VERSION 5.8 ;
BUSBITCHARS "[]" ;
DIVIDERCHAR "/" ;
UNITS
    DATABASE MICRONS 1000 ;
END UNITS

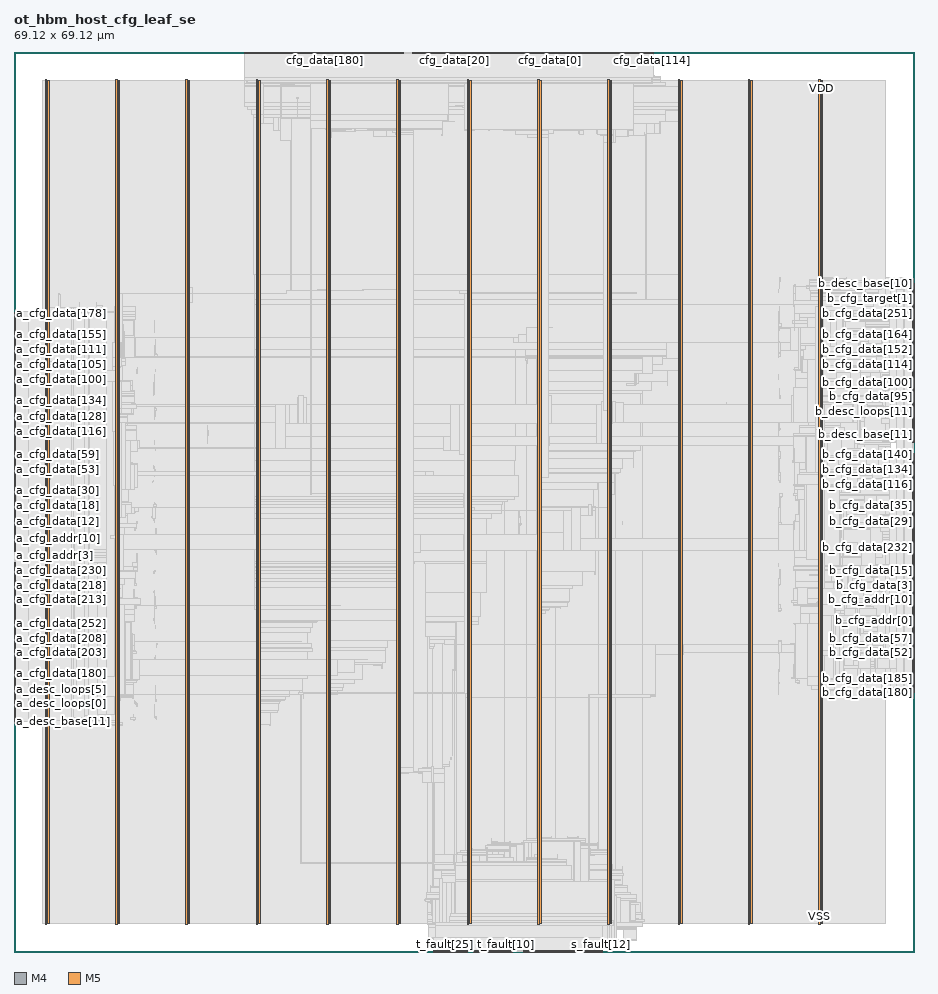
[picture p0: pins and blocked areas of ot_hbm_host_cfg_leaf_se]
MACRO ot_hbm_host_cfg_leaf_se
  FOREIGN ot_hbm_host_cfg_leaf_se 0 0 ;
  CLASS BLOCK ;
  SIZE 69.12 BY 69.12 ;
  PIN a_cfg_addr[0]
    DIRECTION OUTPUT ;
    USE SIGNAL ;
    PORT
      LAYER M4 ;
        RECT  0 30.768 0.084 30.792 ;
    END
  END a_cfg_addr[0]
  PIN a_cfg_addr[10]
    DIRECTION OUTPUT ;
    USE SIGNAL ;
    PORT
      LAYER M4 ;
        RECT  0 31.728 0.084 31.752 ;
    END
  END a_cfg_addr[10]
  PIN a_cfg_addr[11]
    DIRECTION OUTPUT ;
    USE SIGNAL ;
    PORT
      LAYER M4 ;
        RECT  0 31.824 0.084 31.848 ;
    END
  END a_cfg_addr[11]
  PIN a_cfg_addr[1]
    DIRECTION OUTPUT ;
    USE SIGNAL ;
    PORT
      LAYER M4 ;
        RECT  0 30.864 0.084 30.888 ;
    END
  END a_cfg_addr[1]
  PIN a_cfg_addr[2]
    DIRECTION OUTPUT ;
    USE SIGNAL ;
    PORT
      LAYER M4 ;
        RECT  0 30.96 0.084 30.984 ;
    END
  END a_cfg_addr[2]
  PIN a_cfg_addr[3]
    DIRECTION OUTPUT ;
    USE SIGNAL ;
    PORT
      LAYER M4 ;
        RECT  0 31.056 0.084 31.08 ;
    END
  END a_cfg_addr[3]
  PIN a_cfg_addr[4]
    DIRECTION OUTPUT ;
    USE SIGNAL ;
    PORT
      LAYER M4 ;
        RECT  0 31.152 0.084 31.176 ;
    END
  END a_cfg_addr[4]
  PIN a_cfg_addr[5]
    DIRECTION OUTPUT ;
    USE SIGNAL ;
    PORT
      LAYER M4 ;
        RECT  0 31.248 0.084 31.272 ;
    END
  END a_cfg_addr[5]
  PIN a_cfg_addr[6]
    DIRECTION OUTPUT ;
    USE SIGNAL ;
    PORT
      LAYER M4 ;
        RECT  0 31.344 0.084 31.368 ;
    END
  END a_cfg_addr[6]
  PIN a_cfg_addr[7]
    DIRECTION OUTPUT ;
    USE SIGNAL ;
    PORT
      LAYER M4 ;
        RECT  0 31.44 0.084 31.464 ;
    END
  END a_cfg_addr[7]
  PIN a_cfg_addr[8]
    DIRECTION OUTPUT ;
    USE SIGNAL ;
    PORT
      LAYER M4 ;
        RECT  0 31.536 0.084 31.56 ;
    END
  END a_cfg_addr[8]
  PIN a_cfg_addr[9]
    DIRECTION OUTPUT ;
    USE SIGNAL ;
    PORT
      LAYER M4 ;
        RECT  0 31.632 0.084 31.656 ;
    END
  END a_cfg_addr[9]
  PIN a_cfg_data[0]
    DIRECTION OUTPUT ;
    USE SIGNAL ;
    PORT
      LAYER M4 ;
        RECT  0 31.92 0.084 31.944 ;
    END
  END a_cfg_data[0]
  PIN a_cfg_data[100]
    DIRECTION OUTPUT ;
    USE SIGNAL ;
    PORT
      LAYER M4 ;
        RECT  0 44.592 0.084 44.616 ;
    END
  END a_cfg_data[100]
  PIN a_cfg_data[101]
    DIRECTION OUTPUT ;
    USE SIGNAL ;
    PORT
      LAYER M4 ;
        RECT  0 44.688 0.084 44.712 ;
    END
  END a_cfg_data[101]
  PIN a_cfg_data[102]
    DIRECTION OUTPUT ;
    USE SIGNAL ;
    PORT
      LAYER M4 ;
        RECT  0 44.784 0.084 44.808 ;
    END
  END a_cfg_data[102]
  PIN a_cfg_data[103]
    DIRECTION OUTPUT ;
    USE SIGNAL ;
    PORT
      LAYER M4 ;
        RECT  0 44.88 0.084 44.904 ;
    END
  END a_cfg_data[103]
  PIN a_cfg_data[104]
    DIRECTION OUTPUT ;
    USE SIGNAL ;
    PORT
      LAYER M4 ;
        RECT  0 44.976 0.084 45 ;
    END
  END a_cfg_data[104]
  PIN a_cfg_data[105]
    DIRECTION OUTPUT ;
    USE SIGNAL ;
    PORT
      LAYER M4 ;
        RECT  0 45.072 0.084 45.096 ;
    END
  END a_cfg_data[105]
  PIN a_cfg_data[106]
    DIRECTION OUTPUT ;
    USE SIGNAL ;
    PORT
      LAYER M4 ;
        RECT  0 45.168 0.084 45.192 ;
    END
  END a_cfg_data[106]
  PIN a_cfg_data[107]
    DIRECTION OUTPUT ;
    USE SIGNAL ;
    PORT
      LAYER M4 ;
        RECT  0 45.264 0.084 45.288 ;
    END
  END a_cfg_data[107]
  PIN a_cfg_data[108]
    DIRECTION OUTPUT ;
    USE SIGNAL ;
    PORT
      LAYER M4 ;
        RECT  0 45.36 0.084 45.384 ;
    END
  END a_cfg_data[108]
  PIN a_cfg_data[109]
    DIRECTION OUTPUT ;
    USE SIGNAL ;
    PORT
      LAYER M4 ;
        RECT  0 45.456 0.084 45.48 ;
    END
  END a_cfg_data[109]
  PIN a_cfg_data[10]
    DIRECTION OUTPUT ;
    USE SIGNAL ;
    PORT
      LAYER M4 ;
        RECT  0 32.88 0.084 32.904 ;
    END
  END a_cfg_data[10]
  PIN a_cfg_data[110]
    DIRECTION OUTPUT ;
    USE SIGNAL ;
    PORT
      LAYER M4 ;
        RECT  0 45.552 0.084 45.576 ;
    END
  END a_cfg_data[110]
  PIN a_cfg_data[111]
    DIRECTION OUTPUT ;
    USE SIGNAL ;
    PORT
      LAYER M4 ;
        RECT  0 45.648 0.084 45.672 ;
    END
  END a_cfg_data[111]
  PIN a_cfg_data[112]
    DIRECTION OUTPUT ;
    USE SIGNAL ;
    PORT
      LAYER M4 ;
        RECT  0 45.744 0.084 45.768 ;
    END
  END a_cfg_data[112]
  PIN a_cfg_data[113]
    DIRECTION OUTPUT ;
    USE SIGNAL ;
    PORT
      LAYER M4 ;
        RECT  0 45.84 0.084 45.864 ;
    END
  END a_cfg_data[113]
  PIN a_cfg_data[114]
    DIRECTION OUTPUT ;
    USE SIGNAL ;
    PORT
      LAYER M4 ;
        RECT  0 45.936 0.084 45.96 ;
    END
  END a_cfg_data[114]
  PIN a_cfg_data[115]
    DIRECTION OUTPUT ;
    USE SIGNAL ;
    PORT
      LAYER M4 ;
        RECT  0 46.032 0.084 46.056 ;
    END
  END a_cfg_data[115]
  PIN a_cfg_data[116]
    DIRECTION OUTPUT ;
    USE SIGNAL ;
    PORT
      LAYER M4 ;
        RECT  0 39.984 0.084 40.008 ;
    END
  END a_cfg_data[116]
  PIN a_cfg_data[117]
    DIRECTION OUTPUT ;
    USE SIGNAL ;
    PORT
      LAYER M4 ;
        RECT  0 40.08 0.084 40.104 ;
    END
  END a_cfg_data[117]
  PIN a_cfg_data[118]
    DIRECTION OUTPUT ;
    USE SIGNAL ;
    PORT
      LAYER M4 ;
        RECT  0 40.176 0.084 40.2 ;
    END
  END a_cfg_data[118]
  PIN a_cfg_data[119]
    DIRECTION OUTPUT ;
    USE SIGNAL ;
    PORT
      LAYER M4 ;
        RECT  0 40.272 0.084 40.296 ;
    END
  END a_cfg_data[119]
  PIN a_cfg_data[11]
    DIRECTION OUTPUT ;
    USE SIGNAL ;
    PORT
      LAYER M4 ;
        RECT  0 32.976 0.084 33 ;
    END
  END a_cfg_data[11]
  PIN a_cfg_data[120]
    DIRECTION OUTPUT ;
    USE SIGNAL ;
    PORT
      LAYER M4 ;
        RECT  0 40.368 0.084 40.392 ;
    END
  END a_cfg_data[120]
  PIN a_cfg_data[121]
    DIRECTION OUTPUT ;
    USE SIGNAL ;
    PORT
      LAYER M4 ;
        RECT  0 40.464 0.084 40.488 ;
    END
  END a_cfg_data[121]
  PIN a_cfg_data[122]
    DIRECTION OUTPUT ;
    USE SIGNAL ;
    PORT
      LAYER M4 ;
        RECT  0 40.56 0.084 40.584 ;
    END
  END a_cfg_data[122]
  PIN a_cfg_data[123]
    DIRECTION OUTPUT ;
    USE SIGNAL ;
    PORT
      LAYER M4 ;
        RECT  0 40.656 0.084 40.68 ;
    END
  END a_cfg_data[123]
  PIN a_cfg_data[124]
    DIRECTION OUTPUT ;
    USE SIGNAL ;
    PORT
      LAYER M4 ;
        RECT  0 40.752 0.084 40.776 ;
    END
  END a_cfg_data[124]
  PIN a_cfg_data[125]
    DIRECTION OUTPUT ;
    USE SIGNAL ;
    PORT
      LAYER M4 ;
        RECT  0 40.848 0.084 40.872 ;
    END
  END a_cfg_data[125]
  PIN a_cfg_data[126]
    DIRECTION OUTPUT ;
    USE SIGNAL ;
    PORT
      LAYER M4 ;
        RECT  0 40.944 0.084 40.968 ;
    END
  END a_cfg_data[126]
  PIN a_cfg_data[127]
    DIRECTION OUTPUT ;
    USE SIGNAL ;
    PORT
      LAYER M4 ;
        RECT  0 41.04 0.084 41.064 ;
    END
  END a_cfg_data[127]
  PIN a_cfg_data[128]
    DIRECTION OUTPUT ;
    USE SIGNAL ;
    PORT
      LAYER M4 ;
        RECT  0 41.136 0.084 41.16 ;
    END
  END a_cfg_data[128]
  PIN a_cfg_data[129]
    DIRECTION OUTPUT ;
    USE SIGNAL ;
    PORT
      LAYER M4 ;
        RECT  0 41.232 0.084 41.256 ;
    END
  END a_cfg_data[129]
  PIN a_cfg_data[12]
    DIRECTION OUTPUT ;
    USE SIGNAL ;
    PORT
      LAYER M4 ;
        RECT  0 33.072 0.084 33.096 ;
    END
  END a_cfg_data[12]
  PIN a_cfg_data[130]
    DIRECTION OUTPUT ;
    USE SIGNAL ;
    PORT
      LAYER M4 ;
        RECT  0 41.328 0.084 41.352 ;
    END
  END a_cfg_data[130]
  PIN a_cfg_data[131]
    DIRECTION OUTPUT ;
    USE SIGNAL ;
    PORT
      LAYER M4 ;
        RECT  0 41.424 0.084 41.448 ;
    END
  END a_cfg_data[131]
  PIN a_cfg_data[132]
    DIRECTION OUTPUT ;
    USE SIGNAL ;
    PORT
      LAYER M4 ;
        RECT  0 41.52 0.084 41.544 ;
    END
  END a_cfg_data[132]
  PIN a_cfg_data[133]
    DIRECTION OUTPUT ;
    USE SIGNAL ;
    PORT
      LAYER M4 ;
        RECT  0 41.616 0.084 41.64 ;
    END
  END a_cfg_data[133]
  PIN a_cfg_data[134]
    DIRECTION OUTPUT ;
    USE SIGNAL ;
    PORT
      LAYER M4 ;
        RECT  0 41.712 0.084 41.736 ;
    END
  END a_cfg_data[134]
  PIN a_cfg_data[135]
    DIRECTION OUTPUT ;
    USE SIGNAL ;
    PORT
      LAYER M4 ;
        RECT  0 41.808 0.084 41.832 ;
    END
  END a_cfg_data[135]
  PIN a_cfg_data[136]
    DIRECTION OUTPUT ;
    USE SIGNAL ;
    PORT
      LAYER M4 ;
        RECT  0 41.904 0.084 41.928 ;
    END
  END a_cfg_data[136]
  PIN a_cfg_data[137]
    DIRECTION OUTPUT ;
    USE SIGNAL ;
    PORT
      LAYER M4 ;
        RECT  0 42 0.084 42.024 ;
    END
  END a_cfg_data[137]
  PIN a_cfg_data[138]
    DIRECTION OUTPUT ;
    USE SIGNAL ;
    PORT
      LAYER M4 ;
        RECT  0 42.096 0.084 42.12 ;
    END
  END a_cfg_data[138]
  PIN a_cfg_data[139]
    DIRECTION OUTPUT ;
    USE SIGNAL ;
    PORT
      LAYER M4 ;
        RECT  0 42.192 0.084 42.216 ;
    END
  END a_cfg_data[139]
  PIN a_cfg_data[13]
    DIRECTION OUTPUT ;
    USE SIGNAL ;
    PORT
      LAYER M4 ;
        RECT  0 33.168 0.084 33.192 ;
    END
  END a_cfg_data[13]
  PIN a_cfg_data[140]
    DIRECTION OUTPUT ;
    USE SIGNAL ;
    PORT
      LAYER M4 ;
        RECT  0 42.288 0.084 42.312 ;
    END
  END a_cfg_data[140]
  PIN a_cfg_data[141]
    DIRECTION OUTPUT ;
    USE SIGNAL ;
    PORT
      LAYER M4 ;
        RECT  0 42.384 0.084 42.408 ;
    END
  END a_cfg_data[141]
  PIN a_cfg_data[142]
    DIRECTION OUTPUT ;
    USE SIGNAL ;
    PORT
      LAYER M4 ;
        RECT  0 42.48 0.084 42.504 ;
    END
  END a_cfg_data[142]
  PIN a_cfg_data[143]
    DIRECTION OUTPUT ;
    USE SIGNAL ;
    PORT
      LAYER M4 ;
        RECT  0 42.576 0.084 42.6 ;
    END
  END a_cfg_data[143]
  PIN a_cfg_data[144]
    DIRECTION OUTPUT ;
    USE SIGNAL ;
    PORT
      LAYER M4 ;
        RECT  0 42.672 0.084 42.696 ;
    END
  END a_cfg_data[144]
  PIN a_cfg_data[145]
    DIRECTION OUTPUT ;
    USE SIGNAL ;
    PORT
      LAYER M4 ;
        RECT  0 42.768 0.084 42.792 ;
    END
  END a_cfg_data[145]
  PIN a_cfg_data[146]
    DIRECTION OUTPUT ;
    USE SIGNAL ;
    PORT
      LAYER M4 ;
        RECT  0 42.864 0.084 42.888 ;
    END
  END a_cfg_data[146]
  PIN a_cfg_data[147]
    DIRECTION OUTPUT ;
    USE SIGNAL ;
    PORT
      LAYER M4 ;
        RECT  0 42.96 0.084 42.984 ;
    END
  END a_cfg_data[147]
  PIN a_cfg_data[148]
    DIRECTION OUTPUT ;
    USE SIGNAL ;
    PORT
      LAYER M4 ;
        RECT  0 46.128 0.084 46.152 ;
    END
  END a_cfg_data[148]
  PIN a_cfg_data[149]
    DIRECTION OUTPUT ;
    USE SIGNAL ;
    PORT
      LAYER M4 ;
        RECT  0 46.224 0.084 46.248 ;
    END
  END a_cfg_data[149]
  PIN a_cfg_data[14]
    DIRECTION OUTPUT ;
    USE SIGNAL ;
    PORT
      LAYER M4 ;
        RECT  0 33.264 0.084 33.288 ;
    END
  END a_cfg_data[14]
  PIN a_cfg_data[150]
    DIRECTION OUTPUT ;
    USE SIGNAL ;
    PORT
      LAYER M4 ;
        RECT  0 46.32 0.084 46.344 ;
    END
  END a_cfg_data[150]
  PIN a_cfg_data[151]
    DIRECTION OUTPUT ;
    USE SIGNAL ;
    PORT
      LAYER M4 ;
        RECT  0 46.416 0.084 46.44 ;
    END
  END a_cfg_data[151]
  PIN a_cfg_data[152]
    DIRECTION OUTPUT ;
    USE SIGNAL ;
    PORT
      LAYER M4 ;
        RECT  0 46.512 0.084 46.536 ;
    END
  END a_cfg_data[152]
  PIN a_cfg_data[153]
    DIRECTION OUTPUT ;
    USE SIGNAL ;
    PORT
      LAYER M4 ;
        RECT  0 46.608 0.084 46.632 ;
    END
  END a_cfg_data[153]
  PIN a_cfg_data[154]
    DIRECTION OUTPUT ;
    USE SIGNAL ;
    PORT
      LAYER M4 ;
        RECT  0 46.704 0.084 46.728 ;
    END
  END a_cfg_data[154]
  PIN a_cfg_data[155]
    DIRECTION OUTPUT ;
    USE SIGNAL ;
    PORT
      LAYER M4 ;
        RECT  0 46.8 0.084 46.824 ;
    END
  END a_cfg_data[155]
  PIN a_cfg_data[156]
    DIRECTION OUTPUT ;
    USE SIGNAL ;
    PORT
      LAYER M4 ;
        RECT  0 46.896 0.084 46.92 ;
    END
  END a_cfg_data[156]
  PIN a_cfg_data[157]
    DIRECTION OUTPUT ;
    USE SIGNAL ;
    PORT
      LAYER M4 ;
        RECT  0 46.992 0.084 47.016 ;
    END
  END a_cfg_data[157]
  PIN a_cfg_data[158]
    DIRECTION OUTPUT ;
    USE SIGNAL ;
    PORT
      LAYER M4 ;
        RECT  0 47.088 0.084 47.112 ;
    END
  END a_cfg_data[158]
  PIN a_cfg_data[159]
    DIRECTION OUTPUT ;
    USE SIGNAL ;
    PORT
      LAYER M4 ;
        RECT  0 47.184 0.084 47.208 ;
    END
  END a_cfg_data[159]
  PIN a_cfg_data[15]
    DIRECTION OUTPUT ;
    USE SIGNAL ;
    PORT
      LAYER M4 ;
        RECT  0 33.36 0.084 33.384 ;
    END
  END a_cfg_data[15]
  PIN a_cfg_data[160]
    DIRECTION OUTPUT ;
    USE SIGNAL ;
    PORT
      LAYER M4 ;
        RECT  0 47.28 0.084 47.304 ;
    END
  END a_cfg_data[160]
  PIN a_cfg_data[161]
    DIRECTION OUTPUT ;
    USE SIGNAL ;
    PORT
      LAYER M4 ;
        RECT  0 47.376 0.084 47.4 ;
    END
  END a_cfg_data[161]
  PIN a_cfg_data[162]
    DIRECTION OUTPUT ;
    USE SIGNAL ;
    PORT
      LAYER M4 ;
        RECT  0 47.472 0.084 47.496 ;
    END
  END a_cfg_data[162]
  PIN a_cfg_data[163]
    DIRECTION OUTPUT ;
    USE SIGNAL ;
    PORT
      LAYER M4 ;
        RECT  0 47.568 0.084 47.592 ;
    END
  END a_cfg_data[163]
  PIN a_cfg_data[164]
    DIRECTION OUTPUT ;
    USE SIGNAL ;
    PORT
      LAYER M4 ;
        RECT  0 47.664 0.084 47.688 ;
    END
  END a_cfg_data[164]
  PIN a_cfg_data[165]
    DIRECTION OUTPUT ;
    USE SIGNAL ;
    PORT
      LAYER M4 ;
        RECT  0 47.76 0.084 47.784 ;
    END
  END a_cfg_data[165]
  PIN a_cfg_data[166]
    DIRECTION OUTPUT ;
    USE SIGNAL ;
    PORT
      LAYER M4 ;
        RECT  0 47.856 0.084 47.88 ;
    END
  END a_cfg_data[166]
  PIN a_cfg_data[167]
    DIRECTION OUTPUT ;
    USE SIGNAL ;
    PORT
      LAYER M4 ;
        RECT  0 47.952 0.084 47.976 ;
    END
  END a_cfg_data[167]
  PIN a_cfg_data[168]
    DIRECTION OUTPUT ;
    USE SIGNAL ;
    PORT
      LAYER M4 ;
        RECT  0 48.048 0.084 48.072 ;
    END
  END a_cfg_data[168]
  PIN a_cfg_data[169]
    DIRECTION OUTPUT ;
    USE SIGNAL ;
    PORT
      LAYER M4 ;
        RECT  0 48.144 0.084 48.168 ;
    END
  END a_cfg_data[169]
  PIN a_cfg_data[16]
    DIRECTION OUTPUT ;
    USE SIGNAL ;
    PORT
      LAYER M4 ;
        RECT  0 33.456 0.084 33.48 ;
    END
  END a_cfg_data[16]
  PIN a_cfg_data[170]
    DIRECTION OUTPUT ;
    USE SIGNAL ;
    PORT
      LAYER M4 ;
        RECT  0 48.24 0.084 48.264 ;
    END
  END a_cfg_data[170]
  PIN a_cfg_data[171]
    DIRECTION OUTPUT ;
    USE SIGNAL ;
    PORT
      LAYER M4 ;
        RECT  0 48.336 0.084 48.36 ;
    END
  END a_cfg_data[171]
  PIN a_cfg_data[172]
    DIRECTION OUTPUT ;
    USE SIGNAL ;
    PORT
      LAYER M4 ;
        RECT  0 48.432 0.084 48.456 ;
    END
  END a_cfg_data[172]
  PIN a_cfg_data[173]
    DIRECTION OUTPUT ;
    USE SIGNAL ;
    PORT
      LAYER M4 ;
        RECT  0 48.528 0.084 48.552 ;
    END
  END a_cfg_data[173]
  PIN a_cfg_data[174]
    DIRECTION OUTPUT ;
    USE SIGNAL ;
    PORT
      LAYER M4 ;
        RECT  0 48.624 0.084 48.648 ;
    END
  END a_cfg_data[174]
  PIN a_cfg_data[175]
    DIRECTION OUTPUT ;
    USE SIGNAL ;
    PORT
      LAYER M4 ;
        RECT  0 48.72 0.084 48.744 ;
    END
  END a_cfg_data[175]
  PIN a_cfg_data[176]
    DIRECTION OUTPUT ;
    USE SIGNAL ;
    PORT
      LAYER M4 ;
        RECT  0 48.816 0.084 48.84 ;
    END
  END a_cfg_data[176]
  PIN a_cfg_data[177]
    DIRECTION OUTPUT ;
    USE SIGNAL ;
    PORT
      LAYER M4 ;
        RECT  0 48.912 0.084 48.936 ;
    END
  END a_cfg_data[177]
  PIN a_cfg_data[178]
    DIRECTION OUTPUT ;
    USE SIGNAL ;
    PORT
      LAYER M4 ;
        RECT  0 49.008 0.084 49.032 ;
    END
  END a_cfg_data[178]
  PIN a_cfg_data[179]
    DIRECTION OUTPUT ;
    USE SIGNAL ;
    PORT
      LAYER M4 ;
        RECT  0 49.104 0.084 49.128 ;
    END
  END a_cfg_data[179]
  PIN a_cfg_data[17]
    DIRECTION OUTPUT ;
    USE SIGNAL ;
    PORT
      LAYER M4 ;
        RECT  0 33.552 0.084 33.576 ;
    END
  END a_cfg_data[17]
  PIN a_cfg_data[180]
    DIRECTION OUTPUT ;
    USE SIGNAL ;
    PORT
      LAYER M4 ;
        RECT  0 20.784 0.084 20.808 ;
    END
  END a_cfg_data[180]
  PIN a_cfg_data[181]
    DIRECTION OUTPUT ;
    USE SIGNAL ;
    PORT
      LAYER M4 ;
        RECT  0 20.88 0.084 20.904 ;
    END
  END a_cfg_data[181]
  PIN a_cfg_data[182]
    DIRECTION OUTPUT ;
    USE SIGNAL ;
    PORT
      LAYER M4 ;
        RECT  0 20.976 0.084 21 ;
    END
  END a_cfg_data[182]
  PIN a_cfg_data[183]
    DIRECTION OUTPUT ;
    USE SIGNAL ;
    PORT
      LAYER M4 ;
        RECT  0 21.072 0.084 21.096 ;
    END
  END a_cfg_data[183]
  PIN a_cfg_data[184]
    DIRECTION OUTPUT ;
    USE SIGNAL ;
    PORT
      LAYER M4 ;
        RECT  0 21.168 0.084 21.192 ;
    END
  END a_cfg_data[184]
  PIN a_cfg_data[185]
    DIRECTION OUTPUT ;
    USE SIGNAL ;
    PORT
      LAYER M4 ;
        RECT  0 21.264 0.084 21.288 ;
    END
  END a_cfg_data[185]
  PIN a_cfg_data[186]
    DIRECTION OUTPUT ;
    USE SIGNAL ;
    PORT
      LAYER M4 ;
        RECT  0 21.36 0.084 21.384 ;
    END
  END a_cfg_data[186]
  PIN a_cfg_data[187]
    DIRECTION OUTPUT ;
    USE SIGNAL ;
    PORT
      LAYER M4 ;
        RECT  0 21.456 0.084 21.48 ;
    END
  END a_cfg_data[187]
  PIN a_cfg_data[188]
    DIRECTION OUTPUT ;
    USE SIGNAL ;
    PORT
      LAYER M4 ;
        RECT  0 21.552 0.084 21.576 ;
    END
  END a_cfg_data[188]
  PIN a_cfg_data[189]
    DIRECTION OUTPUT ;
    USE SIGNAL ;
    PORT
      LAYER M4 ;
        RECT  0 21.648 0.084 21.672 ;
    END
  END a_cfg_data[189]
  PIN a_cfg_data[18]
    DIRECTION OUTPUT ;
    USE SIGNAL ;
    PORT
      LAYER M4 ;
        RECT  0 33.648 0.084 33.672 ;
    END
  END a_cfg_data[18]
  PIN a_cfg_data[190]
    DIRECTION OUTPUT ;
    USE SIGNAL ;
    PORT
      LAYER M4 ;
        RECT  0 21.744 0.084 21.768 ;
    END
  END a_cfg_data[190]
  PIN a_cfg_data[191]
    DIRECTION OUTPUT ;
    USE SIGNAL ;
    PORT
      LAYER M4 ;
        RECT  0 21.84 0.084 21.864 ;
    END
  END a_cfg_data[191]
  PIN a_cfg_data[192]
    DIRECTION OUTPUT ;
    USE SIGNAL ;
    PORT
      LAYER M4 ;
        RECT  0 21.936 0.084 21.96 ;
    END
  END a_cfg_data[192]
  PIN a_cfg_data[193]
    DIRECTION OUTPUT ;
    USE SIGNAL ;
    PORT
      LAYER M4 ;
        RECT  0 22.032 0.084 22.056 ;
    END
  END a_cfg_data[193]
  PIN a_cfg_data[194]
    DIRECTION OUTPUT ;
    USE SIGNAL ;
    PORT
      LAYER M4 ;
        RECT  0 22.128 0.084 22.152 ;
    END
  END a_cfg_data[194]
  PIN a_cfg_data[195]
    DIRECTION OUTPUT ;
    USE SIGNAL ;
    PORT
      LAYER M4 ;
        RECT  0 22.224 0.084 22.248 ;
    END
  END a_cfg_data[195]
  PIN a_cfg_data[196]
    DIRECTION OUTPUT ;
    USE SIGNAL ;
    PORT
      LAYER M4 ;
        RECT  0 22.32 0.084 22.344 ;
    END
  END a_cfg_data[196]
  PIN a_cfg_data[197]
    DIRECTION OUTPUT ;
    USE SIGNAL ;
    PORT
      LAYER M4 ;
        RECT  0 22.416 0.084 22.44 ;
    END
  END a_cfg_data[197]
  PIN a_cfg_data[198]
    DIRECTION OUTPUT ;
    USE SIGNAL ;
    PORT
      LAYER M4 ;
        RECT  0 22.512 0.084 22.536 ;
    END
  END a_cfg_data[198]
  PIN a_cfg_data[199]
    DIRECTION OUTPUT ;
    USE SIGNAL ;
    PORT
      LAYER M4 ;
        RECT  0 22.608 0.084 22.632 ;
    END
  END a_cfg_data[199]
  PIN a_cfg_data[19]
    DIRECTION OUTPUT ;
    USE SIGNAL ;
    PORT
      LAYER M4 ;
        RECT  0 33.744 0.084 33.768 ;
    END
  END a_cfg_data[19]
  PIN a_cfg_data[1]
    DIRECTION OUTPUT ;
    USE SIGNAL ;
    PORT
      LAYER M4 ;
        RECT  0 32.016 0.084 32.04 ;
    END
  END a_cfg_data[1]
  PIN a_cfg_data[200]
    DIRECTION OUTPUT ;
    USE SIGNAL ;
    PORT
      LAYER M4 ;
        RECT  0 22.704 0.084 22.728 ;
    END
  END a_cfg_data[200]
  PIN a_cfg_data[201]
    DIRECTION OUTPUT ;
    USE SIGNAL ;
    PORT
      LAYER M4 ;
        RECT  0 22.8 0.084 22.824 ;
    END
  END a_cfg_data[201]
  PIN a_cfg_data[202]
    DIRECTION OUTPUT ;
    USE SIGNAL ;
    PORT
      LAYER M4 ;
        RECT  0 22.896 0.084 22.92 ;
    END
  END a_cfg_data[202]
  PIN a_cfg_data[203]
    DIRECTION OUTPUT ;
    USE SIGNAL ;
    PORT
      LAYER M4 ;
        RECT  0 22.992 0.084 23.016 ;
    END
  END a_cfg_data[203]
  PIN a_cfg_data[204]
    DIRECTION OUTPUT ;
    USE SIGNAL ;
    PORT
      LAYER M4 ;
        RECT  0 23.088 0.084 23.112 ;
    END
  END a_cfg_data[204]
  PIN a_cfg_data[205]
    DIRECTION OUTPUT ;
    USE SIGNAL ;
    PORT
      LAYER M4 ;
        RECT  0 23.184 0.084 23.208 ;
    END
  END a_cfg_data[205]
  PIN a_cfg_data[206]
    DIRECTION OUTPUT ;
    USE SIGNAL ;
    PORT
      LAYER M4 ;
        RECT  0 23.28 0.084 23.304 ;
    END
  END a_cfg_data[206]
  PIN a_cfg_data[207]
    DIRECTION OUTPUT ;
    USE SIGNAL ;
    PORT
      LAYER M4 ;
        RECT  0 23.376 0.084 23.4 ;
    END
  END a_cfg_data[207]
  PIN a_cfg_data[208]
    DIRECTION OUTPUT ;
    USE SIGNAL ;
    PORT
      LAYER M4 ;
        RECT  0 23.472 0.084 23.496 ;
    END
  END a_cfg_data[208]
  PIN a_cfg_data[209]
    DIRECTION OUTPUT ;
    USE SIGNAL ;
    PORT
      LAYER M4 ;
        RECT  0 23.568 0.084 23.592 ;
    END
  END a_cfg_data[209]
  PIN a_cfg_data[20]
    DIRECTION OUTPUT ;
    USE SIGNAL ;
    PORT
      LAYER M4 ;
        RECT  0 33.84 0.084 33.864 ;
    END
  END a_cfg_data[20]
  PIN a_cfg_data[210]
    DIRECTION OUTPUT ;
    USE SIGNAL ;
    PORT
      LAYER M4 ;
        RECT  0 23.664 0.084 23.688 ;
    END
  END a_cfg_data[210]
  PIN a_cfg_data[211]
    DIRECTION OUTPUT ;
    USE SIGNAL ;
    PORT
      LAYER M4 ;
        RECT  0 23.76 0.084 23.784 ;
    END
  END a_cfg_data[211]
  PIN a_cfg_data[212]
    DIRECTION OUTPUT ;
    USE SIGNAL ;
    PORT
      LAYER M4 ;
        RECT  0 26.928 0.084 26.952 ;
    END
  END a_cfg_data[212]
  PIN a_cfg_data[213]
    DIRECTION OUTPUT ;
    USE SIGNAL ;
    PORT
      LAYER M4 ;
        RECT  0 27.024 0.084 27.048 ;
    END
  END a_cfg_data[213]
  PIN a_cfg_data[214]
    DIRECTION OUTPUT ;
    USE SIGNAL ;
    PORT
      LAYER M4 ;
        RECT  0 27.12 0.084 27.144 ;
    END
  END a_cfg_data[214]
  PIN a_cfg_data[215]
    DIRECTION OUTPUT ;
    USE SIGNAL ;
    PORT
      LAYER M4 ;
        RECT  0 27.216 0.084 27.24 ;
    END
  END a_cfg_data[215]
  PIN a_cfg_data[216]
    DIRECTION OUTPUT ;
    USE SIGNAL ;
    PORT
      LAYER M4 ;
        RECT  0 27.312 0.084 27.336 ;
    END
  END a_cfg_data[216]
  PIN a_cfg_data[217]
    DIRECTION OUTPUT ;
    USE SIGNAL ;
    PORT
      LAYER M4 ;
        RECT  0 27.408 0.084 27.432 ;
    END
  END a_cfg_data[217]
  PIN a_cfg_data[218]
    DIRECTION OUTPUT ;
    USE SIGNAL ;
    PORT
      LAYER M4 ;
        RECT  0 27.504 0.084 27.528 ;
    END
  END a_cfg_data[218]
  PIN a_cfg_data[219]
    DIRECTION OUTPUT ;
    USE SIGNAL ;
    PORT
      LAYER M4 ;
        RECT  0 27.6 0.084 27.624 ;
    END
  END a_cfg_data[219]
  PIN a_cfg_data[21]
    DIRECTION OUTPUT ;
    USE SIGNAL ;
    PORT
      LAYER M4 ;
        RECT  0 33.936 0.084 33.96 ;
    END
  END a_cfg_data[21]
  PIN a_cfg_data[220]
    DIRECTION OUTPUT ;
    USE SIGNAL ;
    PORT
      LAYER M4 ;
        RECT  0 27.696 0.084 27.72 ;
    END
  END a_cfg_data[220]
  PIN a_cfg_data[221]
    DIRECTION OUTPUT ;
    USE SIGNAL ;
    PORT
      LAYER M4 ;
        RECT  0 27.792 0.084 27.816 ;
    END
  END a_cfg_data[221]
  PIN a_cfg_data[222]
    DIRECTION OUTPUT ;
    USE SIGNAL ;
    PORT
      LAYER M4 ;
        RECT  0 27.888 0.084 27.912 ;
    END
  END a_cfg_data[222]
  PIN a_cfg_data[223]
    DIRECTION OUTPUT ;
    USE SIGNAL ;
    PORT
      LAYER M4 ;
        RECT  0 27.984 0.084 28.008 ;
    END
  END a_cfg_data[223]
  PIN a_cfg_data[224]
    DIRECTION OUTPUT ;
    USE SIGNAL ;
    PORT
      LAYER M4 ;
        RECT  0 28.08 0.084 28.104 ;
    END
  END a_cfg_data[224]
  PIN a_cfg_data[225]
    DIRECTION OUTPUT ;
    USE SIGNAL ;
    PORT
      LAYER M4 ;
        RECT  0 28.176 0.084 28.2 ;
    END
  END a_cfg_data[225]
  PIN a_cfg_data[226]
    DIRECTION OUTPUT ;
    USE SIGNAL ;
    PORT
      LAYER M4 ;
        RECT  0 28.272 0.084 28.296 ;
    END
  END a_cfg_data[226]
  PIN a_cfg_data[227]
    DIRECTION OUTPUT ;
    USE SIGNAL ;
    PORT
      LAYER M4 ;
        RECT  0 28.368 0.084 28.392 ;
    END
  END a_cfg_data[227]
  PIN a_cfg_data[228]
    DIRECTION OUTPUT ;
    USE SIGNAL ;
    PORT
      LAYER M4 ;
        RECT  0 28.464 0.084 28.488 ;
    END
  END a_cfg_data[228]
  PIN a_cfg_data[229]
    DIRECTION OUTPUT ;
    USE SIGNAL ;
    PORT
      LAYER M4 ;
        RECT  0 28.56 0.084 28.584 ;
    END
  END a_cfg_data[229]
  PIN a_cfg_data[22]
    DIRECTION OUTPUT ;
    USE SIGNAL ;
    PORT
      LAYER M4 ;
        RECT  0 34.032 0.084 34.056 ;
    END
  END a_cfg_data[22]
  PIN a_cfg_data[230]
    DIRECTION OUTPUT ;
    USE SIGNAL ;
    PORT
      LAYER M4 ;
        RECT  0 28.656 0.084 28.68 ;
    END
  END a_cfg_data[230]
  PIN a_cfg_data[231]
    DIRECTION OUTPUT ;
    USE SIGNAL ;
    PORT
      LAYER M4 ;
        RECT  0 28.752 0.084 28.776 ;
    END
  END a_cfg_data[231]
  PIN a_cfg_data[232]
    DIRECTION OUTPUT ;
    USE SIGNAL ;
    PORT
      LAYER M4 ;
        RECT  0 28.848 0.084 28.872 ;
    END
  END a_cfg_data[232]
  PIN a_cfg_data[233]
    DIRECTION OUTPUT ;
    USE SIGNAL ;
    PORT
      LAYER M4 ;
        RECT  0 28.944 0.084 28.968 ;
    END
  END a_cfg_data[233]
  PIN a_cfg_data[234]
    DIRECTION OUTPUT ;
    USE SIGNAL ;
    PORT
      LAYER M4 ;
        RECT  0 29.04 0.084 29.064 ;
    END
  END a_cfg_data[234]
  PIN a_cfg_data[235]
    DIRECTION OUTPUT ;
    USE SIGNAL ;
    PORT
      LAYER M4 ;
        RECT  0 29.136 0.084 29.16 ;
    END
  END a_cfg_data[235]
  PIN a_cfg_data[236]
    DIRECTION OUTPUT ;
    USE SIGNAL ;
    PORT
      LAYER M4 ;
        RECT  0 29.232 0.084 29.256 ;
    END
  END a_cfg_data[236]
  PIN a_cfg_data[237]
    DIRECTION OUTPUT ;
    USE SIGNAL ;
    PORT
      LAYER M4 ;
        RECT  0 29.328 0.084 29.352 ;
    END
  END a_cfg_data[237]
  PIN a_cfg_data[238]
    DIRECTION OUTPUT ;
    USE SIGNAL ;
    PORT
      LAYER M4 ;
        RECT  0 29.424 0.084 29.448 ;
    END
  END a_cfg_data[238]
  PIN a_cfg_data[239]
    DIRECTION OUTPUT ;
    USE SIGNAL ;
    PORT
      LAYER M4 ;
        RECT  0 29.52 0.084 29.544 ;
    END
  END a_cfg_data[239]
  PIN a_cfg_data[23]
    DIRECTION OUTPUT ;
    USE SIGNAL ;
    PORT
      LAYER M4 ;
        RECT  0 34.128 0.084 34.152 ;
    END
  END a_cfg_data[23]
  PIN a_cfg_data[240]
    DIRECTION OUTPUT ;
    USE SIGNAL ;
    PORT
      LAYER M4 ;
        RECT  0 29.616 0.084 29.64 ;
    END
  END a_cfg_data[240]
  PIN a_cfg_data[241]
    DIRECTION OUTPUT ;
    USE SIGNAL ;
    PORT
      LAYER M4 ;
        RECT  0 29.712 0.084 29.736 ;
    END
  END a_cfg_data[241]
  PIN a_cfg_data[242]
    DIRECTION OUTPUT ;
    USE SIGNAL ;
    PORT
      LAYER M4 ;
        RECT  0 29.808 0.084 29.832 ;
    END
  END a_cfg_data[242]
  PIN a_cfg_data[243]
    DIRECTION OUTPUT ;
    USE SIGNAL ;
    PORT
      LAYER M4 ;
        RECT  0 29.904 0.084 29.928 ;
    END
  END a_cfg_data[243]
  PIN a_cfg_data[244]
    DIRECTION OUTPUT ;
    USE SIGNAL ;
    PORT
      LAYER M4 ;
        RECT  0 23.856 0.084 23.88 ;
    END
  END a_cfg_data[244]
  PIN a_cfg_data[245]
    DIRECTION OUTPUT ;
    USE SIGNAL ;
    PORT
      LAYER M4 ;
        RECT  0 23.952 0.084 23.976 ;
    END
  END a_cfg_data[245]
  PIN a_cfg_data[246]
    DIRECTION OUTPUT ;
    USE SIGNAL ;
    PORT
      LAYER M4 ;
        RECT  0 24.048 0.084 24.072 ;
    END
  END a_cfg_data[246]
  PIN a_cfg_data[247]
    DIRECTION OUTPUT ;
    USE SIGNAL ;
    PORT
      LAYER M4 ;
        RECT  0 24.144 0.084 24.168 ;
    END
  END a_cfg_data[247]
  PIN a_cfg_data[248]
    DIRECTION OUTPUT ;
    USE SIGNAL ;
    PORT
      LAYER M4 ;
        RECT  0 24.24 0.084 24.264 ;
    END
  END a_cfg_data[248]
  PIN a_cfg_data[249]
    DIRECTION OUTPUT ;
    USE SIGNAL ;
    PORT
      LAYER M4 ;
        RECT  0 24.336 0.084 24.36 ;
    END
  END a_cfg_data[249]
  PIN a_cfg_data[24]
    DIRECTION OUTPUT ;
    USE SIGNAL ;
    PORT
      LAYER M4 ;
        RECT  0 34.224 0.084 34.248 ;
    END
  END a_cfg_data[24]
  PIN a_cfg_data[250]
    DIRECTION OUTPUT ;
    USE SIGNAL ;
    PORT
      LAYER M4 ;
        RECT  0 24.432 0.084 24.456 ;
    END
  END a_cfg_data[250]
  PIN a_cfg_data[251]
    DIRECTION OUTPUT ;
    USE SIGNAL ;
    PORT
      LAYER M4 ;
        RECT  0 24.528 0.084 24.552 ;
    END
  END a_cfg_data[251]
  PIN a_cfg_data[252]
    DIRECTION OUTPUT ;
    USE SIGNAL ;
    PORT
      LAYER M4 ;
        RECT  0 24.624 0.084 24.648 ;
    END
  END a_cfg_data[252]
  PIN a_cfg_data[253]
    DIRECTION OUTPUT ;
    USE SIGNAL ;
    PORT
      LAYER M4 ;
        RECT  0 24.72 0.084 24.744 ;
    END
  END a_cfg_data[253]
  PIN a_cfg_data[254]
    DIRECTION OUTPUT ;
    USE SIGNAL ;
    PORT
      LAYER M4 ;
        RECT  0 24.816 0.084 24.84 ;
    END
  END a_cfg_data[254]
  PIN a_cfg_data[255]
    DIRECTION OUTPUT ;
    USE SIGNAL ;
    PORT
      LAYER M4 ;
        RECT  0 24.912 0.084 24.936 ;
    END
  END a_cfg_data[255]
  PIN a_cfg_data[25]
    DIRECTION OUTPUT ;
    USE SIGNAL ;
    PORT
      LAYER M4 ;
        RECT  0 34.32 0.084 34.344 ;
    END
  END a_cfg_data[25]
  PIN a_cfg_data[26]
    DIRECTION OUTPUT ;
    USE SIGNAL ;
    PORT
      LAYER M4 ;
        RECT  0 34.416 0.084 34.44 ;
    END
  END a_cfg_data[26]
  PIN a_cfg_data[27]
    DIRECTION OUTPUT ;
    USE SIGNAL ;
    PORT
      LAYER M4 ;
        RECT  0 34.512 0.084 34.536 ;
    END
  END a_cfg_data[27]
  PIN a_cfg_data[28]
    DIRECTION OUTPUT ;
    USE SIGNAL ;
    PORT
      LAYER M4 ;
        RECT  0 34.608 0.084 34.632 ;
    END
  END a_cfg_data[28]
  PIN a_cfg_data[29]
    DIRECTION OUTPUT ;
    USE SIGNAL ;
    PORT
      LAYER M4 ;
        RECT  0 34.704 0.084 34.728 ;
    END
  END a_cfg_data[29]
  PIN a_cfg_data[2]
    DIRECTION OUTPUT ;
    USE SIGNAL ;
    PORT
      LAYER M4 ;
        RECT  0 32.112 0.084 32.136 ;
    END
  END a_cfg_data[2]
  PIN a_cfg_data[30]
    DIRECTION OUTPUT ;
    USE SIGNAL ;
    PORT
      LAYER M4 ;
        RECT  0 34.8 0.084 34.824 ;
    END
  END a_cfg_data[30]
  PIN a_cfg_data[31]
    DIRECTION OUTPUT ;
    USE SIGNAL ;
    PORT
      LAYER M4 ;
        RECT  0 34.896 0.084 34.92 ;
    END
  END a_cfg_data[31]
  PIN a_cfg_data[32]
    DIRECTION OUTPUT ;
    USE SIGNAL ;
    PORT
      LAYER M4 ;
        RECT  0 34.992 0.084 35.016 ;
    END
  END a_cfg_data[32]
  PIN a_cfg_data[33]
    DIRECTION OUTPUT ;
    USE SIGNAL ;
    PORT
      LAYER M4 ;
        RECT  0 35.088 0.084 35.112 ;
    END
  END a_cfg_data[33]
  PIN a_cfg_data[34]
    DIRECTION OUTPUT ;
    USE SIGNAL ;
    PORT
      LAYER M4 ;
        RECT  0 35.184 0.084 35.208 ;
    END
  END a_cfg_data[34]
  PIN a_cfg_data[35]
    DIRECTION OUTPUT ;
    USE SIGNAL ;
    PORT
      LAYER M4 ;
        RECT  0 35.28 0.084 35.304 ;
    END
  END a_cfg_data[35]
  PIN a_cfg_data[36]
    DIRECTION OUTPUT ;
    USE SIGNAL ;
    PORT
      LAYER M4 ;
        RECT  0 35.376 0.084 35.4 ;
    END
  END a_cfg_data[36]
  PIN a_cfg_data[37]
    DIRECTION OUTPUT ;
    USE SIGNAL ;
    PORT
      LAYER M4 ;
        RECT  0 35.472 0.084 35.496 ;
    END
  END a_cfg_data[37]
  PIN a_cfg_data[38]
    DIRECTION OUTPUT ;
    USE SIGNAL ;
    PORT
      LAYER M4 ;
        RECT  0 35.568 0.084 35.592 ;
    END
  END a_cfg_data[38]
  PIN a_cfg_data[39]
    DIRECTION OUTPUT ;
    USE SIGNAL ;
    PORT
      LAYER M4 ;
        RECT  0 35.664 0.084 35.688 ;
    END
  END a_cfg_data[39]
  PIN a_cfg_data[3]
    DIRECTION OUTPUT ;
    USE SIGNAL ;
    PORT
      LAYER M4 ;
        RECT  0 32.208 0.084 32.232 ;
    END
  END a_cfg_data[3]
  PIN a_cfg_data[40]
    DIRECTION OUTPUT ;
    USE SIGNAL ;
    PORT
      LAYER M4 ;
        RECT  0 35.76 0.084 35.784 ;
    END
  END a_cfg_data[40]
  PIN a_cfg_data[41]
    DIRECTION OUTPUT ;
    USE SIGNAL ;
    PORT
      LAYER M4 ;
        RECT  0 35.856 0.084 35.88 ;
    END
  END a_cfg_data[41]
  PIN a_cfg_data[42]
    DIRECTION OUTPUT ;
    USE SIGNAL ;
    PORT
      LAYER M4 ;
        RECT  0 35.952 0.084 35.976 ;
    END
  END a_cfg_data[42]
  PIN a_cfg_data[43]
    DIRECTION OUTPUT ;
    USE SIGNAL ;
    PORT
      LAYER M4 ;
        RECT  0 36.048 0.084 36.072 ;
    END
  END a_cfg_data[43]
  PIN a_cfg_data[44]
    DIRECTION OUTPUT ;
    USE SIGNAL ;
    PORT
      LAYER M4 ;
        RECT  0 36.144 0.084 36.168 ;
    END
  END a_cfg_data[44]
  PIN a_cfg_data[45]
    DIRECTION OUTPUT ;
    USE SIGNAL ;
    PORT
      LAYER M4 ;
        RECT  0 36.24 0.084 36.264 ;
    END
  END a_cfg_data[45]
  PIN a_cfg_data[46]
    DIRECTION OUTPUT ;
    USE SIGNAL ;
    PORT
      LAYER M4 ;
        RECT  0 36.336 0.084 36.36 ;
    END
  END a_cfg_data[46]
  PIN a_cfg_data[47]
    DIRECTION OUTPUT ;
    USE SIGNAL ;
    PORT
      LAYER M4 ;
        RECT  0 36.432 0.084 36.456 ;
    END
  END a_cfg_data[47]
  PIN a_cfg_data[48]
    DIRECTION OUTPUT ;
    USE SIGNAL ;
    PORT
      LAYER M4 ;
        RECT  0 36.528 0.084 36.552 ;
    END
  END a_cfg_data[48]
  PIN a_cfg_data[49]
    DIRECTION OUTPUT ;
    USE SIGNAL ;
    PORT
      LAYER M4 ;
        RECT  0 36.624 0.084 36.648 ;
    END
  END a_cfg_data[49]
  PIN a_cfg_data[4]
    DIRECTION OUTPUT ;
    USE SIGNAL ;
    PORT
      LAYER M4 ;
        RECT  0 32.304 0.084 32.328 ;
    END
  END a_cfg_data[4]
  PIN a_cfg_data[50]
    DIRECTION OUTPUT ;
    USE SIGNAL ;
    PORT
      LAYER M4 ;
        RECT  0 36.72 0.084 36.744 ;
    END
  END a_cfg_data[50]
  PIN a_cfg_data[51]
    DIRECTION OUTPUT ;
    USE SIGNAL ;
    PORT
      LAYER M4 ;
        RECT  0 36.816 0.084 36.84 ;
    END
  END a_cfg_data[51]
  PIN a_cfg_data[52]
    DIRECTION OUTPUT ;
    USE SIGNAL ;
    PORT
      LAYER M4 ;
        RECT  0 36.912 0.084 36.936 ;
    END
  END a_cfg_data[52]
  PIN a_cfg_data[53]
    DIRECTION OUTPUT ;
    USE SIGNAL ;
    PORT
      LAYER M4 ;
        RECT  0 37.008 0.084 37.032 ;
    END
  END a_cfg_data[53]
  PIN a_cfg_data[54]
    DIRECTION OUTPUT ;
    USE SIGNAL ;
    PORT
      LAYER M4 ;
        RECT  0 37.104 0.084 37.128 ;
    END
  END a_cfg_data[54]
  PIN a_cfg_data[55]
    DIRECTION OUTPUT ;
    USE SIGNAL ;
    PORT
      LAYER M4 ;
        RECT  0 37.2 0.084 37.224 ;
    END
  END a_cfg_data[55]
  PIN a_cfg_data[56]
    DIRECTION OUTPUT ;
    USE SIGNAL ;
    PORT
      LAYER M4 ;
        RECT  0 37.296 0.084 37.32 ;
    END
  END a_cfg_data[56]
  PIN a_cfg_data[57]
    DIRECTION OUTPUT ;
    USE SIGNAL ;
    PORT
      LAYER M4 ;
        RECT  0 37.392 0.084 37.416 ;
    END
  END a_cfg_data[57]
  PIN a_cfg_data[58]
    DIRECTION OUTPUT ;
    USE SIGNAL ;
    PORT
      LAYER M4 ;
        RECT  0 37.488 0.084 37.512 ;
    END
  END a_cfg_data[58]
  PIN a_cfg_data[59]
    DIRECTION OUTPUT ;
    USE SIGNAL ;
    PORT
      LAYER M4 ;
        RECT  0 37.584 0.084 37.608 ;
    END
  END a_cfg_data[59]
  PIN a_cfg_data[5]
    DIRECTION OUTPUT ;
    USE SIGNAL ;
    PORT
      LAYER M4 ;
        RECT  0 32.4 0.084 32.424 ;
    END
  END a_cfg_data[5]
  PIN a_cfg_data[60]
    DIRECTION OUTPUT ;
    USE SIGNAL ;
    PORT
      LAYER M4 ;
        RECT  0 37.68 0.084 37.704 ;
    END
  END a_cfg_data[60]
  PIN a_cfg_data[61]
    DIRECTION OUTPUT ;
    USE SIGNAL ;
    PORT
      LAYER M4 ;
        RECT  0 37.776 0.084 37.8 ;
    END
  END a_cfg_data[61]
  PIN a_cfg_data[62]
    DIRECTION OUTPUT ;
    USE SIGNAL ;
    PORT
      LAYER M4 ;
        RECT  0 37.872 0.084 37.896 ;
    END
  END a_cfg_data[62]
  PIN a_cfg_data[63]
    DIRECTION OUTPUT ;
    USE SIGNAL ;
    PORT
      LAYER M4 ;
        RECT  0 37.968 0.084 37.992 ;
    END
  END a_cfg_data[63]
  PIN a_cfg_data[64]
    DIRECTION OUTPUT ;
    USE SIGNAL ;
    PORT
      LAYER M4 ;
        RECT  0 38.064 0.084 38.088 ;
    END
  END a_cfg_data[64]
  PIN a_cfg_data[65]
    DIRECTION OUTPUT ;
    USE SIGNAL ;
    PORT
      LAYER M4 ;
        RECT  0 38.16 0.084 38.184 ;
    END
  END a_cfg_data[65]
  PIN a_cfg_data[66]
    DIRECTION OUTPUT ;
    USE SIGNAL ;
    PORT
      LAYER M4 ;
        RECT  0 38.256 0.084 38.28 ;
    END
  END a_cfg_data[66]
  PIN a_cfg_data[67]
    DIRECTION OUTPUT ;
    USE SIGNAL ;
    PORT
      LAYER M4 ;
        RECT  0 38.352 0.084 38.376 ;
    END
  END a_cfg_data[67]
  PIN a_cfg_data[68]
    DIRECTION OUTPUT ;
    USE SIGNAL ;
    PORT
      LAYER M4 ;
        RECT  0 38.448 0.084 38.472 ;
    END
  END a_cfg_data[68]
  PIN a_cfg_data[69]
    DIRECTION OUTPUT ;
    USE SIGNAL ;
    PORT
      LAYER M4 ;
        RECT  0 38.544 0.084 38.568 ;
    END
  END a_cfg_data[69]
  PIN a_cfg_data[6]
    DIRECTION OUTPUT ;
    USE SIGNAL ;
    PORT
      LAYER M4 ;
        RECT  0 32.496 0.084 32.52 ;
    END
  END a_cfg_data[6]
  PIN a_cfg_data[70]
    DIRECTION OUTPUT ;
    USE SIGNAL ;
    PORT
      LAYER M4 ;
        RECT  0 38.64 0.084 38.664 ;
    END
  END a_cfg_data[70]
  PIN a_cfg_data[71]
    DIRECTION OUTPUT ;
    USE SIGNAL ;
    PORT
      LAYER M4 ;
        RECT  0 38.736 0.084 38.76 ;
    END
  END a_cfg_data[71]
  PIN a_cfg_data[72]
    DIRECTION OUTPUT ;
    USE SIGNAL ;
    PORT
      LAYER M4 ;
        RECT  0 38.832 0.084 38.856 ;
    END
  END a_cfg_data[72]
  PIN a_cfg_data[73]
    DIRECTION OUTPUT ;
    USE SIGNAL ;
    PORT
      LAYER M4 ;
        RECT  0 38.928 0.084 38.952 ;
    END
  END a_cfg_data[73]
  PIN a_cfg_data[74]
    DIRECTION OUTPUT ;
    USE SIGNAL ;
    PORT
      LAYER M4 ;
        RECT  0 39.024 0.084 39.048 ;
    END
  END a_cfg_data[74]
  PIN a_cfg_data[75]
    DIRECTION OUTPUT ;
    USE SIGNAL ;
    PORT
      LAYER M4 ;
        RECT  0 39.12 0.084 39.144 ;
    END
  END a_cfg_data[75]
  PIN a_cfg_data[76]
    DIRECTION OUTPUT ;
    USE SIGNAL ;
    PORT
      LAYER M4 ;
        RECT  0 39.216 0.084 39.24 ;
    END
  END a_cfg_data[76]
  PIN a_cfg_data[77]
    DIRECTION OUTPUT ;
    USE SIGNAL ;
    PORT
      LAYER M4 ;
        RECT  0 39.312 0.084 39.336 ;
    END
  END a_cfg_data[77]
  PIN a_cfg_data[78]
    DIRECTION OUTPUT ;
    USE SIGNAL ;
    PORT
      LAYER M4 ;
        RECT  0 39.408 0.084 39.432 ;
    END
  END a_cfg_data[78]
  PIN a_cfg_data[79]
    DIRECTION OUTPUT ;
    USE SIGNAL ;
    PORT
      LAYER M4 ;
        RECT  0 39.504 0.084 39.528 ;
    END
  END a_cfg_data[79]
  PIN a_cfg_data[7]
    DIRECTION OUTPUT ;
    USE SIGNAL ;
    PORT
      LAYER M4 ;
        RECT  0 32.592 0.084 32.616 ;
    END
  END a_cfg_data[7]
  PIN a_cfg_data[80]
    DIRECTION OUTPUT ;
    USE SIGNAL ;
    PORT
      LAYER M4 ;
        RECT  0 39.6 0.084 39.624 ;
    END
  END a_cfg_data[80]
  PIN a_cfg_data[81]
    DIRECTION OUTPUT ;
    USE SIGNAL ;
    PORT
      LAYER M4 ;
        RECT  0 39.696 0.084 39.72 ;
    END
  END a_cfg_data[81]
  PIN a_cfg_data[82]
    DIRECTION OUTPUT ;
    USE SIGNAL ;
    PORT
      LAYER M4 ;
        RECT  0 39.792 0.084 39.816 ;
    END
  END a_cfg_data[82]
  PIN a_cfg_data[83]
    DIRECTION OUTPUT ;
    USE SIGNAL ;
    PORT
      LAYER M4 ;
        RECT  0 39.888 0.084 39.912 ;
    END
  END a_cfg_data[83]
  PIN a_cfg_data[84]
    DIRECTION OUTPUT ;
    USE SIGNAL ;
    PORT
      LAYER M4 ;
        RECT  0 43.056 0.084 43.08 ;
    END
  END a_cfg_data[84]
  PIN a_cfg_data[85]
    DIRECTION OUTPUT ;
    USE SIGNAL ;
    PORT
      LAYER M4 ;
        RECT  0 43.152 0.084 43.176 ;
    END
  END a_cfg_data[85]
  PIN a_cfg_data[86]
    DIRECTION OUTPUT ;
    USE SIGNAL ;
    PORT
      LAYER M4 ;
        RECT  0 43.248 0.084 43.272 ;
    END
  END a_cfg_data[86]
  PIN a_cfg_data[87]
    DIRECTION OUTPUT ;
    USE SIGNAL ;
    PORT
      LAYER M4 ;
        RECT  0 43.344 0.084 43.368 ;
    END
  END a_cfg_data[87]
  PIN a_cfg_data[88]
    DIRECTION OUTPUT ;
    USE SIGNAL ;
    PORT
      LAYER M4 ;
        RECT  0 43.44 0.084 43.464 ;
    END
  END a_cfg_data[88]
  PIN a_cfg_data[89]
    DIRECTION OUTPUT ;
    USE SIGNAL ;
    PORT
      LAYER M4 ;
        RECT  0 43.536 0.084 43.56 ;
    END
  END a_cfg_data[89]
  PIN a_cfg_data[8]
    DIRECTION OUTPUT ;
    USE SIGNAL ;
    PORT
      LAYER M4 ;
        RECT  0 32.688 0.084 32.712 ;
    END
  END a_cfg_data[8]
  PIN a_cfg_data[90]
    DIRECTION OUTPUT ;
    USE SIGNAL ;
    PORT
      LAYER M4 ;
        RECT  0 43.632 0.084 43.656 ;
    END
  END a_cfg_data[90]
  PIN a_cfg_data[91]
    DIRECTION OUTPUT ;
    USE SIGNAL ;
    PORT
      LAYER M4 ;
        RECT  0 43.728 0.084 43.752 ;
    END
  END a_cfg_data[91]
  PIN a_cfg_data[92]
    DIRECTION OUTPUT ;
    USE SIGNAL ;
    PORT
      LAYER M4 ;
        RECT  0 43.824 0.084 43.848 ;
    END
  END a_cfg_data[92]
  PIN a_cfg_data[93]
    DIRECTION OUTPUT ;
    USE SIGNAL ;
    PORT
      LAYER M4 ;
        RECT  0 43.92 0.084 43.944 ;
    END
  END a_cfg_data[93]
  PIN a_cfg_data[94]
    DIRECTION OUTPUT ;
    USE SIGNAL ;
    PORT
      LAYER M4 ;
        RECT  0 44.016 0.084 44.04 ;
    END
  END a_cfg_data[94]
  PIN a_cfg_data[95]
    DIRECTION OUTPUT ;
    USE SIGNAL ;
    PORT
      LAYER M4 ;
        RECT  0 44.112 0.084 44.136 ;
    END
  END a_cfg_data[95]
  PIN a_cfg_data[96]
    DIRECTION OUTPUT ;
    USE SIGNAL ;
    PORT
      LAYER M4 ;
        RECT  0 44.208 0.084 44.232 ;
    END
  END a_cfg_data[96]
  PIN a_cfg_data[97]
    DIRECTION OUTPUT ;
    USE SIGNAL ;
    PORT
      LAYER M4 ;
        RECT  0 44.304 0.084 44.328 ;
    END
  END a_cfg_data[97]
  PIN a_cfg_data[98]
    DIRECTION OUTPUT ;
    USE SIGNAL ;
    PORT
      LAYER M4 ;
        RECT  0 44.4 0.084 44.424 ;
    END
  END a_cfg_data[98]
  PIN a_cfg_data[99]
    DIRECTION OUTPUT ;
    USE SIGNAL ;
    PORT
      LAYER M4 ;
        RECT  0 44.496 0.084 44.52 ;
    END
  END a_cfg_data[99]
  PIN a_cfg_data[9]
    DIRECTION OUTPUT ;
    USE SIGNAL ;
    PORT
      LAYER M4 ;
        RECT  0 32.784 0.084 32.808 ;
    END
  END a_cfg_data[9]
  PIN a_cfg_target[0]
    DIRECTION OUTPUT ;
    USE SIGNAL ;
    PORT
      LAYER M4 ;
        RECT  0 25.008 0.084 25.032 ;
    END
  END a_cfg_target[0]
  PIN a_cfg_target[1]
    DIRECTION OUTPUT ;
    USE SIGNAL ;
    PORT
      LAYER M4 ;
        RECT  0 25.104 0.084 25.128 ;
    END
  END a_cfg_target[1]
  PIN a_cfg_target[2]
    DIRECTION OUTPUT ;
    USE SIGNAL ;
    PORT
      LAYER M4 ;
        RECT  0 25.2 0.084 25.224 ;
    END
  END a_cfg_target[2]
  PIN a_cfg_target[3]
    DIRECTION OUTPUT ;
    USE SIGNAL ;
    PORT
      LAYER M4 ;
        RECT  0 25.296 0.084 25.32 ;
    END
  END a_cfg_target[3]
  PIN a_cfg_target[4]
    DIRECTION OUTPUT ;
    USE SIGNAL ;
    PORT
      LAYER M4 ;
        RECT  0 25.392 0.084 25.416 ;
    END
  END a_cfg_target[4]
  PIN a_cfg_target[5]
    DIRECTION OUTPUT ;
    USE SIGNAL ;
    PORT
      LAYER M4 ;
        RECT  0 25.488 0.084 25.512 ;
    END
  END a_cfg_target[5]
  PIN a_cfg_target[6]
    DIRECTION OUTPUT ;
    USE SIGNAL ;
    PORT
      LAYER M4 ;
        RECT  0 25.584 0.084 25.608 ;
    END
  END a_cfg_target[6]
  PIN a_cfg_target[7]
    DIRECTION OUTPUT ;
    USE SIGNAL ;
    PORT
      LAYER M4 ;
        RECT  0 25.68 0.084 25.704 ;
    END
  END a_cfg_target[7]
  PIN a_cfg_v
    DIRECTION OUTPUT ;
    USE SIGNAL ;
    PORT
      LAYER M4 ;
        RECT  0 25.776 0.084 25.8 ;
    END
  END a_cfg_v
  PIN a_desc_base[0]
    DIRECTION OUTPUT ;
    USE SIGNAL ;
    PORT
      LAYER M4 ;
        RECT  0 25.872 0.084 25.896 ;
    END
  END a_desc_base[0]
  PIN a_desc_base[10]
    DIRECTION OUTPUT ;
    USE SIGNAL ;
    PORT
      LAYER M4 ;
        RECT  0 26.832 0.084 26.856 ;
    END
  END a_desc_base[10]
  PIN a_desc_base[11]
    DIRECTION OUTPUT ;
    USE SIGNAL ;
    PORT
      LAYER M4 ;
        RECT  0 17.712 0.084 17.736 ;
    END
  END a_desc_base[11]
  PIN a_desc_base[1]
    DIRECTION OUTPUT ;
    USE SIGNAL ;
    PORT
      LAYER M4 ;
        RECT  0 25.968 0.084 25.992 ;
    END
  END a_desc_base[1]
  PIN a_desc_base[2]
    DIRECTION OUTPUT ;
    USE SIGNAL ;
    PORT
      LAYER M4 ;
        RECT  0 26.064 0.084 26.088 ;
    END
  END a_desc_base[2]
  PIN a_desc_base[3]
    DIRECTION OUTPUT ;
    USE SIGNAL ;
    PORT
      LAYER M4 ;
        RECT  0 26.16 0.084 26.184 ;
    END
  END a_desc_base[3]
  PIN a_desc_base[4]
    DIRECTION OUTPUT ;
    USE SIGNAL ;
    PORT
      LAYER M4 ;
        RECT  0 26.256 0.084 26.28 ;
    END
  END a_desc_base[4]
  PIN a_desc_base[5]
    DIRECTION OUTPUT ;
    USE SIGNAL ;
    PORT
      LAYER M4 ;
        RECT  0 26.352 0.084 26.376 ;
    END
  END a_desc_base[5]
  PIN a_desc_base[6]
    DIRECTION OUTPUT ;
    USE SIGNAL ;
    PORT
      LAYER M4 ;
        RECT  0 26.448 0.084 26.472 ;
    END
  END a_desc_base[6]
  PIN a_desc_base[7]
    DIRECTION OUTPUT ;
    USE SIGNAL ;
    PORT
      LAYER M4 ;
        RECT  0 26.544 0.084 26.568 ;
    END
  END a_desc_base[7]
  PIN a_desc_base[8]
    DIRECTION OUTPUT ;
    USE SIGNAL ;
    PORT
      LAYER M4 ;
        RECT  0 26.64 0.084 26.664 ;
    END
  END a_desc_base[8]
  PIN a_desc_base[9]
    DIRECTION OUTPUT ;
    USE SIGNAL ;
    PORT
      LAYER M4 ;
        RECT  0 26.736 0.084 26.76 ;
    END
  END a_desc_base[9]
  PIN a_desc_limit[0]
    DIRECTION OUTPUT ;
    USE SIGNAL ;
    PORT
      LAYER M4 ;
        RECT  0 17.808 0.084 17.832 ;
    END
  END a_desc_limit[0]
  PIN a_desc_limit[10]
    DIRECTION OUTPUT ;
    USE SIGNAL ;
    PORT
      LAYER M4 ;
        RECT  0 18.768 0.084 18.792 ;
    END
  END a_desc_limit[10]
  PIN a_desc_limit[11]
    DIRECTION OUTPUT ;
    USE SIGNAL ;
    PORT
      LAYER M4 ;
        RECT  0 18.864 0.084 18.888 ;
    END
  END a_desc_limit[11]
  PIN a_desc_limit[12]
    DIRECTION OUTPUT ;
    USE SIGNAL ;
    PORT
      LAYER M4 ;
        RECT  0 18.96 0.084 18.984 ;
    END
  END a_desc_limit[12]
  PIN a_desc_limit[1]
    DIRECTION OUTPUT ;
    USE SIGNAL ;
    PORT
      LAYER M4 ;
        RECT  0 17.904 0.084 17.928 ;
    END
  END a_desc_limit[1]
  PIN a_desc_limit[2]
    DIRECTION OUTPUT ;
    USE SIGNAL ;
    PORT
      LAYER M4 ;
        RECT  0 18 0.084 18.024 ;
    END
  END a_desc_limit[2]
  PIN a_desc_limit[3]
    DIRECTION OUTPUT ;
    USE SIGNAL ;
    PORT
      LAYER M4 ;
        RECT  0 18.096 0.084 18.12 ;
    END
  END a_desc_limit[3]
  PIN a_desc_limit[4]
    DIRECTION OUTPUT ;
    USE SIGNAL ;
    PORT
      LAYER M4 ;
        RECT  0 18.192 0.084 18.216 ;
    END
  END a_desc_limit[4]
  PIN a_desc_limit[5]
    DIRECTION OUTPUT ;
    USE SIGNAL ;
    PORT
      LAYER M4 ;
        RECT  0 18.288 0.084 18.312 ;
    END
  END a_desc_limit[5]
  PIN a_desc_limit[6]
    DIRECTION OUTPUT ;
    USE SIGNAL ;
    PORT
      LAYER M4 ;
        RECT  0 18.384 0.084 18.408 ;
    END
  END a_desc_limit[6]
  PIN a_desc_limit[7]
    DIRECTION OUTPUT ;
    USE SIGNAL ;
    PORT
      LAYER M4 ;
        RECT  0 18.48 0.084 18.504 ;
    END
  END a_desc_limit[7]
  PIN a_desc_limit[8]
    DIRECTION OUTPUT ;
    USE SIGNAL ;
    PORT
      LAYER M4 ;
        RECT  0 18.576 0.084 18.6 ;
    END
  END a_desc_limit[8]
  PIN a_desc_limit[9]
    DIRECTION OUTPUT ;
    USE SIGNAL ;
    PORT
      LAYER M4 ;
        RECT  0 18.672 0.084 18.696 ;
    END
  END a_desc_limit[9]
  PIN a_desc_loops[0]
    DIRECTION OUTPUT ;
    USE SIGNAL ;
    PORT
      LAYER M4 ;
        RECT  0 19.056 0.084 19.08 ;
    END
  END a_desc_loops[0]
  PIN a_desc_loops[10]
    DIRECTION OUTPUT ;
    USE SIGNAL ;
    PORT
      LAYER M4 ;
        RECT  0 20.016 0.084 20.04 ;
    END
  END a_desc_loops[10]
  PIN a_desc_loops[11]
    DIRECTION OUTPUT ;
    USE SIGNAL ;
    PORT
      LAYER M4 ;
        RECT  0 20.112 0.084 20.136 ;
    END
  END a_desc_loops[11]
  PIN a_desc_loops[12]
    DIRECTION OUTPUT ;
    USE SIGNAL ;
    PORT
      LAYER M4 ;
        RECT  0 20.208 0.084 20.232 ;
    END
  END a_desc_loops[12]
  PIN a_desc_loops[13]
    DIRECTION OUTPUT ;
    USE SIGNAL ;
    PORT
      LAYER M4 ;
        RECT  0 20.304 0.084 20.328 ;
    END
  END a_desc_loops[13]
  PIN a_desc_loops[14]
    DIRECTION OUTPUT ;
    USE SIGNAL ;
    PORT
      LAYER M4 ;
        RECT  0 20.4 0.084 20.424 ;
    END
  END a_desc_loops[14]
  PIN a_desc_loops[15]
    DIRECTION OUTPUT ;
    USE SIGNAL ;
    PORT
      LAYER M4 ;
        RECT  0 20.496 0.084 20.52 ;
    END
  END a_desc_loops[15]
  PIN a_desc_loops[1]
    DIRECTION OUTPUT ;
    USE SIGNAL ;
    PORT
      LAYER M4 ;
        RECT  0 19.152 0.084 19.176 ;
    END
  END a_desc_loops[1]
  PIN a_desc_loops[2]
    DIRECTION OUTPUT ;
    USE SIGNAL ;
    PORT
      LAYER M4 ;
        RECT  0 19.248 0.084 19.272 ;
    END
  END a_desc_loops[2]
  PIN a_desc_loops[3]
    DIRECTION OUTPUT ;
    USE SIGNAL ;
    PORT
      LAYER M4 ;
        RECT  0 19.344 0.084 19.368 ;
    END
  END a_desc_loops[3]
  PIN a_desc_loops[4]
    DIRECTION OUTPUT ;
    USE SIGNAL ;
    PORT
      LAYER M4 ;
        RECT  0 19.44 0.084 19.464 ;
    END
  END a_desc_loops[4]
  PIN a_desc_loops[5]
    DIRECTION OUTPUT ;
    USE SIGNAL ;
    PORT
      LAYER M4 ;
        RECT  0 19.536 0.084 19.56 ;
    END
  END a_desc_loops[5]
  PIN a_desc_loops[6]
    DIRECTION OUTPUT ;
    USE SIGNAL ;
    PORT
      LAYER M4 ;
        RECT  0 19.632 0.084 19.656 ;
    END
  END a_desc_loops[6]
  PIN a_desc_loops[7]
    DIRECTION OUTPUT ;
    USE SIGNAL ;
    PORT
      LAYER M4 ;
        RECT  0 19.728 0.084 19.752 ;
    END
  END a_desc_loops[7]
  PIN a_desc_loops[8]
    DIRECTION OUTPUT ;
    USE SIGNAL ;
    PORT
      LAYER M4 ;
        RECT  0 19.824 0.084 19.848 ;
    END
  END a_desc_loops[8]
  PIN a_desc_loops[9]
    DIRECTION OUTPUT ;
    USE SIGNAL ;
    PORT
      LAYER M4 ;
        RECT  0 19.92 0.084 19.944 ;
    END
  END a_desc_loops[9]
  PIN a_desc_v
    DIRECTION OUTPUT ;
    USE SIGNAL ;
    PORT
      LAYER M4 ;
        RECT  0 20.592 0.084 20.616 ;
    END
  END a_desc_v
  PIN a_launch_v
    DIRECTION OUTPUT ;
    USE SIGNAL ;
    PORT
      LAYER M4 ;
        RECT  0 20.688 0.084 20.712 ;
    END
  END a_launch_v
  PIN b_cfg_addr[0]
    DIRECTION OUTPUT ;
    USE SIGNAL ;
    PORT
      LAYER M4 ;
        RECT  69.036 26.064 69.12 26.088 ;
    END
  END b_cfg_addr[0]
  PIN b_cfg_addr[10]
    DIRECTION OUTPUT ;
    USE SIGNAL ;
    PORT
      LAYER M4 ;
        RECT  69.036 27.024 69.12 27.048 ;
    END
  END b_cfg_addr[10]
  PIN b_cfg_addr[11]
    DIRECTION OUTPUT ;
    USE SIGNAL ;
    PORT
      LAYER M4 ;
        RECT  69.036 27.12 69.12 27.144 ;
    END
  END b_cfg_addr[11]
  PIN b_cfg_addr[1]
    DIRECTION OUTPUT ;
    USE SIGNAL ;
    PORT
      LAYER M4 ;
        RECT  69.036 26.16 69.12 26.184 ;
    END
  END b_cfg_addr[1]
  PIN b_cfg_addr[2]
    DIRECTION OUTPUT ;
    USE SIGNAL ;
    PORT
      LAYER M4 ;
        RECT  69.036 26.256 69.12 26.28 ;
    END
  END b_cfg_addr[2]
  PIN b_cfg_addr[3]
    DIRECTION OUTPUT ;
    USE SIGNAL ;
    PORT
      LAYER M4 ;
        RECT  69.036 26.352 69.12 26.376 ;
    END
  END b_cfg_addr[3]
  PIN b_cfg_addr[4]
    DIRECTION OUTPUT ;
    USE SIGNAL ;
    PORT
      LAYER M4 ;
        RECT  69.036 26.448 69.12 26.472 ;
    END
  END b_cfg_addr[4]
  PIN b_cfg_addr[5]
    DIRECTION OUTPUT ;
    USE SIGNAL ;
    PORT
      LAYER M4 ;
        RECT  69.036 26.544 69.12 26.568 ;
    END
  END b_cfg_addr[5]
  PIN b_cfg_addr[6]
    DIRECTION OUTPUT ;
    USE SIGNAL ;
    PORT
      LAYER M4 ;
        RECT  69.036 26.64 69.12 26.664 ;
    END
  END b_cfg_addr[6]
  PIN b_cfg_addr[7]
    DIRECTION OUTPUT ;
    USE SIGNAL ;
    PORT
      LAYER M4 ;
        RECT  69.036 26.736 69.12 26.76 ;
    END
  END b_cfg_addr[7]
  PIN b_cfg_addr[8]
    DIRECTION OUTPUT ;
    USE SIGNAL ;
    PORT
      LAYER M4 ;
        RECT  69.036 26.832 69.12 26.856 ;
    END
  END b_cfg_addr[8]
  PIN b_cfg_addr[9]
    DIRECTION OUTPUT ;
    USE SIGNAL ;
    PORT
      LAYER M4 ;
        RECT  69.036 26.928 69.12 26.952 ;
    END
  END b_cfg_addr[9]
  PIN b_cfg_data[0]
    DIRECTION OUTPUT ;
    USE SIGNAL ;
    PORT
      LAYER M4 ;
        RECT  69.036 27.216 69.12 27.24 ;
    END
  END b_cfg_data[0]
  PIN b_cfg_data[100]
    DIRECTION OUTPUT ;
    USE SIGNAL ;
    PORT
      LAYER M4 ;
        RECT  69.036 43.728 69.12 43.752 ;
    END
  END b_cfg_data[100]
  PIN b_cfg_data[101]
    DIRECTION OUTPUT ;
    USE SIGNAL ;
    PORT
      LAYER M4 ;
        RECT  69.036 43.824 69.12 43.848 ;
    END
  END b_cfg_data[101]
  PIN b_cfg_data[102]
    DIRECTION OUTPUT ;
    USE SIGNAL ;
    PORT
      LAYER M4 ;
        RECT  69.036 43.92 69.12 43.944 ;
    END
  END b_cfg_data[102]
  PIN b_cfg_data[103]
    DIRECTION OUTPUT ;
    USE SIGNAL ;
    PORT
      LAYER M4 ;
        RECT  69.036 44.016 69.12 44.04 ;
    END
  END b_cfg_data[103]
  PIN b_cfg_data[104]
    DIRECTION OUTPUT ;
    USE SIGNAL ;
    PORT
      LAYER M4 ;
        RECT  69.036 44.112 69.12 44.136 ;
    END
  END b_cfg_data[104]
  PIN b_cfg_data[105]
    DIRECTION OUTPUT ;
    USE SIGNAL ;
    PORT
      LAYER M4 ;
        RECT  69.036 44.208 69.12 44.232 ;
    END
  END b_cfg_data[105]
  PIN b_cfg_data[106]
    DIRECTION OUTPUT ;
    USE SIGNAL ;
    PORT
      LAYER M4 ;
        RECT  69.036 44.304 69.12 44.328 ;
    END
  END b_cfg_data[106]
  PIN b_cfg_data[107]
    DIRECTION OUTPUT ;
    USE SIGNAL ;
    PORT
      LAYER M4 ;
        RECT  69.036 44.4 69.12 44.424 ;
    END
  END b_cfg_data[107]
  PIN b_cfg_data[108]
    DIRECTION OUTPUT ;
    USE SIGNAL ;
    PORT
      LAYER M4 ;
        RECT  69.036 44.496 69.12 44.52 ;
    END
  END b_cfg_data[108]
  PIN b_cfg_data[109]
    DIRECTION OUTPUT ;
    USE SIGNAL ;
    PORT
      LAYER M4 ;
        RECT  69.036 44.592 69.12 44.616 ;
    END
  END b_cfg_data[109]
  PIN b_cfg_data[10]
    DIRECTION OUTPUT ;
    USE SIGNAL ;
    PORT
      LAYER M4 ;
        RECT  69.036 28.176 69.12 28.2 ;
    END
  END b_cfg_data[10]
  PIN b_cfg_data[110]
    DIRECTION OUTPUT ;
    USE SIGNAL ;
    PORT
      LAYER M4 ;
        RECT  69.036 44.688 69.12 44.712 ;
    END
  END b_cfg_data[110]
  PIN b_cfg_data[111]
    DIRECTION OUTPUT ;
    USE SIGNAL ;
    PORT
      LAYER M4 ;
        RECT  69.036 44.784 69.12 44.808 ;
    END
  END b_cfg_data[111]
  PIN b_cfg_data[112]
    DIRECTION OUTPUT ;
    USE SIGNAL ;
    PORT
      LAYER M4 ;
        RECT  69.036 44.88 69.12 44.904 ;
    END
  END b_cfg_data[112]
  PIN b_cfg_data[113]
    DIRECTION OUTPUT ;
    USE SIGNAL ;
    PORT
      LAYER M4 ;
        RECT  69.036 44.976 69.12 45 ;
    END
  END b_cfg_data[113]
  PIN b_cfg_data[114]
    DIRECTION OUTPUT ;
    USE SIGNAL ;
    PORT
      LAYER M4 ;
        RECT  69.036 45.072 69.12 45.096 ;
    END
  END b_cfg_data[114]
  PIN b_cfg_data[115]
    DIRECTION OUTPUT ;
    USE SIGNAL ;
    PORT
      LAYER M4 ;
        RECT  69.036 45.168 69.12 45.192 ;
    END
  END b_cfg_data[115]
  PIN b_cfg_data[116]
    DIRECTION OUTPUT ;
    USE SIGNAL ;
    PORT
      LAYER M4 ;
        RECT  69.036 35.28 69.12 35.304 ;
    END
  END b_cfg_data[116]
  PIN b_cfg_data[117]
    DIRECTION OUTPUT ;
    USE SIGNAL ;
    PORT
      LAYER M4 ;
        RECT  69.036 35.376 69.12 35.4 ;
    END
  END b_cfg_data[117]
  PIN b_cfg_data[118]
    DIRECTION OUTPUT ;
    USE SIGNAL ;
    PORT
      LAYER M4 ;
        RECT  69.036 35.472 69.12 35.496 ;
    END
  END b_cfg_data[118]
  PIN b_cfg_data[119]
    DIRECTION OUTPUT ;
    USE SIGNAL ;
    PORT
      LAYER M4 ;
        RECT  69.036 35.568 69.12 35.592 ;
    END
  END b_cfg_data[119]
  PIN b_cfg_data[11]
    DIRECTION OUTPUT ;
    USE SIGNAL ;
    PORT
      LAYER M4 ;
        RECT  69.036 28.272 69.12 28.296 ;
    END
  END b_cfg_data[11]
  PIN b_cfg_data[120]
    DIRECTION OUTPUT ;
    USE SIGNAL ;
    PORT
      LAYER M4 ;
        RECT  69.036 35.664 69.12 35.688 ;
    END
  END b_cfg_data[120]
  PIN b_cfg_data[121]
    DIRECTION OUTPUT ;
    USE SIGNAL ;
    PORT
      LAYER M4 ;
        RECT  69.036 35.76 69.12 35.784 ;
    END
  END b_cfg_data[121]
  PIN b_cfg_data[122]
    DIRECTION OUTPUT ;
    USE SIGNAL ;
    PORT
      LAYER M4 ;
        RECT  69.036 35.856 69.12 35.88 ;
    END
  END b_cfg_data[122]
  PIN b_cfg_data[123]
    DIRECTION OUTPUT ;
    USE SIGNAL ;
    PORT
      LAYER M4 ;
        RECT  69.036 35.952 69.12 35.976 ;
    END
  END b_cfg_data[123]
  PIN b_cfg_data[124]
    DIRECTION OUTPUT ;
    USE SIGNAL ;
    PORT
      LAYER M4 ;
        RECT  69.036 36.048 69.12 36.072 ;
    END
  END b_cfg_data[124]
  PIN b_cfg_data[125]
    DIRECTION OUTPUT ;
    USE SIGNAL ;
    PORT
      LAYER M4 ;
        RECT  69.036 36.144 69.12 36.168 ;
    END
  END b_cfg_data[125]
  PIN b_cfg_data[126]
    DIRECTION OUTPUT ;
    USE SIGNAL ;
    PORT
      LAYER M4 ;
        RECT  69.036 36.24 69.12 36.264 ;
    END
  END b_cfg_data[126]
  PIN b_cfg_data[127]
    DIRECTION OUTPUT ;
    USE SIGNAL ;
    PORT
      LAYER M4 ;
        RECT  69.036 36.336 69.12 36.36 ;
    END
  END b_cfg_data[127]
  PIN b_cfg_data[128]
    DIRECTION OUTPUT ;
    USE SIGNAL ;
    PORT
      LAYER M4 ;
        RECT  69.036 36.432 69.12 36.456 ;
    END
  END b_cfg_data[128]
  PIN b_cfg_data[129]
    DIRECTION OUTPUT ;
    USE SIGNAL ;
    PORT
      LAYER M4 ;
        RECT  69.036 36.528 69.12 36.552 ;
    END
  END b_cfg_data[129]
  PIN b_cfg_data[12]
    DIRECTION OUTPUT ;
    USE SIGNAL ;
    PORT
      LAYER M4 ;
        RECT  69.036 28.368 69.12 28.392 ;
    END
  END b_cfg_data[12]
  PIN b_cfg_data[130]
    DIRECTION OUTPUT ;
    USE SIGNAL ;
    PORT
      LAYER M4 ;
        RECT  69.036 36.624 69.12 36.648 ;
    END
  END b_cfg_data[130]
  PIN b_cfg_data[131]
    DIRECTION OUTPUT ;
    USE SIGNAL ;
    PORT
      LAYER M4 ;
        RECT  69.036 36.72 69.12 36.744 ;
    END
  END b_cfg_data[131]
  PIN b_cfg_data[132]
    DIRECTION OUTPUT ;
    USE SIGNAL ;
    PORT
      LAYER M4 ;
        RECT  69.036 36.816 69.12 36.84 ;
    END
  END b_cfg_data[132]
  PIN b_cfg_data[133]
    DIRECTION OUTPUT ;
    USE SIGNAL ;
    PORT
      LAYER M4 ;
        RECT  69.036 36.912 69.12 36.936 ;
    END
  END b_cfg_data[133]
  PIN b_cfg_data[134]
    DIRECTION OUTPUT ;
    USE SIGNAL ;
    PORT
      LAYER M4 ;
        RECT  69.036 37.008 69.12 37.032 ;
    END
  END b_cfg_data[134]
  PIN b_cfg_data[135]
    DIRECTION OUTPUT ;
    USE SIGNAL ;
    PORT
      LAYER M4 ;
        RECT  69.036 37.104 69.12 37.128 ;
    END
  END b_cfg_data[135]
  PIN b_cfg_data[136]
    DIRECTION OUTPUT ;
    USE SIGNAL ;
    PORT
      LAYER M4 ;
        RECT  69.036 37.2 69.12 37.224 ;
    END
  END b_cfg_data[136]
  PIN b_cfg_data[137]
    DIRECTION OUTPUT ;
    USE SIGNAL ;
    PORT
      LAYER M4 ;
        RECT  69.036 37.296 69.12 37.32 ;
    END
  END b_cfg_data[137]
  PIN b_cfg_data[138]
    DIRECTION OUTPUT ;
    USE SIGNAL ;
    PORT
      LAYER M4 ;
        RECT  69.036 37.392 69.12 37.416 ;
    END
  END b_cfg_data[138]
  PIN b_cfg_data[139]
    DIRECTION OUTPUT ;
    USE SIGNAL ;
    PORT
      LAYER M4 ;
        RECT  69.036 37.488 69.12 37.512 ;
    END
  END b_cfg_data[139]
  PIN b_cfg_data[13]
    DIRECTION OUTPUT ;
    USE SIGNAL ;
    PORT
      LAYER M4 ;
        RECT  69.036 28.464 69.12 28.488 ;
    END
  END b_cfg_data[13]
  PIN b_cfg_data[140]
    DIRECTION OUTPUT ;
    USE SIGNAL ;
    PORT
      LAYER M4 ;
        RECT  69.036 37.584 69.12 37.608 ;
    END
  END b_cfg_data[140]
  PIN b_cfg_data[141]
    DIRECTION OUTPUT ;
    USE SIGNAL ;
    PORT
      LAYER M4 ;
        RECT  69.036 37.68 69.12 37.704 ;
    END
  END b_cfg_data[141]
  PIN b_cfg_data[142]
    DIRECTION OUTPUT ;
    USE SIGNAL ;
    PORT
      LAYER M4 ;
        RECT  69.036 37.776 69.12 37.8 ;
    END
  END b_cfg_data[142]
  PIN b_cfg_data[143]
    DIRECTION OUTPUT ;
    USE SIGNAL ;
    PORT
      LAYER M4 ;
        RECT  69.036 37.872 69.12 37.896 ;
    END
  END b_cfg_data[143]
  PIN b_cfg_data[144]
    DIRECTION OUTPUT ;
    USE SIGNAL ;
    PORT
      LAYER M4 ;
        RECT  69.036 37.968 69.12 37.992 ;
    END
  END b_cfg_data[144]
  PIN b_cfg_data[145]
    DIRECTION OUTPUT ;
    USE SIGNAL ;
    PORT
      LAYER M4 ;
        RECT  69.036 38.064 69.12 38.088 ;
    END
  END b_cfg_data[145]
  PIN b_cfg_data[146]
    DIRECTION OUTPUT ;
    USE SIGNAL ;
    PORT
      LAYER M4 ;
        RECT  69.036 38.16 69.12 38.184 ;
    END
  END b_cfg_data[146]
  PIN b_cfg_data[147]
    DIRECTION OUTPUT ;
    USE SIGNAL ;
    PORT
      LAYER M4 ;
        RECT  69.036 38.256 69.12 38.28 ;
    END
  END b_cfg_data[147]
  PIN b_cfg_data[148]
    DIRECTION OUTPUT ;
    USE SIGNAL ;
    PORT
      LAYER M4 ;
        RECT  69.036 45.264 69.12 45.288 ;
    END
  END b_cfg_data[148]
  PIN b_cfg_data[149]
    DIRECTION OUTPUT ;
    USE SIGNAL ;
    PORT
      LAYER M4 ;
        RECT  69.036 45.36 69.12 45.384 ;
    END
  END b_cfg_data[149]
  PIN b_cfg_data[14]
    DIRECTION OUTPUT ;
    USE SIGNAL ;
    PORT
      LAYER M4 ;
        RECT  69.036 28.56 69.12 28.584 ;
    END
  END b_cfg_data[14]
  PIN b_cfg_data[150]
    DIRECTION OUTPUT ;
    USE SIGNAL ;
    PORT
      LAYER M4 ;
        RECT  69.036 45.456 69.12 45.48 ;
    END
  END b_cfg_data[150]
  PIN b_cfg_data[151]
    DIRECTION OUTPUT ;
    USE SIGNAL ;
    PORT
      LAYER M4 ;
        RECT  69.036 45.552 69.12 45.576 ;
    END
  END b_cfg_data[151]
  PIN b_cfg_data[152]
    DIRECTION OUTPUT ;
    USE SIGNAL ;
    PORT
      LAYER M4 ;
        RECT  69.036 45.648 69.12 45.672 ;
    END
  END b_cfg_data[152]
  PIN b_cfg_data[153]
    DIRECTION OUTPUT ;
    USE SIGNAL ;
    PORT
      LAYER M4 ;
        RECT  69.036 45.744 69.12 45.768 ;
    END
  END b_cfg_data[153]
  PIN b_cfg_data[154]
    DIRECTION OUTPUT ;
    USE SIGNAL ;
    PORT
      LAYER M4 ;
        RECT  69.036 45.84 69.12 45.864 ;
    END
  END b_cfg_data[154]
  PIN b_cfg_data[155]
    DIRECTION OUTPUT ;
    USE SIGNAL ;
    PORT
      LAYER M4 ;
        RECT  69.036 45.936 69.12 45.96 ;
    END
  END b_cfg_data[155]
  PIN b_cfg_data[156]
    DIRECTION OUTPUT ;
    USE SIGNAL ;
    PORT
      LAYER M4 ;
        RECT  69.036 46.032 69.12 46.056 ;
    END
  END b_cfg_data[156]
  PIN b_cfg_data[157]
    DIRECTION OUTPUT ;
    USE SIGNAL ;
    PORT
      LAYER M4 ;
        RECT  69.036 46.128 69.12 46.152 ;
    END
  END b_cfg_data[157]
  PIN b_cfg_data[158]
    DIRECTION OUTPUT ;
    USE SIGNAL ;
    PORT
      LAYER M4 ;
        RECT  69.036 46.224 69.12 46.248 ;
    END
  END b_cfg_data[158]
  PIN b_cfg_data[159]
    DIRECTION OUTPUT ;
    USE SIGNAL ;
    PORT
      LAYER M4 ;
        RECT  69.036 46.32 69.12 46.344 ;
    END
  END b_cfg_data[159]
  PIN b_cfg_data[15]
    DIRECTION OUTPUT ;
    USE SIGNAL ;
    PORT
      LAYER M4 ;
        RECT  69.036 28.656 69.12 28.68 ;
    END
  END b_cfg_data[15]
  PIN b_cfg_data[160]
    DIRECTION OUTPUT ;
    USE SIGNAL ;
    PORT
      LAYER M4 ;
        RECT  69.036 46.416 69.12 46.44 ;
    END
  END b_cfg_data[160]
  PIN b_cfg_data[161]
    DIRECTION OUTPUT ;
    USE SIGNAL ;
    PORT
      LAYER M4 ;
        RECT  69.036 46.512 69.12 46.536 ;
    END
  END b_cfg_data[161]
  PIN b_cfg_data[162]
    DIRECTION OUTPUT ;
    USE SIGNAL ;
    PORT
      LAYER M4 ;
        RECT  69.036 46.608 69.12 46.632 ;
    END
  END b_cfg_data[162]
  PIN b_cfg_data[163]
    DIRECTION OUTPUT ;
    USE SIGNAL ;
    PORT
      LAYER M4 ;
        RECT  69.036 46.704 69.12 46.728 ;
    END
  END b_cfg_data[163]
  PIN b_cfg_data[164]
    DIRECTION OUTPUT ;
    USE SIGNAL ;
    PORT
      LAYER M4 ;
        RECT  69.036 46.8 69.12 46.824 ;
    END
  END b_cfg_data[164]
  PIN b_cfg_data[165]
    DIRECTION OUTPUT ;
    USE SIGNAL ;
    PORT
      LAYER M4 ;
        RECT  69.036 46.896 69.12 46.92 ;
    END
  END b_cfg_data[165]
  PIN b_cfg_data[166]
    DIRECTION OUTPUT ;
    USE SIGNAL ;
    PORT
      LAYER M4 ;
        RECT  69.036 46.992 69.12 47.016 ;
    END
  END b_cfg_data[166]
  PIN b_cfg_data[167]
    DIRECTION OUTPUT ;
    USE SIGNAL ;
    PORT
      LAYER M4 ;
        RECT  69.036 47.088 69.12 47.112 ;
    END
  END b_cfg_data[167]
  PIN b_cfg_data[168]
    DIRECTION OUTPUT ;
    USE SIGNAL ;
    PORT
      LAYER M4 ;
        RECT  69.036 47.184 69.12 47.208 ;
    END
  END b_cfg_data[168]
  PIN b_cfg_data[169]
    DIRECTION OUTPUT ;
    USE SIGNAL ;
    PORT
      LAYER M4 ;
        RECT  69.036 47.28 69.12 47.304 ;
    END
  END b_cfg_data[169]
  PIN b_cfg_data[16]
    DIRECTION OUTPUT ;
    USE SIGNAL ;
    PORT
      LAYER M4 ;
        RECT  69.036 28.752 69.12 28.776 ;
    END
  END b_cfg_data[16]
  PIN b_cfg_data[170]
    DIRECTION OUTPUT ;
    USE SIGNAL ;
    PORT
      LAYER M4 ;
        RECT  69.036 47.376 69.12 47.4 ;
    END
  END b_cfg_data[170]
  PIN b_cfg_data[171]
    DIRECTION OUTPUT ;
    USE SIGNAL ;
    PORT
      LAYER M4 ;
        RECT  69.036 47.472 69.12 47.496 ;
    END
  END b_cfg_data[171]
  PIN b_cfg_data[172]
    DIRECTION OUTPUT ;
    USE SIGNAL ;
    PORT
      LAYER M4 ;
        RECT  69.036 47.568 69.12 47.592 ;
    END
  END b_cfg_data[172]
  PIN b_cfg_data[173]
    DIRECTION OUTPUT ;
    USE SIGNAL ;
    PORT
      LAYER M4 ;
        RECT  69.036 47.664 69.12 47.688 ;
    END
  END b_cfg_data[173]
  PIN b_cfg_data[174]
    DIRECTION OUTPUT ;
    USE SIGNAL ;
    PORT
      LAYER M4 ;
        RECT  69.036 47.76 69.12 47.784 ;
    END
  END b_cfg_data[174]
  PIN b_cfg_data[175]
    DIRECTION OUTPUT ;
    USE SIGNAL ;
    PORT
      LAYER M4 ;
        RECT  69.036 47.856 69.12 47.88 ;
    END
  END b_cfg_data[175]
  PIN b_cfg_data[176]
    DIRECTION OUTPUT ;
    USE SIGNAL ;
    PORT
      LAYER M4 ;
        RECT  69.036 47.952 69.12 47.976 ;
    END
  END b_cfg_data[176]
  PIN b_cfg_data[177]
    DIRECTION OUTPUT ;
    USE SIGNAL ;
    PORT
      LAYER M4 ;
        RECT  69.036 48.048 69.12 48.072 ;
    END
  END b_cfg_data[177]
  PIN b_cfg_data[178]
    DIRECTION OUTPUT ;
    USE SIGNAL ;
    PORT
      LAYER M4 ;
        RECT  69.036 48.144 69.12 48.168 ;
    END
  END b_cfg_data[178]
  PIN b_cfg_data[179]
    DIRECTION OUTPUT ;
    USE SIGNAL ;
    PORT
      LAYER M4 ;
        RECT  69.036 48.24 69.12 48.264 ;
    END
  END b_cfg_data[179]
  PIN b_cfg_data[17]
    DIRECTION OUTPUT ;
    USE SIGNAL ;
    PORT
      LAYER M4 ;
        RECT  69.036 28.848 69.12 28.872 ;
    END
  END b_cfg_data[17]
  PIN b_cfg_data[180]
    DIRECTION OUTPUT ;
    USE SIGNAL ;
    PORT
      LAYER M4 ;
        RECT  69.036 19.92 69.12 19.944 ;
    END
  END b_cfg_data[180]
  PIN b_cfg_data[181]
    DIRECTION OUTPUT ;
    USE SIGNAL ;
    PORT
      LAYER M4 ;
        RECT  69.036 20.016 69.12 20.04 ;
    END
  END b_cfg_data[181]
  PIN b_cfg_data[182]
    DIRECTION OUTPUT ;
    USE SIGNAL ;
    PORT
      LAYER M4 ;
        RECT  69.036 20.112 69.12 20.136 ;
    END
  END b_cfg_data[182]
  PIN b_cfg_data[183]
    DIRECTION OUTPUT ;
    USE SIGNAL ;
    PORT
      LAYER M4 ;
        RECT  69.036 20.208 69.12 20.232 ;
    END
  END b_cfg_data[183]
  PIN b_cfg_data[184]
    DIRECTION OUTPUT ;
    USE SIGNAL ;
    PORT
      LAYER M4 ;
        RECT  69.036 20.304 69.12 20.328 ;
    END
  END b_cfg_data[184]
  PIN b_cfg_data[185]
    DIRECTION OUTPUT ;
    USE SIGNAL ;
    PORT
      LAYER M4 ;
        RECT  69.036 20.4 69.12 20.424 ;
    END
  END b_cfg_data[185]
  PIN b_cfg_data[186]
    DIRECTION OUTPUT ;
    USE SIGNAL ;
    PORT
      LAYER M4 ;
        RECT  69.036 20.496 69.12 20.52 ;
    END
  END b_cfg_data[186]
  PIN b_cfg_data[187]
    DIRECTION OUTPUT ;
    USE SIGNAL ;
    PORT
      LAYER M4 ;
        RECT  69.036 20.592 69.12 20.616 ;
    END
  END b_cfg_data[187]
  PIN b_cfg_data[188]
    DIRECTION OUTPUT ;
    USE SIGNAL ;
    PORT
      LAYER M4 ;
        RECT  69.036 20.688 69.12 20.712 ;
    END
  END b_cfg_data[188]
  PIN b_cfg_data[189]
    DIRECTION OUTPUT ;
    USE SIGNAL ;
    PORT
      LAYER M4 ;
        RECT  69.036 20.784 69.12 20.808 ;
    END
  END b_cfg_data[189]
  PIN b_cfg_data[18]
    DIRECTION OUTPUT ;
    USE SIGNAL ;
    PORT
      LAYER M4 ;
        RECT  69.036 28.944 69.12 28.968 ;
    END
  END b_cfg_data[18]
  PIN b_cfg_data[190]
    DIRECTION OUTPUT ;
    USE SIGNAL ;
    PORT
      LAYER M4 ;
        RECT  69.036 20.88 69.12 20.904 ;
    END
  END b_cfg_data[190]
  PIN b_cfg_data[191]
    DIRECTION OUTPUT ;
    USE SIGNAL ;
    PORT
      LAYER M4 ;
        RECT  69.036 20.976 69.12 21 ;
    END
  END b_cfg_data[191]
  PIN b_cfg_data[192]
    DIRECTION OUTPUT ;
    USE SIGNAL ;
    PORT
      LAYER M4 ;
        RECT  69.036 21.072 69.12 21.096 ;
    END
  END b_cfg_data[192]
  PIN b_cfg_data[193]
    DIRECTION OUTPUT ;
    USE SIGNAL ;
    PORT
      LAYER M4 ;
        RECT  69.036 21.168 69.12 21.192 ;
    END
  END b_cfg_data[193]
  PIN b_cfg_data[194]
    DIRECTION OUTPUT ;
    USE SIGNAL ;
    PORT
      LAYER M4 ;
        RECT  69.036 21.264 69.12 21.288 ;
    END
  END b_cfg_data[194]
  PIN b_cfg_data[195]
    DIRECTION OUTPUT ;
    USE SIGNAL ;
    PORT
      LAYER M4 ;
        RECT  69.036 21.36 69.12 21.384 ;
    END
  END b_cfg_data[195]
  PIN b_cfg_data[196]
    DIRECTION OUTPUT ;
    USE SIGNAL ;
    PORT
      LAYER M4 ;
        RECT  69.036 21.456 69.12 21.48 ;
    END
  END b_cfg_data[196]
  PIN b_cfg_data[197]
    DIRECTION OUTPUT ;
    USE SIGNAL ;
    PORT
      LAYER M4 ;
        RECT  69.036 21.552 69.12 21.576 ;
    END
  END b_cfg_data[197]
  PIN b_cfg_data[198]
    DIRECTION OUTPUT ;
    USE SIGNAL ;
    PORT
      LAYER M4 ;
        RECT  69.036 21.648 69.12 21.672 ;
    END
  END b_cfg_data[198]
  PIN b_cfg_data[199]
    DIRECTION OUTPUT ;
    USE SIGNAL ;
    PORT
      LAYER M4 ;
        RECT  69.036 21.744 69.12 21.768 ;
    END
  END b_cfg_data[199]
  PIN b_cfg_data[19]
    DIRECTION OUTPUT ;
    USE SIGNAL ;
    PORT
      LAYER M4 ;
        RECT  69.036 29.04 69.12 29.064 ;
    END
  END b_cfg_data[19]
  PIN b_cfg_data[1]
    DIRECTION OUTPUT ;
    USE SIGNAL ;
    PORT
      LAYER M4 ;
        RECT  69.036 27.312 69.12 27.336 ;
    END
  END b_cfg_data[1]
  PIN b_cfg_data[200]
    DIRECTION OUTPUT ;
    USE SIGNAL ;
    PORT
      LAYER M4 ;
        RECT  69.036 21.84 69.12 21.864 ;
    END
  END b_cfg_data[200]
  PIN b_cfg_data[201]
    DIRECTION OUTPUT ;
    USE SIGNAL ;
    PORT
      LAYER M4 ;
        RECT  69.036 21.936 69.12 21.96 ;
    END
  END b_cfg_data[201]
  PIN b_cfg_data[202]
    DIRECTION OUTPUT ;
    USE SIGNAL ;
    PORT
      LAYER M4 ;
        RECT  69.036 22.032 69.12 22.056 ;
    END
  END b_cfg_data[202]
  PIN b_cfg_data[203]
    DIRECTION OUTPUT ;
    USE SIGNAL ;
    PORT
      LAYER M4 ;
        RECT  69.036 22.128 69.12 22.152 ;
    END
  END b_cfg_data[203]
  PIN b_cfg_data[204]
    DIRECTION OUTPUT ;
    USE SIGNAL ;
    PORT
      LAYER M4 ;
        RECT  69.036 22.224 69.12 22.248 ;
    END
  END b_cfg_data[204]
  PIN b_cfg_data[205]
    DIRECTION OUTPUT ;
    USE SIGNAL ;
    PORT
      LAYER M4 ;
        RECT  69.036 22.32 69.12 22.344 ;
    END
  END b_cfg_data[205]
  PIN b_cfg_data[206]
    DIRECTION OUTPUT ;
    USE SIGNAL ;
    PORT
      LAYER M4 ;
        RECT  69.036 22.416 69.12 22.44 ;
    END
  END b_cfg_data[206]
  PIN b_cfg_data[207]
    DIRECTION OUTPUT ;
    USE SIGNAL ;
    PORT
      LAYER M4 ;
        RECT  69.036 22.512 69.12 22.536 ;
    END
  END b_cfg_data[207]
  PIN b_cfg_data[208]
    DIRECTION OUTPUT ;
    USE SIGNAL ;
    PORT
      LAYER M4 ;
        RECT  69.036 22.608 69.12 22.632 ;
    END
  END b_cfg_data[208]
  PIN b_cfg_data[209]
    DIRECTION OUTPUT ;
    USE SIGNAL ;
    PORT
      LAYER M4 ;
        RECT  69.036 22.704 69.12 22.728 ;
    END
  END b_cfg_data[209]
  PIN b_cfg_data[20]
    DIRECTION OUTPUT ;
    USE SIGNAL ;
    PORT
      LAYER M4 ;
        RECT  69.036 32.208 69.12 32.232 ;
    END
  END b_cfg_data[20]
  PIN b_cfg_data[210]
    DIRECTION OUTPUT ;
    USE SIGNAL ;
    PORT
      LAYER M4 ;
        RECT  69.036 22.8 69.12 22.824 ;
    END
  END b_cfg_data[210]
  PIN b_cfg_data[211]
    DIRECTION OUTPUT ;
    USE SIGNAL ;
    PORT
      LAYER M4 ;
        RECT  69.036 22.896 69.12 22.92 ;
    END
  END b_cfg_data[211]
  PIN b_cfg_data[212]
    DIRECTION OUTPUT ;
    USE SIGNAL ;
    PORT
      LAYER M4 ;
        RECT  69.036 29.136 69.12 29.16 ;
    END
  END b_cfg_data[212]
  PIN b_cfg_data[213]
    DIRECTION OUTPUT ;
    USE SIGNAL ;
    PORT
      LAYER M4 ;
        RECT  69.036 29.232 69.12 29.256 ;
    END
  END b_cfg_data[213]
  PIN b_cfg_data[214]
    DIRECTION OUTPUT ;
    USE SIGNAL ;
    PORT
      LAYER M4 ;
        RECT  69.036 29.328 69.12 29.352 ;
    END
  END b_cfg_data[214]
  PIN b_cfg_data[215]
    DIRECTION OUTPUT ;
    USE SIGNAL ;
    PORT
      LAYER M4 ;
        RECT  69.036 29.424 69.12 29.448 ;
    END
  END b_cfg_data[215]
  PIN b_cfg_data[216]
    DIRECTION OUTPUT ;
    USE SIGNAL ;
    PORT
      LAYER M4 ;
        RECT  69.036 29.52 69.12 29.544 ;
    END
  END b_cfg_data[216]
  PIN b_cfg_data[217]
    DIRECTION OUTPUT ;
    USE SIGNAL ;
    PORT
      LAYER M4 ;
        RECT  69.036 29.616 69.12 29.64 ;
    END
  END b_cfg_data[217]
  PIN b_cfg_data[218]
    DIRECTION OUTPUT ;
    USE SIGNAL ;
    PORT
      LAYER M4 ;
        RECT  69.036 29.712 69.12 29.736 ;
    END
  END b_cfg_data[218]
  PIN b_cfg_data[219]
    DIRECTION OUTPUT ;
    USE SIGNAL ;
    PORT
      LAYER M4 ;
        RECT  69.036 29.808 69.12 29.832 ;
    END
  END b_cfg_data[219]
  PIN b_cfg_data[21]
    DIRECTION OUTPUT ;
    USE SIGNAL ;
    PORT
      LAYER M4 ;
        RECT  69.036 32.304 69.12 32.328 ;
    END
  END b_cfg_data[21]
  PIN b_cfg_data[220]
    DIRECTION OUTPUT ;
    USE SIGNAL ;
    PORT
      LAYER M4 ;
        RECT  69.036 29.904 69.12 29.928 ;
    END
  END b_cfg_data[220]
  PIN b_cfg_data[221]
    DIRECTION OUTPUT ;
    USE SIGNAL ;
    PORT
      LAYER M4 ;
        RECT  69.036 30 69.12 30.024 ;
    END
  END b_cfg_data[221]
  PIN b_cfg_data[222]
    DIRECTION OUTPUT ;
    USE SIGNAL ;
    PORT
      LAYER M4 ;
        RECT  69.036 30.096 69.12 30.12 ;
    END
  END b_cfg_data[222]
  PIN b_cfg_data[223]
    DIRECTION OUTPUT ;
    USE SIGNAL ;
    PORT
      LAYER M4 ;
        RECT  69.036 30.192 69.12 30.216 ;
    END
  END b_cfg_data[223]
  PIN b_cfg_data[224]
    DIRECTION OUTPUT ;
    USE SIGNAL ;
    PORT
      LAYER M4 ;
        RECT  69.036 30.288 69.12 30.312 ;
    END
  END b_cfg_data[224]
  PIN b_cfg_data[225]
    DIRECTION OUTPUT ;
    USE SIGNAL ;
    PORT
      LAYER M4 ;
        RECT  69.036 30.384 69.12 30.408 ;
    END
  END b_cfg_data[225]
  PIN b_cfg_data[226]
    DIRECTION OUTPUT ;
    USE SIGNAL ;
    PORT
      LAYER M4 ;
        RECT  69.036 30.48 69.12 30.504 ;
    END
  END b_cfg_data[226]
  PIN b_cfg_data[227]
    DIRECTION OUTPUT ;
    USE SIGNAL ;
    PORT
      LAYER M4 ;
        RECT  69.036 30.576 69.12 30.6 ;
    END
  END b_cfg_data[227]
  PIN b_cfg_data[228]
    DIRECTION OUTPUT ;
    USE SIGNAL ;
    PORT
      LAYER M4 ;
        RECT  69.036 30.672 69.12 30.696 ;
    END
  END b_cfg_data[228]
  PIN b_cfg_data[229]
    DIRECTION OUTPUT ;
    USE SIGNAL ;
    PORT
      LAYER M4 ;
        RECT  69.036 30.768 69.12 30.792 ;
    END
  END b_cfg_data[229]
  PIN b_cfg_data[22]
    DIRECTION OUTPUT ;
    USE SIGNAL ;
    PORT
      LAYER M4 ;
        RECT  69.036 32.4 69.12 32.424 ;
    END
  END b_cfg_data[22]
  PIN b_cfg_data[230]
    DIRECTION OUTPUT ;
    USE SIGNAL ;
    PORT
      LAYER M4 ;
        RECT  69.036 30.864 69.12 30.888 ;
    END
  END b_cfg_data[230]
  PIN b_cfg_data[231]
    DIRECTION OUTPUT ;
    USE SIGNAL ;
    PORT
      LAYER M4 ;
        RECT  69.036 30.96 69.12 30.984 ;
    END
  END b_cfg_data[231]
  PIN b_cfg_data[232]
    DIRECTION OUTPUT ;
    USE SIGNAL ;
    PORT
      LAYER M4 ;
        RECT  69.036 31.056 69.12 31.08 ;
    END
  END b_cfg_data[232]
  PIN b_cfg_data[233]
    DIRECTION OUTPUT ;
    USE SIGNAL ;
    PORT
      LAYER M4 ;
        RECT  69.036 31.152 69.12 31.176 ;
    END
  END b_cfg_data[233]
  PIN b_cfg_data[234]
    DIRECTION OUTPUT ;
    USE SIGNAL ;
    PORT
      LAYER M4 ;
        RECT  69.036 31.248 69.12 31.272 ;
    END
  END b_cfg_data[234]
  PIN b_cfg_data[235]
    DIRECTION OUTPUT ;
    USE SIGNAL ;
    PORT
      LAYER M4 ;
        RECT  69.036 31.344 69.12 31.368 ;
    END
  END b_cfg_data[235]
  PIN b_cfg_data[236]
    DIRECTION OUTPUT ;
    USE SIGNAL ;
    PORT
      LAYER M4 ;
        RECT  69.036 31.44 69.12 31.464 ;
    END
  END b_cfg_data[236]
  PIN b_cfg_data[237]
    DIRECTION OUTPUT ;
    USE SIGNAL ;
    PORT
      LAYER M4 ;
        RECT  69.036 31.536 69.12 31.56 ;
    END
  END b_cfg_data[237]
  PIN b_cfg_data[238]
    DIRECTION OUTPUT ;
    USE SIGNAL ;
    PORT
      LAYER M4 ;
        RECT  69.036 31.632 69.12 31.656 ;
    END
  END b_cfg_data[238]
  PIN b_cfg_data[239]
    DIRECTION OUTPUT ;
    USE SIGNAL ;
    PORT
      LAYER M4 ;
        RECT  69.036 31.728 69.12 31.752 ;
    END
  END b_cfg_data[239]
  PIN b_cfg_data[23]
    DIRECTION OUTPUT ;
    USE SIGNAL ;
    PORT
      LAYER M4 ;
        RECT  69.036 32.496 69.12 32.52 ;
    END
  END b_cfg_data[23]
  PIN b_cfg_data[240]
    DIRECTION OUTPUT ;
    USE SIGNAL ;
    PORT
      LAYER M4 ;
        RECT  69.036 31.824 69.12 31.848 ;
    END
  END b_cfg_data[240]
  PIN b_cfg_data[241]
    DIRECTION OUTPUT ;
    USE SIGNAL ;
    PORT
      LAYER M4 ;
        RECT  69.036 31.92 69.12 31.944 ;
    END
  END b_cfg_data[241]
  PIN b_cfg_data[242]
    DIRECTION OUTPUT ;
    USE SIGNAL ;
    PORT
      LAYER M4 ;
        RECT  69.036 32.016 69.12 32.04 ;
    END
  END b_cfg_data[242]
  PIN b_cfg_data[243]
    DIRECTION OUTPUT ;
    USE SIGNAL ;
    PORT
      LAYER M4 ;
        RECT  69.036 32.112 69.12 32.136 ;
    END
  END b_cfg_data[243]
  PIN b_cfg_data[244]
    DIRECTION OUTPUT ;
    USE SIGNAL ;
    PORT
      LAYER M4 ;
        RECT  69.036 48.336 69.12 48.36 ;
    END
  END b_cfg_data[244]
  PIN b_cfg_data[245]
    DIRECTION OUTPUT ;
    USE SIGNAL ;
    PORT
      LAYER M4 ;
        RECT  69.036 48.432 69.12 48.456 ;
    END
  END b_cfg_data[245]
  PIN b_cfg_data[246]
    DIRECTION OUTPUT ;
    USE SIGNAL ;
    PORT
      LAYER M4 ;
        RECT  69.036 48.528 69.12 48.552 ;
    END
  END b_cfg_data[246]
  PIN b_cfg_data[247]
    DIRECTION OUTPUT ;
    USE SIGNAL ;
    PORT
      LAYER M4 ;
        RECT  69.036 48.624 69.12 48.648 ;
    END
  END b_cfg_data[247]
  PIN b_cfg_data[248]
    DIRECTION OUTPUT ;
    USE SIGNAL ;
    PORT
      LAYER M4 ;
        RECT  69.036 48.72 69.12 48.744 ;
    END
  END b_cfg_data[248]
  PIN b_cfg_data[249]
    DIRECTION OUTPUT ;
    USE SIGNAL ;
    PORT
      LAYER M4 ;
        RECT  69.036 48.816 69.12 48.84 ;
    END
  END b_cfg_data[249]
  PIN b_cfg_data[24]
    DIRECTION OUTPUT ;
    USE SIGNAL ;
    PORT
      LAYER M4 ;
        RECT  69.036 32.592 69.12 32.616 ;
    END
  END b_cfg_data[24]
  PIN b_cfg_data[250]
    DIRECTION OUTPUT ;
    USE SIGNAL ;
    PORT
      LAYER M4 ;
        RECT  69.036 48.912 69.12 48.936 ;
    END
  END b_cfg_data[250]
  PIN b_cfg_data[251]
    DIRECTION OUTPUT ;
    USE SIGNAL ;
    PORT
      LAYER M4 ;
        RECT  69.036 49.008 69.12 49.032 ;
    END
  END b_cfg_data[251]
  PIN b_cfg_data[252]
    DIRECTION OUTPUT ;
    USE SIGNAL ;
    PORT
      LAYER M4 ;
        RECT  69.036 49.104 69.12 49.128 ;
    END
  END b_cfg_data[252]
  PIN b_cfg_data[253]
    DIRECTION OUTPUT ;
    USE SIGNAL ;
    PORT
      LAYER M4 ;
        RECT  69.036 49.2 69.12 49.224 ;
    END
  END b_cfg_data[253]
  PIN b_cfg_data[254]
    DIRECTION OUTPUT ;
    USE SIGNAL ;
    PORT
      LAYER M4 ;
        RECT  69.036 49.296 69.12 49.32 ;
    END
  END b_cfg_data[254]
  PIN b_cfg_data[255]
    DIRECTION OUTPUT ;
    USE SIGNAL ;
    PORT
      LAYER M4 ;
        RECT  69.036 49.392 69.12 49.416 ;
    END
  END b_cfg_data[255]
  PIN b_cfg_data[25]
    DIRECTION OUTPUT ;
    USE SIGNAL ;
    PORT
      LAYER M4 ;
        RECT  69.036 32.688 69.12 32.712 ;
    END
  END b_cfg_data[25]
  PIN b_cfg_data[26]
    DIRECTION OUTPUT ;
    USE SIGNAL ;
    PORT
      LAYER M4 ;
        RECT  69.036 32.784 69.12 32.808 ;
    END
  END b_cfg_data[26]
  PIN b_cfg_data[27]
    DIRECTION OUTPUT ;
    USE SIGNAL ;
    PORT
      LAYER M4 ;
        RECT  69.036 32.88 69.12 32.904 ;
    END
  END b_cfg_data[27]
  PIN b_cfg_data[28]
    DIRECTION OUTPUT ;
    USE SIGNAL ;
    PORT
      LAYER M4 ;
        RECT  69.036 32.976 69.12 33 ;
    END
  END b_cfg_data[28]
  PIN b_cfg_data[29]
    DIRECTION OUTPUT ;
    USE SIGNAL ;
    PORT
      LAYER M4 ;
        RECT  69.036 33.072 69.12 33.096 ;
    END
  END b_cfg_data[29]
  PIN b_cfg_data[2]
    DIRECTION OUTPUT ;
    USE SIGNAL ;
    PORT
      LAYER M4 ;
        RECT  69.036 27.408 69.12 27.432 ;
    END
  END b_cfg_data[2]
  PIN b_cfg_data[30]
    DIRECTION OUTPUT ;
    USE SIGNAL ;
    PORT
      LAYER M4 ;
        RECT  69.036 33.168 69.12 33.192 ;
    END
  END b_cfg_data[30]
  PIN b_cfg_data[31]
    DIRECTION OUTPUT ;
    USE SIGNAL ;
    PORT
      LAYER M4 ;
        RECT  69.036 33.264 69.12 33.288 ;
    END
  END b_cfg_data[31]
  PIN b_cfg_data[32]
    DIRECTION OUTPUT ;
    USE SIGNAL ;
    PORT
      LAYER M4 ;
        RECT  69.036 33.36 69.12 33.384 ;
    END
  END b_cfg_data[32]
  PIN b_cfg_data[33]
    DIRECTION OUTPUT ;
    USE SIGNAL ;
    PORT
      LAYER M4 ;
        RECT  69.036 33.456 69.12 33.48 ;
    END
  END b_cfg_data[33]
  PIN b_cfg_data[34]
    DIRECTION OUTPUT ;
    USE SIGNAL ;
    PORT
      LAYER M4 ;
        RECT  69.036 33.552 69.12 33.576 ;
    END
  END b_cfg_data[34]
  PIN b_cfg_data[35]
    DIRECTION OUTPUT ;
    USE SIGNAL ;
    PORT
      LAYER M4 ;
        RECT  69.036 33.648 69.12 33.672 ;
    END
  END b_cfg_data[35]
  PIN b_cfg_data[36]
    DIRECTION OUTPUT ;
    USE SIGNAL ;
    PORT
      LAYER M4 ;
        RECT  69.036 33.744 69.12 33.768 ;
    END
  END b_cfg_data[36]
  PIN b_cfg_data[37]
    DIRECTION OUTPUT ;
    USE SIGNAL ;
    PORT
      LAYER M4 ;
        RECT  69.036 33.84 69.12 33.864 ;
    END
  END b_cfg_data[37]
  PIN b_cfg_data[38]
    DIRECTION OUTPUT ;
    USE SIGNAL ;
    PORT
      LAYER M4 ;
        RECT  69.036 33.936 69.12 33.96 ;
    END
  END b_cfg_data[38]
  PIN b_cfg_data[39]
    DIRECTION OUTPUT ;
    USE SIGNAL ;
    PORT
      LAYER M4 ;
        RECT  69.036 34.032 69.12 34.056 ;
    END
  END b_cfg_data[39]
  PIN b_cfg_data[3]
    DIRECTION OUTPUT ;
    USE SIGNAL ;
    PORT
      LAYER M4 ;
        RECT  69.036 27.504 69.12 27.528 ;
    END
  END b_cfg_data[3]
  PIN b_cfg_data[40]
    DIRECTION OUTPUT ;
    USE SIGNAL ;
    PORT
      LAYER M4 ;
        RECT  69.036 34.128 69.12 34.152 ;
    END
  END b_cfg_data[40]
  PIN b_cfg_data[41]
    DIRECTION OUTPUT ;
    USE SIGNAL ;
    PORT
      LAYER M4 ;
        RECT  69.036 34.224 69.12 34.248 ;
    END
  END b_cfg_data[41]
  PIN b_cfg_data[42]
    DIRECTION OUTPUT ;
    USE SIGNAL ;
    PORT
      LAYER M4 ;
        RECT  69.036 34.32 69.12 34.344 ;
    END
  END b_cfg_data[42]
  PIN b_cfg_data[43]
    DIRECTION OUTPUT ;
    USE SIGNAL ;
    PORT
      LAYER M4 ;
        RECT  69.036 34.416 69.12 34.44 ;
    END
  END b_cfg_data[43]
  PIN b_cfg_data[44]
    DIRECTION OUTPUT ;
    USE SIGNAL ;
    PORT
      LAYER M4 ;
        RECT  69.036 34.512 69.12 34.536 ;
    END
  END b_cfg_data[44]
  PIN b_cfg_data[45]
    DIRECTION OUTPUT ;
    USE SIGNAL ;
    PORT
      LAYER M4 ;
        RECT  69.036 34.608 69.12 34.632 ;
    END
  END b_cfg_data[45]
  PIN b_cfg_data[46]
    DIRECTION OUTPUT ;
    USE SIGNAL ;
    PORT
      LAYER M4 ;
        RECT  69.036 34.704 69.12 34.728 ;
    END
  END b_cfg_data[46]
  PIN b_cfg_data[47]
    DIRECTION OUTPUT ;
    USE SIGNAL ;
    PORT
      LAYER M4 ;
        RECT  69.036 34.8 69.12 34.824 ;
    END
  END b_cfg_data[47]
  PIN b_cfg_data[48]
    DIRECTION OUTPUT ;
    USE SIGNAL ;
    PORT
      LAYER M4 ;
        RECT  69.036 34.896 69.12 34.92 ;
    END
  END b_cfg_data[48]
  PIN b_cfg_data[49]
    DIRECTION OUTPUT ;
    USE SIGNAL ;
    PORT
      LAYER M4 ;
        RECT  69.036 34.992 69.12 35.016 ;
    END
  END b_cfg_data[49]
  PIN b_cfg_data[4]
    DIRECTION OUTPUT ;
    USE SIGNAL ;
    PORT
      LAYER M4 ;
        RECT  69.036 27.6 69.12 27.624 ;
    END
  END b_cfg_data[4]
  PIN b_cfg_data[50]
    DIRECTION OUTPUT ;
    USE SIGNAL ;
    PORT
      LAYER M4 ;
        RECT  69.036 35.088 69.12 35.112 ;
    END
  END b_cfg_data[50]
  PIN b_cfg_data[51]
    DIRECTION OUTPUT ;
    USE SIGNAL ;
    PORT
      LAYER M4 ;
        RECT  69.036 35.184 69.12 35.208 ;
    END
  END b_cfg_data[51]
  PIN b_cfg_data[52]
    DIRECTION OUTPUT ;
    USE SIGNAL ;
    PORT
      LAYER M4 ;
        RECT  69.036 22.992 69.12 23.016 ;
    END
  END b_cfg_data[52]
  PIN b_cfg_data[53]
    DIRECTION OUTPUT ;
    USE SIGNAL ;
    PORT
      LAYER M4 ;
        RECT  69.036 23.088 69.12 23.112 ;
    END
  END b_cfg_data[53]
  PIN b_cfg_data[54]
    DIRECTION OUTPUT ;
    USE SIGNAL ;
    PORT
      LAYER M4 ;
        RECT  69.036 23.184 69.12 23.208 ;
    END
  END b_cfg_data[54]
  PIN b_cfg_data[55]
    DIRECTION OUTPUT ;
    USE SIGNAL ;
    PORT
      LAYER M4 ;
        RECT  69.036 23.28 69.12 23.304 ;
    END
  END b_cfg_data[55]
  PIN b_cfg_data[56]
    DIRECTION OUTPUT ;
    USE SIGNAL ;
    PORT
      LAYER M4 ;
        RECT  69.036 23.376 69.12 23.4 ;
    END
  END b_cfg_data[56]
  PIN b_cfg_data[57]
    DIRECTION OUTPUT ;
    USE SIGNAL ;
    PORT
      LAYER M4 ;
        RECT  69.036 23.472 69.12 23.496 ;
    END
  END b_cfg_data[57]
  PIN b_cfg_data[58]
    DIRECTION OUTPUT ;
    USE SIGNAL ;
    PORT
      LAYER M4 ;
        RECT  69.036 23.568 69.12 23.592 ;
    END
  END b_cfg_data[58]
  PIN b_cfg_data[59]
    DIRECTION OUTPUT ;
    USE SIGNAL ;
    PORT
      LAYER M4 ;
        RECT  69.036 23.664 69.12 23.688 ;
    END
  END b_cfg_data[59]
  PIN b_cfg_data[5]
    DIRECTION OUTPUT ;
    USE SIGNAL ;
    PORT
      LAYER M4 ;
        RECT  69.036 27.696 69.12 27.72 ;
    END
  END b_cfg_data[5]
  PIN b_cfg_data[60]
    DIRECTION OUTPUT ;
    USE SIGNAL ;
    PORT
      LAYER M4 ;
        RECT  69.036 23.76 69.12 23.784 ;
    END
  END b_cfg_data[60]
  PIN b_cfg_data[61]
    DIRECTION OUTPUT ;
    USE SIGNAL ;
    PORT
      LAYER M4 ;
        RECT  69.036 23.856 69.12 23.88 ;
    END
  END b_cfg_data[61]
  PIN b_cfg_data[62]
    DIRECTION OUTPUT ;
    USE SIGNAL ;
    PORT
      LAYER M4 ;
        RECT  69.036 23.952 69.12 23.976 ;
    END
  END b_cfg_data[62]
  PIN b_cfg_data[63]
    DIRECTION OUTPUT ;
    USE SIGNAL ;
    PORT
      LAYER M4 ;
        RECT  69.036 24.048 69.12 24.072 ;
    END
  END b_cfg_data[63]
  PIN b_cfg_data[64]
    DIRECTION OUTPUT ;
    USE SIGNAL ;
    PORT
      LAYER M4 ;
        RECT  69.036 24.144 69.12 24.168 ;
    END
  END b_cfg_data[64]
  PIN b_cfg_data[65]
    DIRECTION OUTPUT ;
    USE SIGNAL ;
    PORT
      LAYER M4 ;
        RECT  69.036 24.24 69.12 24.264 ;
    END
  END b_cfg_data[65]
  PIN b_cfg_data[66]
    DIRECTION OUTPUT ;
    USE SIGNAL ;
    PORT
      LAYER M4 ;
        RECT  69.036 24.336 69.12 24.36 ;
    END
  END b_cfg_data[66]
  PIN b_cfg_data[67]
    DIRECTION OUTPUT ;
    USE SIGNAL ;
    PORT
      LAYER M4 ;
        RECT  69.036 24.432 69.12 24.456 ;
    END
  END b_cfg_data[67]
  PIN b_cfg_data[68]
    DIRECTION OUTPUT ;
    USE SIGNAL ;
    PORT
      LAYER M4 ;
        RECT  69.036 24.528 69.12 24.552 ;
    END
  END b_cfg_data[68]
  PIN b_cfg_data[69]
    DIRECTION OUTPUT ;
    USE SIGNAL ;
    PORT
      LAYER M4 ;
        RECT  69.036 24.624 69.12 24.648 ;
    END
  END b_cfg_data[69]
  PIN b_cfg_data[6]
    DIRECTION OUTPUT ;
    USE SIGNAL ;
    PORT
      LAYER M4 ;
        RECT  69.036 27.792 69.12 27.816 ;
    END
  END b_cfg_data[6]
  PIN b_cfg_data[70]
    DIRECTION OUTPUT ;
    USE SIGNAL ;
    PORT
      LAYER M4 ;
        RECT  69.036 24.72 69.12 24.744 ;
    END
  END b_cfg_data[70]
  PIN b_cfg_data[71]
    DIRECTION OUTPUT ;
    USE SIGNAL ;
    PORT
      LAYER M4 ;
        RECT  69.036 24.816 69.12 24.84 ;
    END
  END b_cfg_data[71]
  PIN b_cfg_data[72]
    DIRECTION OUTPUT ;
    USE SIGNAL ;
    PORT
      LAYER M4 ;
        RECT  69.036 24.912 69.12 24.936 ;
    END
  END b_cfg_data[72]
  PIN b_cfg_data[73]
    DIRECTION OUTPUT ;
    USE SIGNAL ;
    PORT
      LAYER M4 ;
        RECT  69.036 25.008 69.12 25.032 ;
    END
  END b_cfg_data[73]
  PIN b_cfg_data[74]
    DIRECTION OUTPUT ;
    USE SIGNAL ;
    PORT
      LAYER M4 ;
        RECT  69.036 25.104 69.12 25.128 ;
    END
  END b_cfg_data[74]
  PIN b_cfg_data[75]
    DIRECTION OUTPUT ;
    USE SIGNAL ;
    PORT
      LAYER M4 ;
        RECT  69.036 25.2 69.12 25.224 ;
    END
  END b_cfg_data[75]
  PIN b_cfg_data[76]
    DIRECTION OUTPUT ;
    USE SIGNAL ;
    PORT
      LAYER M4 ;
        RECT  69.036 25.296 69.12 25.32 ;
    END
  END b_cfg_data[76]
  PIN b_cfg_data[77]
    DIRECTION OUTPUT ;
    USE SIGNAL ;
    PORT
      LAYER M4 ;
        RECT  69.036 25.392 69.12 25.416 ;
    END
  END b_cfg_data[77]
  PIN b_cfg_data[78]
    DIRECTION OUTPUT ;
    USE SIGNAL ;
    PORT
      LAYER M4 ;
        RECT  69.036 25.488 69.12 25.512 ;
    END
  END b_cfg_data[78]
  PIN b_cfg_data[79]
    DIRECTION OUTPUT ;
    USE SIGNAL ;
    PORT
      LAYER M4 ;
        RECT  69.036 25.584 69.12 25.608 ;
    END
  END b_cfg_data[79]
  PIN b_cfg_data[7]
    DIRECTION OUTPUT ;
    USE SIGNAL ;
    PORT
      LAYER M4 ;
        RECT  69.036 27.888 69.12 27.912 ;
    END
  END b_cfg_data[7]
  PIN b_cfg_data[80]
    DIRECTION OUTPUT ;
    USE SIGNAL ;
    PORT
      LAYER M4 ;
        RECT  69.036 25.68 69.12 25.704 ;
    END
  END b_cfg_data[80]
  PIN b_cfg_data[81]
    DIRECTION OUTPUT ;
    USE SIGNAL ;
    PORT
      LAYER M4 ;
        RECT  69.036 25.776 69.12 25.8 ;
    END
  END b_cfg_data[81]
  PIN b_cfg_data[82]
    DIRECTION OUTPUT ;
    USE SIGNAL ;
    PORT
      LAYER M4 ;
        RECT  69.036 25.872 69.12 25.896 ;
    END
  END b_cfg_data[82]
  PIN b_cfg_data[83]
    DIRECTION OUTPUT ;
    USE SIGNAL ;
    PORT
      LAYER M4 ;
        RECT  69.036 25.968 69.12 25.992 ;
    END
  END b_cfg_data[83]
  PIN b_cfg_data[84]
    DIRECTION OUTPUT ;
    USE SIGNAL ;
    PORT
      LAYER M4 ;
        RECT  69.036 42.192 69.12 42.216 ;
    END
  END b_cfg_data[84]
  PIN b_cfg_data[85]
    DIRECTION OUTPUT ;
    USE SIGNAL ;
    PORT
      LAYER M4 ;
        RECT  69.036 42.288 69.12 42.312 ;
    END
  END b_cfg_data[85]
  PIN b_cfg_data[86]
    DIRECTION OUTPUT ;
    USE SIGNAL ;
    PORT
      LAYER M4 ;
        RECT  69.036 42.384 69.12 42.408 ;
    END
  END b_cfg_data[86]
  PIN b_cfg_data[87]
    DIRECTION OUTPUT ;
    USE SIGNAL ;
    PORT
      LAYER M4 ;
        RECT  69.036 42.48 69.12 42.504 ;
    END
  END b_cfg_data[87]
  PIN b_cfg_data[88]
    DIRECTION OUTPUT ;
    USE SIGNAL ;
    PORT
      LAYER M4 ;
        RECT  69.036 42.576 69.12 42.6 ;
    END
  END b_cfg_data[88]
  PIN b_cfg_data[89]
    DIRECTION OUTPUT ;
    USE SIGNAL ;
    PORT
      LAYER M4 ;
        RECT  69.036 42.672 69.12 42.696 ;
    END
  END b_cfg_data[89]
  PIN b_cfg_data[8]
    DIRECTION OUTPUT ;
    USE SIGNAL ;
    PORT
      LAYER M4 ;
        RECT  69.036 27.984 69.12 28.008 ;
    END
  END b_cfg_data[8]
  PIN b_cfg_data[90]
    DIRECTION OUTPUT ;
    USE SIGNAL ;
    PORT
      LAYER M4 ;
        RECT  69.036 42.768 69.12 42.792 ;
    END
  END b_cfg_data[90]
  PIN b_cfg_data[91]
    DIRECTION OUTPUT ;
    USE SIGNAL ;
    PORT
      LAYER M4 ;
        RECT  69.036 42.864 69.12 42.888 ;
    END
  END b_cfg_data[91]
  PIN b_cfg_data[92]
    DIRECTION OUTPUT ;
    USE SIGNAL ;
    PORT
      LAYER M4 ;
        RECT  69.036 42.96 69.12 42.984 ;
    END
  END b_cfg_data[92]
  PIN b_cfg_data[93]
    DIRECTION OUTPUT ;
    USE SIGNAL ;
    PORT
      LAYER M4 ;
        RECT  69.036 43.056 69.12 43.08 ;
    END
  END b_cfg_data[93]
  PIN b_cfg_data[94]
    DIRECTION OUTPUT ;
    USE SIGNAL ;
    PORT
      LAYER M4 ;
        RECT  69.036 43.152 69.12 43.176 ;
    END
  END b_cfg_data[94]
  PIN b_cfg_data[95]
    DIRECTION OUTPUT ;
    USE SIGNAL ;
    PORT
      LAYER M4 ;
        RECT  69.036 43.248 69.12 43.272 ;
    END
  END b_cfg_data[95]
  PIN b_cfg_data[96]
    DIRECTION OUTPUT ;
    USE SIGNAL ;
    PORT
      LAYER M4 ;
        RECT  69.036 43.344 69.12 43.368 ;
    END
  END b_cfg_data[96]
  PIN b_cfg_data[97]
    DIRECTION OUTPUT ;
    USE SIGNAL ;
    PORT
      LAYER M4 ;
        RECT  69.036 43.44 69.12 43.464 ;
    END
  END b_cfg_data[97]
  PIN b_cfg_data[98]
    DIRECTION OUTPUT ;
    USE SIGNAL ;
    PORT
      LAYER M4 ;
        RECT  69.036 43.536 69.12 43.56 ;
    END
  END b_cfg_data[98]
  PIN b_cfg_data[99]
    DIRECTION OUTPUT ;
    USE SIGNAL ;
    PORT
      LAYER M4 ;
        RECT  69.036 43.632 69.12 43.656 ;
    END
  END b_cfg_data[99]
  PIN b_cfg_data[9]
    DIRECTION OUTPUT ;
    USE SIGNAL ;
    PORT
      LAYER M4 ;
        RECT  69.036 28.08 69.12 28.104 ;
    END
  END b_cfg_data[9]
  PIN b_cfg_target[0]
    DIRECTION OUTPUT ;
    USE SIGNAL ;
    PORT
      LAYER M4 ;
        RECT  69.036 49.488 69.12 49.512 ;
    END
  END b_cfg_target[0]
  PIN b_cfg_target[1]
    DIRECTION OUTPUT ;
    USE SIGNAL ;
    PORT
      LAYER M4 ;
        RECT  69.036 49.584 69.12 49.608 ;
    END
  END b_cfg_target[1]
  PIN b_cfg_target[2]
    DIRECTION OUTPUT ;
    USE SIGNAL ;
    PORT
      LAYER M4 ;
        RECT  69.036 49.68 69.12 49.704 ;
    END
  END b_cfg_target[2]
  PIN b_cfg_target[3]
    DIRECTION OUTPUT ;
    USE SIGNAL ;
    PORT
      LAYER M4 ;
        RECT  69.036 49.776 69.12 49.8 ;
    END
  END b_cfg_target[3]
  PIN b_cfg_target[4]
    DIRECTION OUTPUT ;
    USE SIGNAL ;
    PORT
      LAYER M4 ;
        RECT  69.036 49.872 69.12 49.896 ;
    END
  END b_cfg_target[4]
  PIN b_cfg_target[5]
    DIRECTION OUTPUT ;
    USE SIGNAL ;
    PORT
      LAYER M4 ;
        RECT  69.036 49.968 69.12 49.992 ;
    END
  END b_cfg_target[5]
  PIN b_cfg_target[6]
    DIRECTION OUTPUT ;
    USE SIGNAL ;
    PORT
      LAYER M4 ;
        RECT  69.036 50.064 69.12 50.088 ;
    END
  END b_cfg_target[6]
  PIN b_cfg_target[7]
    DIRECTION OUTPUT ;
    USE SIGNAL ;
    PORT
      LAYER M4 ;
        RECT  69.036 50.16 69.12 50.184 ;
    END
  END b_cfg_target[7]
  PIN b_cfg_v
    DIRECTION OUTPUT ;
    USE SIGNAL ;
    PORT
      LAYER M4 ;
        RECT  69.036 50.256 69.12 50.28 ;
    END
  END b_cfg_v
  PIN b_desc_base[0]
    DIRECTION OUTPUT ;
    USE SIGNAL ;
    PORT
      LAYER M4 ;
        RECT  69.036 50.352 69.12 50.376 ;
    END
  END b_desc_base[0]
  PIN b_desc_base[10]
    DIRECTION OUTPUT ;
    USE SIGNAL ;
    PORT
      LAYER M4 ;
        RECT  69.036 51.312 69.12 51.336 ;
    END
  END b_desc_base[10]
  PIN b_desc_base[11]
    DIRECTION OUTPUT ;
    USE SIGNAL ;
    PORT
      LAYER M4 ;
        RECT  69.036 39.12 69.12 39.144 ;
    END
  END b_desc_base[11]
  PIN b_desc_base[1]
    DIRECTION OUTPUT ;
    USE SIGNAL ;
    PORT
      LAYER M4 ;
        RECT  69.036 50.448 69.12 50.472 ;
    END
  END b_desc_base[1]
  PIN b_desc_base[2]
    DIRECTION OUTPUT ;
    USE SIGNAL ;
    PORT
      LAYER M4 ;
        RECT  69.036 50.544 69.12 50.568 ;
    END
  END b_desc_base[2]
  PIN b_desc_base[3]
    DIRECTION OUTPUT ;
    USE SIGNAL ;
    PORT
      LAYER M4 ;
        RECT  69.036 50.64 69.12 50.664 ;
    END
  END b_desc_base[3]
  PIN b_desc_base[4]
    DIRECTION OUTPUT ;
    USE SIGNAL ;
    PORT
      LAYER M4 ;
        RECT  69.036 50.736 69.12 50.76 ;
    END
  END b_desc_base[4]
  PIN b_desc_base[5]
    DIRECTION OUTPUT ;
    USE SIGNAL ;
    PORT
      LAYER M4 ;
        RECT  69.036 50.832 69.12 50.856 ;
    END
  END b_desc_base[5]
  PIN b_desc_base[6]
    DIRECTION OUTPUT ;
    USE SIGNAL ;
    PORT
      LAYER M4 ;
        RECT  69.036 50.928 69.12 50.952 ;
    END
  END b_desc_base[6]
  PIN b_desc_base[7]
    DIRECTION OUTPUT ;
    USE SIGNAL ;
    PORT
      LAYER M4 ;
        RECT  69.036 51.024 69.12 51.048 ;
    END
  END b_desc_base[7]
  PIN b_desc_base[8]
    DIRECTION OUTPUT ;
    USE SIGNAL ;
    PORT
      LAYER M4 ;
        RECT  69.036 51.12 69.12 51.144 ;
    END
  END b_desc_base[8]
  PIN b_desc_base[9]
    DIRECTION OUTPUT ;
    USE SIGNAL ;
    PORT
      LAYER M4 ;
        RECT  69.036 51.216 69.12 51.24 ;
    END
  END b_desc_base[9]
  PIN b_desc_limit[0]
    DIRECTION OUTPUT ;
    USE SIGNAL ;
    PORT
      LAYER M4 ;
        RECT  69.036 39.216 69.12 39.24 ;
    END
  END b_desc_limit[0]
  PIN b_desc_limit[10]
    DIRECTION OUTPUT ;
    USE SIGNAL ;
    PORT
      LAYER M4 ;
        RECT  69.036 40.176 69.12 40.2 ;
    END
  END b_desc_limit[10]
  PIN b_desc_limit[11]
    DIRECTION OUTPUT ;
    USE SIGNAL ;
    PORT
      LAYER M4 ;
        RECT  69.036 40.272 69.12 40.296 ;
    END
  END b_desc_limit[11]
  PIN b_desc_limit[12]
    DIRECTION OUTPUT ;
    USE SIGNAL ;
    PORT
      LAYER M4 ;
        RECT  69.036 40.368 69.12 40.392 ;
    END
  END b_desc_limit[12]
  PIN b_desc_limit[1]
    DIRECTION OUTPUT ;
    USE SIGNAL ;
    PORT
      LAYER M4 ;
        RECT  69.036 39.312 69.12 39.336 ;
    END
  END b_desc_limit[1]
  PIN b_desc_limit[2]
    DIRECTION OUTPUT ;
    USE SIGNAL ;
    PORT
      LAYER M4 ;
        RECT  69.036 39.408 69.12 39.432 ;
    END
  END b_desc_limit[2]
  PIN b_desc_limit[3]
    DIRECTION OUTPUT ;
    USE SIGNAL ;
    PORT
      LAYER M4 ;
        RECT  69.036 39.504 69.12 39.528 ;
    END
  END b_desc_limit[3]
  PIN b_desc_limit[4]
    DIRECTION OUTPUT ;
    USE SIGNAL ;
    PORT
      LAYER M4 ;
        RECT  69.036 39.6 69.12 39.624 ;
    END
  END b_desc_limit[4]
  PIN b_desc_limit[5]
    DIRECTION OUTPUT ;
    USE SIGNAL ;
    PORT
      LAYER M4 ;
        RECT  69.036 39.696 69.12 39.72 ;
    END
  END b_desc_limit[5]
  PIN b_desc_limit[6]
    DIRECTION OUTPUT ;
    USE SIGNAL ;
    PORT
      LAYER M4 ;
        RECT  69.036 39.792 69.12 39.816 ;
    END
  END b_desc_limit[6]
  PIN b_desc_limit[7]
    DIRECTION OUTPUT ;
    USE SIGNAL ;
    PORT
      LAYER M4 ;
        RECT  69.036 39.888 69.12 39.912 ;
    END
  END b_desc_limit[7]
  PIN b_desc_limit[8]
    DIRECTION OUTPUT ;
    USE SIGNAL ;
    PORT
      LAYER M4 ;
        RECT  69.036 39.984 69.12 40.008 ;
    END
  END b_desc_limit[8]
  PIN b_desc_limit[9]
    DIRECTION OUTPUT ;
    USE SIGNAL ;
    PORT
      LAYER M4 ;
        RECT  69.036 40.08 69.12 40.104 ;
    END
  END b_desc_limit[9]
  PIN b_desc_loops[0]
    DIRECTION OUTPUT ;
    USE SIGNAL ;
    PORT
      LAYER M4 ;
        RECT  69.036 40.464 69.12 40.488 ;
    END
  END b_desc_loops[0]
  PIN b_desc_loops[10]
    DIRECTION OUTPUT ;
    USE SIGNAL ;
    PORT
      LAYER M4 ;
        RECT  69.036 41.424 69.12 41.448 ;
    END
  END b_desc_loops[10]
  PIN b_desc_loops[11]
    DIRECTION OUTPUT ;
    USE SIGNAL ;
    PORT
      LAYER M4 ;
        RECT  69.036 41.52 69.12 41.544 ;
    END
  END b_desc_loops[11]
  PIN b_desc_loops[12]
    DIRECTION OUTPUT ;
    USE SIGNAL ;
    PORT
      LAYER M4 ;
        RECT  69.036 41.616 69.12 41.64 ;
    END
  END b_desc_loops[12]
  PIN b_desc_loops[13]
    DIRECTION OUTPUT ;
    USE SIGNAL ;
    PORT
      LAYER M4 ;
        RECT  69.036 41.712 69.12 41.736 ;
    END
  END b_desc_loops[13]
  PIN b_desc_loops[14]
    DIRECTION OUTPUT ;
    USE SIGNAL ;
    PORT
      LAYER M4 ;
        RECT  69.036 41.808 69.12 41.832 ;
    END
  END b_desc_loops[14]
  PIN b_desc_loops[15]
    DIRECTION OUTPUT ;
    USE SIGNAL ;
    PORT
      LAYER M4 ;
        RECT  69.036 41.904 69.12 41.928 ;
    END
  END b_desc_loops[15]
  PIN b_desc_loops[1]
    DIRECTION OUTPUT ;
    USE SIGNAL ;
    PORT
      LAYER M4 ;
        RECT  69.036 40.56 69.12 40.584 ;
    END
  END b_desc_loops[1]
  PIN b_desc_loops[2]
    DIRECTION OUTPUT ;
    USE SIGNAL ;
    PORT
      LAYER M4 ;
        RECT  69.036 40.656 69.12 40.68 ;
    END
  END b_desc_loops[2]
  PIN b_desc_loops[3]
    DIRECTION OUTPUT ;
    USE SIGNAL ;
    PORT
      LAYER M4 ;
        RECT  69.036 40.752 69.12 40.776 ;
    END
  END b_desc_loops[3]
  PIN b_desc_loops[4]
    DIRECTION OUTPUT ;
    USE SIGNAL ;
    PORT
      LAYER M4 ;
        RECT  69.036 40.848 69.12 40.872 ;
    END
  END b_desc_loops[4]
  PIN b_desc_loops[5]
    DIRECTION OUTPUT ;
    USE SIGNAL ;
    PORT
      LAYER M4 ;
        RECT  69.036 40.944 69.12 40.968 ;
    END
  END b_desc_loops[5]
  PIN b_desc_loops[6]
    DIRECTION OUTPUT ;
    USE SIGNAL ;
    PORT
      LAYER M4 ;
        RECT  69.036 41.04 69.12 41.064 ;
    END
  END b_desc_loops[6]
  PIN b_desc_loops[7]
    DIRECTION OUTPUT ;
    USE SIGNAL ;
    PORT
      LAYER M4 ;
        RECT  69.036 41.136 69.12 41.16 ;
    END
  END b_desc_loops[7]
  PIN b_desc_loops[8]
    DIRECTION OUTPUT ;
    USE SIGNAL ;
    PORT
      LAYER M4 ;
        RECT  69.036 41.232 69.12 41.256 ;
    END
  END b_desc_loops[8]
  PIN b_desc_loops[9]
    DIRECTION OUTPUT ;
    USE SIGNAL ;
    PORT
      LAYER M4 ;
        RECT  69.036 41.328 69.12 41.352 ;
    END
  END b_desc_loops[9]
  PIN b_desc_v
    DIRECTION OUTPUT ;
    USE SIGNAL ;
    PORT
      LAYER M4 ;
        RECT  69.036 42 69.12 42.024 ;
    END
  END b_desc_v
  PIN b_launch_v
    DIRECTION OUTPUT ;
    USE SIGNAL ;
    PORT
      LAYER M4 ;
        RECT  69.036 42.096 69.12 42.12 ;
    END
  END b_launch_v
  PIN cfg_addr[0]
    DIRECTION INPUT ;
    USE SIGNAL ;
    PORT
      LAYER M5 ;
        RECT  39.984 69.036 40.008 69.12 ;
    END
  END cfg_addr[0]
  PIN cfg_addr[10]
    DIRECTION INPUT ;
    USE SIGNAL ;
    PORT
      LAYER M5 ;
        RECT  40.944 69.036 40.968 69.12 ;
    END
  END cfg_addr[10]
  PIN cfg_addr[11]
    DIRECTION INPUT ;
    USE SIGNAL ;
    PORT
      LAYER M5 ;
        RECT  41.04 69.036 41.064 69.12 ;
    END
  END cfg_addr[11]
  PIN cfg_addr[1]
    DIRECTION INPUT ;
    USE SIGNAL ;
    PORT
      LAYER M5 ;
        RECT  40.08 69.036 40.104 69.12 ;
    END
  END cfg_addr[1]
  PIN cfg_addr[2]
    DIRECTION INPUT ;
    USE SIGNAL ;
    PORT
      LAYER M5 ;
        RECT  40.176 69.036 40.2 69.12 ;
    END
  END cfg_addr[2]
  PIN cfg_addr[3]
    DIRECTION INPUT ;
    USE SIGNAL ;
    PORT
      LAYER M5 ;
        RECT  40.272 69.036 40.296 69.12 ;
    END
  END cfg_addr[3]
  PIN cfg_addr[4]
    DIRECTION INPUT ;
    USE SIGNAL ;
    PORT
      LAYER M5 ;
        RECT  40.368 69.036 40.392 69.12 ;
    END
  END cfg_addr[4]
  PIN cfg_addr[5]
    DIRECTION INPUT ;
    USE SIGNAL ;
    PORT
      LAYER M5 ;
        RECT  40.464 69.036 40.488 69.12 ;
    END
  END cfg_addr[5]
  PIN cfg_addr[6]
    DIRECTION INPUT ;
    USE SIGNAL ;
    PORT
      LAYER M5 ;
        RECT  40.56 69.036 40.584 69.12 ;
    END
  END cfg_addr[6]
  PIN cfg_addr[7]
    DIRECTION INPUT ;
    USE SIGNAL ;
    PORT
      LAYER M5 ;
        RECT  40.656 69.036 40.68 69.12 ;
    END
  END cfg_addr[7]
  PIN cfg_addr[8]
    DIRECTION INPUT ;
    USE SIGNAL ;
    PORT
      LAYER M5 ;
        RECT  40.752 69.036 40.776 69.12 ;
    END
  END cfg_addr[8]
  PIN cfg_addr[9]
    DIRECTION INPUT ;
    USE SIGNAL ;
    PORT
      LAYER M5 ;
        RECT  40.848 69.036 40.872 69.12 ;
    END
  END cfg_addr[9]
  PIN cfg_data[0]
    DIRECTION INPUT ;
    USE SIGNAL ;
    PORT
      LAYER M5 ;
        RECT  41.136 69.036 41.16 69.12 ;
    END
  END cfg_data[0]
  PIN cfg_data[100]
    DIRECTION INPUT ;
    USE SIGNAL ;
    PORT
      LAYER M5 ;
        RECT  47.664 69.036 47.688 69.12 ;
    END
  END cfg_data[100]
  PIN cfg_data[101]
    DIRECTION INPUT ;
    USE SIGNAL ;
    PORT
      LAYER M5 ;
        RECT  47.76 69.036 47.784 69.12 ;
    END
  END cfg_data[101]
  PIN cfg_data[102]
    DIRECTION INPUT ;
    USE SIGNAL ;
    PORT
      LAYER M5 ;
        RECT  47.856 69.036 47.88 69.12 ;
    END
  END cfg_data[102]
  PIN cfg_data[103]
    DIRECTION INPUT ;
    USE SIGNAL ;
    PORT
      LAYER M5 ;
        RECT  47.952 69.036 47.976 69.12 ;
    END
  END cfg_data[103]
  PIN cfg_data[104]
    DIRECTION INPUT ;
    USE SIGNAL ;
    PORT
      LAYER M5 ;
        RECT  48.048 69.036 48.072 69.12 ;
    END
  END cfg_data[104]
  PIN cfg_data[105]
    DIRECTION INPUT ;
    USE SIGNAL ;
    PORT
      LAYER M5 ;
        RECT  48.144 69.036 48.168 69.12 ;
    END
  END cfg_data[105]
  PIN cfg_data[106]
    DIRECTION INPUT ;
    USE SIGNAL ;
    PORT
      LAYER M5 ;
        RECT  48.24 69.036 48.264 69.12 ;
    END
  END cfg_data[106]
  PIN cfg_data[107]
    DIRECTION INPUT ;
    USE SIGNAL ;
    PORT
      LAYER M5 ;
        RECT  48.336 69.036 48.36 69.12 ;
    END
  END cfg_data[107]
  PIN cfg_data[108]
    DIRECTION INPUT ;
    USE SIGNAL ;
    PORT
      LAYER M5 ;
        RECT  48.432 69.036 48.456 69.12 ;
    END
  END cfg_data[108]
  PIN cfg_data[109]
    DIRECTION INPUT ;
    USE SIGNAL ;
    PORT
      LAYER M5 ;
        RECT  48.528 69.036 48.552 69.12 ;
    END
  END cfg_data[109]
  PIN cfg_data[10]
    DIRECTION INPUT ;
    USE SIGNAL ;
    PORT
      LAYER M5 ;
        RECT  42.096 69.036 42.12 69.12 ;
    END
  END cfg_data[10]
  PIN cfg_data[110]
    DIRECTION INPUT ;
    USE SIGNAL ;
    PORT
      LAYER M5 ;
        RECT  48.624 69.036 48.648 69.12 ;
    END
  END cfg_data[110]
  PIN cfg_data[111]
    DIRECTION INPUT ;
    USE SIGNAL ;
    PORT
      LAYER M5 ;
        RECT  48.72 69.036 48.744 69.12 ;
    END
  END cfg_data[111]
  PIN cfg_data[112]
    DIRECTION INPUT ;
    USE SIGNAL ;
    PORT
      LAYER M5 ;
        RECT  48.816 69.036 48.84 69.12 ;
    END
  END cfg_data[112]
  PIN cfg_data[113]
    DIRECTION INPUT ;
    USE SIGNAL ;
    PORT
      LAYER M5 ;
        RECT  48.912 69.036 48.936 69.12 ;
    END
  END cfg_data[113]
  PIN cfg_data[114]
    DIRECTION INPUT ;
    USE SIGNAL ;
    PORT
      LAYER M5 ;
        RECT  49.008 69.036 49.032 69.12 ;
    END
  END cfg_data[114]
  PIN cfg_data[115]
    DIRECTION INPUT ;
    USE SIGNAL ;
    PORT
      LAYER M5 ;
        RECT  49.104 69.036 49.128 69.12 ;
    END
  END cfg_data[115]
  PIN cfg_data[116]
    DIRECTION INPUT ;
    USE SIGNAL ;
    PORT
      LAYER M5 ;
        RECT  43.056 69.036 43.08 69.12 ;
    END
  END cfg_data[116]
  PIN cfg_data[117]
    DIRECTION INPUT ;
    USE SIGNAL ;
    PORT
      LAYER M5 ;
        RECT  43.152 69.036 43.176 69.12 ;
    END
  END cfg_data[117]
  PIN cfg_data[118]
    DIRECTION INPUT ;
    USE SIGNAL ;
    PORT
      LAYER M5 ;
        RECT  43.248 69.036 43.272 69.12 ;
    END
  END cfg_data[118]
  PIN cfg_data[119]
    DIRECTION INPUT ;
    USE SIGNAL ;
    PORT
      LAYER M5 ;
        RECT  43.344 69.036 43.368 69.12 ;
    END
  END cfg_data[119]
  PIN cfg_data[11]
    DIRECTION INPUT ;
    USE SIGNAL ;
    PORT
      LAYER M5 ;
        RECT  42.192 69.036 42.216 69.12 ;
    END
  END cfg_data[11]
  PIN cfg_data[120]
    DIRECTION INPUT ;
    USE SIGNAL ;
    PORT
      LAYER M5 ;
        RECT  43.44 69.036 43.464 69.12 ;
    END
  END cfg_data[120]
  PIN cfg_data[121]
    DIRECTION INPUT ;
    USE SIGNAL ;
    PORT
      LAYER M5 ;
        RECT  43.536 69.036 43.56 69.12 ;
    END
  END cfg_data[121]
  PIN cfg_data[122]
    DIRECTION INPUT ;
    USE SIGNAL ;
    PORT
      LAYER M5 ;
        RECT  43.632 69.036 43.656 69.12 ;
    END
  END cfg_data[122]
  PIN cfg_data[123]
    DIRECTION INPUT ;
    USE SIGNAL ;
    PORT
      LAYER M5 ;
        RECT  43.728 69.036 43.752 69.12 ;
    END
  END cfg_data[123]
  PIN cfg_data[124]
    DIRECTION INPUT ;
    USE SIGNAL ;
    PORT
      LAYER M5 ;
        RECT  43.824 69.036 43.848 69.12 ;
    END
  END cfg_data[124]
  PIN cfg_data[125]
    DIRECTION INPUT ;
    USE SIGNAL ;
    PORT
      LAYER M5 ;
        RECT  43.92 69.036 43.944 69.12 ;
    END
  END cfg_data[125]
  PIN cfg_data[126]
    DIRECTION INPUT ;
    USE SIGNAL ;
    PORT
      LAYER M5 ;
        RECT  44.016 69.036 44.04 69.12 ;
    END
  END cfg_data[126]
  PIN cfg_data[127]
    DIRECTION INPUT ;
    USE SIGNAL ;
    PORT
      LAYER M5 ;
        RECT  44.112 69.036 44.136 69.12 ;
    END
  END cfg_data[127]
  PIN cfg_data[128]
    DIRECTION INPUT ;
    USE SIGNAL ;
    PORT
      LAYER M5 ;
        RECT  44.208 69.036 44.232 69.12 ;
    END
  END cfg_data[128]
  PIN cfg_data[129]
    DIRECTION INPUT ;
    USE SIGNAL ;
    PORT
      LAYER M5 ;
        RECT  44.304 69.036 44.328 69.12 ;
    END
  END cfg_data[129]
  PIN cfg_data[12]
    DIRECTION INPUT ;
    USE SIGNAL ;
    PORT
      LAYER M5 ;
        RECT  42.288 69.036 42.312 69.12 ;
    END
  END cfg_data[12]
  PIN cfg_data[130]
    DIRECTION INPUT ;
    USE SIGNAL ;
    PORT
      LAYER M5 ;
        RECT  44.4 69.036 44.424 69.12 ;
    END
  END cfg_data[130]
  PIN cfg_data[131]
    DIRECTION INPUT ;
    USE SIGNAL ;
    PORT
      LAYER M5 ;
        RECT  44.496 69.036 44.52 69.12 ;
    END
  END cfg_data[131]
  PIN cfg_data[132]
    DIRECTION INPUT ;
    USE SIGNAL ;
    PORT
      LAYER M5 ;
        RECT  44.592 69.036 44.616 69.12 ;
    END
  END cfg_data[132]
  PIN cfg_data[133]
    DIRECTION INPUT ;
    USE SIGNAL ;
    PORT
      LAYER M5 ;
        RECT  44.688 69.036 44.712 69.12 ;
    END
  END cfg_data[133]
  PIN cfg_data[134]
    DIRECTION INPUT ;
    USE SIGNAL ;
    PORT
      LAYER M5 ;
        RECT  44.784 69.036 44.808 69.12 ;
    END
  END cfg_data[134]
  PIN cfg_data[135]
    DIRECTION INPUT ;
    USE SIGNAL ;
    PORT
      LAYER M5 ;
        RECT  44.88 69.036 44.904 69.12 ;
    END
  END cfg_data[135]
  PIN cfg_data[136]
    DIRECTION INPUT ;
    USE SIGNAL ;
    PORT
      LAYER M5 ;
        RECT  44.976 69.036 45 69.12 ;
    END
  END cfg_data[136]
  PIN cfg_data[137]
    DIRECTION INPUT ;
    USE SIGNAL ;
    PORT
      LAYER M5 ;
        RECT  45.072 69.036 45.096 69.12 ;
    END
  END cfg_data[137]
  PIN cfg_data[138]
    DIRECTION INPUT ;
    USE SIGNAL ;
    PORT
      LAYER M5 ;
        RECT  45.168 69.036 45.192 69.12 ;
    END
  END cfg_data[138]
  PIN cfg_data[139]
    DIRECTION INPUT ;
    USE SIGNAL ;
    PORT
      LAYER M5 ;
        RECT  45.264 69.036 45.288 69.12 ;
    END
  END cfg_data[139]
  PIN cfg_data[13]
    DIRECTION INPUT ;
    USE SIGNAL ;
    PORT
      LAYER M5 ;
        RECT  42.384 69.036 42.408 69.12 ;
    END
  END cfg_data[13]
  PIN cfg_data[140]
    DIRECTION INPUT ;
    USE SIGNAL ;
    PORT
      LAYER M5 ;
        RECT  45.36 69.036 45.384 69.12 ;
    END
  END cfg_data[140]
  PIN cfg_data[141]
    DIRECTION INPUT ;
    USE SIGNAL ;
    PORT
      LAYER M5 ;
        RECT  45.456 69.036 45.48 69.12 ;
    END
  END cfg_data[141]
  PIN cfg_data[142]
    DIRECTION INPUT ;
    USE SIGNAL ;
    PORT
      LAYER M5 ;
        RECT  45.552 69.036 45.576 69.12 ;
    END
  END cfg_data[142]
  PIN cfg_data[143]
    DIRECTION INPUT ;
    USE SIGNAL ;
    PORT
      LAYER M5 ;
        RECT  45.648 69.036 45.672 69.12 ;
    END
  END cfg_data[143]
  PIN cfg_data[144]
    DIRECTION INPUT ;
    USE SIGNAL ;
    PORT
      LAYER M5 ;
        RECT  45.744 69.036 45.768 69.12 ;
    END
  END cfg_data[144]
  PIN cfg_data[145]
    DIRECTION INPUT ;
    USE SIGNAL ;
    PORT
      LAYER M5 ;
        RECT  45.84 69.036 45.864 69.12 ;
    END
  END cfg_data[145]
  PIN cfg_data[146]
    DIRECTION INPUT ;
    USE SIGNAL ;
    PORT
      LAYER M5 ;
        RECT  45.936 69.036 45.96 69.12 ;
    END
  END cfg_data[146]
  PIN cfg_data[147]
    DIRECTION INPUT ;
    USE SIGNAL ;
    PORT
      LAYER M5 ;
        RECT  46.032 69.036 46.056 69.12 ;
    END
  END cfg_data[147]
  PIN cfg_data[148]
    DIRECTION INPUT ;
    USE SIGNAL ;
    PORT
      LAYER M5 ;
        RECT  36.912 69.036 36.936 69.12 ;
    END
  END cfg_data[148]
  PIN cfg_data[149]
    DIRECTION INPUT ;
    USE SIGNAL ;
    PORT
      LAYER M5 ;
        RECT  37.008 69.036 37.032 69.12 ;
    END
  END cfg_data[149]
  PIN cfg_data[14]
    DIRECTION INPUT ;
    USE SIGNAL ;
    PORT
      LAYER M5 ;
        RECT  42.48 69.036 42.504 69.12 ;
    END
  END cfg_data[14]
  PIN cfg_data[150]
    DIRECTION INPUT ;
    USE SIGNAL ;
    PORT
      LAYER M5 ;
        RECT  37.104 69.036 37.128 69.12 ;
    END
  END cfg_data[150]
  PIN cfg_data[151]
    DIRECTION INPUT ;
    USE SIGNAL ;
    PORT
      LAYER M5 ;
        RECT  37.2 69.036 37.224 69.12 ;
    END
  END cfg_data[151]
  PIN cfg_data[152]
    DIRECTION INPUT ;
    USE SIGNAL ;
    PORT
      LAYER M5 ;
        RECT  37.296 69.036 37.32 69.12 ;
    END
  END cfg_data[152]
  PIN cfg_data[153]
    DIRECTION INPUT ;
    USE SIGNAL ;
    PORT
      LAYER M5 ;
        RECT  37.392 69.036 37.416 69.12 ;
    END
  END cfg_data[153]
  PIN cfg_data[154]
    DIRECTION INPUT ;
    USE SIGNAL ;
    PORT
      LAYER M5 ;
        RECT  37.488 69.036 37.512 69.12 ;
    END
  END cfg_data[154]
  PIN cfg_data[155]
    DIRECTION INPUT ;
    USE SIGNAL ;
    PORT
      LAYER M5 ;
        RECT  37.584 69.036 37.608 69.12 ;
    END
  END cfg_data[155]
  PIN cfg_data[156]
    DIRECTION INPUT ;
    USE SIGNAL ;
    PORT
      LAYER M5 ;
        RECT  37.68 69.036 37.704 69.12 ;
    END
  END cfg_data[156]
  PIN cfg_data[157]
    DIRECTION INPUT ;
    USE SIGNAL ;
    PORT
      LAYER M5 ;
        RECT  37.776 69.036 37.8 69.12 ;
    END
  END cfg_data[157]
  PIN cfg_data[158]
    DIRECTION INPUT ;
    USE SIGNAL ;
    PORT
      LAYER M5 ;
        RECT  37.872 69.036 37.896 69.12 ;
    END
  END cfg_data[158]
  PIN cfg_data[159]
    DIRECTION INPUT ;
    USE SIGNAL ;
    PORT
      LAYER M5 ;
        RECT  37.968 69.036 37.992 69.12 ;
    END
  END cfg_data[159]
  PIN cfg_data[15]
    DIRECTION INPUT ;
    USE SIGNAL ;
    PORT
      LAYER M5 ;
        RECT  42.576 69.036 42.6 69.12 ;
    END
  END cfg_data[15]
  PIN cfg_data[160]
    DIRECTION INPUT ;
    USE SIGNAL ;
    PORT
      LAYER M5 ;
        RECT  38.064 69.036 38.088 69.12 ;
    END
  END cfg_data[160]
  PIN cfg_data[161]
    DIRECTION INPUT ;
    USE SIGNAL ;
    PORT
      LAYER M5 ;
        RECT  38.16 69.036 38.184 69.12 ;
    END
  END cfg_data[161]
  PIN cfg_data[162]
    DIRECTION INPUT ;
    USE SIGNAL ;
    PORT
      LAYER M5 ;
        RECT  38.256 69.036 38.28 69.12 ;
    END
  END cfg_data[162]
  PIN cfg_data[163]
    DIRECTION INPUT ;
    USE SIGNAL ;
    PORT
      LAYER M5 ;
        RECT  38.352 69.036 38.376 69.12 ;
    END
  END cfg_data[163]
  PIN cfg_data[164]
    DIRECTION INPUT ;
    USE SIGNAL ;
    PORT
      LAYER M5 ;
        RECT  38.448 69.036 38.472 69.12 ;
    END
  END cfg_data[164]
  PIN cfg_data[165]
    DIRECTION INPUT ;
    USE SIGNAL ;
    PORT
      LAYER M5 ;
        RECT  38.544 69.036 38.568 69.12 ;
    END
  END cfg_data[165]
  PIN cfg_data[166]
    DIRECTION INPUT ;
    USE SIGNAL ;
    PORT
      LAYER M5 ;
        RECT  38.64 69.036 38.664 69.12 ;
    END
  END cfg_data[166]
  PIN cfg_data[167]
    DIRECTION INPUT ;
    USE SIGNAL ;
    PORT
      LAYER M5 ;
        RECT  38.736 69.036 38.76 69.12 ;
    END
  END cfg_data[167]
  PIN cfg_data[168]
    DIRECTION INPUT ;
    USE SIGNAL ;
    PORT
      LAYER M5 ;
        RECT  38.832 69.036 38.856 69.12 ;
    END
  END cfg_data[168]
  PIN cfg_data[169]
    DIRECTION INPUT ;
    USE SIGNAL ;
    PORT
      LAYER M5 ;
        RECT  38.928 69.036 38.952 69.12 ;
    END
  END cfg_data[169]
  PIN cfg_data[16]
    DIRECTION INPUT ;
    USE SIGNAL ;
    PORT
      LAYER M5 ;
        RECT  42.672 69.036 42.696 69.12 ;
    END
  END cfg_data[16]
  PIN cfg_data[170]
    DIRECTION INPUT ;
    USE SIGNAL ;
    PORT
      LAYER M5 ;
        RECT  39.024 69.036 39.048 69.12 ;
    END
  END cfg_data[170]
  PIN cfg_data[171]
    DIRECTION INPUT ;
    USE SIGNAL ;
    PORT
      LAYER M5 ;
        RECT  39.12 69.036 39.144 69.12 ;
    END
  END cfg_data[171]
  PIN cfg_data[172]
    DIRECTION INPUT ;
    USE SIGNAL ;
    PORT
      LAYER M5 ;
        RECT  39.216 69.036 39.24 69.12 ;
    END
  END cfg_data[172]
  PIN cfg_data[173]
    DIRECTION INPUT ;
    USE SIGNAL ;
    PORT
      LAYER M5 ;
        RECT  39.312 69.036 39.336 69.12 ;
    END
  END cfg_data[173]
  PIN cfg_data[174]
    DIRECTION INPUT ;
    USE SIGNAL ;
    PORT
      LAYER M5 ;
        RECT  39.408 69.036 39.432 69.12 ;
    END
  END cfg_data[174]
  PIN cfg_data[175]
    DIRECTION INPUT ;
    USE SIGNAL ;
    PORT
      LAYER M5 ;
        RECT  39.504 69.036 39.528 69.12 ;
    END
  END cfg_data[175]
  PIN cfg_data[176]
    DIRECTION INPUT ;
    USE SIGNAL ;
    PORT
      LAYER M5 ;
        RECT  39.6 69.036 39.624 69.12 ;
    END
  END cfg_data[176]
  PIN cfg_data[177]
    DIRECTION INPUT ;
    USE SIGNAL ;
    PORT
      LAYER M5 ;
        RECT  39.696 69.036 39.72 69.12 ;
    END
  END cfg_data[177]
  PIN cfg_data[178]
    DIRECTION INPUT ;
    USE SIGNAL ;
    PORT
      LAYER M5 ;
        RECT  39.792 69.036 39.816 69.12 ;
    END
  END cfg_data[178]
  PIN cfg_data[179]
    DIRECTION INPUT ;
    USE SIGNAL ;
    PORT
      LAYER M5 ;
        RECT  39.888 69.036 39.912 69.12 ;
    END
  END cfg_data[179]
  PIN cfg_data[17]
    DIRECTION INPUT ;
    USE SIGNAL ;
    PORT
      LAYER M5 ;
        RECT  42.768 69.036 42.792 69.12 ;
    END
  END cfg_data[17]
  PIN cfg_data[180]
    DIRECTION INPUT ;
    USE SIGNAL ;
    PORT
      LAYER M5 ;
        RECT  23.856 69.036 23.88 69.12 ;
    END
  END cfg_data[180]
  PIN cfg_data[181]
    DIRECTION INPUT ;
    USE SIGNAL ;
    PORT
      LAYER M5 ;
        RECT  23.952 69.036 23.976 69.12 ;
    END
  END cfg_data[181]
  PIN cfg_data[182]
    DIRECTION INPUT ;
    USE SIGNAL ;
    PORT
      LAYER M5 ;
        RECT  24.048 69.036 24.072 69.12 ;
    END
  END cfg_data[182]
  PIN cfg_data[183]
    DIRECTION INPUT ;
    USE SIGNAL ;
    PORT
      LAYER M5 ;
        RECT  24.144 69.036 24.168 69.12 ;
    END
  END cfg_data[183]
  PIN cfg_data[184]
    DIRECTION INPUT ;
    USE SIGNAL ;
    PORT
      LAYER M5 ;
        RECT  24.24 69.036 24.264 69.12 ;
    END
  END cfg_data[184]
  PIN cfg_data[185]
    DIRECTION INPUT ;
    USE SIGNAL ;
    PORT
      LAYER M5 ;
        RECT  24.336 69.036 24.36 69.12 ;
    END
  END cfg_data[185]
  PIN cfg_data[186]
    DIRECTION INPUT ;
    USE SIGNAL ;
    PORT
      LAYER M5 ;
        RECT  24.432 69.036 24.456 69.12 ;
    END
  END cfg_data[186]
  PIN cfg_data[187]
    DIRECTION INPUT ;
    USE SIGNAL ;
    PORT
      LAYER M5 ;
        RECT  24.528 69.036 24.552 69.12 ;
    END
  END cfg_data[187]
  PIN cfg_data[188]
    DIRECTION INPUT ;
    USE SIGNAL ;
    PORT
      LAYER M5 ;
        RECT  24.624 69.036 24.648 69.12 ;
    END
  END cfg_data[188]
  PIN cfg_data[189]
    DIRECTION INPUT ;
    USE SIGNAL ;
    PORT
      LAYER M5 ;
        RECT  24.72 69.036 24.744 69.12 ;
    END
  END cfg_data[189]
  PIN cfg_data[18]
    DIRECTION INPUT ;
    USE SIGNAL ;
    PORT
      LAYER M5 ;
        RECT  42.864 69.036 42.888 69.12 ;
    END
  END cfg_data[18]
  PIN cfg_data[190]
    DIRECTION INPUT ;
    USE SIGNAL ;
    PORT
      LAYER M5 ;
        RECT  24.816 69.036 24.84 69.12 ;
    END
  END cfg_data[190]
  PIN cfg_data[191]
    DIRECTION INPUT ;
    USE SIGNAL ;
    PORT
      LAYER M5 ;
        RECT  24.912 69.036 24.936 69.12 ;
    END
  END cfg_data[191]
  PIN cfg_data[192]
    DIRECTION INPUT ;
    USE SIGNAL ;
    PORT
      LAYER M5 ;
        RECT  25.008 69.036 25.032 69.12 ;
    END
  END cfg_data[192]
  PIN cfg_data[193]
    DIRECTION INPUT ;
    USE SIGNAL ;
    PORT
      LAYER M5 ;
        RECT  25.104 69.036 25.128 69.12 ;
    END
  END cfg_data[193]
  PIN cfg_data[194]
    DIRECTION INPUT ;
    USE SIGNAL ;
    PORT
      LAYER M5 ;
        RECT  25.2 69.036 25.224 69.12 ;
    END
  END cfg_data[194]
  PIN cfg_data[195]
    DIRECTION INPUT ;
    USE SIGNAL ;
    PORT
      LAYER M5 ;
        RECT  25.296 69.036 25.32 69.12 ;
    END
  END cfg_data[195]
  PIN cfg_data[196]
    DIRECTION INPUT ;
    USE SIGNAL ;
    PORT
      LAYER M5 ;
        RECT  25.392 69.036 25.416 69.12 ;
    END
  END cfg_data[196]
  PIN cfg_data[197]
    DIRECTION INPUT ;
    USE SIGNAL ;
    PORT
      LAYER M5 ;
        RECT  25.488 69.036 25.512 69.12 ;
    END
  END cfg_data[197]
  PIN cfg_data[198]
    DIRECTION INPUT ;
    USE SIGNAL ;
    PORT
      LAYER M5 ;
        RECT  25.584 69.036 25.608 69.12 ;
    END
  END cfg_data[198]
  PIN cfg_data[199]
    DIRECTION INPUT ;
    USE SIGNAL ;
    PORT
      LAYER M5 ;
        RECT  25.68 69.036 25.704 69.12 ;
    END
  END cfg_data[199]
  PIN cfg_data[19]
    DIRECTION INPUT ;
    USE SIGNAL ;
    PORT
      LAYER M5 ;
        RECT  42.96 69.036 42.984 69.12 ;
    END
  END cfg_data[19]
  PIN cfg_data[1]
    DIRECTION INPUT ;
    USE SIGNAL ;
    PORT
      LAYER M5 ;
        RECT  41.232 69.036 41.256 69.12 ;
    END
  END cfg_data[1]
  PIN cfg_data[200]
    DIRECTION INPUT ;
    USE SIGNAL ;
    PORT
      LAYER M5 ;
        RECT  25.776 69.036 25.8 69.12 ;
    END
  END cfg_data[200]
  PIN cfg_data[201]
    DIRECTION INPUT ;
    USE SIGNAL ;
    PORT
      LAYER M5 ;
        RECT  25.872 69.036 25.896 69.12 ;
    END
  END cfg_data[201]
  PIN cfg_data[202]
    DIRECTION INPUT ;
    USE SIGNAL ;
    PORT
      LAYER M5 ;
        RECT  25.968 69.036 25.992 69.12 ;
    END
  END cfg_data[202]
  PIN cfg_data[203]
    DIRECTION INPUT ;
    USE SIGNAL ;
    PORT
      LAYER M5 ;
        RECT  26.064 69.036 26.088 69.12 ;
    END
  END cfg_data[203]
  PIN cfg_data[204]
    DIRECTION INPUT ;
    USE SIGNAL ;
    PORT
      LAYER M5 ;
        RECT  26.16 69.036 26.184 69.12 ;
    END
  END cfg_data[204]
  PIN cfg_data[205]
    DIRECTION INPUT ;
    USE SIGNAL ;
    PORT
      LAYER M5 ;
        RECT  26.256 69.036 26.28 69.12 ;
    END
  END cfg_data[205]
  PIN cfg_data[206]
    DIRECTION INPUT ;
    USE SIGNAL ;
    PORT
      LAYER M5 ;
        RECT  26.352 69.036 26.376 69.12 ;
    END
  END cfg_data[206]
  PIN cfg_data[207]
    DIRECTION INPUT ;
    USE SIGNAL ;
    PORT
      LAYER M5 ;
        RECT  26.448 69.036 26.472 69.12 ;
    END
  END cfg_data[207]
  PIN cfg_data[208]
    DIRECTION INPUT ;
    USE SIGNAL ;
    PORT
      LAYER M5 ;
        RECT  26.544 69.036 26.568 69.12 ;
    END
  END cfg_data[208]
  PIN cfg_data[209]
    DIRECTION INPUT ;
    USE SIGNAL ;
    PORT
      LAYER M5 ;
        RECT  26.64 69.036 26.664 69.12 ;
    END
  END cfg_data[209]
  PIN cfg_data[20]
    DIRECTION INPUT ;
    USE SIGNAL ;
    PORT
      LAYER M5 ;
        RECT  33.84 69.036 33.864 69.12 ;
    END
  END cfg_data[20]
  PIN cfg_data[210]
    DIRECTION INPUT ;
    USE SIGNAL ;
    PORT
      LAYER M5 ;
        RECT  26.736 69.036 26.76 69.12 ;
    END
  END cfg_data[210]
  PIN cfg_data[211]
    DIRECTION INPUT ;
    USE SIGNAL ;
    PORT
      LAYER M5 ;
        RECT  26.832 69.036 26.856 69.12 ;
    END
  END cfg_data[211]
  PIN cfg_data[212]
    DIRECTION INPUT ;
    USE SIGNAL ;
    PORT
      LAYER M5 ;
        RECT  26.928 69.036 26.952 69.12 ;
    END
  END cfg_data[212]
  PIN cfg_data[213]
    DIRECTION INPUT ;
    USE SIGNAL ;
    PORT
      LAYER M5 ;
        RECT  27.024 69.036 27.048 69.12 ;
    END
  END cfg_data[213]
  PIN cfg_data[214]
    DIRECTION INPUT ;
    USE SIGNAL ;
    PORT
      LAYER M5 ;
        RECT  27.12 69.036 27.144 69.12 ;
    END
  END cfg_data[214]
  PIN cfg_data[215]
    DIRECTION INPUT ;
    USE SIGNAL ;
    PORT
      LAYER M5 ;
        RECT  27.216 69.036 27.24 69.12 ;
    END
  END cfg_data[215]
  PIN cfg_data[216]
    DIRECTION INPUT ;
    USE SIGNAL ;
    PORT
      LAYER M5 ;
        RECT  27.312 69.036 27.336 69.12 ;
    END
  END cfg_data[216]
  PIN cfg_data[217]
    DIRECTION INPUT ;
    USE SIGNAL ;
    PORT
      LAYER M5 ;
        RECT  27.408 69.036 27.432 69.12 ;
    END
  END cfg_data[217]
  PIN cfg_data[218]
    DIRECTION INPUT ;
    USE SIGNAL ;
    PORT
      LAYER M5 ;
        RECT  27.504 69.036 27.528 69.12 ;
    END
  END cfg_data[218]
  PIN cfg_data[219]
    DIRECTION INPUT ;
    USE SIGNAL ;
    PORT
      LAYER M5 ;
        RECT  27.6 69.036 27.624 69.12 ;
    END
  END cfg_data[219]
  PIN cfg_data[21]
    DIRECTION INPUT ;
    USE SIGNAL ;
    PORT
      LAYER M5 ;
        RECT  33.936 69.036 33.96 69.12 ;
    END
  END cfg_data[21]
  PIN cfg_data[220]
    DIRECTION INPUT ;
    USE SIGNAL ;
    PORT
      LAYER M5 ;
        RECT  27.696 69.036 27.72 69.12 ;
    END
  END cfg_data[220]
  PIN cfg_data[221]
    DIRECTION INPUT ;
    USE SIGNAL ;
    PORT
      LAYER M5 ;
        RECT  27.792 69.036 27.816 69.12 ;
    END
  END cfg_data[221]
  PIN cfg_data[222]
    DIRECTION INPUT ;
    USE SIGNAL ;
    PORT
      LAYER M5 ;
        RECT  27.888 69.036 27.912 69.12 ;
    END
  END cfg_data[222]
  PIN cfg_data[223]
    DIRECTION INPUT ;
    USE SIGNAL ;
    PORT
      LAYER M5 ;
        RECT  27.984 69.036 28.008 69.12 ;
    END
  END cfg_data[223]
  PIN cfg_data[224]
    DIRECTION INPUT ;
    USE SIGNAL ;
    PORT
      LAYER M5 ;
        RECT  28.08 69.036 28.104 69.12 ;
    END
  END cfg_data[224]
  PIN cfg_data[225]
    DIRECTION INPUT ;
    USE SIGNAL ;
    PORT
      LAYER M5 ;
        RECT  28.176 69.036 28.2 69.12 ;
    END
  END cfg_data[225]
  PIN cfg_data[226]
    DIRECTION INPUT ;
    USE SIGNAL ;
    PORT
      LAYER M5 ;
        RECT  28.272 69.036 28.296 69.12 ;
    END
  END cfg_data[226]
  PIN cfg_data[227]
    DIRECTION INPUT ;
    USE SIGNAL ;
    PORT
      LAYER M5 ;
        RECT  28.368 69.036 28.392 69.12 ;
    END
  END cfg_data[227]
  PIN cfg_data[228]
    DIRECTION INPUT ;
    USE SIGNAL ;
    PORT
      LAYER M5 ;
        RECT  28.464 69.036 28.488 69.12 ;
    END
  END cfg_data[228]
  PIN cfg_data[229]
    DIRECTION INPUT ;
    USE SIGNAL ;
    PORT
      LAYER M5 ;
        RECT  28.56 69.036 28.584 69.12 ;
    END
  END cfg_data[229]
  PIN cfg_data[22]
    DIRECTION INPUT ;
    USE SIGNAL ;
    PORT
      LAYER M5 ;
        RECT  34.032 69.036 34.056 69.12 ;
    END
  END cfg_data[22]
  PIN cfg_data[230]
    DIRECTION INPUT ;
    USE SIGNAL ;
    PORT
      LAYER M5 ;
        RECT  28.656 69.036 28.68 69.12 ;
    END
  END cfg_data[230]
  PIN cfg_data[231]
    DIRECTION INPUT ;
    USE SIGNAL ;
    PORT
      LAYER M5 ;
        RECT  28.752 69.036 28.776 69.12 ;
    END
  END cfg_data[231]
  PIN cfg_data[232]
    DIRECTION INPUT ;
    USE SIGNAL ;
    PORT
      LAYER M5 ;
        RECT  28.848 69.036 28.872 69.12 ;
    END
  END cfg_data[232]
  PIN cfg_data[233]
    DIRECTION INPUT ;
    USE SIGNAL ;
    PORT
      LAYER M5 ;
        RECT  28.944 69.036 28.968 69.12 ;
    END
  END cfg_data[233]
  PIN cfg_data[234]
    DIRECTION INPUT ;
    USE SIGNAL ;
    PORT
      LAYER M5 ;
        RECT  29.04 69.036 29.064 69.12 ;
    END
  END cfg_data[234]
  PIN cfg_data[235]
    DIRECTION INPUT ;
    USE SIGNAL ;
    PORT
      LAYER M5 ;
        RECT  29.136 69.036 29.16 69.12 ;
    END
  END cfg_data[235]
  PIN cfg_data[236]
    DIRECTION INPUT ;
    USE SIGNAL ;
    PORT
      LAYER M5 ;
        RECT  29.232 69.036 29.256 69.12 ;
    END
  END cfg_data[236]
  PIN cfg_data[237]
    DIRECTION INPUT ;
    USE SIGNAL ;
    PORT
      LAYER M5 ;
        RECT  29.328 69.036 29.352 69.12 ;
    END
  END cfg_data[237]
  PIN cfg_data[238]
    DIRECTION INPUT ;
    USE SIGNAL ;
    PORT
      LAYER M5 ;
        RECT  29.424 69.036 29.448 69.12 ;
    END
  END cfg_data[238]
  PIN cfg_data[239]
    DIRECTION INPUT ;
    USE SIGNAL ;
    PORT
      LAYER M5 ;
        RECT  29.52 69.036 29.544 69.12 ;
    END
  END cfg_data[239]
  PIN cfg_data[23]
    DIRECTION INPUT ;
    USE SIGNAL ;
    PORT
      LAYER M5 ;
        RECT  34.128 69.036 34.152 69.12 ;
    END
  END cfg_data[23]
  PIN cfg_data[240]
    DIRECTION INPUT ;
    USE SIGNAL ;
    PORT
      LAYER M5 ;
        RECT  29.616 69.036 29.64 69.12 ;
    END
  END cfg_data[240]
  PIN cfg_data[241]
    DIRECTION INPUT ;
    USE SIGNAL ;
    PORT
      LAYER M5 ;
        RECT  29.712 69.036 29.736 69.12 ;
    END
  END cfg_data[241]
  PIN cfg_data[242]
    DIRECTION INPUT ;
    USE SIGNAL ;
    PORT
      LAYER M5 ;
        RECT  29.808 69.036 29.832 69.12 ;
    END
  END cfg_data[242]
  PIN cfg_data[243]
    DIRECTION INPUT ;
    USE SIGNAL ;
    PORT
      LAYER M5 ;
        RECT  29.904 69.036 29.928 69.12 ;
    END
  END cfg_data[243]
  PIN cfg_data[244]
    DIRECTION INPUT ;
    USE SIGNAL ;
    PORT
      LAYER M5 ;
        RECT  20.784 69.036 20.808 69.12 ;
    END
  END cfg_data[244]
  PIN cfg_data[245]
    DIRECTION INPUT ;
    USE SIGNAL ;
    PORT
      LAYER M5 ;
        RECT  20.88 69.036 20.904 69.12 ;
    END
  END cfg_data[245]
  PIN cfg_data[246]
    DIRECTION INPUT ;
    USE SIGNAL ;
    PORT
      LAYER M5 ;
        RECT  20.976 69.036 21 69.12 ;
    END
  END cfg_data[246]
  PIN cfg_data[247]
    DIRECTION INPUT ;
    USE SIGNAL ;
    PORT
      LAYER M5 ;
        RECT  21.072 69.036 21.096 69.12 ;
    END
  END cfg_data[247]
  PIN cfg_data[248]
    DIRECTION INPUT ;
    USE SIGNAL ;
    PORT
      LAYER M5 ;
        RECT  21.168 69.036 21.192 69.12 ;
    END
  END cfg_data[248]
  PIN cfg_data[249]
    DIRECTION INPUT ;
    USE SIGNAL ;
    PORT
      LAYER M5 ;
        RECT  21.264 69.036 21.288 69.12 ;
    END
  END cfg_data[249]
  PIN cfg_data[24]
    DIRECTION INPUT ;
    USE SIGNAL ;
    PORT
      LAYER M5 ;
        RECT  34.224 69.036 34.248 69.12 ;
    END
  END cfg_data[24]
  PIN cfg_data[250]
    DIRECTION INPUT ;
    USE SIGNAL ;
    PORT
      LAYER M5 ;
        RECT  21.36 69.036 21.384 69.12 ;
    END
  END cfg_data[250]
  PIN cfg_data[251]
    DIRECTION INPUT ;
    USE SIGNAL ;
    PORT
      LAYER M5 ;
        RECT  21.456 69.036 21.48 69.12 ;
    END
  END cfg_data[251]
  PIN cfg_data[252]
    DIRECTION INPUT ;
    USE SIGNAL ;
    PORT
      LAYER M5 ;
        RECT  21.552 69.036 21.576 69.12 ;
    END
  END cfg_data[252]
  PIN cfg_data[253]
    DIRECTION INPUT ;
    USE SIGNAL ;
    PORT
      LAYER M5 ;
        RECT  21.648 69.036 21.672 69.12 ;
    END
  END cfg_data[253]
  PIN cfg_data[254]
    DIRECTION INPUT ;
    USE SIGNAL ;
    PORT
      LAYER M5 ;
        RECT  21.744 69.036 21.768 69.12 ;
    END
  END cfg_data[254]
  PIN cfg_data[255]
    DIRECTION INPUT ;
    USE SIGNAL ;
    PORT
      LAYER M5 ;
        RECT  21.84 69.036 21.864 69.12 ;
    END
  END cfg_data[255]
  PIN cfg_data[25]
    DIRECTION INPUT ;
    USE SIGNAL ;
    PORT
      LAYER M5 ;
        RECT  34.32 69.036 34.344 69.12 ;
    END
  END cfg_data[25]
  PIN cfg_data[26]
    DIRECTION INPUT ;
    USE SIGNAL ;
    PORT
      LAYER M5 ;
        RECT  34.416 69.036 34.44 69.12 ;
    END
  END cfg_data[26]
  PIN cfg_data[27]
    DIRECTION INPUT ;
    USE SIGNAL ;
    PORT
      LAYER M5 ;
        RECT  34.512 69.036 34.536 69.12 ;
    END
  END cfg_data[27]
  PIN cfg_data[28]
    DIRECTION INPUT ;
    USE SIGNAL ;
    PORT
      LAYER M5 ;
        RECT  34.608 69.036 34.632 69.12 ;
    END
  END cfg_data[28]
  PIN cfg_data[29]
    DIRECTION INPUT ;
    USE SIGNAL ;
    PORT
      LAYER M5 ;
        RECT  34.704 69.036 34.728 69.12 ;
    END
  END cfg_data[29]
  PIN cfg_data[2]
    DIRECTION INPUT ;
    USE SIGNAL ;
    PORT
      LAYER M5 ;
        RECT  41.328 69.036 41.352 69.12 ;
    END
  END cfg_data[2]
  PIN cfg_data[30]
    DIRECTION INPUT ;
    USE SIGNAL ;
    PORT
      LAYER M5 ;
        RECT  34.8 69.036 34.824 69.12 ;
    END
  END cfg_data[30]
  PIN cfg_data[31]
    DIRECTION INPUT ;
    USE SIGNAL ;
    PORT
      LAYER M5 ;
        RECT  34.896 69.036 34.92 69.12 ;
    END
  END cfg_data[31]
  PIN cfg_data[32]
    DIRECTION INPUT ;
    USE SIGNAL ;
    PORT
      LAYER M5 ;
        RECT  34.992 69.036 35.016 69.12 ;
    END
  END cfg_data[32]
  PIN cfg_data[33]
    DIRECTION INPUT ;
    USE SIGNAL ;
    PORT
      LAYER M5 ;
        RECT  35.088 69.036 35.112 69.12 ;
    END
  END cfg_data[33]
  PIN cfg_data[34]
    DIRECTION INPUT ;
    USE SIGNAL ;
    PORT
      LAYER M5 ;
        RECT  35.184 69.036 35.208 69.12 ;
    END
  END cfg_data[34]
  PIN cfg_data[35]
    DIRECTION INPUT ;
    USE SIGNAL ;
    PORT
      LAYER M5 ;
        RECT  35.28 69.036 35.304 69.12 ;
    END
  END cfg_data[35]
  PIN cfg_data[36]
    DIRECTION INPUT ;
    USE SIGNAL ;
    PORT
      LAYER M5 ;
        RECT  35.376 69.036 35.4 69.12 ;
    END
  END cfg_data[36]
  PIN cfg_data[37]
    DIRECTION INPUT ;
    USE SIGNAL ;
    PORT
      LAYER M5 ;
        RECT  35.472 69.036 35.496 69.12 ;
    END
  END cfg_data[37]
  PIN cfg_data[38]
    DIRECTION INPUT ;
    USE SIGNAL ;
    PORT
      LAYER M5 ;
        RECT  35.568 69.036 35.592 69.12 ;
    END
  END cfg_data[38]
  PIN cfg_data[39]
    DIRECTION INPUT ;
    USE SIGNAL ;
    PORT
      LAYER M5 ;
        RECT  35.664 69.036 35.688 69.12 ;
    END
  END cfg_data[39]
  PIN cfg_data[3]
    DIRECTION INPUT ;
    USE SIGNAL ;
    PORT
      LAYER M5 ;
        RECT  41.424 69.036 41.448 69.12 ;
    END
  END cfg_data[3]
  PIN cfg_data[40]
    DIRECTION INPUT ;
    USE SIGNAL ;
    PORT
      LAYER M5 ;
        RECT  35.76 69.036 35.784 69.12 ;
    END
  END cfg_data[40]
  PIN cfg_data[41]
    DIRECTION INPUT ;
    USE SIGNAL ;
    PORT
      LAYER M5 ;
        RECT  35.856 69.036 35.88 69.12 ;
    END
  END cfg_data[41]
  PIN cfg_data[42]
    DIRECTION INPUT ;
    USE SIGNAL ;
    PORT
      LAYER M5 ;
        RECT  35.952 69.036 35.976 69.12 ;
    END
  END cfg_data[42]
  PIN cfg_data[43]
    DIRECTION INPUT ;
    USE SIGNAL ;
    PORT
      LAYER M5 ;
        RECT  36.048 69.036 36.072 69.12 ;
    END
  END cfg_data[43]
  PIN cfg_data[44]
    DIRECTION INPUT ;
    USE SIGNAL ;
    PORT
      LAYER M5 ;
        RECT  36.144 69.036 36.168 69.12 ;
    END
  END cfg_data[44]
  PIN cfg_data[45]
    DIRECTION INPUT ;
    USE SIGNAL ;
    PORT
      LAYER M5 ;
        RECT  36.24 69.036 36.264 69.12 ;
    END
  END cfg_data[45]
  PIN cfg_data[46]
    DIRECTION INPUT ;
    USE SIGNAL ;
    PORT
      LAYER M5 ;
        RECT  36.336 69.036 36.36 69.12 ;
    END
  END cfg_data[46]
  PIN cfg_data[47]
    DIRECTION INPUT ;
    USE SIGNAL ;
    PORT
      LAYER M5 ;
        RECT  36.432 69.036 36.456 69.12 ;
    END
  END cfg_data[47]
  PIN cfg_data[48]
    DIRECTION INPUT ;
    USE SIGNAL ;
    PORT
      LAYER M5 ;
        RECT  36.528 69.036 36.552 69.12 ;
    END
  END cfg_data[48]
  PIN cfg_data[49]
    DIRECTION INPUT ;
    USE SIGNAL ;
    PORT
      LAYER M5 ;
        RECT  36.624 69.036 36.648 69.12 ;
    END
  END cfg_data[49]
  PIN cfg_data[4]
    DIRECTION INPUT ;
    USE SIGNAL ;
    PORT
      LAYER M5 ;
        RECT  41.52 69.036 41.544 69.12 ;
    END
  END cfg_data[4]
  PIN cfg_data[50]
    DIRECTION INPUT ;
    USE SIGNAL ;
    PORT
      LAYER M5 ;
        RECT  36.72 69.036 36.744 69.12 ;
    END
  END cfg_data[50]
  PIN cfg_data[51]
    DIRECTION INPUT ;
    USE SIGNAL ;
    PORT
      LAYER M5 ;
        RECT  36.816 69.036 36.84 69.12 ;
    END
  END cfg_data[51]
  PIN cfg_data[52]
    DIRECTION INPUT ;
    USE SIGNAL ;
    PORT
      LAYER M5 ;
        RECT  30.768 69.036 30.792 69.12 ;
    END
  END cfg_data[52]
  PIN cfg_data[53]
    DIRECTION INPUT ;
    USE SIGNAL ;
    PORT
      LAYER M5 ;
        RECT  30.864 69.036 30.888 69.12 ;
    END
  END cfg_data[53]
  PIN cfg_data[54]
    DIRECTION INPUT ;
    USE SIGNAL ;
    PORT
      LAYER M5 ;
        RECT  30.96 69.036 30.984 69.12 ;
    END
  END cfg_data[54]
  PIN cfg_data[55]
    DIRECTION INPUT ;
    USE SIGNAL ;
    PORT
      LAYER M5 ;
        RECT  31.056 69.036 31.08 69.12 ;
    END
  END cfg_data[55]
  PIN cfg_data[56]
    DIRECTION INPUT ;
    USE SIGNAL ;
    PORT
      LAYER M5 ;
        RECT  31.152 69.036 31.176 69.12 ;
    END
  END cfg_data[56]
  PIN cfg_data[57]
    DIRECTION INPUT ;
    USE SIGNAL ;
    PORT
      LAYER M5 ;
        RECT  31.248 69.036 31.272 69.12 ;
    END
  END cfg_data[57]
  PIN cfg_data[58]
    DIRECTION INPUT ;
    USE SIGNAL ;
    PORT
      LAYER M5 ;
        RECT  31.344 69.036 31.368 69.12 ;
    END
  END cfg_data[58]
  PIN cfg_data[59]
    DIRECTION INPUT ;
    USE SIGNAL ;
    PORT
      LAYER M5 ;
        RECT  31.44 69.036 31.464 69.12 ;
    END
  END cfg_data[59]
  PIN cfg_data[5]
    DIRECTION INPUT ;
    USE SIGNAL ;
    PORT
      LAYER M5 ;
        RECT  41.616 69.036 41.64 69.12 ;
    END
  END cfg_data[5]
  PIN cfg_data[60]
    DIRECTION INPUT ;
    USE SIGNAL ;
    PORT
      LAYER M5 ;
        RECT  31.536 69.036 31.56 69.12 ;
    END
  END cfg_data[60]
  PIN cfg_data[61]
    DIRECTION INPUT ;
    USE SIGNAL ;
    PORT
      LAYER M5 ;
        RECT  31.632 69.036 31.656 69.12 ;
    END
  END cfg_data[61]
  PIN cfg_data[62]
    DIRECTION INPUT ;
    USE SIGNAL ;
    PORT
      LAYER M5 ;
        RECT  31.728 69.036 31.752 69.12 ;
    END
  END cfg_data[62]
  PIN cfg_data[63]
    DIRECTION INPUT ;
    USE SIGNAL ;
    PORT
      LAYER M5 ;
        RECT  31.824 69.036 31.848 69.12 ;
    END
  END cfg_data[63]
  PIN cfg_data[64]
    DIRECTION INPUT ;
    USE SIGNAL ;
    PORT
      LAYER M5 ;
        RECT  31.92 69.036 31.944 69.12 ;
    END
  END cfg_data[64]
  PIN cfg_data[65]
    DIRECTION INPUT ;
    USE SIGNAL ;
    PORT
      LAYER M5 ;
        RECT  32.016 69.036 32.04 69.12 ;
    END
  END cfg_data[65]
  PIN cfg_data[66]
    DIRECTION INPUT ;
    USE SIGNAL ;
    PORT
      LAYER M5 ;
        RECT  32.112 69.036 32.136 69.12 ;
    END
  END cfg_data[66]
  PIN cfg_data[67]
    DIRECTION INPUT ;
    USE SIGNAL ;
    PORT
      LAYER M5 ;
        RECT  32.208 69.036 32.232 69.12 ;
    END
  END cfg_data[67]
  PIN cfg_data[68]
    DIRECTION INPUT ;
    USE SIGNAL ;
    PORT
      LAYER M5 ;
        RECT  32.304 69.036 32.328 69.12 ;
    END
  END cfg_data[68]
  PIN cfg_data[69]
    DIRECTION INPUT ;
    USE SIGNAL ;
    PORT
      LAYER M5 ;
        RECT  32.4 69.036 32.424 69.12 ;
    END
  END cfg_data[69]
  PIN cfg_data[6]
    DIRECTION INPUT ;
    USE SIGNAL ;
    PORT
      LAYER M5 ;
        RECT  41.712 69.036 41.736 69.12 ;
    END
  END cfg_data[6]
  PIN cfg_data[70]
    DIRECTION INPUT ;
    USE SIGNAL ;
    PORT
      LAYER M5 ;
        RECT  32.496 69.036 32.52 69.12 ;
    END
  END cfg_data[70]
  PIN cfg_data[71]
    DIRECTION INPUT ;
    USE SIGNAL ;
    PORT
      LAYER M5 ;
        RECT  32.592 69.036 32.616 69.12 ;
    END
  END cfg_data[71]
  PIN cfg_data[72]
    DIRECTION INPUT ;
    USE SIGNAL ;
    PORT
      LAYER M5 ;
        RECT  32.688 69.036 32.712 69.12 ;
    END
  END cfg_data[72]
  PIN cfg_data[73]
    DIRECTION INPUT ;
    USE SIGNAL ;
    PORT
      LAYER M5 ;
        RECT  32.784 69.036 32.808 69.12 ;
    END
  END cfg_data[73]
  PIN cfg_data[74]
    DIRECTION INPUT ;
    USE SIGNAL ;
    PORT
      LAYER M5 ;
        RECT  32.88 69.036 32.904 69.12 ;
    END
  END cfg_data[74]
  PIN cfg_data[75]
    DIRECTION INPUT ;
    USE SIGNAL ;
    PORT
      LAYER M5 ;
        RECT  32.976 69.036 33 69.12 ;
    END
  END cfg_data[75]
  PIN cfg_data[76]
    DIRECTION INPUT ;
    USE SIGNAL ;
    PORT
      LAYER M5 ;
        RECT  33.072 69.036 33.096 69.12 ;
    END
  END cfg_data[76]
  PIN cfg_data[77]
    DIRECTION INPUT ;
    USE SIGNAL ;
    PORT
      LAYER M5 ;
        RECT  33.168 69.036 33.192 69.12 ;
    END
  END cfg_data[77]
  PIN cfg_data[78]
    DIRECTION INPUT ;
    USE SIGNAL ;
    PORT
      LAYER M5 ;
        RECT  33.264 69.036 33.288 69.12 ;
    END
  END cfg_data[78]
  PIN cfg_data[79]
    DIRECTION INPUT ;
    USE SIGNAL ;
    PORT
      LAYER M5 ;
        RECT  33.36 69.036 33.384 69.12 ;
    END
  END cfg_data[79]
  PIN cfg_data[7]
    DIRECTION INPUT ;
    USE SIGNAL ;
    PORT
      LAYER M5 ;
        RECT  41.808 69.036 41.832 69.12 ;
    END
  END cfg_data[7]
  PIN cfg_data[80]
    DIRECTION INPUT ;
    USE SIGNAL ;
    PORT
      LAYER M5 ;
        RECT  33.456 69.036 33.48 69.12 ;
    END
  END cfg_data[80]
  PIN cfg_data[81]
    DIRECTION INPUT ;
    USE SIGNAL ;
    PORT
      LAYER M5 ;
        RECT  33.552 69.036 33.576 69.12 ;
    END
  END cfg_data[81]
  PIN cfg_data[82]
    DIRECTION INPUT ;
    USE SIGNAL ;
    PORT
      LAYER M5 ;
        RECT  33.648 69.036 33.672 69.12 ;
    END
  END cfg_data[82]
  PIN cfg_data[83]
    DIRECTION INPUT ;
    USE SIGNAL ;
    PORT
      LAYER M5 ;
        RECT  33.744 69.036 33.768 69.12 ;
    END
  END cfg_data[83]
  PIN cfg_data[84]
    DIRECTION INPUT ;
    USE SIGNAL ;
    PORT
      LAYER M5 ;
        RECT  46.128 69.036 46.152 69.12 ;
    END
  END cfg_data[84]
  PIN cfg_data[85]
    DIRECTION INPUT ;
    USE SIGNAL ;
    PORT
      LAYER M5 ;
        RECT  46.224 69.036 46.248 69.12 ;
    END
  END cfg_data[85]
  PIN cfg_data[86]
    DIRECTION INPUT ;
    USE SIGNAL ;
    PORT
      LAYER M5 ;
        RECT  46.32 69.036 46.344 69.12 ;
    END
  END cfg_data[86]
  PIN cfg_data[87]
    DIRECTION INPUT ;
    USE SIGNAL ;
    PORT
      LAYER M5 ;
        RECT  46.416 69.036 46.44 69.12 ;
    END
  END cfg_data[87]
  PIN cfg_data[88]
    DIRECTION INPUT ;
    USE SIGNAL ;
    PORT
      LAYER M5 ;
        RECT  46.512 69.036 46.536 69.12 ;
    END
  END cfg_data[88]
  PIN cfg_data[89]
    DIRECTION INPUT ;
    USE SIGNAL ;
    PORT
      LAYER M5 ;
        RECT  46.608 69.036 46.632 69.12 ;
    END
  END cfg_data[89]
  PIN cfg_data[8]
    DIRECTION INPUT ;
    USE SIGNAL ;
    PORT
      LAYER M5 ;
        RECT  41.904 69.036 41.928 69.12 ;
    END
  END cfg_data[8]
  PIN cfg_data[90]
    DIRECTION INPUT ;
    USE SIGNAL ;
    PORT
      LAYER M5 ;
        RECT  46.704 69.036 46.728 69.12 ;
    END
  END cfg_data[90]
  PIN cfg_data[91]
    DIRECTION INPUT ;
    USE SIGNAL ;
    PORT
      LAYER M5 ;
        RECT  46.8 69.036 46.824 69.12 ;
    END
  END cfg_data[91]
  PIN cfg_data[92]
    DIRECTION INPUT ;
    USE SIGNAL ;
    PORT
      LAYER M5 ;
        RECT  46.896 69.036 46.92 69.12 ;
    END
  END cfg_data[92]
  PIN cfg_data[93]
    DIRECTION INPUT ;
    USE SIGNAL ;
    PORT
      LAYER M5 ;
        RECT  46.992 69.036 47.016 69.12 ;
    END
  END cfg_data[93]
  PIN cfg_data[94]
    DIRECTION INPUT ;
    USE SIGNAL ;
    PORT
      LAYER M5 ;
        RECT  47.088 69.036 47.112 69.12 ;
    END
  END cfg_data[94]
  PIN cfg_data[95]
    DIRECTION INPUT ;
    USE SIGNAL ;
    PORT
      LAYER M5 ;
        RECT  47.184 69.036 47.208 69.12 ;
    END
  END cfg_data[95]
  PIN cfg_data[96]
    DIRECTION INPUT ;
    USE SIGNAL ;
    PORT
      LAYER M5 ;
        RECT  47.28 69.036 47.304 69.12 ;
    END
  END cfg_data[96]
  PIN cfg_data[97]
    DIRECTION INPUT ;
    USE SIGNAL ;
    PORT
      LAYER M5 ;
        RECT  47.376 69.036 47.4 69.12 ;
    END
  END cfg_data[97]
  PIN cfg_data[98]
    DIRECTION INPUT ;
    USE SIGNAL ;
    PORT
      LAYER M5 ;
        RECT  47.472 69.036 47.496 69.12 ;
    END
  END cfg_data[98]
  PIN cfg_data[99]
    DIRECTION INPUT ;
    USE SIGNAL ;
    PORT
      LAYER M5 ;
        RECT  47.568 69.036 47.592 69.12 ;
    END
  END cfg_data[99]
  PIN cfg_data[9]
    DIRECTION INPUT ;
    USE SIGNAL ;
    PORT
      LAYER M5 ;
        RECT  42 69.036 42.024 69.12 ;
    END
  END cfg_data[9]
  PIN cfg_target[0]
    DIRECTION INPUT ;
    USE SIGNAL ;
    PORT
      LAYER M5 ;
        RECT  21.936 69.036 21.96 69.12 ;
    END
  END cfg_target[0]
  PIN cfg_target[1]
    DIRECTION INPUT ;
    USE SIGNAL ;
    PORT
      LAYER M5 ;
        RECT  22.032 69.036 22.056 69.12 ;
    END
  END cfg_target[1]
  PIN cfg_target[2]
    DIRECTION INPUT ;
    USE SIGNAL ;
    PORT
      LAYER M5 ;
        RECT  22.128 69.036 22.152 69.12 ;
    END
  END cfg_target[2]
  PIN cfg_target[3]
    DIRECTION INPUT ;
    USE SIGNAL ;
    PORT
      LAYER M5 ;
        RECT  22.224 69.036 22.248 69.12 ;
    END
  END cfg_target[3]
  PIN cfg_target[4]
    DIRECTION INPUT ;
    USE SIGNAL ;
    PORT
      LAYER M5 ;
        RECT  22.32 69.036 22.344 69.12 ;
    END
  END cfg_target[4]
  PIN cfg_target[5]
    DIRECTION INPUT ;
    USE SIGNAL ;
    PORT
      LAYER M5 ;
        RECT  22.416 69.036 22.44 69.12 ;
    END
  END cfg_target[5]
  PIN cfg_target[6]
    DIRECTION INPUT ;
    USE SIGNAL ;
    PORT
      LAYER M5 ;
        RECT  22.512 69.036 22.536 69.12 ;
    END
  END cfg_target[6]
  PIN cfg_target[7]
    DIRECTION INPUT ;
    USE SIGNAL ;
    PORT
      LAYER M5 ;
        RECT  22.608 69.036 22.632 69.12 ;
    END
  END cfg_target[7]
  PIN cfg_v
    DIRECTION INPUT ;
    USE SIGNAL ;
    PORT
      LAYER M5 ;
        RECT  22.704 69.036 22.728 69.12 ;
    END
  END cfg_v
  PIN clk
    DIRECTION INPUT ;
    USE SIGNAL ;
    PORT
      LAYER M5 ;
        RECT  22.8 69.036 22.824 69.12 ;
    END
  END clk
  PIN desc_base[0]
    DIRECTION INPUT ;
    USE SIGNAL ;
    PORT
      LAYER M5 ;
        RECT  22.896 69.036 22.92 69.12 ;
    END
  END desc_base[0]
  PIN desc_base[10]
    DIRECTION INPUT ;
    USE SIGNAL ;
    PORT
      LAYER M5 ;
        RECT  17.712 69.036 17.736 69.12 ;
    END
  END desc_base[10]
  PIN desc_base[11]
    DIRECTION INPUT ;
    USE SIGNAL ;
    PORT
      LAYER M5 ;
        RECT  17.808 69.036 17.832 69.12 ;
    END
  END desc_base[11]
  PIN desc_base[1]
    DIRECTION INPUT ;
    USE SIGNAL ;
    PORT
      LAYER M5 ;
        RECT  22.992 69.036 23.016 69.12 ;
    END
  END desc_base[1]
  PIN desc_base[2]
    DIRECTION INPUT ;
    USE SIGNAL ;
    PORT
      LAYER M5 ;
        RECT  23.088 69.036 23.112 69.12 ;
    END
  END desc_base[2]
  PIN desc_base[3]
    DIRECTION INPUT ;
    USE SIGNAL ;
    PORT
      LAYER M5 ;
        RECT  23.184 69.036 23.208 69.12 ;
    END
  END desc_base[3]
  PIN desc_base[4]
    DIRECTION INPUT ;
    USE SIGNAL ;
    PORT
      LAYER M5 ;
        RECT  23.28 69.036 23.304 69.12 ;
    END
  END desc_base[4]
  PIN desc_base[5]
    DIRECTION INPUT ;
    USE SIGNAL ;
    PORT
      LAYER M5 ;
        RECT  23.376 69.036 23.4 69.12 ;
    END
  END desc_base[5]
  PIN desc_base[6]
    DIRECTION INPUT ;
    USE SIGNAL ;
    PORT
      LAYER M5 ;
        RECT  23.472 69.036 23.496 69.12 ;
    END
  END desc_base[6]
  PIN desc_base[7]
    DIRECTION INPUT ;
    USE SIGNAL ;
    PORT
      LAYER M5 ;
        RECT  23.568 69.036 23.592 69.12 ;
    END
  END desc_base[7]
  PIN desc_base[8]
    DIRECTION INPUT ;
    USE SIGNAL ;
    PORT
      LAYER M5 ;
        RECT  23.664 69.036 23.688 69.12 ;
    END
  END desc_base[8]
  PIN desc_base[9]
    DIRECTION INPUT ;
    USE SIGNAL ;
    PORT
      LAYER M5 ;
        RECT  23.76 69.036 23.784 69.12 ;
    END
  END desc_base[9]
  PIN desc_limit[0]
    DIRECTION INPUT ;
    USE SIGNAL ;
    PORT
      LAYER M5 ;
        RECT  17.904 69.036 17.928 69.12 ;
    END
  END desc_limit[0]
  PIN desc_limit[10]
    DIRECTION INPUT ;
    USE SIGNAL ;
    PORT
      LAYER M5 ;
        RECT  18.864 69.036 18.888 69.12 ;
    END
  END desc_limit[10]
  PIN desc_limit[11]
    DIRECTION INPUT ;
    USE SIGNAL ;
    PORT
      LAYER M5 ;
        RECT  18.96 69.036 18.984 69.12 ;
    END
  END desc_limit[11]
  PIN desc_limit[12]
    DIRECTION INPUT ;
    USE SIGNAL ;
    PORT
      LAYER M5 ;
        RECT  19.056 69.036 19.08 69.12 ;
    END
  END desc_limit[12]
  PIN desc_limit[1]
    DIRECTION INPUT ;
    USE SIGNAL ;
    PORT
      LAYER M5 ;
        RECT  18 69.036 18.024 69.12 ;
    END
  END desc_limit[1]
  PIN desc_limit[2]
    DIRECTION INPUT ;
    USE SIGNAL ;
    PORT
      LAYER M5 ;
        RECT  18.096 69.036 18.12 69.12 ;
    END
  END desc_limit[2]
  PIN desc_limit[3]
    DIRECTION INPUT ;
    USE SIGNAL ;
    PORT
      LAYER M5 ;
        RECT  18.192 69.036 18.216 69.12 ;
    END
  END desc_limit[3]
  PIN desc_limit[4]
    DIRECTION INPUT ;
    USE SIGNAL ;
    PORT
      LAYER M5 ;
        RECT  18.288 69.036 18.312 69.12 ;
    END
  END desc_limit[4]
  PIN desc_limit[5]
    DIRECTION INPUT ;
    USE SIGNAL ;
    PORT
      LAYER M5 ;
        RECT  18.384 69.036 18.408 69.12 ;
    END
  END desc_limit[5]
  PIN desc_limit[6]
    DIRECTION INPUT ;
    USE SIGNAL ;
    PORT
      LAYER M5 ;
        RECT  18.48 69.036 18.504 69.12 ;
    END
  END desc_limit[6]
  PIN desc_limit[7]
    DIRECTION INPUT ;
    USE SIGNAL ;
    PORT
      LAYER M5 ;
        RECT  18.576 69.036 18.6 69.12 ;
    END
  END desc_limit[7]
  PIN desc_limit[8]
    DIRECTION INPUT ;
    USE SIGNAL ;
    PORT
      LAYER M5 ;
        RECT  18.672 69.036 18.696 69.12 ;
    END
  END desc_limit[8]
  PIN desc_limit[9]
    DIRECTION INPUT ;
    USE SIGNAL ;
    PORT
      LAYER M5 ;
        RECT  18.768 69.036 18.792 69.12 ;
    END
  END desc_limit[9]
  PIN desc_loops[0]
    DIRECTION INPUT ;
    USE SIGNAL ;
    PORT
      LAYER M5 ;
        RECT  19.152 69.036 19.176 69.12 ;
    END
  END desc_loops[0]
  PIN desc_loops[10]
    DIRECTION INPUT ;
    USE SIGNAL ;
    PORT
      LAYER M5 ;
        RECT  20.112 69.036 20.136 69.12 ;
    END
  END desc_loops[10]
  PIN desc_loops[11]
    DIRECTION INPUT ;
    USE SIGNAL ;
    PORT
      LAYER M5 ;
        RECT  20.208 69.036 20.232 69.12 ;
    END
  END desc_loops[11]
  PIN desc_loops[12]
    DIRECTION INPUT ;
    USE SIGNAL ;
    PORT
      LAYER M5 ;
        RECT  20.304 69.036 20.328 69.12 ;
    END
  END desc_loops[12]
  PIN desc_loops[13]
    DIRECTION INPUT ;
    USE SIGNAL ;
    PORT
      LAYER M5 ;
        RECT  20.4 69.036 20.424 69.12 ;
    END
  END desc_loops[13]
  PIN desc_loops[14]
    DIRECTION INPUT ;
    USE SIGNAL ;
    PORT
      LAYER M5 ;
        RECT  20.496 69.036 20.52 69.12 ;
    END
  END desc_loops[14]
  PIN desc_loops[15]
    DIRECTION INPUT ;
    USE SIGNAL ;
    PORT
      LAYER M5 ;
        RECT  20.592 69.036 20.616 69.12 ;
    END
  END desc_loops[15]
  PIN desc_loops[1]
    DIRECTION INPUT ;
    USE SIGNAL ;
    PORT
      LAYER M5 ;
        RECT  19.248 69.036 19.272 69.12 ;
    END
  END desc_loops[1]
  PIN desc_loops[2]
    DIRECTION INPUT ;
    USE SIGNAL ;
    PORT
      LAYER M5 ;
        RECT  19.344 69.036 19.368 69.12 ;
    END
  END desc_loops[2]
  PIN desc_loops[3]
    DIRECTION INPUT ;
    USE SIGNAL ;
    PORT
      LAYER M5 ;
        RECT  19.44 69.036 19.464 69.12 ;
    END
  END desc_loops[3]
  PIN desc_loops[4]
    DIRECTION INPUT ;
    USE SIGNAL ;
    PORT
      LAYER M5 ;
        RECT  19.536 69.036 19.56 69.12 ;
    END
  END desc_loops[4]
  PIN desc_loops[5]
    DIRECTION INPUT ;
    USE SIGNAL ;
    PORT
      LAYER M5 ;
        RECT  19.632 69.036 19.656 69.12 ;
    END
  END desc_loops[5]
  PIN desc_loops[6]
    DIRECTION INPUT ;
    USE SIGNAL ;
    PORT
      LAYER M5 ;
        RECT  19.728 69.036 19.752 69.12 ;
    END
  END desc_loops[6]
  PIN desc_loops[7]
    DIRECTION INPUT ;
    USE SIGNAL ;
    PORT
      LAYER M5 ;
        RECT  19.824 69.036 19.848 69.12 ;
    END
  END desc_loops[7]
  PIN desc_loops[8]
    DIRECTION INPUT ;
    USE SIGNAL ;
    PORT
      LAYER M5 ;
        RECT  19.92 69.036 19.944 69.12 ;
    END
  END desc_loops[8]
  PIN desc_loops[9]
    DIRECTION INPUT ;
    USE SIGNAL ;
    PORT
      LAYER M5 ;
        RECT  20.016 69.036 20.04 69.12 ;
    END
  END desc_loops[9]
  PIN desc_v
    DIRECTION INPUT ;
    USE SIGNAL ;
    PORT
      LAYER M5 ;
        RECT  20.688 69.036 20.712 69.12 ;
    END
  END desc_v
  PIN launch_v
    DIRECTION INPUT ;
    USE SIGNAL ;
    PORT
      LAYER M5 ;
        RECT  30.576 69.036 30.6 69.12 ;
    END
  END launch_v
  PIN rst_n
    DIRECTION INPUT ;
    USE SIGNAL ;
    PORT
      LAYER M5 ;
        RECT  30.672 69.036 30.696 69.12 ;
    END
  END rst_n
  PIN s_active[0]
    DIRECTION OUTPUT ;
    USE SIGNAL ;
    PORT
      LAYER M5 ;
        RECT  42.192 0 42.216 0.084 ;
    END
  END s_active[0]
  PIN s_active[10]
    DIRECTION OUTPUT ;
    USE SIGNAL ;
    PORT
      LAYER M5 ;
        RECT  43.152 0 43.176 0.084 ;
    END
  END s_active[10]
  PIN s_active[11]
    DIRECTION OUTPUT ;
    USE SIGNAL ;
    PORT
      LAYER M5 ;
        RECT  43.248 0 43.272 0.084 ;
    END
  END s_active[11]
  PIN s_active[12]
    DIRECTION OUTPUT ;
    USE SIGNAL ;
    PORT
      LAYER M5 ;
        RECT  43.344 0 43.368 0.084 ;
    END
  END s_active[12]
  PIN s_active[13]
    DIRECTION OUTPUT ;
    USE SIGNAL ;
    PORT
      LAYER M5 ;
        RECT  43.44 0 43.464 0.084 ;
    END
  END s_active[13]
  PIN s_active[14]
    DIRECTION OUTPUT ;
    USE SIGNAL ;
    PORT
      LAYER M5 ;
        RECT  43.536 0 43.56 0.084 ;
    END
  END s_active[14]
  PIN s_active[15]
    DIRECTION OUTPUT ;
    USE SIGNAL ;
    PORT
      LAYER M5 ;
        RECT  43.632 0 43.656 0.084 ;
    END
  END s_active[15]
  PIN s_active[16]
    DIRECTION OUTPUT ;
    USE SIGNAL ;
    PORT
      LAYER M5 ;
        RECT  43.728 0 43.752 0.084 ;
    END
  END s_active[16]
  PIN s_active[17]
    DIRECTION OUTPUT ;
    USE SIGNAL ;
    PORT
      LAYER M5 ;
        RECT  43.824 0 43.848 0.084 ;
    END
  END s_active[17]
  PIN s_active[1]
    DIRECTION OUTPUT ;
    USE SIGNAL ;
    PORT
      LAYER M5 ;
        RECT  42.288 0 42.312 0.084 ;
    END
  END s_active[1]
  PIN s_active[2]
    DIRECTION OUTPUT ;
    USE SIGNAL ;
    PORT
      LAYER M5 ;
        RECT  42.384 0 42.408 0.084 ;
    END
  END s_active[2]
  PIN s_active[3]
    DIRECTION OUTPUT ;
    USE SIGNAL ;
    PORT
      LAYER M5 ;
        RECT  42.48 0 42.504 0.084 ;
    END
  END s_active[3]
  PIN s_active[4]
    DIRECTION OUTPUT ;
    USE SIGNAL ;
    PORT
      LAYER M5 ;
        RECT  42.576 0 42.6 0.084 ;
    END
  END s_active[4]
  PIN s_active[5]
    DIRECTION OUTPUT ;
    USE SIGNAL ;
    PORT
      LAYER M5 ;
        RECT  42.672 0 42.696 0.084 ;
    END
  END s_active[5]
  PIN s_active[6]
    DIRECTION OUTPUT ;
    USE SIGNAL ;
    PORT
      LAYER M5 ;
        RECT  42.768 0 42.792 0.084 ;
    END
  END s_active[6]
  PIN s_active[7]
    DIRECTION OUTPUT ;
    USE SIGNAL ;
    PORT
      LAYER M5 ;
        RECT  42.864 0 42.888 0.084 ;
    END
  END s_active[7]
  PIN s_active[8]
    DIRECTION OUTPUT ;
    USE SIGNAL ;
    PORT
      LAYER M5 ;
        RECT  42.96 0 42.984 0.084 ;
    END
  END s_active[8]
  PIN s_active[9]
    DIRECTION OUTPUT ;
    USE SIGNAL ;
    PORT
      LAYER M5 ;
        RECT  43.056 0 43.08 0.084 ;
    END
  END s_active[9]
  PIN s_fault[0]
    DIRECTION OUTPUT ;
    USE SIGNAL ;
    PORT
      LAYER M5 ;
        RECT  43.92 0 43.944 0.084 ;
    END
  END s_fault[0]
  PIN s_fault[10]
    DIRECTION OUTPUT ;
    USE SIGNAL ;
    PORT
      LAYER M5 ;
        RECT  44.88 0 44.904 0.084 ;
    END
  END s_fault[10]
  PIN s_fault[11]
    DIRECTION OUTPUT ;
    USE SIGNAL ;
    PORT
      LAYER M5 ;
        RECT  44.976 0 45 0.084 ;
    END
  END s_fault[11]
  PIN s_fault[12]
    DIRECTION OUTPUT ;
    USE SIGNAL ;
    PORT
      LAYER M5 ;
        RECT  45.072 0 45.096 0.084 ;
    END
  END s_fault[12]
  PIN s_fault[13]
    DIRECTION OUTPUT ;
    USE SIGNAL ;
    PORT
      LAYER M5 ;
        RECT  45.168 0 45.192 0.084 ;
    END
  END s_fault[13]
  PIN s_fault[14]
    DIRECTION OUTPUT ;
    USE SIGNAL ;
    PORT
      LAYER M5 ;
        RECT  39.12 0 39.144 0.084 ;
    END
  END s_fault[14]
  PIN s_fault[15]
    DIRECTION OUTPUT ;
    USE SIGNAL ;
    PORT
      LAYER M5 ;
        RECT  39.216 0 39.24 0.084 ;
    END
  END s_fault[15]
  PIN s_fault[16]
    DIRECTION OUTPUT ;
    USE SIGNAL ;
    PORT
      LAYER M5 ;
        RECT  39.312 0 39.336 0.084 ;
    END
  END s_fault[16]
  PIN s_fault[17]
    DIRECTION OUTPUT ;
    USE SIGNAL ;
    PORT
      LAYER M5 ;
        RECT  39.408 0 39.432 0.084 ;
    END
  END s_fault[17]
  PIN s_fault[18]
    DIRECTION OUTPUT ;
    USE SIGNAL ;
    PORT
      LAYER M5 ;
        RECT  39.504 0 39.528 0.084 ;
    END
  END s_fault[18]
  PIN s_fault[19]
    DIRECTION OUTPUT ;
    USE SIGNAL ;
    PORT
      LAYER M5 ;
        RECT  39.6 0 39.624 0.084 ;
    END
  END s_fault[19]
  PIN s_fault[1]
    DIRECTION OUTPUT ;
    USE SIGNAL ;
    PORT
      LAYER M5 ;
        RECT  44.016 0 44.04 0.084 ;
    END
  END s_fault[1]
  PIN s_fault[20]
    DIRECTION OUTPUT ;
    USE SIGNAL ;
    PORT
      LAYER M5 ;
        RECT  39.696 0 39.72 0.084 ;
    END
  END s_fault[20]
  PIN s_fault[21]
    DIRECTION OUTPUT ;
    USE SIGNAL ;
    PORT
      LAYER M5 ;
        RECT  39.792 0 39.816 0.084 ;
    END
  END s_fault[21]
  PIN s_fault[22]
    DIRECTION OUTPUT ;
    USE SIGNAL ;
    PORT
      LAYER M5 ;
        RECT  39.888 0 39.912 0.084 ;
    END
  END s_fault[22]
  PIN s_fault[23]
    DIRECTION OUTPUT ;
    USE SIGNAL ;
    PORT
      LAYER M5 ;
        RECT  39.984 0 40.008 0.084 ;
    END
  END s_fault[23]
  PIN s_fault[24]
    DIRECTION OUTPUT ;
    USE SIGNAL ;
    PORT
      LAYER M5 ;
        RECT  40.08 0 40.104 0.084 ;
    END
  END s_fault[24]
  PIN s_fault[25]
    DIRECTION OUTPUT ;
    USE SIGNAL ;
    PORT
      LAYER M5 ;
        RECT  40.176 0 40.2 0.084 ;
    END
  END s_fault[25]
  PIN s_fault[2]
    DIRECTION OUTPUT ;
    USE SIGNAL ;
    PORT
      LAYER M5 ;
        RECT  44.112 0 44.136 0.084 ;
    END
  END s_fault[2]
  PIN s_fault[3]
    DIRECTION OUTPUT ;
    USE SIGNAL ;
    PORT
      LAYER M5 ;
        RECT  44.208 0 44.232 0.084 ;
    END
  END s_fault[3]
  PIN s_fault[4]
    DIRECTION OUTPUT ;
    USE SIGNAL ;
    PORT
      LAYER M5 ;
        RECT  44.304 0 44.328 0.084 ;
    END
  END s_fault[4]
  PIN s_fault[5]
    DIRECTION OUTPUT ;
    USE SIGNAL ;
    PORT
      LAYER M5 ;
        RECT  44.4 0 44.424 0.084 ;
    END
  END s_fault[5]
  PIN s_fault[6]
    DIRECTION OUTPUT ;
    USE SIGNAL ;
    PORT
      LAYER M5 ;
        RECT  44.496 0 44.52 0.084 ;
    END
  END s_fault[6]
  PIN s_fault[7]
    DIRECTION OUTPUT ;
    USE SIGNAL ;
    PORT
      LAYER M5 ;
        RECT  44.592 0 44.616 0.084 ;
    END
  END s_fault[7]
  PIN s_fault[8]
    DIRECTION OUTPUT ;
    USE SIGNAL ;
    PORT
      LAYER M5 ;
        RECT  44.688 0 44.712 0.084 ;
    END
  END s_fault[8]
  PIN s_fault[9]
    DIRECTION OUTPUT ;
    USE SIGNAL ;
    PORT
      LAYER M5 ;
        RECT  44.784 0 44.808 0.084 ;
    END
  END s_fault[9]
  PIN s_ready[0]
    DIRECTION OUTPUT ;
    USE SIGNAL ;
    PORT
      LAYER M5 ;
        RECT  40.272 0 40.296 0.084 ;
    END
  END s_ready[0]
  PIN s_ready[10]
    DIRECTION OUTPUT ;
    USE SIGNAL ;
    PORT
      LAYER M5 ;
        RECT  41.232 0 41.256 0.084 ;
    END
  END s_ready[10]
  PIN s_ready[11]
    DIRECTION OUTPUT ;
    USE SIGNAL ;
    PORT
      LAYER M5 ;
        RECT  41.328 0 41.352 0.084 ;
    END
  END s_ready[11]
  PIN s_ready[12]
    DIRECTION OUTPUT ;
    USE SIGNAL ;
    PORT
      LAYER M5 ;
        RECT  41.424 0 41.448 0.084 ;
    END
  END s_ready[12]
  PIN s_ready[13]
    DIRECTION OUTPUT ;
    USE SIGNAL ;
    PORT
      LAYER M5 ;
        RECT  41.52 0 41.544 0.084 ;
    END
  END s_ready[13]
  PIN s_ready[14]
    DIRECTION OUTPUT ;
    USE SIGNAL ;
    PORT
      LAYER M5 ;
        RECT  41.616 0 41.64 0.084 ;
    END
  END s_ready[14]
  PIN s_ready[15]
    DIRECTION OUTPUT ;
    USE SIGNAL ;
    PORT
      LAYER M5 ;
        RECT  41.712 0 41.736 0.084 ;
    END
  END s_ready[15]
  PIN s_ready[16]
    DIRECTION OUTPUT ;
    USE SIGNAL ;
    PORT
      LAYER M5 ;
        RECT  41.808 0 41.832 0.084 ;
    END
  END s_ready[16]
  PIN s_ready[17]
    DIRECTION OUTPUT ;
    USE SIGNAL ;
    PORT
      LAYER M5 ;
        RECT  41.904 0 41.928 0.084 ;
    END
  END s_ready[17]
  PIN s_ready[1]
    DIRECTION OUTPUT ;
    USE SIGNAL ;
    PORT
      LAYER M5 ;
        RECT  40.368 0 40.392 0.084 ;
    END
  END s_ready[1]
  PIN s_ready[2]
    DIRECTION OUTPUT ;
    USE SIGNAL ;
    PORT
      LAYER M5 ;
        RECT  40.464 0 40.488 0.084 ;
    END
  END s_ready[2]
  PIN s_ready[3]
    DIRECTION OUTPUT ;
    USE SIGNAL ;
    PORT
      LAYER M5 ;
        RECT  40.56 0 40.584 0.084 ;
    END
  END s_ready[3]
  PIN s_ready[4]
    DIRECTION OUTPUT ;
    USE SIGNAL ;
    PORT
      LAYER M5 ;
        RECT  40.656 0 40.68 0.084 ;
    END
  END s_ready[4]
  PIN s_ready[5]
    DIRECTION OUTPUT ;
    USE SIGNAL ;
    PORT
      LAYER M5 ;
        RECT  40.752 0 40.776 0.084 ;
    END
  END s_ready[5]
  PIN s_ready[6]
    DIRECTION OUTPUT ;
    USE SIGNAL ;
    PORT
      LAYER M5 ;
        RECT  40.848 0 40.872 0.084 ;
    END
  END s_ready[6]
  PIN s_ready[7]
    DIRECTION OUTPUT ;
    USE SIGNAL ;
    PORT
      LAYER M5 ;
        RECT  40.944 0 40.968 0.084 ;
    END
  END s_ready[7]
  PIN s_ready[8]
    DIRECTION OUTPUT ;
    USE SIGNAL ;
    PORT
      LAYER M5 ;
        RECT  41.04 0 41.064 0.084 ;
    END
  END s_ready[8]
  PIN s_ready[9]
    DIRECTION OUTPUT ;
    USE SIGNAL ;
    PORT
      LAYER M5 ;
        RECT  41.136 0 41.16 0.084 ;
    END
  END s_ready[9]
  PIN t_active[0]
    DIRECTION INPUT ;
    USE SIGNAL ;
    PORT
      LAYER M5 ;
        RECT  42 0 42.024 0.084 ;
    END
  END t_active[0]
  PIN t_active[10]
    DIRECTION INPUT ;
    USE SIGNAL ;
    PORT
      LAYER M5 ;
        RECT  36.048 0 36.072 0.084 ;
    END
  END t_active[10]
  PIN t_active[11]
    DIRECTION INPUT ;
    USE SIGNAL ;
    PORT
      LAYER M5 ;
        RECT  36.144 0 36.168 0.084 ;
    END
  END t_active[11]
  PIN t_active[12]
    DIRECTION INPUT ;
    USE SIGNAL ;
    PORT
      LAYER M5 ;
        RECT  36.24 0 36.264 0.084 ;
    END
  END t_active[12]
  PIN t_active[13]
    DIRECTION INPUT ;
    USE SIGNAL ;
    PORT
      LAYER M5 ;
        RECT  36.336 0 36.36 0.084 ;
    END
  END t_active[13]
  PIN t_active[14]
    DIRECTION INPUT ;
    USE SIGNAL ;
    PORT
      LAYER M5 ;
        RECT  36.432 0 36.456 0.084 ;
    END
  END t_active[14]
  PIN t_active[15]
    DIRECTION INPUT ;
    USE SIGNAL ;
    PORT
      LAYER M5 ;
        RECT  36.528 0 36.552 0.084 ;
    END
  END t_active[15]
  PIN t_active[16]
    DIRECTION INPUT ;
    USE SIGNAL ;
    PORT
      LAYER M5 ;
        RECT  36.624 0 36.648 0.084 ;
    END
  END t_active[16]
  PIN t_active[17]
    DIRECTION INPUT ;
    USE SIGNAL ;
    PORT
      LAYER M5 ;
        RECT  36.72 0 36.744 0.084 ;
    END
  END t_active[17]
  PIN t_active[1]
    DIRECTION INPUT ;
    USE SIGNAL ;
    PORT
      LAYER M5 ;
        RECT  42.096 0 42.12 0.084 ;
    END
  END t_active[1]
  PIN t_active[2]
    DIRECTION INPUT ;
    USE SIGNAL ;
    PORT
      LAYER M5 ;
        RECT  35.28 0 35.304 0.084 ;
    END
  END t_active[2]
  PIN t_active[3]
    DIRECTION INPUT ;
    USE SIGNAL ;
    PORT
      LAYER M5 ;
        RECT  35.376 0 35.4 0.084 ;
    END
  END t_active[3]
  PIN t_active[4]
    DIRECTION INPUT ;
    USE SIGNAL ;
    PORT
      LAYER M5 ;
        RECT  35.472 0 35.496 0.084 ;
    END
  END t_active[4]
  PIN t_active[5]
    DIRECTION INPUT ;
    USE SIGNAL ;
    PORT
      LAYER M5 ;
        RECT  35.568 0 35.592 0.084 ;
    END
  END t_active[5]
  PIN t_active[6]
    DIRECTION INPUT ;
    USE SIGNAL ;
    PORT
      LAYER M5 ;
        RECT  35.664 0 35.688 0.084 ;
    END
  END t_active[6]
  PIN t_active[7]
    DIRECTION INPUT ;
    USE SIGNAL ;
    PORT
      LAYER M5 ;
        RECT  35.76 0 35.784 0.084 ;
    END
  END t_active[7]
  PIN t_active[8]
    DIRECTION INPUT ;
    USE SIGNAL ;
    PORT
      LAYER M5 ;
        RECT  35.856 0 35.88 0.084 ;
    END
  END t_active[8]
  PIN t_active[9]
    DIRECTION INPUT ;
    USE SIGNAL ;
    PORT
      LAYER M5 ;
        RECT  35.952 0 35.976 0.084 ;
    END
  END t_active[9]
  PIN t_fault[0]
    DIRECTION INPUT ;
    USE SIGNAL ;
    PORT
      LAYER M5 ;
        RECT  36.816 0 36.84 0.084 ;
    END
  END t_fault[0]
  PIN t_fault[10]
    DIRECTION INPUT ;
    USE SIGNAL ;
    PORT
      LAYER M5 ;
        RECT  37.776 0 37.8 0.084 ;
    END
  END t_fault[10]
  PIN t_fault[11]
    DIRECTION INPUT ;
    USE SIGNAL ;
    PORT
      LAYER M5 ;
        RECT  37.872 0 37.896 0.084 ;
    END
  END t_fault[11]
  PIN t_fault[12]
    DIRECTION INPUT ;
    USE SIGNAL ;
    PORT
      LAYER M5 ;
        RECT  37.968 0 37.992 0.084 ;
    END
  END t_fault[12]
  PIN t_fault[13]
    DIRECTION INPUT ;
    USE SIGNAL ;
    PORT
      LAYER M5 ;
        RECT  38.064 0 38.088 0.084 ;
    END
  END t_fault[13]
  PIN t_fault[14]
    DIRECTION INPUT ;
    USE SIGNAL ;
    PORT
      LAYER M5 ;
        RECT  38.16 0 38.184 0.084 ;
    END
  END t_fault[14]
  PIN t_fault[15]
    DIRECTION INPUT ;
    USE SIGNAL ;
    PORT
      LAYER M5 ;
        RECT  38.256 0 38.28 0.084 ;
    END
  END t_fault[15]
  PIN t_fault[16]
    DIRECTION INPUT ;
    USE SIGNAL ;
    PORT
      LAYER M5 ;
        RECT  32.208 0 32.232 0.084 ;
    END
  END t_fault[16]
  PIN t_fault[17]
    DIRECTION INPUT ;
    USE SIGNAL ;
    PORT
      LAYER M5 ;
        RECT  32.304 0 32.328 0.084 ;
    END
  END t_fault[17]
  PIN t_fault[18]
    DIRECTION INPUT ;
    USE SIGNAL ;
    PORT
      LAYER M5 ;
        RECT  32.4 0 32.424 0.084 ;
    END
  END t_fault[18]
  PIN t_fault[19]
    DIRECTION INPUT ;
    USE SIGNAL ;
    PORT
      LAYER M5 ;
        RECT  32.496 0 32.52 0.084 ;
    END
  END t_fault[19]
  PIN t_fault[1]
    DIRECTION INPUT ;
    USE SIGNAL ;
    PORT
      LAYER M5 ;
        RECT  36.912 0 36.936 0.084 ;
    END
  END t_fault[1]
  PIN t_fault[20]
    DIRECTION INPUT ;
    USE SIGNAL ;
    PORT
      LAYER M5 ;
        RECT  32.592 0 32.616 0.084 ;
    END
  END t_fault[20]
  PIN t_fault[21]
    DIRECTION INPUT ;
    USE SIGNAL ;
    PORT
      LAYER M5 ;
        RECT  32.688 0 32.712 0.084 ;
    END
  END t_fault[21]
  PIN t_fault[22]
    DIRECTION INPUT ;
    USE SIGNAL ;
    PORT
      LAYER M5 ;
        RECT  32.784 0 32.808 0.084 ;
    END
  END t_fault[22]
  PIN t_fault[23]
    DIRECTION INPUT ;
    USE SIGNAL ;
    PORT
      LAYER M5 ;
        RECT  32.88 0 32.904 0.084 ;
    END
  END t_fault[23]
  PIN t_fault[24]
    DIRECTION INPUT ;
    USE SIGNAL ;
    PORT
      LAYER M5 ;
        RECT  32.976 0 33 0.084 ;
    END
  END t_fault[24]
  PIN t_fault[25]
    DIRECTION INPUT ;
    USE SIGNAL ;
    PORT
      LAYER M5 ;
        RECT  33.072 0 33.096 0.084 ;
    END
  END t_fault[25]
  PIN t_fault[2]
    DIRECTION INPUT ;
    USE SIGNAL ;
    PORT
      LAYER M5 ;
        RECT  37.008 0 37.032 0.084 ;
    END
  END t_fault[2]
  PIN t_fault[3]
    DIRECTION INPUT ;
    USE SIGNAL ;
    PORT
      LAYER M5 ;
        RECT  37.104 0 37.128 0.084 ;
    END
  END t_fault[3]
  PIN t_fault[4]
    DIRECTION INPUT ;
    USE SIGNAL ;
    PORT
      LAYER M5 ;
        RECT  37.2 0 37.224 0.084 ;
    END
  END t_fault[4]
  PIN t_fault[5]
    DIRECTION INPUT ;
    USE SIGNAL ;
    PORT
      LAYER M5 ;
        RECT  37.296 0 37.32 0.084 ;
    END
  END t_fault[5]
  PIN t_fault[6]
    DIRECTION INPUT ;
    USE SIGNAL ;
    PORT
      LAYER M5 ;
        RECT  37.392 0 37.416 0.084 ;
    END
  END t_fault[6]
  PIN t_fault[7]
    DIRECTION INPUT ;
    USE SIGNAL ;
    PORT
      LAYER M5 ;
        RECT  37.488 0 37.512 0.084 ;
    END
  END t_fault[7]
  PIN t_fault[8]
    DIRECTION INPUT ;
    USE SIGNAL ;
    PORT
      LAYER M5 ;
        RECT  37.584 0 37.608 0.084 ;
    END
  END t_fault[8]
  PIN t_fault[9]
    DIRECTION INPUT ;
    USE SIGNAL ;
    PORT
      LAYER M5 ;
        RECT  37.68 0 37.704 0.084 ;
    END
  END t_fault[9]
  PIN t_ready[0]
    DIRECTION INPUT ;
    USE SIGNAL ;
    PORT
      LAYER M5 ;
        RECT  33.168 0 33.192 0.084 ;
    END
  END t_ready[0]
  PIN t_ready[10]
    DIRECTION INPUT ;
    USE SIGNAL ;
    PORT
      LAYER M5 ;
        RECT  34.128 0 34.152 0.084 ;
    END
  END t_ready[10]
  PIN t_ready[11]
    DIRECTION INPUT ;
    USE SIGNAL ;
    PORT
      LAYER M5 ;
        RECT  34.224 0 34.248 0.084 ;
    END
  END t_ready[11]
  PIN t_ready[12]
    DIRECTION INPUT ;
    USE SIGNAL ;
    PORT
      LAYER M5 ;
        RECT  34.32 0 34.344 0.084 ;
    END
  END t_ready[12]
  PIN t_ready[13]
    DIRECTION INPUT ;
    USE SIGNAL ;
    PORT
      LAYER M5 ;
        RECT  34.416 0 34.44 0.084 ;
    END
  END t_ready[13]
  PIN t_ready[14]
    DIRECTION INPUT ;
    USE SIGNAL ;
    PORT
      LAYER M5 ;
        RECT  34.512 0 34.536 0.084 ;
    END
  END t_ready[14]
  PIN t_ready[15]
    DIRECTION INPUT ;
    USE SIGNAL ;
    PORT
      LAYER M5 ;
        RECT  34.608 0 34.632 0.084 ;
    END
  END t_ready[15]
  PIN t_ready[16]
    DIRECTION INPUT ;
    USE SIGNAL ;
    PORT
      LAYER M5 ;
        RECT  34.704 0 34.728 0.084 ;
    END
  END t_ready[16]
  PIN t_ready[17]
    DIRECTION INPUT ;
    USE SIGNAL ;
    PORT
      LAYER M5 ;
        RECT  34.8 0 34.824 0.084 ;
    END
  END t_ready[17]
  PIN t_ready[1]
    DIRECTION INPUT ;
    USE SIGNAL ;
    PORT
      LAYER M5 ;
        RECT  33.264 0 33.288 0.084 ;
    END
  END t_ready[1]
  PIN t_ready[2]
    DIRECTION INPUT ;
    USE SIGNAL ;
    PORT
      LAYER M5 ;
        RECT  33.36 0 33.384 0.084 ;
    END
  END t_ready[2]
  PIN t_ready[3]
    DIRECTION INPUT ;
    USE SIGNAL ;
    PORT
      LAYER M5 ;
        RECT  33.456 0 33.48 0.084 ;
    END
  END t_ready[3]
  PIN t_ready[4]
    DIRECTION INPUT ;
    USE SIGNAL ;
    PORT
      LAYER M5 ;
        RECT  33.552 0 33.576 0.084 ;
    END
  END t_ready[4]
  PIN t_ready[5]
    DIRECTION INPUT ;
    USE SIGNAL ;
    PORT
      LAYER M5 ;
        RECT  33.648 0 33.672 0.084 ;
    END
  END t_ready[5]
  PIN t_ready[6]
    DIRECTION INPUT ;
    USE SIGNAL ;
    PORT
      LAYER M5 ;
        RECT  33.744 0 33.768 0.084 ;
    END
  END t_ready[6]
  PIN t_ready[7]
    DIRECTION INPUT ;
    USE SIGNAL ;
    PORT
      LAYER M5 ;
        RECT  33.84 0 33.864 0.084 ;
    END
  END t_ready[7]
  PIN t_ready[8]
    DIRECTION INPUT ;
    USE SIGNAL ;
    PORT
      LAYER M5 ;
        RECT  33.936 0 33.96 0.084 ;
    END
  END t_ready[8]
  PIN t_ready[9]
    DIRECTION INPUT ;
    USE SIGNAL ;
    PORT
      LAYER M5 ;
        RECT  34.032 0 34.056 0.084 ;
    END
  END t_ready[9]
  PIN VDD
    DIRECTION INOUT ;
    USE POWER ;
    PORT
      LAYER M5 ;
        RECT  61.992 2.151 62.112 66.969 ;
        RECT  56.592 2.151 56.712 66.969 ;
        RECT  51.192 2.151 51.312 66.969 ;
        RECT  45.792 2.151 45.912 66.969 ;
        RECT  40.392 2.151 40.512 66.969 ;
        RECT  34.992 2.151 35.112 66.969 ;
        RECT  29.592 2.151 29.712 66.969 ;
        RECT  24.192 2.151 24.312 66.969 ;
        RECT  18.792 2.151 18.912 66.969 ;
        RECT  13.392 2.151 13.512 66.969 ;
        RECT  7.992 2.151 8.112 66.969 ;
        RECT  2.592 2.151 2.712 66.969 ;
    END
  END VDD
  PIN VSS
    DIRECTION INOUT ;
    USE GROUND ;
    PORT
      LAYER M5 ;
        RECT  61.8 2.137 61.92 66.983 ;
        RECT  56.4 2.137 56.52 66.983 ;
        RECT  51 2.137 51.12 66.983 ;
        RECT  45.6 2.137 45.72 66.983 ;
        RECT  40.2 2.137 40.32 66.983 ;
        RECT  34.8 2.137 34.92 66.983 ;
        RECT  29.4 2.137 29.52 66.983 ;
        RECT  24 2.137 24.12 66.983 ;
        RECT  18.6 2.137 18.72 66.983 ;
        RECT  13.2 2.137 13.32 66.983 ;
        RECT  7.8 2.137 7.92 66.983 ;
        RECT  2.4 2.137 2.52 66.983 ;
    END
  END VSS
  # OT_OBS_CLOSED layer=M5 d_um=1.536 added=34
  OBS
    LAYER RVTN ;
     RECT  2.16 2.16 66.96 2.295 ;
     RECT  2.16 2.565 66.96 2.835 ;
     RECT  2.16 3.105 66.96 3.375 ;
     RECT  2.16 3.645 66.96 3.915 ;
     RECT  2.16 4.185 66.96 4.455 ;
     RECT  2.16 4.725 66.96 4.995 ;
     RECT  2.16 5.265 66.96 5.535 ;
     RECT  2.16 5.805 66.96 6.075 ;
     RECT  2.16 6.345 66.96 6.615 ;
     RECT  2.16 6.885 66.96 7.155 ;
     RECT  2.16 7.425 66.96 7.695 ;
     RECT  2.16 7.965 66.96 8.235 ;
     RECT  2.16 8.505 66.96 8.775 ;
     RECT  2.16 9.045 66.96 9.315 ;
     RECT  2.16 9.585 66.96 9.855 ;
     RECT  2.16 10.125 66.96 10.395 ;
     RECT  2.16 10.665 66.96 10.935 ;
     RECT  2.16 11.205 66.96 11.475 ;
     RECT  2.16 11.745 66.96 12.015 ;
     RECT  2.16 12.285 66.96 12.555 ;
     RECT  2.16 12.825 66.96 13.095 ;
     RECT  2.16 13.365 66.96 13.635 ;
     RECT  2.16 13.905 66.96 14.175 ;
     RECT  2.16 14.445 66.96 14.715 ;
     RECT  2.16 14.985 66.96 15.255 ;
     RECT  2.16 15.525 66.96 15.795 ;
     RECT  2.16 16.065 66.96 16.335 ;
     RECT  2.16 16.605 66.96 16.875 ;
     RECT  2.16 17.145 66.96 17.415 ;
     RECT  2.16 17.685 66.96 17.955 ;
     RECT  2.16 18.225 66.96 18.495 ;
     RECT  2.16 18.765 66.96 19.035 ;
     RECT  2.16 19.305 66.96 19.575 ;
     RECT  2.16 19.845 66.96 20.115 ;
     RECT  2.16 20.385 66.96 20.655 ;
     RECT  2.16 20.925 66.96 21.195 ;
     RECT  2.16 21.465 66.96 21.735 ;
     RECT  2.16 22.005 66.96 22.275 ;
     RECT  2.16 22.545 66.96 22.815 ;
     RECT  2.16 23.085 66.96 23.355 ;
     RECT  2.16 23.625 66.96 23.895 ;
     RECT  2.16 24.165 66.96 24.435 ;
     RECT  2.16 24.705 66.96 24.975 ;
     RECT  2.16 25.245 66.96 25.515 ;
     RECT  2.16 25.785 66.96 26.055 ;
     RECT  2.16 26.325 66.96 26.595 ;
     RECT  2.16 26.865 66.96 27.135 ;
     RECT  2.16 27.405 66.96 27.675 ;
     RECT  2.16 27.945 66.96 28.215 ;
     RECT  2.16 28.485 66.96 28.755 ;
     RECT  2.16 29.025 66.96 29.295 ;
     RECT  2.16 29.565 66.96 29.835 ;
     RECT  2.16 30.105 66.96 30.375 ;
     RECT  2.16 30.645 66.96 30.915 ;
     RECT  2.16 31.185 66.96 31.455 ;
     RECT  2.16 31.725 66.96 31.995 ;
     RECT  2.16 32.265 66.96 32.535 ;
     RECT  2.16 32.805 66.96 33.075 ;
     RECT  2.16 33.345 66.96 33.615 ;
     RECT  2.16 33.885 66.96 34.155 ;
     RECT  2.16 34.425 66.96 34.695 ;
     RECT  2.16 34.965 66.96 35.235 ;
     RECT  2.16 35.505 66.96 35.775 ;
     RECT  2.16 36.045 66.96 36.315 ;
     RECT  2.16 36.585 66.96 36.855 ;
     RECT  2.16 37.125 66.96 37.395 ;
     RECT  2.16 37.665 66.96 37.935 ;
     RECT  2.16 38.205 66.96 38.475 ;
     RECT  2.16 38.745 66.96 39.015 ;
     RECT  2.16 39.285 66.96 39.555 ;
     RECT  2.16 39.825 66.96 40.095 ;
     RECT  2.16 40.365 66.96 40.635 ;
     RECT  2.16 40.905 66.96 41.175 ;
     RECT  2.16 41.445 66.96 41.715 ;
     RECT  2.16 41.985 66.96 42.255 ;
     RECT  2.16 42.525 66.96 42.795 ;
     RECT  2.16 43.065 66.96 43.335 ;
     RECT  2.16 43.605 66.96 43.875 ;
     RECT  2.16 44.145 66.96 44.415 ;
     RECT  2.16 44.685 66.96 44.955 ;
     RECT  2.16 45.225 66.96 45.495 ;
     RECT  2.16 45.765 66.96 46.035 ;
     RECT  2.16 46.305 66.96 46.575 ;
     RECT  2.16 46.845 66.96 47.115 ;
     RECT  2.16 47.385 66.96 47.655 ;
     RECT  2.16 47.925 66.96 48.195 ;
     RECT  2.16 48.465 66.96 48.735 ;
     RECT  2.16 49.005 66.96 49.275 ;
     RECT  2.16 49.545 66.96 49.815 ;
     RECT  2.16 50.085 66.96 50.355 ;
     RECT  2.16 50.625 66.96 50.895 ;
     RECT  2.16 51.165 66.96 51.435 ;
     RECT  2.16 51.705 66.96 51.975 ;
     RECT  2.16 52.245 66.96 52.515 ;
     RECT  2.16 52.785 66.96 53.055 ;
     RECT  2.16 53.325 66.96 53.595 ;
     RECT  2.16 53.865 66.96 54.135 ;
     RECT  2.16 54.405 66.96 54.675 ;
     RECT  2.16 54.945 66.96 55.215 ;
     RECT  2.16 55.485 66.96 55.755 ;
     RECT  2.16 56.025 66.96 56.295 ;
     RECT  2.16 56.565 66.96 56.835 ;
     RECT  2.16 57.105 66.96 57.375 ;
     RECT  2.16 57.645 66.96 57.915 ;
     RECT  2.16 58.185 66.96 58.455 ;
     RECT  2.16 58.725 66.96 58.995 ;
     RECT  2.16 59.265 66.96 59.535 ;
     RECT  2.16 59.805 66.96 60.075 ;
     RECT  2.16 60.345 66.96 60.615 ;
     RECT  2.16 60.885 66.96 61.155 ;
     RECT  2.16 61.425 66.96 61.695 ;
     RECT  2.16 61.965 66.96 62.235 ;
     RECT  2.16 62.505 66.96 62.775 ;
     RECT  2.16 63.045 66.96 63.315 ;
     RECT  2.16 63.585 66.96 63.855 ;
     RECT  2.16 64.125 66.96 64.395 ;
     RECT  2.16 64.665 66.96 64.935 ;
     RECT  2.16 65.205 66.96 65.475 ;
     RECT  2.16 65.745 66.96 66.015 ;
     RECT  2.16 66.285 66.96 66.555 ;
     RECT  2.16 66.825 66.96 66.96 ;
    LAYER RVTP ;
     RECT  2.16 2.295 66.96 2.565 ;
     RECT  2.16 2.835 66.96 3.105 ;
     RECT  2.16 3.375 66.96 3.645 ;
     RECT  2.16 3.915 66.96 4.185 ;
     RECT  2.16 4.455 66.96 4.725 ;
     RECT  2.16 4.995 66.96 5.265 ;
     RECT  2.16 5.535 66.96 5.805 ;
     RECT  2.16 6.075 66.96 6.345 ;
     RECT  2.16 6.615 66.96 6.885 ;
     RECT  2.16 7.155 66.96 7.425 ;
     RECT  2.16 7.695 66.96 7.965 ;
     RECT  2.16 8.235 66.96 8.505 ;
     RECT  2.16 8.775 66.96 9.045 ;
     RECT  2.16 9.315 66.96 9.585 ;
     RECT  2.16 9.855 66.96 10.125 ;
     RECT  2.16 10.395 66.96 10.665 ;
     RECT  2.16 10.935 66.96 11.205 ;
     RECT  2.16 11.475 66.96 11.745 ;
     RECT  2.16 12.015 66.96 12.285 ;
     RECT  2.16 12.555 66.96 12.825 ;
     RECT  2.16 13.095 66.96 13.365 ;
     RECT  2.16 13.635 66.96 13.905 ;
     RECT  2.16 14.175 66.96 14.445 ;
     RECT  2.16 14.715 66.96 14.985 ;
     RECT  2.16 15.255 66.96 15.525 ;
     RECT  2.16 15.795 66.96 16.065 ;
     RECT  2.16 16.335 66.96 16.605 ;
     RECT  2.16 16.875 66.96 17.145 ;
     RECT  2.16 17.415 66.96 17.685 ;
     RECT  2.16 17.955 66.96 18.225 ;
     RECT  2.16 18.495 66.96 18.765 ;
     RECT  2.16 19.035 66.96 19.305 ;
     RECT  2.16 19.575 66.96 19.845 ;
     RECT  2.16 20.115 66.96 20.385 ;
     RECT  2.16 20.655 66.96 20.925 ;
     RECT  2.16 21.195 66.96 21.465 ;
     RECT  2.16 21.735 66.96 22.005 ;
     RECT  2.16 22.275 66.96 22.545 ;
     RECT  2.16 22.815 66.96 23.085 ;
     RECT  2.16 23.355 66.96 23.625 ;
     RECT  2.16 23.895 66.96 24.165 ;
     RECT  2.16 24.435 66.96 24.705 ;
     RECT  2.16 24.975 66.96 25.245 ;
     RECT  2.16 25.515 66.96 25.785 ;
     RECT  2.16 26.055 66.96 26.325 ;
     RECT  2.16 26.595 66.96 26.865 ;
     RECT  2.16 27.135 66.96 27.405 ;
     RECT  2.16 27.675 66.96 27.945 ;
     RECT  2.16 28.215 66.96 28.485 ;
     RECT  2.16 28.755 66.96 29.025 ;
     RECT  2.16 29.295 66.96 29.565 ;
     RECT  2.16 29.835 66.96 30.105 ;
     RECT  2.16 30.375 66.96 30.645 ;
     RECT  2.16 30.915 66.96 31.185 ;
     RECT  2.16 31.455 66.96 31.725 ;
     RECT  2.16 31.995 66.96 32.265 ;
     RECT  2.16 32.535 66.96 32.805 ;
     RECT  2.16 33.075 66.96 33.345 ;
     RECT  2.16 33.615 66.96 33.885 ;
     RECT  2.16 34.155 66.96 34.425 ;
     RECT  2.16 34.695 66.96 34.965 ;
     RECT  2.16 35.235 66.96 35.505 ;
     RECT  2.16 35.775 66.96 36.045 ;
     RECT  2.16 36.315 66.96 36.585 ;
     RECT  2.16 36.855 66.96 37.125 ;
     RECT  2.16 37.395 66.96 37.665 ;
     RECT  2.16 37.935 66.96 38.205 ;
     RECT  2.16 38.475 66.96 38.745 ;
     RECT  2.16 39.015 66.96 39.285 ;
     RECT  2.16 39.555 66.96 39.825 ;
     RECT  2.16 40.095 66.96 40.365 ;
     RECT  2.16 40.635 66.96 40.905 ;
     RECT  2.16 41.175 66.96 41.445 ;
     RECT  2.16 41.715 66.96 41.985 ;
     RECT  2.16 42.255 66.96 42.525 ;
     RECT  2.16 42.795 66.96 43.065 ;
     RECT  2.16 43.335 66.96 43.605 ;
     RECT  2.16 43.875 66.96 44.145 ;
     RECT  2.16 44.415 66.96 44.685 ;
     RECT  2.16 44.955 66.96 45.225 ;
     RECT  2.16 45.495 66.96 45.765 ;
     RECT  2.16 46.035 66.96 46.305 ;
     RECT  2.16 46.575 66.96 46.845 ;
     RECT  2.16 47.115 66.96 47.385 ;
     RECT  2.16 47.655 66.96 47.925 ;
     RECT  2.16 48.195 66.96 48.465 ;
     RECT  2.16 48.735 66.96 49.005 ;
     RECT  2.16 49.275 66.96 49.545 ;
     RECT  2.16 49.815 66.96 50.085 ;
     RECT  2.16 50.355 66.96 50.625 ;
     RECT  2.16 50.895 66.96 51.165 ;
     RECT  2.16 51.435 66.96 51.705 ;
     RECT  2.16 51.975 66.96 52.245 ;
     RECT  2.16 52.515 66.96 52.785 ;
     RECT  2.16 53.055 66.96 53.325 ;
     RECT  2.16 53.595 66.96 53.865 ;
     RECT  2.16 54.135 66.96 54.405 ;
     RECT  2.16 54.675 66.96 54.945 ;
     RECT  2.16 55.215 66.96 55.485 ;
     RECT  2.16 55.755 66.96 56.025 ;
     RECT  2.16 56.295 66.96 56.565 ;
     RECT  2.16 56.835 66.96 57.105 ;
     RECT  2.16 57.375 66.96 57.645 ;
     RECT  2.16 57.915 66.96 58.185 ;
     RECT  2.16 58.455 66.96 58.725 ;
     RECT  2.16 58.995 66.96 59.265 ;
     RECT  2.16 59.535 66.96 59.805 ;
     RECT  2.16 60.075 66.96 60.345 ;
     RECT  2.16 60.615 66.96 60.885 ;
     RECT  2.16 61.155 66.96 61.425 ;
     RECT  2.16 61.695 66.96 61.965 ;
     RECT  2.16 62.235 66.96 62.505 ;
     RECT  2.16 62.775 66.96 63.045 ;
     RECT  2.16 63.315 66.96 63.585 ;
     RECT  2.16 63.855 66.96 64.125 ;
     RECT  2.16 64.395 66.96 64.665 ;
     RECT  2.16 64.935 66.96 65.205 ;
     RECT  2.16 65.475 66.96 65.745 ;
     RECT  2.16 66.015 66.96 66.285 ;
     RECT  2.16 66.555 66.96 66.825 ;
    LAYER M1 ;
     RECT  2.16 2.151 66.96 66.969 ;
    LAYER M2 ;
     RECT  0.103 20.241 0.139 20.259 ;
     RECT  0.103 41.418 0.139 41.436 ;
     RECT  0.103 35.712 0.175 35.73 ;
     RECT  0.103 18.432 0.203 18.45 ;
     RECT  0.139 20.196 0.203 20.259 ;
     RECT  0.103 21.132 0.203 21.15 ;
     RECT  0.103 21.942 0.203 21.96 ;
     RECT  0.103 22.788 0.203 23.814 ;
     RECT  0.103 25.641 0.203 26.01 ;
     RECT  0.103 26.766 0.203 27.126 ;
     RECT  0.103 33.696 0.203 34.416 ;
     RECT  0.175 35.28 0.203 35.73 ;
     RECT  0.103 37.566 0.203 38.196 ;
     RECT  0.139 41.346 0.203 41.436 ;
     RECT  0.103 44.118 0.203 44.712 ;
     RECT  0.103 47.286 0.203 47.529 ;
     RECT  0.203 20.196 0.239 20.214 ;
     RECT  0.203 41.346 0.239 41.364 ;
     RECT  0.103 42.57 0.239 43.056 ;
     RECT  0.175 49.086 0.311 49.104 ;
     RECT  0.203 35.28 0.347 35.298 ;
     RECT  0.103 31.23 0.499 31.248 ;
     RECT  0.499 31.23 0.535 31.482 ;
     RECT  0.103 39.834 0.535 39.852 ;
     RECT  0.535 32.976 0.635 33.066 ;
     RECT  0.535 18.504 2.16 18.522 ;
     RECT  0.535 21.474 2.16 21.492 ;
     RECT  0.203 22.788 2.16 22.806 ;
     RECT  0.203 26.766 2.16 26.784 ;
     RECT  0.103 29.736 2.16 29.754 ;
     RECT  0.535 30.726 2.16 31.914 ;
     RECT  0.635 33.048 2.16 33.066 ;
     RECT  0.203 37.566 2.16 37.584 ;
     RECT  0.535 39.834 2.16 40.284 ;
     RECT  2.155 41.922 2.16 41.94 ;
     RECT  0.535 43.236 2.16 43.254 ;
     RECT  2.16 2.151 31.783 66.969 ;
     RECT  31.783 2.106 32.143 66.969 ;
     RECT  32.143 1.881 32.899 66.969 ;
     RECT  32.899 1.836 33.863 66.969 ;
     RECT  33.863 1.881 33.971 66.969 ;
     RECT  33.971 1.962 34.699 66.969 ;
     RECT  34.699 1.881 35.059 66.969 ;
     RECT  35.059 1.836 37.643 66.969 ;
     RECT  37.643 2.106 39.343 66.969 ;
     RECT  39.343 2.034 40.163 66.969 ;
     RECT  40.163 2.106 41.567 66.969 ;
     RECT  41.567 2.151 44.887 66.969 ;
     RECT  44.887 1.998 46.219 66.969 ;
     RECT  46.939 1.152 47.075 1.17 ;
     RECT  46.219 1.926 48.299 66.969 ;
     RECT  48.299 2.151 66.96 66.969 ;
     RECT  66.96 19.818 67.307 51.768 ;
     RECT  67.307 20.052 67.811 38.304 ;
     RECT  67.811 20.052 67.847 24.804 ;
     RECT  67.811 25.758 67.847 37.422 ;
     RECT  67.307 39.096 67.847 51.768 ;
     RECT  67.847 20.052 67.883 21.762 ;
     RECT  67.847 50.166 68.351 51.768 ;
     RECT  67.847 22.59 68.387 24.804 ;
     RECT  67.847 25.794 68.387 37.422 ;
     RECT  67.811 38.286 68.387 38.304 ;
     RECT  67.847 43.542 68.387 49.374 ;
     RECT  68.351 50.166 68.387 51.732 ;
     RECT  67.883 20.052 68.423 21.492 ;
     RECT  68.387 22.59 68.423 23.346 ;
     RECT  68.387 24.174 68.423 24.804 ;
     RECT  68.387 26.064 68.423 37.422 ;
     RECT  67.847 39.096 68.423 42.75 ;
     RECT  68.387 43.542 68.423 48.024 ;
     RECT  68.387 48.816 68.423 49.374 ;
     RECT  68.387 50.868 68.423 51.192 ;
     RECT  68.423 39.366 68.459 42.714 ;
     RECT  68.423 45.81 68.459 48.024 ;
     RECT  68.423 28.53 68.963 37.35 ;
     RECT  68.423 20.052 68.999 21.294 ;
     RECT  68.963 28.53 68.999 32.634 ;
     RECT  68.459 39.834 68.999 42.714 ;
     RECT  68.423 43.542 68.999 44.208 ;
     RECT  68.459 45.81 68.999 47.214 ;
     RECT  68.423 49.284 68.999 49.374 ;
     RECT  68.999 20.052 69.035 21.114 ;
     RECT  68.423 22.626 69.035 23.346 ;
     RECT  68.423 24.174 69.035 24.534 ;
     RECT  68.423 26.064 69.035 27.63 ;
     RECT  68.999 28.53 69.035 30.33 ;
     RECT  68.999 31.194 69.035 31.752 ;
     RECT  68.999 32.616 69.035 32.634 ;
     RECT  68.963 33.588 69.035 37.35 ;
     RECT  68.999 39.87 69.035 40.932 ;
     RECT  68.999 41.76 69.035 42.714 ;
     RECT  68.999 43.614 69.035 44.208 ;
     RECT  68.999 45.972 69.035 47.214 ;
     RECT  68.459 48.006 69.035 48.024 ;
     RECT  68.999 49.284 69.035 49.302 ;
     RECT  68.423 51.174 69.035 51.192 ;
    LAYER M3 ;
     RECT  32.364 0.091 32.382 0.571 ;
     RECT  40.068 0.427 40.086 0.571 ;
     RECT  39.564 0.571 40.086 0.605 ;
     RECT  32.364 0.571 32.562 0.619 ;
     RECT  33.336 0.571 33.606 0.619 ;
     RECT  32.364 0.619 33.606 0.667 ;
     RECT  46.836 0.811 46.854 0.907 ;
     RECT  46.836 0.907 46.962 0.955 ;
     RECT  47.808 0.859 47.826 0.955 ;
     RECT  32.364 0.667 33.858 1.003 ;
     RECT  39.564 0.605 39.582 1.675 ;
     RECT  35.748 0.571 35.766 1.723 ;
     RECT  36.504 1.147 36.522 1.723 ;
     RECT  40.86 0.091 41.49 1.723 ;
     RECT  46.836 0.955 47.826 1.723 ;
     RECT  46.188 1.723 47.826 1.819 ;
     RECT  35.244 1.723 35.766 1.831 ;
     RECT  37.656 1.675 37.674 1.831 ;
     RECT  40.86 1.723 42.714 1.867 ;
     RECT  45 1.771 45.126 1.867 ;
     RECT  46.008 1.819 47.826 1.867 ;
     RECT  31.824 1.003 33.858 1.876 ;
     RECT  35.064 1.831 35.766 1.876 ;
     RECT  45 1.867 47.826 1.921 ;
     RECT  45 1.921 48.294 1.993 ;
     RECT  36.504 1.723 36.594 2.029 ;
     RECT  39.492 1.675 39.582 2.029 ;
     RECT  40.356 1.867 42.714 2.029 ;
     RECT  31.824 1.876 33.966 2.101 ;
     RECT  34.704 1.876 35.766 2.101 ;
     RECT  36.504 2.029 36.774 2.101 ;
     RECT  37.62 1.831 37.674 2.101 ;
     RECT  34.704 2.101 37.674 2.191 ;
     RECT  39.348 2.029 42.714 2.191 ;
     RECT  31.788 2.101 33.966 2.227 ;
     RECT  34.704 2.191 38.25 2.227 ;
     RECT  39.348 2.191 42.93 2.227 ;
     RECT  44.064 2.191 44.082 2.227 ;
     RECT  39.348 2.227 44.082 2.299 ;
     RECT  44.892 1.993 48.294 2.299 ;
     RECT  39.132 2.299 48.294 2.335 ;
     RECT  31.788 2.227 38.25 2.371 ;
     RECT  39.132 2.335 48.402 2.371 ;
     RECT  2.415 2.143 2.505 2.413 ;
     RECT  7.815 2.143 7.905 2.413 ;
     RECT  13.215 2.143 13.305 2.413 ;
     RECT  18.615 2.143 18.705 2.413 ;
     RECT  24.015 2.143 24.105 2.413 ;
     RECT  29.415 2.143 29.505 2.413 ;
     RECT  51.015 2.143 51.105 2.413 ;
     RECT  56.415 2.143 56.505 2.413 ;
     RECT  61.815 2.143 61.905 2.413 ;
     RECT  31.788 2.371 48.402 2.489 ;
     RECT  31.788 2.489 48.222 2.911 ;
     RECT  31.752 2.911 48.222 3.029 ;
     RECT  31.752 3.029 48.114 3.839 ;
     RECT  31.752 3.839 47.826 3.847 ;
     RECT  31.644 3.847 47.826 3.979 ;
     RECT  31.572 3.979 47.826 4.145 ;
     RECT  31.716 4.145 47.826 4.379 ;
     RECT  31.716 4.379 47.502 4.415 ;
     RECT  31.716 4.415 47.322 4.559 ;
     RECT  32.004 4.559 47.142 4.919 ;
     RECT  32.004 4.919 32.022 5.069 ;
     RECT  32.796 4.919 47.142 5.099 ;
     RECT  32.796 5.099 46.746 5.189 ;
     RECT  32.832 5.189 46.746 5.881 ;
     RECT  32.832 5.881 46.782 5.999 ;
     RECT  32.832 5.999 46.746 6.235 ;
     RECT  32.184 6.235 46.746 6.275 ;
     RECT  32.328 6.275 46.746 6.305 ;
     RECT  46.728 6.305 46.746 6.539 ;
     RECT  32.328 6.305 45.99 6.683 ;
     RECT  32.328 6.683 45.897 7.469 ;
     RECT  34.092 7.469 45.897 7.619 ;
     RECT  34.272 7.619 45.897 7.799 ;
     RECT  34.815 7.799 45.897 7.889 ;
     RECT  34.815 7.889 35.226 7.961 ;
     RECT  36.18 7.889 44.802 8.195 ;
     RECT  36.36 8.195 44.802 8.267 ;
     RECT  36.684 8.267 44.802 8.303 ;
     RECT  36.684 8.303 43.902 8.339 ;
     RECT  36.684 8.339 38.106 8.429 ;
     RECT  38.988 8.339 43.902 8.429 ;
     RECT  44.784 8.303 44.802 8.429 ;
     RECT  36.684 8.429 37.134 8.465 ;
     RECT  38.088 8.429 38.106 8.465 ;
     RECT  39.096 8.429 43.902 8.537 ;
     RECT  39.348 8.537 43.902 8.699 ;
     RECT  36.684 8.465 36.702 8.735 ;
     RECT  39.348 8.699 39.366 8.735 ;
     RECT  40.215 8.699 41.274 8.807 ;
     RECT  42.48 8.699 43.326 8.807 ;
     RECT  41.256 8.807 41.274 8.843 ;
     RECT  42.48 8.807 42.498 8.843 ;
     RECT  43.308 8.807 43.326 8.843 ;
     RECT  32.328 7.469 33.066 12.991 ;
     RECT  31.68 12.991 33.066 13.051 ;
     RECT  29.415 2.413 29.697 13.711 ;
     RECT  31.392 13.051 33.066 13.711 ;
     RECT  29.415 13.711 30.294 13.853 ;
     RECT  31.068 13.711 33.066 14.099 ;
     RECT  31.392 14.099 32.13 14.135 ;
     RECT  30.636 14.203 30.654 14.243 ;
     RECT  32.112 14.135 32.13 14.243 ;
     RECT  32.94 14.099 33.066 14.251 ;
     RECT  32.94 14.251 33.426 14.369 ;
     RECT  33.408 14.369 33.426 14.639 ;
     RECT  33.552 14.791 33.57 14.945 ;
     RECT  7.815 2.413 8.097 17.383 ;
     RECT  4.608 17.383 4.626 17.419 ;
     RECT  6.552 17.383 6.57 17.419 ;
     RECT  7.596 17.383 8.097 17.419 ;
     RECT  5.94 17.419 6.57 17.455 ;
     RECT  7.596 17.419 8.37 17.455 ;
     RECT  18.615 2.413 18.897 17.455 ;
     RECT  19.656 17.419 19.674 17.455 ;
     RECT  5.94 17.455 8.37 17.491 ;
     RECT  5.436 17.491 8.37 17.609 ;
     RECT  2.415 2.413 2.697 17.707 ;
     RECT  3.636 17.689 3.654 17.752 ;
     RECT  4.536 17.419 4.626 17.752 ;
     RECT  2.34 17.707 2.697 17.761 ;
     RECT  3.636 17.752 4.626 17.761 ;
     RECT  5.436 17.609 8.097 17.761 ;
     RECT  9.144 17.761 9.234 17.851 ;
     RECT  9.144 17.851 9.306 17.887 ;
     RECT  10.908 17.851 10.926 17.923 ;
     RECT  8.928 17.887 9.306 17.987 ;
     RECT  8.928 17.987 9.162 18.023 ;
     RECT  10.836 17.923 10.926 18.031 ;
     RECT  10.8 18.031 10.926 18.059 ;
     RECT  2.304 17.761 2.697 18.121 ;
     RECT  9.144 18.023 9.162 18.221 ;
     RECT  2.304 18.121 2.826 18.265 ;
     RECT  18.615 17.455 19.674 18.391 ;
     RECT  0.144 18.235 0.162 18.412 ;
     RECT  18.615 18.391 19.746 18.427 ;
     RECT  0.108 18.412 0.198 18.499 ;
     RECT  2.304 18.265 2.862 18.571 ;
     RECT  3.636 17.761 8.097 18.571 ;
     RECT  18.615 18.427 20.214 18.571 ;
     RECT  0.108 18.499 0.558 18.605 ;
     RECT  2.304 18.571 8.097 18.761 ;
     RECT  0.54 18.605 0.558 18.989 ;
     RECT  10.8 18.059 10.818 18.995 ;
     RECT  9.432 18.841 9.45 19.039 ;
     RECT  18.615 18.571 20.322 19.075 ;
     RECT  9.36 19.039 9.45 19.103 ;
     RECT  9.36 19.103 9.378 19.111 ;
     RECT  9.288 19.111 9.378 19.139 ;
     RECT  9.288 19.139 9.306 19.201 ;
     RECT  18.615 19.075 20.358 19.201 ;
     RECT  9.216 19.201 9.306 19.229 ;
     RECT  18.615 19.201 20.502 19.309 ;
     RECT  9.216 19.229 9.234 19.337 ;
     RECT  4.284 18.761 8.097 19.345 ;
     RECT  10.836 19.201 10.926 19.373 ;
     RECT  18.615 19.309 20.79 19.381 ;
     RECT  4.284 19.345 8.19 19.543 ;
     RECT  9.072 19.471 9.198 19.543 ;
     RECT  4.284 19.543 9.198 19.651 ;
     RECT  18.615 19.381 20.826 19.651 ;
     RECT  48.888 19.531 48.906 19.651 ;
     RECT  4.068 19.651 9.198 19.679 ;
     RECT  4.068 19.679 8.37 19.769 ;
     RECT  48.888 19.651 49.266 19.769 ;
     RECT  22.212 19.471 22.23 19.777 ;
     RECT  24.015 2.413 24.297 19.777 ;
     RECT  21.96 19.777 22.23 19.805 ;
     RECT  48.888 19.769 48.906 19.805 ;
     RECT  21.96 19.805 22.194 19.867 ;
     RECT  61.815 2.413 62.097 19.885 ;
     RECT  2.304 18.761 3.294 19.921 ;
     RECT  4.068 19.769 8.226 19.921 ;
     RECT  24.015 19.777 24.822 20.047 ;
     RECT  61.815 19.885 62.73 20.047 ;
     RECT  66.672 19.813 67.302 20.047 ;
     RECT  64.404 19.885 64.422 20.075 ;
     RECT  18.615 19.651 21.15 20.083 ;
     RECT  21.888 19.867 22.194 20.083 ;
     RECT  0.216 20.155 0.234 20.191 ;
     RECT  61.815 20.047 62.982 20.191 ;
     RECT  66.096 20.047 67.302 20.191 ;
     RECT  66.096 20.191 67.842 20.219 ;
     RECT  0.144 20.191 0.234 20.236 ;
     RECT  0.108 20.236 0.234 20.237 ;
     RECT  24.015 20.047 25.254 20.281 ;
     RECT  0.108 20.237 0.198 20.333 ;
     RECT  66.6 20.219 67.842 20.333 ;
     RECT  0.144 20.333 0.198 20.381 ;
     RECT  64.728 20.281 64.818 20.417 ;
     RECT  9.18 19.679 9.198 20.461 ;
     RECT  2.304 19.921 8.226 20.488 ;
     RECT  10.836 19.373 10.854 20.489 ;
     RECT  2.268 20.488 8.226 20.551 ;
     RECT  9.144 20.461 9.198 20.551 ;
     RECT  2.268 20.551 9.198 20.579 ;
     RECT  58.716 19.777 58.734 20.587 ;
     RECT  64.764 20.417 64.818 20.587 ;
     RECT  65.556 20.551 65.574 20.587 ;
     RECT  69.012 19.915 69.03 20.587 ;
     RECT  24.015 20.281 25.29 20.623 ;
     RECT  26.136 20.587 26.154 20.623 ;
     RECT  60.3 20.587 60.318 20.623 ;
     RECT  61.236 20.191 62.982 20.659 ;
     RECT  63.828 20.083 63.846 20.659 ;
     RECT  67.824 20.333 67.842 20.659 ;
     RECT  68.976 20.587 69.03 20.659 ;
     RECT  60.192 20.623 60.318 20.695 ;
     RECT  58.716 20.587 58.806 20.723 ;
     RECT  2.304 20.579 9.198 20.731 ;
     RECT  2.304 20.731 9.414 20.821 ;
     RECT  60.048 20.695 60.318 20.849 ;
     RECT  2.304 20.821 9.522 20.923 ;
     RECT  24.015 20.623 26.154 20.929 ;
     RECT  61.236 20.659 63.846 20.965 ;
     RECT  18.615 20.083 22.194 21.001 ;
     RECT  60.048 20.849 60.138 21.001 ;
     RECT  2.304 20.923 9.63 21.029 ;
     RECT  66.6 20.333 66.69 21.029 ;
     RECT  59.76 21.001 60.138 21.053 ;
     RECT  61.236 20.965 63.918 21.091 ;
     RECT  67.824 20.659 69.03 21.119 ;
     RECT  0.144 20.381 0.162 21.127 ;
     RECT  60.912 21.091 63.918 21.163 ;
     RECT  64.764 20.587 65.574 21.163 ;
     RECT  66.528 21.091 66.546 21.191 ;
     RECT  60.912 21.163 65.574 21.227 ;
     RECT  67.824 21.119 68.994 21.259 ;
     RECT  60.912 21.227 64.998 21.299 ;
     RECT  67.788 21.259 68.994 21.299 ;
     RECT  10.764 21.199 10.782 21.389 ;
     RECT  10.836 21.397 10.926 21.403 ;
     RECT  10.836 21.403 10.998 21.437 ;
     RECT  0.108 21.127 0.198 21.469 ;
     RECT  58.716 20.723 58.734 21.505 ;
     RECT  67.788 21.299 68.418 21.547 ;
     RECT  2.304 21.029 9.486 21.581 ;
     RECT  33.696 15.061 33.714 21.631 ;
     RECT  2.304 21.581 9.126 21.659 ;
     RECT  33.696 21.631 33.93 21.659 ;
     RECT  58.716 21.505 58.806 21.659 ;
     RECT  0.108 21.469 0.558 21.677 ;
     RECT  67.752 21.547 68.418 21.677 ;
     RECT  59.868 21.053 60.138 21.703 ;
     RECT  60.912 21.299 64.854 21.703 ;
     RECT  65.772 21.271 66.15 21.931 ;
     RECT  0.108 21.677 0.198 21.98 ;
     RECT  28.26 21.811 28.278 22.009 ;
     RECT  59.868 21.703 64.854 22.037 ;
     RECT  65.772 21.931 66.186 22.045 ;
     RECT  24.015 20.929 26.766 22.081 ;
     RECT  27.612 22.009 28.278 22.081 ;
     RECT  59.868 22.037 63.774 22.109 ;
     RECT  24.015 22.081 28.278 22.207 ;
     RECT  10.908 21.437 10.998 22.234 ;
     RECT  65.772 22.045 66.726 22.315 ;
     RECT  67.752 21.677 67.878 22.315 ;
     RECT  64.512 22.037 64.854 22.351 ;
     RECT  10.908 22.234 11.034 22.379 ;
     RECT  2.304 21.659 2.826 22.441 ;
     RECT  3.564 21.659 9.126 22.441 ;
     RECT  65.772 22.315 67.878 22.585 ;
     RECT  69.012 22.411 69.03 22.585 ;
     RECT  10.764 22.441 10.854 22.613 ;
     RECT  10.836 22.613 10.854 22.739 ;
     RECT  0.144 21.98 0.162 22.783 ;
     RECT  58.788 21.659 58.806 22.811 ;
     RECT  0.108 22.783 0.162 22.843 ;
     RECT  51.015 2.413 51.297 22.843 ;
     RECT  64.512 22.351 64.998 22.855 ;
     RECT  2.304 22.441 9.126 22.891 ;
     RECT  64.512 22.855 65.034 22.891 ;
     RECT  65.772 22.585 69.03 22.891 ;
     RECT  59.94 22.109 63.774 22.981 ;
     RECT  64.512 22.891 69.03 22.981 ;
     RECT  51.015 22.843 51.39 23.021 ;
     RECT  59.94 22.981 69.03 23.021 ;
     RECT  18.615 21.001 22.518 23.053 ;
     RECT  2.304 22.891 9.378 23.081 ;
     RECT  18.615 23.053 22.842 23.089 ;
     RECT  24.015 22.207 28.494 23.125 ;
     RECT  2.304 23.081 9.306 23.153 ;
     RECT  2.304 23.153 9.27 23.189 ;
     RECT  18.615 23.089 22.914 23.279 ;
     RECT  31.932 23.287 31.95 23.323 ;
     RECT  18.615 23.279 22.878 23.351 ;
     RECT  59.94 23.021 66.762 23.371 ;
     RECT  24.015 23.125 28.566 23.395 ;
     RECT  31.932 23.323 32.202 23.431 ;
     RECT  59.724 23.371 66.762 23.521 ;
     RECT  2.415 23.189 9.234 23.549 ;
     RECT  59.652 23.521 66.762 23.549 ;
     RECT  10.908 23.395 10.926 23.593 ;
     RECT  58.716 22.891 58.77 23.629 ;
     RECT  59.652 23.549 65.934 23.657 ;
     RECT  10.908 23.593 10.998 23.693 ;
     RECT  18.615 23.351 22.842 23.693 ;
     RECT  60.192 23.657 65.934 23.693 ;
     RECT  66.744 23.549 66.762 23.693 ;
     RECT  31.932 23.431 32.274 23.701 ;
     RECT  33.048 23.611 33.066 23.701 ;
     RECT  58.716 23.629 58.806 23.701 ;
     RECT  60.264 23.693 65.934 23.819 ;
     RECT  58.716 23.701 58.842 23.851 ;
     RECT  58.716 23.851 58.914 23.885 ;
     RECT  67.788 23.021 69.03 23.885 ;
     RECT  24.015 23.395 28.674 23.899 ;
     RECT  29.415 13.853 29.697 23.899 ;
     RECT  58.824 23.885 58.914 23.927 ;
     RECT  2.415 23.549 8.406 23.947 ;
     RECT  31.932 23.701 33.066 23.971 ;
     RECT  33.912 21.659 33.93 23.971 ;
     RECT  67.788 23.885 67.806 23.971 ;
     RECT  0.108 22.843 0.198 24.077 ;
     RECT  0.18 24.077 0.198 24.125 ;
     RECT  31.932 23.971 33.93 24.205 ;
     RECT  2.304 23.947 8.406 24.331 ;
     RECT  9.144 23.549 9.234 24.331 ;
     RECT  2.304 24.331 9.234 24.413 ;
     RECT  2.304 24.413 9.09 24.431 ;
     RECT  2.304 24.431 8.442 24.461 ;
     RECT  2.304 24.461 4.626 24.467 ;
     RECT  60.264 23.819 65.646 24.469 ;
     RECT  18.615 23.693 22.518 24.511 ;
     RECT  2.304 24.467 3.474 24.539 ;
     RECT  69.012 23.885 69.03 24.539 ;
     RECT  60.012 24.469 65.646 24.601 ;
     RECT  4.212 24.467 4.626 24.629 ;
     RECT  67.284 23.971 67.806 24.673 ;
     RECT  67.284 24.673 67.842 24.715 ;
     RECT  34.815 7.961 35.097 24.745 ;
     RECT  4.392 24.629 4.554 24.749 ;
     RECT  67.284 24.715 68.418 24.845 ;
     RECT  5.4 24.461 8.442 24.899 ;
     RECT  18.615 24.511 22.77 24.943 ;
     RECT  60.012 24.601 66.33 24.944 ;
     RECT  0.216 24.523 0.234 24.989 ;
     RECT  10.836 24.871 10.854 25.079 ;
     RECT  34.704 24.745 35.097 25.177 ;
     RECT  60.012 24.944 61.074 25.177 ;
     RECT  59.904 25.177 61.074 25.229 ;
     RECT  5.616 24.899 8.442 25.243 ;
     RECT  18.615 24.943 22.914 25.285 ;
     RECT  31.608 24.205 33.93 25.285 ;
     RECT  61.815 24.944 66.33 25.285 ;
     RECT  67.284 24.845 68.382 25.285 ;
     RECT  18.615 25.285 23.13 25.321 ;
     RECT  4.392 24.749 4.518 25.411 ;
     RECT  5.616 25.243 9.018 25.411 ;
     RECT  18.615 25.321 23.202 25.411 ;
     RECT  31.608 25.285 33.966 25.411 ;
     RECT  34.704 25.177 35.658 25.411 ;
     RECT  61.815 25.285 68.382 25.439 ;
     RECT  10.8 25.249 10.818 25.483 ;
     RECT  18.615 25.411 23.274 25.483 ;
     RECT  24.015 23.899 29.697 25.483 ;
     RECT  2.304 24.539 3.294 25.555 ;
     RECT  4.104 25.411 4.518 25.555 ;
     RECT  2.304 25.555 4.518 25.579 ;
     RECT  10.728 25.483 10.818 25.619 ;
     RECT  2.304 25.579 4.554 25.789 ;
     RECT  31.608 25.411 35.658 25.789 ;
     RECT  61.815 25.439 66.438 25.805 ;
     RECT  61.815 25.805 66.294 25.817 ;
     RECT  64.62 25.817 66.294 25.853 ;
     RECT  67.248 25.439 68.382 25.853 ;
     RECT  67.284 25.853 68.382 25.867 ;
     RECT  2.304 25.789 4.626 25.951 ;
     RECT  5.616 25.411 9.234 25.951 ;
     RECT  0.108 25.387 0.198 26.015 ;
     RECT  61.815 25.817 63.81 26.015 ;
     RECT  40.215 8.807 40.497 26.023 ;
     RECT  60.408 25.229 61.074 26.023 ;
     RECT  61.815 26.015 62.694 26.023 ;
     RECT  58.716 26.131 58.878 26.248 ;
     RECT  40.215 26.023 40.806 26.257 ;
     RECT  18.615 25.483 29.697 26.329 ;
     RECT  40.215 26.257 41.058 26.329 ;
     RECT  10.764 25.619 10.818 26.365 ;
     RECT  58.716 26.248 58.914 26.381 ;
     RECT  64.62 25.853 66.222 26.393 ;
     RECT  2.304 25.951 9.234 26.401 ;
     RECT  2.304 26.401 9.378 26.477 ;
     RECT  40.215 26.329 41.13 26.491 ;
     RECT  41.976 26.365 41.994 26.491 ;
     RECT  10.764 26.365 10.926 26.519 ;
     RECT  64.62 26.393 66.042 26.519 ;
     RECT  60.408 26.023 62.694 26.527 ;
     RECT  40.215 26.491 41.994 26.563 ;
     RECT  64.62 26.519 65.79 26.627 ;
     RECT  60.372 26.527 62.694 26.635 ;
     RECT  2.415 26.477 9.378 26.671 ;
     RECT  10.764 26.519 10.854 26.699 ;
     RECT  58.716 26.381 58.842 26.699 ;
     RECT  59.868 26.635 62.694 26.699 ;
     RECT  0.144 26.015 0.198 26.761 ;
     RECT  60.948 26.699 62.694 26.761 ;
     RECT  63.468 26.015 63.81 26.761 ;
     RECT  64.62 26.627 65.574 26.761 ;
     RECT  67.284 25.867 69.03 26.765 ;
     RECT  40.215 26.563 42.498 26.869 ;
     RECT  59.868 26.699 60.21 26.869 ;
     RECT  40.215 26.869 42.57 26.941 ;
     RECT  0.108 26.761 0.558 26.957 ;
     RECT  59.724 26.869 60.21 26.969 ;
     RECT  0.108 26.957 0.234 27.101 ;
     RECT  2.415 26.671 9.738 27.131 ;
     RECT  60.948 26.761 65.574 27.131 ;
     RECT  63.684 27.131 65.574 27.149 ;
     RECT  2.415 27.131 9.45 27.167 ;
     RECT  0.108 27.101 0.198 27.197 ;
     RECT  2.415 27.167 8.37 27.211 ;
     RECT  9.144 27.167 9.45 27.239 ;
     RECT  0.108 27.197 0.126 27.245 ;
     RECT  10.8 26.699 10.854 27.329 ;
     RECT  66.708 27.301 66.726 27.481 ;
     RECT  10.8 27.329 10.818 27.571 ;
     RECT  67.824 26.765 69.03 27.595 ;
     RECT  10.764 27.571 10.818 27.607 ;
     RECT  31.608 25.789 35.802 27.643 ;
     RECT  10.692 27.607 10.818 27.671 ;
     RECT  66.6 27.481 66.726 27.679 ;
     RECT  10.692 27.671 10.782 27.707 ;
     RECT  10.764 27.707 10.782 27.743 ;
     RECT  66.312 27.679 66.726 27.751 ;
     RECT  66.276 27.751 66.726 27.787 ;
     RECT  67.788 27.595 69.03 27.787 ;
     RECT  9.144 27.239 9.234 27.869 ;
     RECT  63.684 27.149 65.25 27.869 ;
     RECT  66.276 27.787 69.03 27.877 ;
     RECT  59.868 26.969 60.21 27.905 ;
     RECT  40.215 26.941 42.642 27.949 ;
     RECT  60.948 27.131 62.874 27.949 ;
     RECT  63.684 27.869 65.106 27.949 ;
     RECT  18.504 26.329 29.697 28.021 ;
     RECT  60.012 27.905 60.21 28.021 ;
     RECT  60.948 27.949 65.106 28.021 ;
     RECT  40.215 27.949 42.858 28.147 ;
     RECT  58.716 26.699 58.734 28.147 ;
     RECT  40.215 28.147 43.434 28.183 ;
     RECT  58.716 28.147 58.806 28.219 ;
     RECT  2.304 27.211 8.37 28.255 ;
     RECT  9.288 28.111 9.378 28.319 ;
     RECT  66.06 27.877 69.03 28.409 ;
     RECT  66.06 28.409 66.294 28.411 ;
     RECT  60.012 28.021 65.106 28.445 ;
     RECT  18.504 28.021 30.222 28.489 ;
     RECT  0.324 28.363 0.342 28.493 ;
     RECT  63.648 28.445 65.106 28.679 ;
     RECT  58.716 28.219 58.842 28.715 ;
     RECT  2.304 28.255 8.514 28.723 ;
     RECT  9.288 28.319 9.342 28.723 ;
     RECT  18.504 28.489 30.258 28.723 ;
     RECT  66.024 28.411 66.294 28.759 ;
     RECT  65.988 28.759 66.294 28.795 ;
     RECT  65.844 28.795 66.294 28.831 ;
     RECT  18.504 28.723 30.294 29.065 ;
     RECT  58.788 28.715 58.842 29.065 ;
     RECT  2.304 28.723 9.342 29.191 ;
     RECT  10.728 29.101 10.818 29.191 ;
     RECT  40.215 28.183 43.65 29.191 ;
     RECT  44.604 29.029 44.622 29.191 ;
     RECT  10.728 29.191 10.89 29.219 ;
     RECT  65.772 28.831 66.294 29.219 ;
     RECT  10.8 29.219 10.89 29.291 ;
     RECT  18.504 29.065 30.474 29.299 ;
     RECT  67.248 28.409 69.03 29.299 ;
     RECT  2.304 29.191 9.486 29.327 ;
     RECT  60.012 28.445 62.802 29.335 ;
     RECT  66.708 29.299 69.03 29.357 ;
     RECT  58.788 29.065 58.878 29.363 ;
     RECT  59.868 29.335 62.91 29.371 ;
     RECT  63.648 28.679 65.034 29.371 ;
     RECT  58.788 29.363 58.806 29.399 ;
     RECT  18.504 29.299 30.51 29.533 ;
     RECT  2.415 29.327 9.486 29.597 ;
     RECT  59.868 29.371 65.034 29.633 ;
     RECT  18.504 29.533 30.618 29.641 ;
     RECT  2.415 29.597 8.097 29.669 ;
     RECT  59.904 29.633 65.034 29.707 ;
     RECT  65.772 29.219 65.97 29.707 ;
     RECT  0.108 29.707 0.126 29.759 ;
     RECT  58.716 29.641 58.734 29.831 ;
     RECT  18.504 29.641 30.69 29.839 ;
     RECT  2.415 29.669 3.762 29.867 ;
     RECT  31.608 27.643 36.27 29.875 ;
     RECT  9.108 29.597 9.45 29.939 ;
     RECT  18.504 29.839 30.726 30.001 ;
     RECT  31.536 29.875 36.27 30.001 ;
     RECT  67.284 29.357 69.03 30.125 ;
     RECT  59.904 29.707 65.97 30.271 ;
     RECT  4.536 29.669 8.097 30.331 ;
     RECT  9.396 29.939 9.45 30.343 ;
     RECT  4.536 30.331 8.406 30.479 ;
     RECT  9.396 30.343 9.486 30.569 ;
     RECT  3.528 29.867 3.762 30.649 ;
     RECT  4.536 30.479 8.37 30.649 ;
     RECT  10.908 30.541 10.926 30.649 ;
     RECT  67.716 30.125 69.03 30.677 ;
     RECT  0.54 30.721 0.558 30.797 ;
     RECT  10.836 30.649 10.926 30.811 ;
     RECT  3.528 30.649 8.37 30.883 ;
     RECT  59.904 30.271 66.726 30.893 ;
     RECT  2.415 29.867 2.697 30.955 ;
     RECT  3.42 30.883 8.37 30.955 ;
     RECT  59.904 30.893 65.754 30.955 ;
     RECT  66.708 30.893 66.726 30.955 ;
     RECT  38.772 30.955 38.79 30.991 ;
     RECT  59.796 30.955 65.754 31.019 ;
     RECT  38.772 30.991 38.862 31.109 ;
     RECT  2.415 30.955 8.37 31.147 ;
     RECT  0.144 31.051 0.522 31.225 ;
     RECT  58.716 30.847 58.806 31.289 ;
     RECT  2.304 31.147 8.37 31.351 ;
     RECT  0.108 31.225 0.522 31.373 ;
     RECT  10.764 30.811 10.926 31.387 ;
     RECT  58.788 31.289 58.806 31.423 ;
     RECT  9.216 31.387 9.234 31.523 ;
     RECT  2.304 31.351 8.406 31.531 ;
     RECT  10.728 31.387 10.926 31.649 ;
     RECT  0.144 31.373 0.522 31.661 ;
     RECT  10.8 31.649 10.926 31.757 ;
     RECT  66.708 30.955 67.302 31.819 ;
     RECT  68.328 30.677 69.03 31.819 ;
     RECT  2.304 31.531 9.162 31.829 ;
     RECT  0.504 31.661 0.522 31.891 ;
     RECT  0.504 31.891 0.558 32.011 ;
     RECT  0.504 32.011 0.63 32.045 ;
     RECT  58.788 31.423 58.842 32.071 ;
     RECT  66.708 31.819 69.03 32.071 ;
     RECT  0.612 32.045 0.63 32.141 ;
     RECT  66.672 32.071 69.03 32.269 ;
     RECT  59.868 31.019 65.754 32.467 ;
     RECT  10.836 31.757 10.926 32.495 ;
     RECT  9.288 32.341 9.306 32.503 ;
     RECT  59.796 32.467 65.754 32.525 ;
     RECT  2.304 31.829 8.478 32.611 ;
     RECT  9.288 32.503 9.378 32.611 ;
     RECT  58.716 32.071 58.842 32.611 ;
     RECT  60.012 32.525 65.754 32.611 ;
     RECT  66.564 32.269 69.03 32.611 ;
     RECT  58.716 32.611 58.878 32.737 ;
     RECT  38.772 31.109 38.79 32.773 ;
     RECT  38.772 32.773 38.898 32.809 ;
     RECT  58.716 32.737 58.986 32.861 ;
     RECT  2.304 32.611 9.378 32.873 ;
     RECT  38.772 32.809 38.97 32.909 ;
     RECT  58.716 32.861 58.914 32.999 ;
     RECT  60.012 32.611 69.03 32.999 ;
     RECT  9.432 32.881 9.45 33.035 ;
     RECT  66.276 32.999 69.03 33.035 ;
     RECT  0.54 32.971 0.63 33.053 ;
     RECT  46.728 32.809 46.746 33.071 ;
     RECT  0.54 33.053 0.558 33.101 ;
     RECT  10.8 32.971 10.818 33.115 ;
     RECT  10.764 33.115 10.818 33.151 ;
     RECT  18.504 30.001 36.27 33.277 ;
     RECT  10.692 33.151 10.818 33.307 ;
     RECT  38.772 32.909 38.934 33.341 ;
     RECT  10.62 33.307 10.818 33.346 ;
     RECT  38.772 33.341 38.862 33.413 ;
     RECT  10.584 33.346 10.818 33.449 ;
     RECT  66.528 33.035 69.03 33.485 ;
     RECT  2.304 32.873 8.694 33.539 ;
     RECT  60.012 32.999 65.466 33.611 ;
     RECT  66.528 33.485 67.806 33.611 ;
     RECT  2.415 33.539 8.694 33.655 ;
     RECT  18.504 33.277 36.702 33.691 ;
     RECT  2.415 33.655 9.234 33.781 ;
     RECT  38.772 33.413 38.79 33.809 ;
     RECT  2.415 33.781 9.306 33.835 ;
     RECT  40.215 29.191 44.622 33.889 ;
     RECT  2.415 33.835 9.522 33.953 ;
     RECT  60.264 33.611 65.466 34.051 ;
     RECT  2.415 33.953 9.162 34.079 ;
     RECT  40.215 33.889 44.694 34.123 ;
     RECT  58.716 32.999 58.842 34.151 ;
     RECT  40.215 34.123 44.766 34.16 ;
     RECT  40.215 34.16 44.694 34.187 ;
     RECT  60.264 34.051 65.898 34.187 ;
     RECT  60.264 34.187 65.394 34.205 ;
     RECT  10.836 33.619 10.854 34.231 ;
     RECT  67.248 33.611 67.806 34.315 ;
     RECT  69.012 33.485 69.03 34.315 ;
     RECT  10.728 34.231 10.926 34.349 ;
     RECT  18.504 33.691 37.422 34.357 ;
     RECT  67.248 34.315 69.03 34.393 ;
     RECT  66.672 34.393 69.03 34.429 ;
     RECT  10.8 34.349 10.854 34.457 ;
     RECT  2.415 34.079 9.018 34.493 ;
     RECT  10.8 34.457 10.818 34.529 ;
     RECT  0.108 33.547 0.198 34.541 ;
     RECT  2.415 34.493 8.766 34.603 ;
     RECT  18.504 34.357 37.494 34.627 ;
     RECT  60.264 34.205 65.322 34.699 ;
     RECT  60.048 34.699 65.322 34.733 ;
     RECT  18.504 34.627 37.926 34.771 ;
     RECT  60.048 34.733 60.21 34.781 ;
     RECT  58.824 34.151 58.842 34.897 ;
     RECT  58.824 34.897 58.914 34.933 ;
     RECT  58.788 34.933 58.914 34.969 ;
     RECT  18.504 34.771 38.466 35.005 ;
     RECT  60.048 34.781 60.138 35.041 ;
     RECT  61.02 34.733 65.322 35.041 ;
     RECT  66.24 34.429 69.03 35.041 ;
     RECT  0.144 34.541 0.198 35.083 ;
     RECT  61.02 35.041 69.03 35.159 ;
     RECT  45.615 7.889 45.897 35.167 ;
     RECT  58.788 34.969 58.986 35.195 ;
     RECT  59.868 35.041 60.138 35.195 ;
     RECT  58.968 35.195 58.986 35.231 ;
     RECT  0.144 35.083 0.342 35.309 ;
     RECT  2.304 34.603 8.766 35.509 ;
     RECT  40.215 34.187 44.514 35.509 ;
     RECT  59.904 35.195 60.138 35.509 ;
     RECT  61.02 35.159 67.806 35.509 ;
     RECT  2.304 35.509 9.234 35.581 ;
     RECT  2.304 35.581 9.27 35.671 ;
     RECT  0.144 35.309 0.198 35.692 ;
     RECT  2.304 35.671 9.414 35.699 ;
     RECT  7.668 35.699 9.414 35.701 ;
     RECT  59.904 35.509 67.806 35.735 ;
     RECT  7.668 35.701 9.486 35.741 ;
     RECT  7.668 35.741 9.414 35.771 ;
     RECT  59.904 35.735 64.026 35.771 ;
     RECT  60.048 35.771 64.026 35.807 ;
     RECT  7.668 35.771 8.694 35.837 ;
     RECT  60.048 35.807 63.99 35.885 ;
     RECT  0.108 35.692 0.198 35.981 ;
     RECT  0.144 35.981 0.198 36.029 ;
     RECT  40.215 35.509 44.802 36.049 ;
     RECT  45.615 35.167 46.098 36.049 ;
     RECT  10.656 36.049 10.674 36.121 ;
     RECT  58.824 36.049 58.842 36.121 ;
     RECT  64.764 35.735 67.806 36.121 ;
     RECT  68.976 35.159 69.03 36.121 ;
     RECT  2.304 35.699 6.894 36.125 ;
     RECT  10.656 36.121 10.746 36.149 ;
     RECT  10.728 36.149 10.746 36.239 ;
     RECT  58.788 36.121 58.842 36.247 ;
     RECT  64.764 36.121 69.03 36.347 ;
     RECT  7.668 35.837 8.37 36.365 ;
     RECT  66.672 36.347 69.03 36.419 ;
     RECT  0.144 36.029 0.162 36.461 ;
     RECT  4.392 36.125 6.894 36.481 ;
     RECT  7.668 36.365 8.298 36.481 ;
     RECT  58.716 36.247 58.842 36.589 ;
     RECT  18.504 35.005 38.754 36.605 ;
     RECT  64.764 36.347 65.934 36.625 ;
     RECT  60.192 35.885 63.99 36.653 ;
     RECT  67.212 36.419 69.03 36.653 ;
     RECT  10.764 36.481 10.818 36.661 ;
     RECT  64.728 36.625 65.934 36.689 ;
     RECT  2.304 36.125 3.654 36.715 ;
     RECT  2.268 36.715 3.654 36.779 ;
     RECT  10.764 36.661 10.926 36.779 ;
     RECT  40.215 36.049 46.098 36.787 ;
     RECT  58.716 36.589 58.878 36.851 ;
     RECT  2.304 36.779 3.654 36.859 ;
     RECT  4.392 36.481 8.298 36.859 ;
     RECT  40.215 36.787 46.458 36.859 ;
     RECT  60.336 36.653 63.99 36.859 ;
     RECT  64.728 36.689 65.826 36.859 ;
     RECT  10.764 36.779 10.854 37.049 ;
     RECT  60.336 36.859 65.826 37.049 ;
     RECT  40.215 36.859 46.602 37.129 ;
     RECT  2.304 36.859 8.298 37.165 ;
     RECT  9.18 36.589 9.198 37.165 ;
     RECT  10.764 37.049 10.818 37.165 ;
     RECT  2.304 37.165 9.198 37.201 ;
     RECT  63.288 37.049 65.826 37.229 ;
     RECT  10.728 37.165 10.818 37.319 ;
     RECT  10.728 37.319 10.746 37.355 ;
     RECT  67.284 36.653 69.03 37.355 ;
     RECT  2.304 37.201 9.234 37.363 ;
     RECT  67.284 37.355 68.418 37.387 ;
     RECT  63.288 37.229 65.682 37.427 ;
     RECT  2.304 37.363 9.306 37.435 ;
     RECT  2.304 37.435 9.486 37.499 ;
     RECT  67.248 37.387 68.418 37.517 ;
     RECT  60.336 37.049 62.514 37.561 ;
     RECT  2.304 37.499 9.126 37.589 ;
     RECT  59.796 37.561 62.514 37.733 ;
     RECT  18.504 36.605 38.466 37.741 ;
     RECT  67.248 37.517 67.806 37.859 ;
     RECT  40.215 37.129 46.746 37.867 ;
     RECT  47.592 37.201 47.61 37.867 ;
     RECT  58.716 36.851 58.806 37.867 ;
     RECT  0.108 37.561 0.126 37.915 ;
     RECT  2.304 37.589 8.91 37.931 ;
     RECT  60.336 37.733 62.514 38.011 ;
     RECT  63.288 37.427 65.502 38.011 ;
     RECT  58.716 37.867 58.878 38.039 ;
     RECT  60.336 38.011 65.502 38.129 ;
     RECT  67.284 37.859 67.806 38.129 ;
     RECT  0.108 37.915 0.198 38.204 ;
     RECT  68.364 38.251 68.382 38.309 ;
     RECT  58.716 38.039 58.842 38.435 ;
     RECT  9.36 38.407 9.378 38.437 ;
     RECT  40.215 37.867 47.61 38.443 ;
     RECT  40.215 38.443 47.718 38.515 ;
     RECT  60.336 38.129 65.286 38.515 ;
     RECT  40.215 38.515 47.754 38.551 ;
     RECT  58.716 38.435 58.806 38.579 ;
     RECT  60.192 38.515 65.286 38.635 ;
     RECT  0.144 38.204 0.162 38.669 ;
     RECT  10.836 38.515 10.854 38.669 ;
     RECT  60.048 38.635 65.286 38.675 ;
     RECT  2.304 37.931 8.586 38.731 ;
     RECT  9.36 38.437 9.45 38.731 ;
     RECT  2.304 38.731 9.45 38.821 ;
     RECT  66.384 38.059 66.402 38.821 ;
     RECT  67.284 38.129 67.302 38.821 ;
     RECT  56.415 2.413 56.697 38.911 ;
     RECT  2.304 38.821 9.558 38.923 ;
     RECT  64.8 38.675 65.286 38.947 ;
     RECT  66.384 38.821 67.302 38.947 ;
     RECT  64.8 38.947 67.302 39.115 ;
     RECT  68.4 39.091 68.418 39.115 ;
     RECT  10.764 38.947 10.818 39.119 ;
     RECT  2.268 38.923 9.558 39.149 ;
     RECT  2.268 39.149 5.418 39.209 ;
     RECT  10.8 39.119 10.818 39.245 ;
     RECT  64.8 39.115 68.418 39.245 ;
     RECT  6.192 39.149 9.558 39.259 ;
     RECT  58.716 38.579 58.77 39.281 ;
     RECT  6.192 39.259 9.63 39.317 ;
     RECT  60.048 38.675 64.026 39.325 ;
     RECT  67.248 39.245 68.418 39.361 ;
     RECT  56.304 38.911 56.697 39.488 ;
     RECT  14.832 39.091 14.85 39.631 ;
     RECT  59.868 39.325 64.026 39.631 ;
     RECT  64.8 39.245 64.998 39.631 ;
     RECT  67.248 39.361 68.454 39.691 ;
     RECT  65.772 39.245 66.366 39.749 ;
     RECT  59.868 39.631 64.998 39.785 ;
     RECT  0.108 39.829 0.126 39.883 ;
     RECT  0.108 39.883 0.198 40.013 ;
     RECT  6.192 39.317 9.414 40.019 ;
     RECT  14.832 39.631 14.958 40.055 ;
     RECT  65.772 39.749 65.862 40.055 ;
     RECT  0.18 40.013 0.198 40.061 ;
     RECT  58.716 39.281 58.734 40.063 ;
     RECT  58.716 40.063 58.77 40.099 ;
     RECT  64.764 39.785 64.998 40.099 ;
     RECT  2.304 39.209 5.418 40.135 ;
     RECT  6.192 40.019 9.378 40.135 ;
     RECT  58.716 40.099 58.842 40.199 ;
     RECT  60.336 39.785 63.81 40.289 ;
     RECT  60.336 40.289 63.45 40.397 ;
     RECT  60.948 40.397 63.45 40.433 ;
     RECT  2.304 40.135 9.378 40.469 ;
     RECT  14.832 40.055 14.85 40.469 ;
     RECT  0.54 40.261 0.558 40.493 ;
     RECT  67.248 39.691 69.03 40.567 ;
     RECT  64.764 40.099 65.286 40.711 ;
     RECT  58.716 40.199 58.806 40.937 ;
     RECT  58.788 40.937 58.806 41.009 ;
     RECT  66.6 40.567 69.03 41.009 ;
     RECT  2.304 40.469 8.73 41.035 ;
     RECT  60.984 40.433 63.45 41.071 ;
     RECT  64.584 40.711 65.286 41.071 ;
     RECT  2.268 41.035 8.73 41.099 ;
     RECT  60.984 41.071 63.522 41.099 ;
     RECT  67.284 41.009 69.03 41.099 ;
     RECT  10.8 40.873 10.818 41.107 ;
     RECT  10.8 41.107 10.854 41.215 ;
     RECT  2.304 41.099 8.73 41.251 ;
     RECT  0.144 41.323 0.162 41.341 ;
     RECT  61.815 41.099 63.522 41.341 ;
     RECT  64.584 41.071 65.358 41.341 ;
     RECT  2.304 41.251 9.162 41.369 ;
     RECT  0.144 41.341 0.234 41.404 ;
     RECT  0.108 41.404 0.234 41.419 ;
     RECT  10.764 41.215 10.854 41.441 ;
     RECT  61.815 41.341 65.358 41.449 ;
     RECT  0.108 41.419 0.342 41.453 ;
     RECT  59.868 40.675 59.886 41.485 ;
     RECT  59.832 41.485 59.886 41.513 ;
     RECT  0.144 41.453 0.342 41.549 ;
     RECT  10.8 41.441 10.854 41.611 ;
     RECT  9 41.369 9.162 41.707 ;
     RECT  10.8 41.611 10.926 41.711 ;
     RECT  9 41.707 9.378 41.756 ;
     RECT  67.284 41.099 67.806 41.837 ;
     RECT  61.815 41.449 66.222 41.881 ;
     RECT  2.304 41.369 8.262 41.899 ;
     RECT  58.716 41.881 58.734 41.899 ;
     RECT  67.752 41.837 67.806 41.917 ;
     RECT  68.904 41.099 69.03 41.917 ;
     RECT  61.815 41.881 66.762 41.933 ;
     RECT  2.16 41.899 8.262 41.945 ;
     RECT  58.716 41.899 58.77 41.981 ;
     RECT  56.415 39.488 56.697 42.025 ;
     RECT  10.8 41.711 10.89 42.053 ;
     RECT  56.304 42.025 56.697 42.077 ;
     RECT  58.752 41.981 58.77 42.077 ;
     RECT  9 41.756 9.342 42.089 ;
     RECT  54.72 41.989 54.738 42.179 ;
     RECT  2.415 41.945 8.262 42.187 ;
     RECT  9 42.089 9.234 42.187 ;
     RECT  60.984 41.099 61.002 42.187 ;
     RECT  61.815 41.933 66.69 42.187 ;
     RECT  59.832 41.513 59.85 42.259 ;
     RECT  59.832 42.259 60.21 42.295 ;
     RECT  60.984 42.187 66.69 42.295 ;
     RECT  0.144 41.549 0.162 42.556 ;
     RECT  0.108 42.556 0.162 42.565 ;
     RECT  67.752 41.917 69.03 42.605 ;
     RECT  59.832 42.295 66.69 42.629 ;
     RECT  2.415 42.187 9.234 42.667 ;
     RECT  59.832 42.629 65.826 42.691 ;
     RECT  2.304 42.667 9.234 42.719 ;
     RECT  59.724 42.691 65.826 42.749 ;
     RECT  58.788 42.493 58.842 42.755 ;
     RECT  67.788 42.605 69.03 42.797 ;
     RECT  10.692 42.763 10.71 42.799 ;
     RECT  10.692 42.799 10.782 42.835 ;
     RECT  10.692 42.835 10.818 42.863 ;
     RECT  2.415 42.719 9.234 42.871 ;
     RECT  40.215 38.551 48.15 42.871 ;
     RECT  2.415 42.871 9.27 43.025 ;
     RECT  40.215 42.871 48.294 43.105 ;
     RECT  2.415 43.025 9.234 43.133 ;
     RECT  0.108 42.565 0.234 43.181 ;
     RECT  66.708 43.069 66.726 43.181 ;
     RECT  0.18 43.181 0.234 43.231 ;
     RECT  59.904 42.749 65.826 43.259 ;
     RECT  58.788 42.755 58.806 43.295 ;
     RECT  59.904 43.259 65.466 43.331 ;
     RECT  0.18 43.231 0.558 43.469 ;
     RECT  69.012 42.797 69.03 43.528 ;
     RECT  2.415 43.133 9.09 43.531 ;
     RECT  67.788 42.797 67.842 43.627 ;
     RECT  68.976 43.528 69.03 43.627 ;
     RECT  67.788 43.627 69.03 43.681 ;
     RECT  10.728 42.863 10.818 43.709 ;
     RECT  66.384 43.537 66.546 43.709 ;
     RECT  10.764 43.709 10.818 43.835 ;
     RECT  40.215 43.105 48.942 43.843 ;
     RECT  50.184 43.537 50.202 43.843 ;
     RECT  2.304 43.531 9.09 43.871 ;
     RECT  66.528 43.709 66.546 43.915 ;
     RECT  67.284 43.681 69.03 43.915 ;
     RECT  60.012 43.331 64.206 44.069 ;
     RECT  0.18 43.469 0.198 44.113 ;
     RECT  64.98 43.331 65.466 44.149 ;
     RECT  66.528 43.915 69.03 44.213 ;
     RECT  64.98 44.149 65.538 44.221 ;
     RECT  10.8 43.835 10.818 44.339 ;
     RECT  58.716 43.951 58.734 44.339 ;
     RECT  63.144 44.069 64.206 44.491 ;
     RECT  64.98 44.221 65.754 44.491 ;
     RECT  66.528 44.213 68.418 44.491 ;
     RECT  63.144 44.491 68.418 44.519 ;
     RECT  40.215 43.843 50.202 44.689 ;
     RECT  51.015 23.021 51.297 44.689 ;
     RECT  60.012 44.069 62.19 44.689 ;
     RECT  10.836 44.581 10.854 44.717 ;
     RECT  67.248 44.519 68.418 44.717 ;
     RECT  0.108 44.113 0.198 44.732 ;
     RECT  9.432 44.455 9.522 44.753 ;
     RECT  59.904 44.689 62.19 44.765 ;
     RECT  9.504 44.753 9.522 44.879 ;
     RECT  59.976 44.765 62.19 44.915 ;
     RECT  63.144 44.519 66.438 44.951 ;
     RECT  2.304 43.871 8.298 45.031 ;
     RECT  60.336 44.915 62.19 45.031 ;
     RECT  63.144 44.951 66.258 45.031 ;
     RECT  67.284 44.717 68.418 45.101 ;
     RECT  67.752 45.101 68.418 45.163 ;
     RECT  2.304 45.031 8.55 45.355 ;
     RECT  39.42 45.229 39.438 45.463 ;
     RECT  60.336 45.031 66.258 45.533 ;
     RECT  39.312 45.463 39.438 45.571 ;
     RECT  40.215 44.689 51.297 45.571 ;
     RECT  2.268 45.355 8.55 45.599 ;
     RECT  60.336 45.533 60.642 45.691 ;
     RECT  39.312 45.571 51.297 45.697 ;
     RECT  58.716 45.661 58.734 45.697 ;
     RECT  61.524 45.533 66.258 45.697 ;
     RECT  2.304 45.599 8.55 45.733 ;
     RECT  10.8 45.661 10.818 45.733 ;
     RECT  2.304 45.733 9.09 45.769 ;
     RECT  58.716 45.697 58.77 45.769 ;
     RECT  61.524 45.697 66.402 45.769 ;
     RECT  67.752 45.163 69.03 45.773 ;
     RECT  39.312 45.697 51.318 45.797 ;
     RECT  0.144 45.643 0.162 45.821 ;
     RECT  10.8 45.733 10.998 45.869 ;
     RECT  68.94 45.773 69.03 45.869 ;
     RECT  10.8 45.869 10.926 45.959 ;
     RECT  58.716 45.769 58.842 45.967 ;
     RECT  2.304 45.769 9.126 45.995 ;
     RECT  9.072 45.995 9.126 46.031 ;
     RECT  68.976 45.869 69.03 46.031 ;
     RECT  58.716 45.967 58.878 46.061 ;
     RECT  61.524 45.769 66.762 46.103 ;
     RECT  9.18 46.069 9.342 46.109 ;
     RECT  60.228 45.691 60.642 46.171 ;
     RECT  18.504 37.741 38.502 46.237 ;
     RECT  39.312 45.797 51.297 46.237 ;
     RECT  59.76 46.171 60.642 46.273 ;
     RECT  59.76 46.273 60.75 46.309 ;
     RECT  63.216 46.103 66.762 46.309 ;
     RECT  67.752 45.773 67.806 46.309 ;
     RECT  58.716 46.061 58.842 46.337 ;
     RECT  10.8 45.959 10.89 46.571 ;
     RECT  59.76 46.309 60.786 46.615 ;
     RECT  61.524 46.103 62.442 46.615 ;
     RECT  63.216 46.309 67.806 46.679 ;
     RECT  66.6 46.679 67.806 46.841 ;
     RECT  58.716 46.337 58.806 46.877 ;
     RECT  59.76 46.615 62.442 46.885 ;
     RECT  63.216 46.679 65.646 46.885 ;
     RECT  2.304 45.995 8.226 46.921 ;
     RECT  59.76 46.885 65.646 46.921 ;
     RECT  2.268 46.921 8.226 47.011 ;
     RECT  9.18 46.109 9.306 47.011 ;
     RECT  2.268 47.011 9.306 47.021 ;
     RECT  10.836 46.571 10.854 47.039 ;
     RECT  59.724 46.921 65.646 47.077 ;
     RECT  2.304 47.021 9.306 47.083 ;
     RECT  59.616 47.077 65.646 47.117 ;
     RECT  69.012 46.031 69.03 47.119 ;
     RECT  0.144 46.555 0.162 47.131 ;
     RECT  2.304 47.083 9.342 47.165 ;
     RECT  0.144 47.131 0.198 47.179 ;
     RECT  2.304 47.165 9.234 47.219 ;
     RECT  2.415 47.219 9.234 47.309 ;
     RECT  59.688 47.117 65.646 47.405 ;
     RECT  59.832 47.405 65.646 47.417 ;
     RECT  0.108 47.179 0.198 47.419 ;
     RECT  59.868 47.417 65.646 47.453 ;
     RECT  0.108 47.419 0.234 47.597 ;
     RECT  59.94 47.453 65.646 47.659 ;
     RECT  66.6 46.841 67.338 47.659 ;
     RECT  2.415 47.309 8.442 47.693 ;
     RECT  59.94 47.659 67.338 47.695 ;
     RECT  68.364 47.119 69.03 47.695 ;
     RECT  58.716 46.877 58.734 47.731 ;
     RECT  0.144 47.597 0.234 47.789 ;
     RECT  58.716 47.731 58.806 47.929 ;
     RECT  59.94 47.695 69.03 47.957 ;
     RECT  58.716 47.929 58.842 47.965 ;
     RECT  10.8 47.551 10.818 48.001 ;
     RECT  58.716 47.965 58.914 48.001 ;
     RECT  61.815 47.957 69.03 48.029 ;
     RECT  2.415 47.693 8.37 48.043 ;
     RECT  10.764 48.001 10.818 48.119 ;
     RECT  61.815 48.029 68.454 48.173 ;
     RECT  58.716 48.001 58.95 48.263 ;
     RECT  59.94 47.957 60.966 48.271 ;
     RECT  61.815 48.173 68.418 48.389 ;
     RECT  10.8 48.119 10.818 48.461 ;
     RECT  64.476 48.389 68.418 48.461 ;
     RECT  2.304 48.043 8.37 48.505 ;
     RECT  9.18 47.309 9.234 48.505 ;
     RECT  59.796 48.271 60.966 48.533 ;
     RECT  2.304 48.505 9.234 48.541 ;
     RECT  64.476 48.461 67.338 48.557 ;
     RECT  0.144 47.789 0.162 48.653 ;
     RECT  60.3 48.533 60.966 48.703 ;
     RECT  61.815 48.389 63.738 48.703 ;
     RECT  68.364 48.461 68.418 48.749 ;
     RECT  58.716 48.263 58.806 48.803 ;
     RECT  2.304 48.541 9.342 48.839 ;
     RECT  64.476 48.557 67.266 48.839 ;
     RECT  2.34 48.839 9.306 48.929 ;
     RECT  68.4 48.749 68.418 48.941 ;
     RECT  64.476 48.839 66.15 49.037 ;
     RECT  0.18 49.051 0.306 49.109 ;
     RECT  0.18 49.109 0.198 49.133 ;
     RECT  1.116 49.003 1.134 49.181 ;
     RECT  2.415 48.929 9.306 49.199 ;
     RECT  58.716 48.803 58.77 49.199 ;
     RECT  67.248 48.839 67.266 49.199 ;
     RECT  60.3 48.703 63.738 49.243 ;
     RECT  64.476 49.037 66.042 49.243 ;
     RECT  60.3 49.243 66.042 49.279 ;
     RECT  68.976 49.195 69.03 49.307 ;
     RECT  68.976 49.307 68.994 49.379 ;
     RECT  67.284 49.315 67.302 49.441 ;
     RECT  2.415 49.199 3.546 49.469 ;
     RECT  4.536 49.199 6.93 49.469 ;
     RECT  4.536 49.469 5.022 49.475 ;
     RECT  5.796 49.469 6.822 49.505 ;
     RECT  7.704 49.199 9.306 49.541 ;
     RECT  67.284 49.441 67.338 49.549 ;
     RECT  9.216 49.541 9.234 49.577 ;
     RECT  58.752 49.199 58.77 49.577 ;
     RECT  60.012 49.279 66.042 49.585 ;
     RECT  6.336 49.505 6.822 49.649 ;
     RECT  56.415 42.077 56.697 49.711 ;
     RECT  18.504 46.237 51.297 49.723 ;
     RECT  56.304 49.711 56.697 49.757 ;
     RECT  13.215 2.413 13.497 49.855 ;
     RECT  6.336 49.649 6.354 49.883 ;
     RECT  5.004 49.475 5.022 49.919 ;
     RECT  67.284 49.549 67.842 49.963 ;
     RECT  59.868 49.585 66.042 50.009 ;
     RECT  18.504 49.723 51.354 50.141 ;
     RECT  67.248 49.963 67.842 50.152 ;
     RECT  67.248 50.152 68.382 50.153 ;
     RECT  61.164 50.009 66.042 50.359 ;
     RECT  3.456 49.469 3.546 50.459 ;
     RECT  3.456 50.459 3.474 50.549 ;
     RECT  59.868 50.009 60.03 50.549 ;
     RECT  61.164 50.359 66.186 50.557 ;
     RECT  61.164 50.557 66.402 50.621 ;
     RECT  61.164 50.621 64.638 50.821 ;
     RECT  65.376 50.621 66.402 50.863 ;
     RECT  67.752 50.153 68.382 50.863 ;
     RECT  58.716 50.629 58.734 50.891 ;
     RECT  61.092 50.821 64.638 50.935 ;
     RECT  65.376 50.863 66.618 50.935 ;
     RECT  13.215 49.855 13.698 50.999 ;
     RECT  67.752 50.863 68.418 50.999 ;
     RECT  68.328 50.999 68.418 51.115 ;
     RECT  59.868 50.549 59.994 51.149 ;
     RECT  60.84 50.935 64.638 51.197 ;
     RECT  65.376 50.935 66.69 51.197 ;
     RECT  68.328 51.115 69.03 51.197 ;
     RECT  59.976 51.149 59.994 51.269 ;
     RECT  61.092 51.197 64.638 51.439 ;
     RECT  65.376 51.197 66.114 51.439 ;
     RECT  58.788 50.935 58.806 51.511 ;
     RECT  61.092 51.439 66.114 51.539 ;
     RECT  61.092 51.539 64.566 51.629 ;
     RECT  65.448 51.539 66.114 51.629 ;
     RECT  61.092 51.629 63.918 51.665 ;
     RECT  61.815 51.665 63.918 51.737 ;
     RECT  68.328 51.197 68.382 51.737 ;
     RECT  58.788 51.511 58.842 51.773 ;
     RECT  61.815 51.737 62.874 51.773 ;
     RECT  63.9 51.737 63.918 51.773 ;
     RECT  68.328 51.737 68.346 51.773 ;
     RECT  58.788 51.773 58.806 51.809 ;
     RECT  61.815 51.773 62.802 51.809 ;
     RECT  65.448 51.629 65.466 51.809 ;
     RECT  18.504 50.141 51.297 52.051 ;
     RECT  18.396 52.051 51.297 64.327 ;
     RECT  18.216 64.327 51.297 64.705 ;
     RECT  17.928 64.705 51.297 64.939 ;
     RECT  17.712 64.939 51.297 65.245 ;
     RECT  17.676 65.245 51.297 66.479 ;
     RECT  17.676 66.479 50.058 66.557 ;
     RECT  2.415 49.469 2.697 66.707 ;
     RECT  7.815 49.541 8.097 66.707 ;
     RECT  13.215 50.999 13.497 66.707 ;
     RECT  51.015 66.479 51.297 66.707 ;
     RECT  56.415 49.757 56.697 66.707 ;
     RECT  61.815 51.809 62.097 66.707 ;
     RECT  28.08 66.557 50.058 66.749 ;
     RECT  17.676 66.557 27.306 66.785 ;
     RECT  28.116 66.749 41.094 66.785 ;
     RECT  41.832 66.749 49.662 66.785 ;
     RECT  29.196 66.785 41.094 66.893 ;
     RECT  42.12 66.785 49.662 66.893 ;
     RECT  17.676 66.785 27.27 66.941 ;
     RECT  2.415 66.707 2.505 66.977 ;
     RECT  7.815 66.707 7.905 66.977 ;
     RECT  13.215 66.707 13.305 66.977 ;
     RECT  38.844 66.893 41.094 66.977 ;
     RECT  45 66.893 49.662 66.977 ;
     RECT  51.015 66.707 51.105 66.977 ;
     RECT  56.415 66.707 56.505 66.977 ;
     RECT  61.815 66.707 61.905 66.977 ;
     RECT  38.844 66.977 40.158 67.085 ;
     RECT  29.196 66.893 37.998 67.229 ;
     RECT  38.844 67.085 40.122 67.229 ;
     RECT  42.12 66.893 44.118 67.229 ;
     RECT  45.756 66.977 49.662 67.229 ;
     RECT  17.748 66.941 27.27 67.277 ;
     RECT  28.116 66.785 28.134 67.277 ;
     RECT  29.196 67.229 32.634 67.277 ;
     RECT  33.588 67.229 37.998 67.277 ;
     RECT  38.844 67.229 38.862 67.277 ;
     RECT  39.78 67.229 39.798 67.277 ;
     RECT  40.896 66.977 41.094 67.277 ;
     RECT  42.48 67.229 44.118 67.277 ;
     RECT  45 66.977 45.018 67.277 ;
     RECT  45.756 67.229 47.286 67.277 ;
     RECT  49.032 67.229 49.194 67.277 ;
     RECT  17.748 67.277 20.646 67.325 ;
     RECT  33.804 67.277 34.758 67.325 ;
     RECT  36.864 67.277 37.458 67.325 ;
     RECT  41.076 67.277 41.094 67.325 ;
     RECT  33.804 67.325 34.434 67.373 ;
     RECT  20.592 67.325 20.646 67.853 ;
     RECT  21.456 67.277 21.654 67.853 ;
     RECT  23.832 67.277 24.57 67.853 ;
     RECT  30.636 67.277 30.654 67.853 ;
     RECT  31.572 67.277 31.842 67.853 ;
     RECT  33.804 67.373 33.822 67.853 ;
     RECT  36.864 67.325 36.882 67.853 ;
     RECT  45.756 67.277 45.774 67.853 ;
     RECT  46.764 67.277 46.782 67.853 ;
     RECT  17.856 67.325 18.81 67.901 ;
     RECT  21.636 67.853 21.654 67.901 ;
     RECT  31.572 67.853 31.59 68.381 ;
     RECT  49.032 67.277 49.05 68.381 ;
     RECT  18.432 67.901 18.81 68.429 ;
     RECT  20.628 67.853 20.646 68.429 ;
     RECT  22.752 67.277 22.77 68.429 ;
     RECT  18.792 68.429 18.81 68.477 ;
     RECT  24.552 67.853 24.57 68.861 ;
     RECT  25.38 68.731 25.398 68.861 ;
     RECT  43.344 68.731 43.758 68.861 ;
     RECT  43.74 68.861 43.758 68.875 ;
     RECT  26.928 67.277 26.946 68.909 ;
     RECT  19.548 67.325 19.674 68.957 ;
     RECT  19.656 68.957 19.674 69.005 ;
     RECT  28.296 68.779 28.314 69.005 ;
     RECT  35.316 68.875 36.234 69.005 ;
     RECT  38.34 68.827 38.358 69.005 ;
     RECT  39.492 68.827 39.51 69.005 ;
     RECT  43.74 68.875 44.442 69.005 ;
     RECT  45.396 68.875 45.414 69.005 ;
    LAYER M4 ;
     RECT  0.084 17.712 0.133 17.736 ;
     RECT  0.06 17.736 0.133 17.808 ;
     RECT  0.084 17.808 0.133 17.832 ;
     RECT  0.06 17.832 0.133 17.904 ;
     RECT  0.084 17.904 0.133 17.928 ;
     RECT  0.06 17.928 0.133 18 ;
     RECT  0.084 18 0.133 18.024 ;
     RECT  0.06 18.024 0.133 18.096 ;
     RECT  0.084 18.096 0.133 18.12 ;
     RECT  0.06 18.12 0.133 18.192 ;
     RECT  0.084 18.192 0.133 18.216 ;
     RECT  0.06 18.216 0.133 18.288 ;
     RECT  0.084 18.288 0.133 18.312 ;
     RECT  0.06 18.312 0.133 18.384 ;
     RECT  0.084 18.384 0.133 18.408 ;
     RECT  0.06 18.408 0.133 18.48 ;
     RECT  0.084 18.48 0.133 18.504 ;
     RECT  0.06 18.504 0.133 18.576 ;
     RECT  0.084 18.576 0.133 18.6 ;
     RECT  0.06 18.6 0.133 18.672 ;
     RECT  0.084 18.672 0.133 18.696 ;
     RECT  0.06 18.696 0.133 18.768 ;
     RECT  0.084 18.768 0.133 18.792 ;
     RECT  0.06 18.792 0.133 18.864 ;
     RECT  0.084 18.864 0.133 18.888 ;
     RECT  0.06 18.888 0.133 18.96 ;
     RECT  0.084 18.96 0.133 18.984 ;
     RECT  0.06 18.984 0.133 19.056 ;
     RECT  0.084 19.056 0.133 19.08 ;
     RECT  0.06 19.08 0.133 19.152 ;
     RECT  0.084 19.152 0.133 19.176 ;
     RECT  0.06 19.176 0.133 19.248 ;
     RECT  0.084 19.248 0.133 19.272 ;
     RECT  0.06 19.272 0.133 19.344 ;
     RECT  0.084 19.344 0.133 19.368 ;
     RECT  0.06 19.368 0.133 19.44 ;
     RECT  0.084 19.44 0.133 19.464 ;
     RECT  0.06 19.464 0.133 19.536 ;
     RECT  0.084 19.536 0.133 19.56 ;
     RECT  0.06 19.56 0.133 19.632 ;
     RECT  0.084 19.632 0.133 19.656 ;
     RECT  0.06 19.656 0.133 19.728 ;
     RECT  0.084 19.728 0.133 19.752 ;
     RECT  0.06 19.752 0.133 19.824 ;
     RECT  0.084 19.824 0.133 19.848 ;
     RECT  0.06 19.848 0.133 19.92 ;
     RECT  0.084 19.92 0.133 19.944 ;
     RECT  0.06 19.944 0.133 20.016 ;
     RECT  0.084 20.016 0.133 20.04 ;
     RECT  0.06 20.04 0.133 20.112 ;
     RECT  0.084 20.112 0.133 20.136 ;
     RECT  0.06 20.136 0.133 20.208 ;
     RECT  0.084 20.208 0.133 20.232 ;
     RECT  0.06 20.232 0.133 20.304 ;
     RECT  0.084 20.304 0.133 20.328 ;
     RECT  0.06 20.328 0.133 20.4 ;
     RECT  0.084 20.4 0.133 20.424 ;
     RECT  0.06 20.424 0.133 20.496 ;
     RECT  0.084 20.496 0.133 20.52 ;
     RECT  0.06 20.52 0.133 20.592 ;
     RECT  0.084 20.592 0.133 20.616 ;
     RECT  0.06 20.616 0.133 20.688 ;
     RECT  0.084 20.688 0.133 20.712 ;
     RECT  0.06 20.712 0.133 20.784 ;
     RECT  0.084 20.784 0.133 20.808 ;
     RECT  0.06 20.808 0.133 20.88 ;
     RECT  0.084 20.88 0.133 20.904 ;
     RECT  0.06 20.904 0.133 20.976 ;
     RECT  0.084 20.976 0.133 21 ;
     RECT  0.06 21 0.133 21.072 ;
     RECT  0.084 21.072 0.133 21.096 ;
     RECT  0.06 21.096 0.133 21.168 ;
     RECT  0.084 21.168 0.133 21.192 ;
     RECT  0.06 21.192 0.133 21.264 ;
     RECT  0.084 21.264 0.133 21.288 ;
     RECT  0.06 21.288 0.133 21.36 ;
     RECT  0.084 21.36 0.133 21.384 ;
     RECT  0.06 21.384 0.133 21.456 ;
     RECT  0.084 21.456 0.133 21.48 ;
     RECT  0.06 21.48 0.133 21.552 ;
     RECT  0.084 21.552 0.133 21.576 ;
     RECT  0.06 21.576 0.133 21.648 ;
     RECT  0.084 21.648 0.133 21.672 ;
     RECT  0.06 21.672 0.133 21.744 ;
     RECT  0.084 21.744 0.133 21.768 ;
     RECT  0.06 21.768 0.133 21.84 ;
     RECT  0.084 21.84 0.133 21.864 ;
     RECT  0.06 21.864 0.133 21.936 ;
     RECT  0.084 21.936 0.133 21.96 ;
     RECT  0.06 21.96 0.133 22.032 ;
     RECT  0.084 22.032 0.133 22.056 ;
     RECT  0.06 22.056 0.133 22.128 ;
     RECT  0.084 22.128 0.133 22.152 ;
     RECT  0.06 22.152 0.133 22.224 ;
     RECT  0.084 22.224 0.133 22.248 ;
     RECT  0.06 22.248 0.133 22.32 ;
     RECT  0.084 22.32 0.133 22.344 ;
     RECT  0.06 22.344 0.133 22.416 ;
     RECT  0.084 22.416 0.133 22.44 ;
     RECT  0.06 22.44 0.133 22.512 ;
     RECT  0.084 22.512 0.133 22.536 ;
     RECT  0.06 22.536 0.133 22.608 ;
     RECT  0.084 22.608 0.133 22.632 ;
     RECT  0.06 22.632 0.133 22.704 ;
     RECT  0.084 22.704 0.133 22.728 ;
     RECT  0.06 22.728 0.133 22.8 ;
     RECT  0.084 22.8 0.133 22.824 ;
     RECT  0.06 22.824 0.133 22.896 ;
     RECT  0.084 22.896 0.133 22.92 ;
     RECT  0.06 22.92 0.133 22.992 ;
     RECT  0.084 22.992 0.133 23.016 ;
     RECT  0.06 23.016 0.133 23.088 ;
     RECT  0.084 23.088 0.133 23.112 ;
     RECT  0.06 23.112 0.133 23.184 ;
     RECT  0.084 23.184 0.133 23.208 ;
     RECT  0.06 23.208 0.133 23.28 ;
     RECT  0.084 23.28 0.133 23.304 ;
     RECT  0.06 23.304 0.133 23.376 ;
     RECT  0.084 23.376 0.133 23.4 ;
     RECT  0.06 23.4 0.133 23.472 ;
     RECT  0.084 23.472 0.133 23.496 ;
     RECT  0.06 23.496 0.133 23.568 ;
     RECT  0.084 23.568 0.133 23.592 ;
     RECT  0.06 23.592 0.133 23.664 ;
     RECT  0.084 23.664 0.133 23.688 ;
     RECT  0.06 23.688 0.133 23.76 ;
     RECT  0.084 23.76 0.133 23.784 ;
     RECT  0.06 23.784 0.133 23.856 ;
     RECT  0.084 23.856 0.133 23.88 ;
     RECT  0.06 23.88 0.133 23.952 ;
     RECT  0.084 23.952 0.133 23.976 ;
     RECT  0.06 23.976 0.133 24.048 ;
     RECT  0.084 24.048 0.133 24.072 ;
     RECT  0.06 24.072 0.133 24.144 ;
     RECT  0.084 24.144 0.133 24.168 ;
     RECT  0.06 24.168 0.133 24.24 ;
     RECT  0.084 24.24 0.133 24.264 ;
     RECT  0.06 24.264 0.133 24.336 ;
     RECT  0.084 24.336 0.133 24.36 ;
     RECT  0.06 24.36 0.133 24.432 ;
     RECT  0.084 24.432 0.133 24.456 ;
     RECT  0.06 24.456 0.133 24.528 ;
     RECT  0.084 24.528 0.133 24.552 ;
     RECT  0.06 24.552 0.133 24.624 ;
     RECT  0.084 24.624 0.133 24.648 ;
     RECT  0.06 24.648 0.133 24.72 ;
     RECT  0.084 24.72 0.133 24.744 ;
     RECT  0.06 24.744 0.133 24.816 ;
     RECT  0.084 24.816 0.133 24.84 ;
     RECT  0.06 24.84 0.133 24.912 ;
     RECT  0.084 24.912 0.133 24.936 ;
     RECT  0.06 24.936 0.133 25.008 ;
     RECT  0.084 25.008 0.133 25.032 ;
     RECT  0.06 25.032 0.133 25.104 ;
     RECT  0.084 25.104 0.133 25.128 ;
     RECT  0.06 25.128 0.133 25.2 ;
     RECT  0.084 25.2 0.133 25.224 ;
     RECT  0.06 25.224 0.133 25.296 ;
     RECT  0.084 25.296 0.133 25.32 ;
     RECT  0.06 25.32 0.133 25.392 ;
     RECT  0.084 25.392 0.133 25.416 ;
     RECT  0.06 25.416 0.133 25.488 ;
     RECT  0.084 25.488 0.133 25.512 ;
     RECT  0.06 25.512 0.133 25.584 ;
     RECT  0.084 25.584 0.133 25.608 ;
     RECT  0.06 25.608 0.133 25.68 ;
     RECT  0.084 25.68 0.133 25.704 ;
     RECT  0.06 25.704 0.133 25.776 ;
     RECT  0.084 25.776 0.133 25.8 ;
     RECT  0.06 25.8 0.133 25.872 ;
     RECT  0.084 25.872 0.133 25.896 ;
     RECT  0.06 25.896 0.133 25.968 ;
     RECT  0.084 25.968 0.133 25.992 ;
     RECT  0.06 25.992 0.133 26.064 ;
     RECT  0.084 26.064 0.133 26.088 ;
     RECT  0.06 26.088 0.133 26.16 ;
     RECT  0.084 26.16 0.133 26.184 ;
     RECT  0.06 26.184 0.133 26.256 ;
     RECT  0.084 26.256 0.133 26.28 ;
     RECT  0.06 26.28 0.133 26.352 ;
     RECT  0.084 26.352 0.133 26.376 ;
     RECT  0.06 26.376 0.133 26.448 ;
     RECT  0.084 26.448 0.133 26.472 ;
     RECT  0.06 26.472 0.133 26.544 ;
     RECT  0.084 26.544 0.133 26.568 ;
     RECT  0.06 26.568 0.133 26.64 ;
     RECT  0.084 26.64 0.133 26.664 ;
     RECT  0.06 26.664 0.133 26.736 ;
     RECT  0.084 26.736 0.133 26.76 ;
     RECT  0.06 26.76 0.133 26.832 ;
     RECT  0.084 26.832 0.133 26.856 ;
     RECT  0.06 26.856 0.133 26.928 ;
     RECT  0.084 26.928 0.133 26.952 ;
     RECT  0.06 26.952 0.133 27.024 ;
     RECT  0.084 27.024 0.133 27.048 ;
     RECT  0.06 27.048 0.133 27.12 ;
     RECT  0.084 27.12 0.133 27.144 ;
     RECT  0.06 27.144 0.133 27.216 ;
     RECT  0.084 27.216 0.133 27.24 ;
     RECT  0.06 27.24 0.133 27.312 ;
     RECT  0.084 27.312 0.133 27.336 ;
     RECT  0.06 27.336 0.133 27.408 ;
     RECT  0.084 27.408 0.133 27.432 ;
     RECT  0.06 27.432 0.133 27.504 ;
     RECT  0.084 27.504 0.133 27.528 ;
     RECT  0.06 27.528 0.133 27.6 ;
     RECT  0.084 27.6 0.133 27.624 ;
     RECT  0.06 27.624 0.133 27.696 ;
     RECT  0.084 27.696 0.133 27.72 ;
     RECT  0.06 27.72 0.133 27.792 ;
     RECT  0.084 27.792 0.133 27.816 ;
     RECT  0.06 27.816 0.133 27.888 ;
     RECT  0.084 27.888 0.133 27.912 ;
     RECT  0.06 27.912 0.133 27.984 ;
     RECT  0.084 27.984 0.133 28.008 ;
     RECT  0.06 28.008 0.133 28.08 ;
     RECT  0.084 28.08 0.133 28.104 ;
     RECT  0.06 28.104 0.133 28.176 ;
     RECT  0.084 28.176 0.133 28.2 ;
     RECT  0.06 28.2 0.133 28.272 ;
     RECT  0.084 28.272 0.133 28.296 ;
     RECT  0.06 28.296 0.133 28.368 ;
     RECT  0.084 28.368 0.133 28.392 ;
     RECT  0.06 28.392 0.133 28.464 ;
     RECT  0.084 28.464 0.133 28.488 ;
     RECT  0.06 28.488 0.133 28.56 ;
     RECT  0.084 28.56 0.133 28.584 ;
     RECT  0.06 28.584 0.133 28.656 ;
     RECT  0.084 28.656 0.133 28.68 ;
     RECT  0.06 28.68 0.133 28.752 ;
     RECT  0.084 28.752 0.133 28.776 ;
     RECT  0.06 28.776 0.133 28.848 ;
     RECT  0.084 28.848 0.133 28.872 ;
     RECT  0.06 28.872 0.133 28.944 ;
     RECT  0.084 28.944 0.133 28.968 ;
     RECT  0.06 28.968 0.133 29.04 ;
     RECT  0.084 29.04 0.133 29.064 ;
     RECT  0.06 29.064 0.133 29.136 ;
     RECT  0.084 29.136 0.133 29.16 ;
     RECT  0.06 29.16 0.133 29.232 ;
     RECT  0.084 29.232 0.133 29.256 ;
     RECT  0.06 29.256 0.133 29.328 ;
     RECT  0.084 29.328 0.133 29.352 ;
     RECT  0.06 29.352 0.133 29.424 ;
     RECT  0.084 29.424 0.133 29.448 ;
     RECT  0.06 29.448 0.133 29.52 ;
     RECT  0.084 29.52 0.133 29.544 ;
     RECT  0.06 29.544 0.133 29.616 ;
     RECT  0.084 29.616 0.133 29.64 ;
     RECT  0.06 29.64 0.133 29.712 ;
     RECT  0.084 29.712 0.133 29.736 ;
     RECT  0.06 29.736 0.133 29.808 ;
     RECT  0.084 29.808 0.133 29.832 ;
     RECT  0.06 29.832 0.133 29.904 ;
     RECT  0.084 29.904 0.133 29.928 ;
     RECT  0.06 29.928 0.133 30.768 ;
     RECT  0.084 30.768 0.133 30.792 ;
     RECT  0.06 30.792 0.133 30.864 ;
     RECT  0.084 30.864 0.133 30.888 ;
     RECT  0.06 30.888 0.133 30.96 ;
     RECT  0.084 30.96 0.133 30.984 ;
     RECT  0.06 30.984 0.133 31.056 ;
     RECT  0.084 31.056 0.133 31.08 ;
     RECT  0.06 31.08 0.133 31.152 ;
     RECT  0.084 31.152 0.133 31.176 ;
     RECT  0.06 31.176 0.133 31.248 ;
     RECT  0.084 31.248 0.133 31.272 ;
     RECT  0.06 31.272 0.133 31.344 ;
     RECT  0.084 31.344 0.133 31.368 ;
     RECT  0.06 31.368 0.133 31.44 ;
     RECT  0.084 31.44 0.133 31.464 ;
     RECT  0.06 31.464 0.133 31.536 ;
     RECT  0.084 31.536 0.133 31.56 ;
     RECT  0.06 31.56 0.133 31.632 ;
     RECT  0.084 31.632 0.133 31.656 ;
     RECT  0.06 31.656 0.133 31.728 ;
     RECT  0.084 31.728 0.133 31.752 ;
     RECT  0.06 31.752 0.133 31.824 ;
     RECT  0.084 31.824 0.133 31.848 ;
     RECT  0.06 31.848 0.133 31.92 ;
     RECT  0.084 31.92 0.133 31.944 ;
     RECT  0.06 31.944 0.133 32.016 ;
     RECT  0.084 32.016 0.133 32.04 ;
     RECT  0.06 32.04 0.133 32.112 ;
     RECT  0.084 32.112 0.133 32.136 ;
     RECT  0.06 32.136 0.133 32.208 ;
     RECT  0.084 32.208 0.133 32.232 ;
     RECT  0.06 32.232 0.133 32.304 ;
     RECT  0.084 32.304 0.133 32.328 ;
     RECT  0.06 32.328 0.133 32.4 ;
     RECT  0.084 32.4 0.133 32.424 ;
     RECT  0.06 32.424 0.133 32.496 ;
     RECT  0.084 32.496 0.133 32.52 ;
     RECT  0.06 32.52 0.133 32.592 ;
     RECT  0.084 32.592 0.133 32.616 ;
     RECT  0.06 32.616 0.133 32.688 ;
     RECT  0.084 32.688 0.133 32.712 ;
     RECT  0.06 32.712 0.133 32.784 ;
     RECT  0.084 32.784 0.133 32.808 ;
     RECT  0.06 32.808 0.133 32.88 ;
     RECT  0.084 32.88 0.133 32.904 ;
     RECT  0.06 32.904 0.133 32.976 ;
     RECT  0.084 32.976 0.133 33 ;
     RECT  0.06 33 0.133 33.072 ;
     RECT  0.084 33.072 0.133 33.096 ;
     RECT  0.06 33.096 0.133 33.168 ;
     RECT  0.084 33.168 0.133 33.192 ;
     RECT  0.06 33.192 0.133 33.264 ;
     RECT  0.084 33.264 0.133 33.288 ;
     RECT  0.06 33.288 0.133 33.36 ;
     RECT  0.084 33.36 0.133 33.384 ;
     RECT  0.06 33.384 0.133 33.456 ;
     RECT  0.084 33.456 0.133 33.48 ;
     RECT  0.06 33.48 0.133 33.552 ;
     RECT  0.084 33.552 0.133 33.576 ;
     RECT  0.06 33.576 0.133 33.648 ;
     RECT  0.084 33.648 0.133 33.672 ;
     RECT  0.06 33.672 0.133 33.744 ;
     RECT  0.084 33.744 0.133 33.768 ;
     RECT  0.06 33.768 0.133 33.84 ;
     RECT  0.084 33.84 0.133 33.864 ;
     RECT  0.06 33.864 0.133 33.936 ;
     RECT  0.084 33.936 0.133 33.96 ;
     RECT  0.06 33.96 0.133 34.032 ;
     RECT  0.084 34.032 0.133 34.056 ;
     RECT  0.06 34.056 0.133 34.128 ;
     RECT  0.084 34.128 0.133 34.152 ;
     RECT  0.06 34.152 0.133 34.224 ;
     RECT  0.084 34.224 0.133 34.248 ;
     RECT  0.06 34.248 0.133 34.32 ;
     RECT  0.084 34.32 0.133 34.344 ;
     RECT  0.06 34.344 0.133 34.416 ;
     RECT  0.084 34.416 0.133 34.44 ;
     RECT  0.06 34.44 0.133 34.512 ;
     RECT  0.084 34.512 0.133 34.536 ;
     RECT  0.06 34.536 0.133 34.608 ;
     RECT  0.084 34.608 0.133 34.632 ;
     RECT  0.06 34.632 0.133 34.704 ;
     RECT  0.084 34.704 0.133 34.728 ;
     RECT  0.06 34.728 0.133 34.8 ;
     RECT  0.084 34.8 0.133 34.824 ;
     RECT  0.06 34.824 0.133 34.896 ;
     RECT  0.084 34.896 0.133 34.92 ;
     RECT  0.06 34.92 0.133 34.992 ;
     RECT  0.084 34.992 0.133 35.016 ;
     RECT  0.06 35.016 0.133 35.088 ;
     RECT  0.084 35.088 0.133 35.112 ;
     RECT  0.06 35.112 0.133 35.184 ;
     RECT  0.084 35.184 0.133 35.208 ;
     RECT  0.06 35.208 0.133 35.28 ;
     RECT  0.084 35.28 0.133 35.304 ;
     RECT  0.06 35.304 0.133 35.376 ;
     RECT  0.084 35.376 0.133 35.4 ;
     RECT  0.06 35.4 0.133 35.472 ;
     RECT  0.084 35.472 0.133 35.496 ;
     RECT  0.06 35.496 0.133 35.568 ;
     RECT  0.084 35.568 0.133 35.592 ;
     RECT  0.06 35.592 0.133 35.664 ;
     RECT  0.084 35.664 0.133 35.688 ;
     RECT  0.06 35.688 0.133 35.76 ;
     RECT  0.084 35.76 0.133 35.784 ;
     RECT  0.06 35.784 0.133 35.856 ;
     RECT  0.084 35.856 0.133 35.88 ;
     RECT  0.06 35.88 0.133 35.952 ;
     RECT  0.084 35.952 0.133 35.976 ;
     RECT  0.06 35.976 0.133 36.048 ;
     RECT  0.084 36.048 0.133 36.072 ;
     RECT  0.06 36.072 0.133 36.144 ;
     RECT  0.084 36.144 0.133 36.168 ;
     RECT  0.06 36.168 0.133 36.24 ;
     RECT  0.084 36.24 0.133 36.264 ;
     RECT  0.06 36.264 0.133 36.336 ;
     RECT  0.084 36.336 0.133 36.36 ;
     RECT  0.06 36.36 0.133 36.432 ;
     RECT  0.084 36.432 0.133 36.456 ;
     RECT  0.06 36.456 0.133 36.528 ;
     RECT  0.084 36.528 0.133 36.552 ;
     RECT  0.06 36.552 0.133 36.624 ;
     RECT  0.084 36.624 0.133 36.648 ;
     RECT  0.06 36.648 0.133 36.72 ;
     RECT  0.084 36.72 0.133 36.744 ;
     RECT  0.06 36.744 0.133 36.816 ;
     RECT  0.084 36.816 0.133 36.84 ;
     RECT  0.06 36.84 0.133 36.912 ;
     RECT  0.084 36.912 0.133 36.936 ;
     RECT  0.06 36.936 0.133 37.008 ;
     RECT  0.084 37.008 0.133 37.032 ;
     RECT  0.06 37.032 0.133 37.104 ;
     RECT  0.084 37.104 0.133 37.128 ;
     RECT  0.06 37.128 0.133 37.2 ;
     RECT  0.084 37.2 0.133 37.224 ;
     RECT  0.06 37.224 0.133 37.296 ;
     RECT  0.084 37.296 0.133 37.32 ;
     RECT  0.06 37.32 0.133 37.392 ;
     RECT  0.084 37.392 0.133 37.416 ;
     RECT  0.06 37.416 0.133 37.488 ;
     RECT  0.084 37.488 0.133 37.512 ;
     RECT  0.06 37.512 0.133 37.584 ;
     RECT  0.084 37.584 0.133 37.608 ;
     RECT  0.06 37.608 0.133 37.68 ;
     RECT  0.084 37.68 0.133 37.704 ;
     RECT  0.06 37.704 0.133 37.776 ;
     RECT  0.084 37.776 0.133 37.8 ;
     RECT  0.06 37.8 0.133 37.872 ;
     RECT  0.084 37.872 0.133 37.896 ;
     RECT  0.06 37.896 0.133 37.968 ;
     RECT  0.084 37.968 0.133 37.992 ;
     RECT  0.06 37.992 0.133 38.064 ;
     RECT  0.084 38.064 0.133 38.088 ;
     RECT  0.06 38.088 0.133 38.16 ;
     RECT  0.084 38.16 0.133 38.184 ;
     RECT  0.06 38.184 0.133 38.256 ;
     RECT  0.084 38.256 0.133 38.28 ;
     RECT  0.06 38.28 0.133 38.352 ;
     RECT  0.084 38.352 0.133 38.376 ;
     RECT  0.06 38.376 0.133 38.448 ;
     RECT  0.084 38.448 0.133 38.472 ;
     RECT  0.06 38.472 0.133 38.544 ;
     RECT  0.084 38.544 0.133 38.568 ;
     RECT  0.06 38.568 0.133 38.64 ;
     RECT  0.084 38.64 0.133 38.664 ;
     RECT  0.06 38.664 0.133 38.736 ;
     RECT  0.084 38.736 0.133 38.76 ;
     RECT  0.06 38.76 0.133 38.832 ;
     RECT  0.084 38.832 0.133 38.856 ;
     RECT  0.06 38.856 0.133 38.928 ;
     RECT  0.084 38.928 0.133 38.952 ;
     RECT  0.06 38.952 0.133 39.024 ;
     RECT  0.084 39.024 0.133 39.048 ;
     RECT  0.06 39.048 0.133 39.12 ;
     RECT  0.084 39.12 0.133 39.144 ;
     RECT  0.06 39.144 0.133 39.216 ;
     RECT  0.084 39.216 0.133 39.24 ;
     RECT  0.06 39.24 0.133 39.312 ;
     RECT  0.084 39.312 0.133 39.336 ;
     RECT  0.06 39.336 0.133 39.408 ;
     RECT  0.084 39.408 0.133 39.432 ;
     RECT  0.06 39.432 0.133 39.504 ;
     RECT  0.084 39.504 0.133 39.528 ;
     RECT  0.06 39.528 0.133 39.6 ;
     RECT  0.084 39.6 0.133 39.624 ;
     RECT  0.06 39.624 0.133 39.696 ;
     RECT  0.084 39.696 0.133 39.72 ;
     RECT  0.06 39.72 0.133 39.792 ;
     RECT  0.084 39.792 0.133 39.816 ;
     RECT  0.06 39.816 0.133 39.888 ;
     RECT  0.084 39.888 0.133 39.912 ;
     RECT  0.06 39.912 0.133 39.984 ;
     RECT  0.084 39.984 0.133 40.008 ;
     RECT  0.06 40.008 0.133 40.08 ;
     RECT  0.084 40.08 0.133 40.104 ;
     RECT  0.06 40.104 0.133 40.176 ;
     RECT  0.084 40.176 0.133 40.2 ;
     RECT  0.06 40.2 0.133 40.272 ;
     RECT  0.084 40.272 0.133 40.296 ;
     RECT  0.06 40.296 0.133 40.368 ;
     RECT  0.084 40.368 0.133 40.392 ;
     RECT  0.06 40.392 0.133 40.464 ;
     RECT  0.084 40.464 0.133 40.488 ;
     RECT  0.06 40.488 0.133 40.56 ;
     RECT  0.084 40.56 0.133 40.584 ;
     RECT  0.06 40.584 0.133 40.656 ;
     RECT  0.084 40.656 0.133 40.68 ;
     RECT  0.06 40.68 0.133 40.752 ;
     RECT  0.084 40.752 0.133 40.776 ;
     RECT  0.06 40.776 0.133 40.848 ;
     RECT  0.084 40.848 0.133 40.872 ;
     RECT  0.06 40.872 0.133 40.944 ;
     RECT  0.084 40.944 0.133 40.968 ;
     RECT  0.06 40.968 0.133 41.04 ;
     RECT  0.084 41.04 0.133 41.064 ;
     RECT  0.06 41.064 0.133 41.136 ;
     RECT  0.084 41.136 0.133 41.16 ;
     RECT  0.06 41.16 0.133 41.232 ;
     RECT  0.084 41.232 0.133 41.256 ;
     RECT  0.06 41.256 0.133 41.328 ;
     RECT  0.084 41.328 0.133 41.352 ;
     RECT  0.06 41.352 0.133 41.424 ;
     RECT  0.084 41.424 0.133 41.448 ;
     RECT  0.06 41.448 0.133 41.52 ;
     RECT  0.084 41.52 0.133 41.544 ;
     RECT  0.06 41.544 0.133 41.616 ;
     RECT  0.084 41.616 0.133 41.64 ;
     RECT  0.06 41.64 0.133 41.712 ;
     RECT  0.084 41.712 0.133 41.736 ;
     RECT  0.06 41.736 0.133 41.808 ;
     RECT  0.084 41.808 0.133 41.832 ;
     RECT  0.06 41.832 0.133 41.904 ;
     RECT  0.084 41.904 0.133 41.928 ;
     RECT  0.06 41.928 0.133 42 ;
     RECT  0.084 42 0.133 42.024 ;
     RECT  0.06 42.024 0.133 42.096 ;
     RECT  0.084 42.096 0.133 42.12 ;
     RECT  0.06 42.12 0.133 42.192 ;
     RECT  0.084 42.192 0.133 42.216 ;
     RECT  0.06 42.216 0.133 42.288 ;
     RECT  0.084 42.288 0.133 42.312 ;
     RECT  0.06 42.312 0.133 42.384 ;
     RECT  0.084 42.384 0.133 42.408 ;
     RECT  0.06 42.408 0.133 42.48 ;
     RECT  0.084 42.48 0.133 42.504 ;
     RECT  0.06 42.504 0.133 42.576 ;
     RECT  0.084 42.576 0.133 42.6 ;
     RECT  0.06 42.6 0.133 42.672 ;
     RECT  0.084 42.672 0.133 42.696 ;
     RECT  0.06 42.696 0.133 42.768 ;
     RECT  0.084 42.768 0.133 42.792 ;
     RECT  0.06 42.792 0.133 42.864 ;
     RECT  0.084 42.864 0.133 42.888 ;
     RECT  0.06 42.888 0.133 42.96 ;
     RECT  0.084 42.96 0.133 42.984 ;
     RECT  0.06 42.984 0.133 43.056 ;
     RECT  0.084 43.056 0.133 43.08 ;
     RECT  0.06 43.08 0.133 43.152 ;
     RECT  0.084 43.152 0.133 43.176 ;
     RECT  0.06 43.176 0.133 43.248 ;
     RECT  0.084 43.248 0.133 43.272 ;
     RECT  0.06 43.272 0.133 43.344 ;
     RECT  0.084 43.344 0.133 43.368 ;
     RECT  0.06 43.368 0.133 43.44 ;
     RECT  0.084 43.44 0.133 43.464 ;
     RECT  0.06 43.464 0.133 43.536 ;
     RECT  0.084 43.536 0.133 43.56 ;
     RECT  0.06 43.56 0.133 43.632 ;
     RECT  0.084 43.632 0.133 43.656 ;
     RECT  0.06 43.656 0.133 43.728 ;
     RECT  0.084 43.728 0.133 43.752 ;
     RECT  0.06 43.752 0.133 43.824 ;
     RECT  0.084 43.824 0.133 43.848 ;
     RECT  0.06 43.848 0.133 43.92 ;
     RECT  0.084 43.92 0.133 43.944 ;
     RECT  0.06 43.944 0.133 44.016 ;
     RECT  0.084 44.016 0.133 44.04 ;
     RECT  0.06 44.04 0.133 44.112 ;
     RECT  0.084 44.112 0.133 44.136 ;
     RECT  0.06 44.136 0.133 44.208 ;
     RECT  0.084 44.208 0.133 44.232 ;
     RECT  0.06 44.232 0.133 44.304 ;
     RECT  0.084 44.304 0.133 44.328 ;
     RECT  0.06 44.328 0.133 44.4 ;
     RECT  0.084 44.4 0.133 44.424 ;
     RECT  0.06 44.424 0.133 44.496 ;
     RECT  0.084 44.496 0.133 44.52 ;
     RECT  0.06 44.52 0.133 44.592 ;
     RECT  0.084 44.592 0.133 44.616 ;
     RECT  0.06 44.616 0.133 44.688 ;
     RECT  0.084 44.688 0.133 44.712 ;
     RECT  0.06 44.712 0.133 44.784 ;
     RECT  0.084 44.784 0.133 44.808 ;
     RECT  0.06 44.808 0.133 44.88 ;
     RECT  0.084 44.88 0.133 44.904 ;
     RECT  0.06 44.904 0.133 44.976 ;
     RECT  0.084 44.976 0.133 45 ;
     RECT  0.06 45 0.133 45.072 ;
     RECT  0.084 45.072 0.133 45.096 ;
     RECT  0.06 45.096 0.133 45.168 ;
     RECT  0.084 45.168 0.133 45.192 ;
     RECT  0.06 45.192 0.133 45.264 ;
     RECT  0.084 45.264 0.133 45.288 ;
     RECT  0.06 45.288 0.133 45.36 ;
     RECT  0.084 45.36 0.133 45.384 ;
     RECT  0.06 45.384 0.133 45.456 ;
     RECT  0.084 45.456 0.133 45.48 ;
     RECT  0.06 45.48 0.133 45.552 ;
     RECT  0.084 45.552 0.133 45.576 ;
     RECT  0.06 45.576 0.133 45.648 ;
     RECT  0.084 45.648 0.133 45.672 ;
     RECT  0.06 45.672 0.133 45.744 ;
     RECT  0.084 45.744 0.133 45.768 ;
     RECT  0.06 45.768 0.133 45.84 ;
     RECT  0.084 45.84 0.133 45.864 ;
     RECT  0.06 45.864 0.133 45.936 ;
     RECT  0.084 45.936 0.133 45.96 ;
     RECT  0.06 45.96 0.133 46.032 ;
     RECT  0.084 46.032 0.133 46.056 ;
     RECT  0.06 46.056 0.133 46.128 ;
     RECT  0.084 46.128 0.133 46.152 ;
     RECT  0.06 46.152 0.133 46.224 ;
     RECT  0.084 46.224 0.133 46.248 ;
     RECT  0.06 46.248 0.133 46.32 ;
     RECT  0.084 46.32 0.133 46.344 ;
     RECT  0.06 46.344 0.133 46.416 ;
     RECT  0.084 46.416 0.133 46.44 ;
     RECT  0.06 46.44 0.133 46.512 ;
     RECT  0.084 46.512 0.133 46.536 ;
     RECT  0.06 46.536 0.133 46.608 ;
     RECT  0.084 46.608 0.133 46.632 ;
     RECT  0.06 46.632 0.133 46.704 ;
     RECT  0.084 46.704 0.133 46.728 ;
     RECT  0.06 46.728 0.133 46.8 ;
     RECT  0.084 46.8 0.133 46.824 ;
     RECT  0.06 46.824 0.133 46.896 ;
     RECT  0.084 46.896 0.133 46.92 ;
     RECT  0.06 46.92 0.133 46.992 ;
     RECT  0.084 46.992 0.133 47.016 ;
     RECT  0.06 47.016 0.133 47.088 ;
     RECT  0.084 47.088 0.133 47.112 ;
     RECT  0.06 47.112 0.133 47.184 ;
     RECT  0.084 47.184 0.133 47.208 ;
     RECT  0.06 47.208 0.133 47.28 ;
     RECT  0.084 47.28 0.133 47.304 ;
     RECT  0.06 47.304 0.133 47.376 ;
     RECT  0.084 47.376 0.133 47.4 ;
     RECT  0.06 47.4 0.133 47.472 ;
     RECT  0.084 47.472 0.133 47.496 ;
     RECT  0.06 47.496 0.133 47.568 ;
     RECT  0.084 47.568 0.133 47.592 ;
     RECT  0.06 47.592 0.133 47.664 ;
     RECT  0.084 47.664 0.133 47.688 ;
     RECT  0.06 47.688 0.133 47.76 ;
     RECT  0.084 47.76 0.133 47.784 ;
     RECT  0.06 47.784 0.133 47.856 ;
     RECT  0.084 47.856 0.133 47.88 ;
     RECT  0.06 47.88 0.133 47.952 ;
     RECT  0.084 47.952 0.133 47.976 ;
     RECT  0.06 47.976 0.133 48.048 ;
     RECT  0.084 48.048 0.133 48.072 ;
     RECT  0.06 48.072 0.133 48.144 ;
     RECT  0.084 48.144 0.133 48.168 ;
     RECT  0.06 48.168 0.133 48.24 ;
     RECT  0.084 48.24 0.133 48.264 ;
     RECT  0.06 48.264 0.133 48.336 ;
     RECT  0.084 48.336 0.133 48.36 ;
     RECT  0.06 48.36 0.133 48.432 ;
     RECT  0.084 48.432 0.133 48.456 ;
     RECT  0.06 48.456 0.133 48.528 ;
     RECT  0.084 48.528 0.133 48.552 ;
     RECT  0.06 48.552 0.133 48.624 ;
     RECT  0.084 48.624 0.133 48.648 ;
     RECT  0.06 48.648 0.133 48.72 ;
     RECT  0.084 48.72 0.133 48.744 ;
     RECT  0.06 48.744 0.133 48.816 ;
     RECT  0.084 48.816 0.133 48.84 ;
     RECT  0.06 48.84 0.133 48.912 ;
     RECT  0.084 48.912 0.133 48.936 ;
     RECT  0.06 48.936 0.133 49.008 ;
     RECT  0.084 49.008 0.133 49.032 ;
     RECT  0.06 49.032 0.133 49.104 ;
     RECT  0.084 49.104 0.133 49.128 ;
     RECT  0.133 17.712 1.145 49.176 ;
     RECT  1.145 17.712 2.408 49.08 ;
     RECT  2.408 2.148 2.512 66.972 ;
     RECT  2.512 2.418 2.704 66.702 ;
     RECT  2.704 17.76 4.385 49.464 ;
     RECT  4.385 17.904 4.565 49.464 ;
     RECT  4.565 18 5.393 49.128 ;
     RECT  5.393 18.192 5.753 49.128 ;
     RECT  5.753 30.912 5.825 49.128 ;
     RECT  5.753 18.192 6.437 29.928 ;
     RECT  6.437 18.24 7.081 29.928 ;
     RECT  5.825 30.912 7.081 49.08 ;
     RECT  7.081 18.24 7.693 49.08 ;
     RECT  7.693 18.24 7.808 49.512 ;
     RECT  7.808 2.148 7.912 66.972 ;
     RECT  7.912 2.418 8.104 66.702 ;
     RECT  8.104 44.88 8.165 49.512 ;
     RECT  8.104 27.888 8.201 27.912 ;
     RECT  8.165 44.88 8.201 48.696 ;
     RECT  8.201 44.976 8.243 48.696 ;
     RECT  8.104 33.36 8.273 40.632 ;
     RECT  8.104 41.712 8.273 43.848 ;
     RECT  8.243 45.6 8.281 48.696 ;
     RECT  8.281 45.696 8.339 48.696 ;
     RECT  8.339 45.696 8.381 48.168 ;
     RECT  8.104 29.28 8.417 32.088 ;
     RECT  8.104 19.776 8.453 26.664 ;
     RECT  8.381 45.696 8.453 47.688 ;
     RECT  8.453 19.776 8.525 25.32 ;
     RECT  8.273 35.52 8.525 40.632 ;
     RECT  8.273 33.36 8.561 34.392 ;
     RECT  8.525 20.928 8.921 25.32 ;
     RECT  8.525 35.52 8.921 39.288 ;
     RECT  8.273 43.056 8.957 43.848 ;
     RECT  8.561 33.696 8.993 34.392 ;
     RECT  8.921 20.928 9.029 25.272 ;
     RECT  9.029 20.928 9.137 24.408 ;
     RECT  8.417 29.28 9.209 29.592 ;
     RECT  8.957 43.056 9.209 43.08 ;
     RECT  9.137 23.568 9.245 24.408 ;
     RECT  8.453 26.304 9.245 26.664 ;
     RECT  8.993 33.696 9.245 34.152 ;
     RECT  8.921 35.52 9.245 37.464 ;
     RECT  8.453 45.696 9.281 47.208 ;
     RECT  9.245 26.544 9.353 26.664 ;
     RECT  9.281 45.696 9.353 46.104 ;
     RECT  9.281 47.136 9.353 47.208 ;
     RECT  8.273 41.712 9.389 42.024 ;
     RECT  9.209 29.568 9.461 29.592 ;
     RECT  8.921 38.448 9.461 39.288 ;
     RECT  9.245 35.712 9.497 37.464 ;
     RECT  9.245 33.84 9.533 34.152 ;
     RECT  9.137 20.928 9.641 22.488 ;
     RECT  9.461 38.688 9.641 39.288 ;
     RECT  9.533 34.128 10.609 34.152 ;
     RECT  10.609 33.312 10.829 34.152 ;
     RECT  8.525 19.776 13.208 19.8 ;
     RECT  9.641 21.216 13.208 22.488 ;
     RECT  9.245 23.856 13.208 23.88 ;
     RECT  9.353 26.592 13.208 26.616 ;
     RECT  8.417 30.912 13.208 32.088 ;
     RECT  10.829 34.128 13.208 34.152 ;
     RECT  9.497 36.576 13.208 36.936 ;
     RECT  9.641 38.688 13.208 38.712 ;
     RECT  8.525 40.608 13.208 40.632 ;
     RECT  9.389 41.904 13.208 42.024 ;
     RECT  9.353 45.696 13.208 45.72 ;
     RECT  9.353 47.184 13.208 47.208 ;
     RECT  8.104 50.544 13.208 50.568 ;
     RECT  13.208 2.148 13.312 66.972 ;
     RECT  13.312 2.418 13.504 66.702 ;
     RECT  17.66 66.912 17.665 66.936 ;
     RECT  17.665 66.72 17.737 66.936 ;
     RECT  17.737 66.72 17.845 67.32 ;
     RECT  17.845 66.72 18.421 67.896 ;
     RECT  13.504 19.776 18.608 19.8 ;
     RECT  13.504 21.216 18.608 22.488 ;
     RECT  13.504 23.856 18.608 23.88 ;
     RECT  13.504 26.592 18.608 26.616 ;
     RECT  13.504 30.912 18.608 32.088 ;
     RECT  13.504 34.128 18.608 34.152 ;
     RECT  13.504 36.576 18.608 36.936 ;
     RECT  13.504 38.688 18.608 38.712 ;
     RECT  13.504 40.608 18.608 40.632 ;
     RECT  13.504 41.904 18.608 42.024 ;
     RECT  13.504 45.696 18.608 45.72 ;
     RECT  13.504 47.184 18.608 47.208 ;
     RECT  13.504 50.544 18.608 50.568 ;
     RECT  18.493 64.08 18.608 64.104 ;
     RECT  18.421 66.72 18.608 68.424 ;
     RECT  18.608 2.148 18.712 68.424 ;
     RECT  18.712 2.418 18.781 68.424 ;
     RECT  18.781 2.418 18.899 68.472 ;
     RECT  18.899 2.418 18.904 67.32 ;
     RECT  18.899 68.4 18.995 68.472 ;
     RECT  18.904 63.648 19.187 64.392 ;
     RECT  18.995 68.448 19.379 68.472 ;
     RECT  19.429 68.928 19.577 69 ;
     RECT  19.577 68.976 19.685 69 ;
     RECT  19.187 63.648 19.897 64.104 ;
     RECT  18.904 38.688 20.077 40.632 ;
     RECT  18.904 41.904 20.077 42.024 ;
     RECT  19.897 63.12 20.333 64.104 ;
     RECT  18.904 66.72 20.437 67.32 ;
     RECT  20.333 63.12 20.444 64.056 ;
     RECT  20.444 62.304 20.531 64.056 ;
     RECT  20.437 66.624 20.581 67.32 ;
     RECT  20.581 66.624 20.617 67.848 ;
     RECT  20.077 38.688 20.837 42.024 ;
     RECT  18.904 50.544 20.905 50.568 ;
     RECT  20.905 50.544 20.945 50.808 ;
     RECT  20.837 40.608 21.121 42.024 ;
     RECT  20.531 63.12 21.161 64.056 ;
     RECT  20.945 50.784 21.253 50.808 ;
     RECT  21.161 63.648 21.299 64.056 ;
     RECT  20.617 66.624 21.299 68.424 ;
     RECT  21.253 50.784 21.34 51 ;
     RECT  21.299 66.624 21.557 67.896 ;
     RECT  21.121 40.608 21.805 42.072 ;
     RECT  21.733 65.568 21.817 65.592 ;
     RECT  21.805 40.608 21.841 42.552 ;
     RECT  21.557 66.72 21.875 67.896 ;
     RECT  18.904 19.776 21.877 19.8 ;
     RECT  18.904 23.856 22.097 23.88 ;
     RECT  21.841 40.608 22.205 42.744 ;
     RECT  21.877 19.776 22.241 19.896 ;
     RECT  22.205 40.608 22.457 42.552 ;
     RECT  21.299 64.032 22.813 64.056 ;
     RECT  22.741 68.4 22.931 68.424 ;
     RECT  21.34 50.784 23.317 50.808 ;
     RECT  22.813 64.032 23.353 64.152 ;
     RECT  21.875 66.72 23.821 67.272 ;
     RECT  23.353 63.216 23.893 64.152 ;
     RECT  23.821 66.72 23.987 67.848 ;
     RECT  22.021 6.816 24.008 6.84 ;
     RECT  22.241 19.872 24.008 19.896 ;
     RECT  18.904 21.216 24.008 22.488 ;
     RECT  18.904 26.592 24.008 26.616 ;
     RECT  18.904 30.912 24.008 32.088 ;
     RECT  18.904 34.128 24.008 34.152 ;
     RECT  22.789 35.184 24.008 35.208 ;
     RECT  18.904 36.576 24.008 36.936 ;
     RECT  20.837 38.688 24.008 39.624 ;
     RECT  22.457 40.608 24.008 42.072 ;
     RECT  18.904 45.696 24.008 45.72 ;
     RECT  18.904 47.184 24.008 47.208 ;
     RECT  23.317 50.784 24.008 50.904 ;
     RECT  23.893 63.216 24.008 64.2 ;
     RECT  23.987 66.72 24.008 67.272 ;
     RECT  24.008 2.148 24.112 67.272 ;
     RECT  24.112 2.418 24.304 67.272 ;
     RECT  24.304 62.592 24.329 65.16 ;
     RECT  24.329 62.592 24.419 64.344 ;
     RECT  24.229 68.928 24.497 68.952 ;
     RECT  24.304 21.216 24.833 22.488 ;
     RECT  24.304 26.592 25.085 26.616 ;
     RECT  24.304 66.192 25.157 67.272 ;
     RECT  24.497 68.832 25.285 68.952 ;
     RECT  25.285 68.592 25.475 68.952 ;
     RECT  25.475 68.592 25.571 68.856 ;
     RECT  25.571 68.688 25.619 68.856 ;
     RECT  25.619 68.832 25.667 68.856 ;
     RECT  24.833 21.504 26.165 22.488 ;
     RECT  24.419 63.024 26.165 64.344 ;
     RECT  26.165 63.024 26.201 63.288 ;
     RECT  26.165 64.32 26.437 64.344 ;
     RECT  25.157 67.056 26.485 67.272 ;
     RECT  24.304 50.784 26.773 50.808 ;
     RECT  26.485 66.816 26.809 67.272 ;
     RECT  26.773 50.784 26.813 50.904 ;
     RECT  26.437 64.32 26.885 64.392 ;
     RECT  26.917 68.88 27.157 68.904 ;
     RECT  26.165 22.464 27.173 22.488 ;
     RECT  26.201 63.072 27.213 63.288 ;
     RECT  26.885 64.32 27.213 64.344 ;
     RECT  27.213 63.072 27.299 64.344 ;
     RECT  26.809 66.72 27.349 67.272 ;
     RECT  27.157 68.88 27.349 68.952 ;
     RECT  27.349 66.528 27.443 67.272 ;
     RECT  27.299 63.072 27.601 64.296 ;
     RECT  27.349 68.832 27.781 68.952 ;
     RECT  27.443 67.248 28.145 67.272 ;
     RECT  27.781 68.784 28.21 68.952 ;
     RECT  28.21 68.784 28.325 69 ;
     RECT  28.325 68.784 28.355 68.952 ;
     RECT  27.601 62.64 28.645 64.296 ;
     RECT  29.125 67.248 29.365 67.272 ;
     RECT  24.304 6.816 29.408 6.84 ;
     RECT  24.304 19.872 29.408 19.896 ;
     RECT  24.304 30.912 29.408 32.088 ;
     RECT  24.304 34.128 29.408 34.152 ;
     RECT  24.304 35.184 29.408 35.208 ;
     RECT  24.304 36.576 29.408 36.936 ;
     RECT  24.304 38.688 29.408 39.624 ;
     RECT  24.304 40.608 29.408 42.072 ;
     RECT  24.304 45.696 29.408 45.72 ;
     RECT  24.304 47.184 29.408 47.208 ;
     RECT  26.813 50.88 29.408 50.904 ;
     RECT  28.645 62.64 29.408 64.392 ;
     RECT  28.753 66.192 29.408 66.216 ;
     RECT  29.365 67.2 29.408 67.272 ;
     RECT  29.408 2.148 29.512 67.272 ;
     RECT  28.355 68.88 29.555 68.952 ;
     RECT  29.555 68.88 29.651 68.904 ;
     RECT  29.512 2.418 29.704 67.272 ;
     RECT  29.704 63.216 29.843 65.112 ;
     RECT  29.843 64.992 30.035 65.112 ;
     RECT  30.035 65.088 30.197 65.112 ;
     RECT  29.704 66.288 30.625 67.272 ;
     RECT  29.704 30.384 30.629 32.088 ;
     RECT  29.704 13.824 30.707 14.232 ;
     RECT  30.625 66.288 30.803 67.848 ;
     RECT  29.843 63.216 31.201 63.816 ;
     RECT  30.629 30.72 31.205 32.088 ;
     RECT  31.201 63.216 31.285 64.056 ;
     RECT  30.707 13.824 31.381 13.848 ;
     RECT  31.285 63.168 31.421 64.056 ;
     RECT  31.561 3.984 31.633 4.008 ;
     RECT  29.704 36.576 31.637 36.936 ;
     RECT  31.561 68.352 31.717 68.376 ;
     RECT  30.803 66.288 31.813 67.272 ;
     RECT  31.717 68.352 31.813 68.952 ;
     RECT  31.813 1.008 31.849 1.032 ;
     RECT  31.813 66.288 31.955 68.952 ;
     RECT  31.633 3.888 31.957 4.008 ;
     RECT  31.957 3.792 31.993 4.008 ;
     RECT  31.955 68.352 32.051 68.952 ;
     RECT  31.993 3.696 32.065 4.008 ;
     RECT  31.381 13.056 32.101 13.848 ;
     RECT  29.704 6.816 32.156 6.84 ;
     RECT  32.065 2.784 32.173 4.008 ;
     RECT  31.993 5.04 32.197 5.064 ;
     RECT  32.156 6.24 32.197 6.84 ;
     RECT  31.637 36.576 32.213 36.888 ;
     RECT  32.197 5.04 32.243 6.84 ;
     RECT  32.101 13.056 32.243 14.232 ;
     RECT  31.849 1.008 32.353 1.128 ;
     RECT  32.173 2.256 32.389 4.008 ;
     RECT  31.955 66.288 32.461 67.272 ;
     RECT  32.461 65.52 32.573 67.272 ;
     RECT  32.389 2.208 32.713 4.008 ;
     RECT  32.243 5.04 32.713 5.64 ;
     RECT  32.353 0.096 32.723 1.128 ;
     RECT  32.051 68.928 32.771 68.952 ;
     RECT  31.421 63.216 32.812 64.056 ;
     RECT  32.713 2.208 32.897 5.64 ;
     RECT  32.828 62.736 32.915 62.76 ;
     RECT  32.812 63.792 32.965 64.056 ;
     RECT  29.704 38.688 33.001 39.624 ;
     RECT  32.573 65.52 33.185 65.544 ;
     RECT  32.723 0.576 33.253 1.128 ;
     RECT  32.897 2.208 33.253 5.304 ;
     RECT  32.965 63.792 33.395 64.392 ;
     RECT  33.001 38.496 33.505 39.624 ;
     RECT  29.704 40.608 33.505 42.072 ;
     RECT  33.253 0.576 33.581 5.304 ;
     RECT  32.243 6.72 33.721 6.84 ;
     RECT  33.581 0.576 33.761 1.176 ;
     RECT  33.721 6.72 33.793 7.464 ;
     RECT  32.573 66.72 33.793 67.272 ;
     RECT  33.395 63.792 33.797 63.816 ;
     RECT  33.581 2.256 33.833 5.304 ;
     RECT  33.761 0.576 33.913 0.696 ;
     RECT  33.833 4.464 34.009 5.304 ;
     RECT  33.793 6.288 34.009 7.464 ;
     RECT  33.913 0.576 34.163 0.648 ;
     RECT  33.505 38.496 34.189 42.072 ;
     RECT  29.704 50.784 34.213 50.808 ;
     RECT  33.793 66.72 34.355 67.848 ;
     RECT  33.937 64.992 34.441 65.016 ;
     RECT  29.704 35.184 34.508 35.208 ;
     RECT  34.163 0.624 34.547 0.648 ;
     RECT  31.205 30.864 34.549 32.088 ;
     RECT  29.704 34.128 34.549 34.152 ;
     RECT  34.508 35.136 34.549 35.208 ;
     RECT  34.355 66.72 34.657 67.368 ;
     RECT  29.704 19.872 34.693 19.896 ;
     RECT  33.833 2.256 34.789 3.432 ;
     RECT  34.789 1.728 34.808 3.432 ;
     RECT  34.009 4.464 34.808 7.464 ;
     RECT  34.693 19.536 34.808 19.896 ;
     RECT  33.037 23.616 34.808 23.64 ;
     RECT  34.549 30.816 34.808 32.088 ;
     RECT  34.549 34.128 34.808 35.208 ;
     RECT  32.213 36.576 34.808 36.6 ;
     RECT  34.189 38.208 34.808 42.072 ;
     RECT  29.704 45.696 34.808 45.72 ;
     RECT  29.704 47.184 34.808 47.208 ;
     RECT  34.213 50.592 34.808 50.808 ;
     RECT  34.597 63.072 34.808 63.624 ;
     RECT  34.441 64.896 34.808 65.016 ;
     RECT  34.657 66.48 34.808 67.368 ;
     RECT  34.808 1.728 35.104 67.368 ;
     RECT  35.104 66.48 35.123 67.368 ;
     RECT  34.789 68.736 35.173 68.76 ;
     RECT  35.173 68.736 35.219 69 ;
     RECT  35.104 33.888 35.345 34.152 ;
     RECT  35.104 63.072 35.345 63.72 ;
     RECT  35.123 66.48 35.381 67.272 ;
     RECT  35.104 1.728 35.741 7.416 ;
     RECT  35.219 68.832 35.747 69 ;
     RECT  35.737 0.576 35.821 0.6 ;
     RECT  35.104 64.896 35.993 64.92 ;
     RECT  35.741 5.664 36.305 7.416 ;
     RECT  35.747 68.88 36.371 69 ;
     RECT  35.345 63.216 36.373 63.72 ;
     RECT  36.305 5.664 36.389 7.992 ;
     RECT  36.371 68.88 36.419 68.952 ;
     RECT  36.373 63.168 36.421 63.72 ;
     RECT  35.741 1.728 36.493 4.68 ;
     RECT  36.421 63.072 36.508 63.72 ;
     RECT  36.493 1.152 36.605 4.68 ;
     RECT  35.381 66.72 36.853 67.272 ;
     RECT  36.605 1.152 36.947 1.176 ;
     RECT  36.889 64.944 37.037 64.968 ;
     RECT  36.605 2.256 37.177 4.68 ;
     RECT  36.389 5.664 37.177 7.704 ;
     RECT  36.853 66.72 37.331 67.848 ;
     RECT  36.419 68.928 37.381 68.952 ;
     RECT  36.508 63.216 37.573 63.72 ;
     RECT  37.177 2.256 37.645 7.704 ;
     RECT  37.717 65.568 37.801 65.592 ;
     RECT  37.331 66.72 37.906 67.32 ;
     RECT  37.645 1.68 38.041 7.704 ;
     RECT  37.906 66.672 38.051 67.32 ;
     RECT  38.041 1.68 38.099 8.088 ;
     RECT  38.051 66.72 38.099 67.32 ;
     RECT  38.099 66.72 38.195 67.272 ;
     RECT  37.381 68.832 38.329 68.952 ;
     RECT  35.104 47.184 38.365 47.208 ;
     RECT  38.329 68.832 38.38 69 ;
     RECT  38.38 68.928 38.413 69 ;
     RECT  38.195 66.768 38.483 67.272 ;
     RECT  37.573 63.12 38.533 63.72 ;
     RECT  38.099 2.4 38.617 8.088 ;
     RECT  38.365 46.8 38.761 47.208 ;
     RECT  35.104 36.576 38.765 36.6 ;
     RECT  38.533 62.832 39.109 63.72 ;
     RECT  38.617 2.4 39.121 8.232 ;
     RECT  39.121 2.4 39.193 8.376 ;
     RECT  39.109 62.832 39.197 63.816 ;
     RECT  38.761 46.8 39.373 47.4 ;
     RECT  39.197 62.832 39.445 63.72 ;
     RECT  38.413 68.928 39.445 68.952 ;
     RECT  39.193 2.304 39.481 8.376 ;
     RECT  39.445 68.832 39.481 68.952 ;
     RECT  39.481 68.832 39.532 69 ;
     RECT  39.532 68.928 39.565 69 ;
     RECT  39.481 1.68 39.731 8.376 ;
     RECT  39.397 0.576 39.925 0.6 ;
     RECT  38.483 67.104 40.021 67.272 ;
     RECT  39.925 0.192 40.069 0.6 ;
     RECT  39.397 65.712 40.129 65.736 ;
     RECT  39.731 1.728 40.208 8.376 ;
     RECT  35.104 19.536 40.208 19.56 ;
     RECT  35.104 23.616 40.208 23.64 ;
     RECT  35.104 30.864 40.208 32.088 ;
     RECT  35.345 33.888 40.208 33.912 ;
     RECT  35.104 38.928 40.208 39.624 ;
     RECT  35.104 40.608 40.208 42.072 ;
     RECT  35.104 45.696 40.208 45.72 ;
     RECT  39.373 46.8 40.208 47.976 ;
     RECT  35.104 50.592 40.208 50.616 ;
     RECT  39.445 62.592 40.208 63.72 ;
     RECT  40.129 64.992 40.208 65.736 ;
     RECT  40.021 66.72 40.208 67.272 ;
     RECT  40.069 0.192 40.211 0.696 ;
     RECT  40.208 1.728 40.504 67.272 ;
     RECT  40.211 0.192 40.549 0.6 ;
     RECT  39.565 68.928 40.549 68.952 ;
     RECT  40.549 68.88 40.739 68.952 ;
     RECT  40.549 0.096 40.925 0.6 ;
     RECT  40.504 67.152 41.021 67.272 ;
     RECT  40.504 36.48 41.075 36.504 ;
     RECT  40.504 38.928 41.105 39.624 ;
     RECT  41.021 67.152 41.105 67.32 ;
     RECT  40.504 64.944 41.113 65.016 ;
     RECT  41.105 67.152 41.171 67.272 ;
     RECT  41.113 64.944 41.213 64.968 ;
     RECT  40.504 40.608 41.249 42.744 ;
     RECT  40.504 47.952 41.321 47.976 ;
     RECT  40.504 62.832 41.429 63.816 ;
     RECT  40.925 0.096 41.501 0.12 ;
     RECT  41.171 67.152 41.749 67.224 ;
     RECT  41.749 66.72 41.821 67.224 ;
     RECT  40.739 68.928 42.083 68.952 ;
     RECT  40.504 30.864 42.181 32.232 ;
     RECT  40.504 33.888 42.181 33.912 ;
     RECT  41.821 66.672 42.181 67.224 ;
     RECT  42.181 30.864 42.829 33.912 ;
     RECT  41.429 63.12 42.901 63.816 ;
     RECT  42.181 66.672 42.901 67.272 ;
     RECT  40.504 1.728 42.949 8.52 ;
     RECT  42.901 66.576 43.013 67.272 ;
     RECT  42.949 0.912 43.045 8.52 ;
     RECT  43.292 68.832 43.333 68.856 ;
     RECT  42.901 63.12 43.34 64.056 ;
     RECT  43.045 0.816 43.517 8.52 ;
     RECT  42.829 30.864 43.517 34.152 ;
     RECT  43.333 68.736 43.621 68.856 ;
     RECT  43.621 68.736 43.685 68.952 ;
     RECT  43.34 62.832 43.763 64.056 ;
     RECT  43.685 68.736 43.811 69 ;
     RECT  43.013 66.72 43.859 67.272 ;
     RECT  43.763 63.216 44.021 64.056 ;
     RECT  43.517 33.504 44.089 34.152 ;
     RECT  40.504 19.536 44.149 19.56 ;
     RECT  43.517 0.816 44.195 7.944 ;
     RECT  44.195 7.392 44.237 7.944 ;
     RECT  44.089 33.504 44.381 34.392 ;
     RECT  44.381 33.504 44.453 34.152 ;
     RECT  44.237 7.392 44.597 7.416 ;
     RECT  41.105 39.024 44.773 39.624 ;
     RECT  41.249 40.608 44.773 42.072 ;
     RECT  44.021 63.216 44.773 63.912 ;
     RECT  43.859 67.152 44.924 67.272 ;
     RECT  44.773 62.832 45.053 63.912 ;
     RECT  44.773 39.024 45.097 42.072 ;
     RECT  45.097 39.024 45.133 42.216 ;
     RECT  44.924 66.72 45.233 67.272 ;
     RECT  45.053 62.736 45.253 63.912 ;
     RECT  45.233 66.096 45.26 67.272 ;
     RECT  45.26 65.952 45.397 67.272 ;
     RECT  45.397 65.616 45.445 67.272 ;
     RECT  43.811 68.88 45.539 69 ;
     RECT  45.539 68.928 45.587 69 ;
     RECT  44.195 0.816 45.608 6.264 ;
     RECT  44.149 19.536 45.608 19.8 ;
     RECT  40.504 23.616 45.608 23.64 ;
     RECT  43.517 30.864 45.608 31.752 ;
     RECT  44.453 34.128 45.608 34.152 ;
     RECT  45.133 39.024 45.608 42.312 ;
     RECT  40.504 45.696 45.608 45.72 ;
     RECT  40.504 46.8 45.608 46.824 ;
     RECT  40.504 50.592 45.608 50.616 ;
     RECT  45.253 62.736 45.608 64.44 ;
     RECT  45.445 65.52 45.608 67.272 ;
     RECT  45.608 0.816 45.745 67.272 ;
     RECT  45.745 0.816 45.904 67.848 ;
     RECT  45.904 40.608 45.965 42.312 ;
     RECT  45.904 64.896 46.001 65.544 ;
     RECT  45.904 0.816 46.145 5.544 ;
     RECT  45.904 62.208 46.181 63.816 ;
     RECT  45.965 40.656 46.217 42.312 ;
     RECT  46.001 64.896 46.252 64.968 ;
     RECT  46.145 0.816 46.289 4.344 ;
     RECT  46.252 64.944 46.333 64.968 ;
     RECT  45.904 66.624 46.361 67.848 ;
     RECT  46.361 66.72 46.396 67.848 ;
     RECT  46.289 2.256 46.541 4.152 ;
     RECT  45.587 68.928 46.547 68.952 ;
     RECT  46.541 2.304 46.613 4.152 ;
     RECT  46.145 5.52 46.613 5.544 ;
     RECT  46.396 66.816 46.643 67.848 ;
     RECT  46.217 40.656 46.793 42.216 ;
     RECT  46.643 67.104 46.835 67.848 ;
     RECT  46.289 0.816 46.865 0.984 ;
     RECT  47.005 43.584 47.041 43.608 ;
     RECT  47.041 43.488 47.077 43.608 ;
     RECT  46.181 62.64 47.197 63.816 ;
     RECT  46.613 2.304 47.261 3.96 ;
     RECT  47.261 2.4 47.369 3.96 ;
     RECT  46.865 0.864 47.441 0.984 ;
     RECT  47.197 62.736 47.549 63.816 ;
     RECT  47.077 43.488 47.653 43.656 ;
     RECT  46.835 67.104 47.653 67.272 ;
     RECT  47.369 2.4 47.693 3.672 ;
     RECT  47.653 43.488 47.693 44.424 ;
     RECT  47.693 2.4 47.729 2.568 ;
     RECT  47.653 66.768 47.749 67.272 ;
     RECT  47.693 43.584 47.801 44.424 ;
     RECT  47.441 0.864 47.837 0.888 ;
     RECT  45.904 50.592 47.837 50.616 ;
     RECT  47.801 43.632 47.945 44.424 ;
     RECT  47.729 2.544 47.981 2.568 ;
     RECT  47.693 3.648 47.981 3.672 ;
     RECT  47.945 44.4 48.265 44.424 ;
     RECT  45.904 45.696 48.265 45.72 ;
     RECT  47.549 62.736 48.601 63.624 ;
     RECT  45.904 19.536 48.917 19.8 ;
     RECT  48.265 44.4 49.025 45.72 ;
     RECT  47.749 66.72 49.025 67.272 ;
     RECT  49.025 44.88 49.061 45.72 ;
     RECT  48.957 68.352 49.061 68.376 ;
     RECT  48.601 62.832 49.169 63.624 ;
     RECT  49.025 67.152 49.205 67.272 ;
     RECT  45.904 23.616 49.237 23.64 ;
     RECT  48.917 19.68 49.283 19.704 ;
     RECT  49.169 62.88 49.561 63.624 ;
     RECT  49.205 67.152 49.601 67.224 ;
     RECT  49.561 62.88 49.673 63.816 ;
     RECT  49.601 67.2 49.673 67.224 ;
     RECT  49.061 45.12 49.781 45.72 ;
     RECT  49.673 63.792 50.005 63.816 ;
     RECT  49.781 45.552 50.101 45.72 ;
     RECT  45.904 46.8 50.101 46.824 ;
     RECT  49.237 22.848 51.008 23.64 ;
     RECT  45.904 30.864 51.008 31.752 ;
     RECT  45.904 38.928 51.008 39.624 ;
     RECT  46.793 40.656 51.008 42.072 ;
     RECT  50.101 45.552 51.008 46.824 ;
     RECT  48.517 50.112 51.008 50.136 ;
     RECT  50.005 63.792 51.008 64.584 ;
     RECT  51.008 2.148 51.112 66.972 ;
     RECT  51.112 2.418 51.304 66.702 ;
     RECT  51.304 49.728 51.365 50.136 ;
     RECT  51.304 22.848 51.401 23.64 ;
     RECT  51.401 22.992 56.408 23.64 ;
     RECT  51.304 30.864 56.408 31.752 ;
     RECT  51.304 38.928 56.408 39.624 ;
     RECT  51.304 40.656 56.408 42.072 ;
     RECT  51.304 46.8 56.408 46.824 ;
     RECT  51.365 49.728 56.408 49.752 ;
     RECT  56.408 2.148 56.512 66.972 ;
     RECT  56.512 2.418 56.704 66.702 ;
     RECT  56.704 22.992 58.705 23.64 ;
     RECT  56.704 46.8 58.705 46.824 ;
     RECT  56.704 30.864 58.741 31.752 ;
     RECT  58.705 32.736 58.741 32.76 ;
     RECT  58.705 46.032 58.889 46.824 ;
     RECT  58.705 22.992 58.925 23.88 ;
     RECT  58.705 26.352 58.925 26.376 ;
     RECT  58.889 46.176 59.605 46.824 ;
     RECT  58.705 47.904 59.605 47.928 ;
     RECT  56.704 40.656 59.713 42.072 ;
     RECT  58.741 30.864 59.893 32.856 ;
     RECT  59.852 37.584 59.893 37.608 ;
     RECT  56.704 38.928 59.893 39.624 ;
     RECT  59.713 40.656 59.893 42.744 ;
     RECT  56.704 49.728 59.941 49.752 ;
     RECT  59.749 21.024 59.965 21.048 ;
     RECT  58.925 22.992 59.965 23.64 ;
     RECT  59.965 21.024 60.001 23.64 ;
     RECT  59.893 25.2 60.001 25.224 ;
     RECT  60.037 34.704 60.181 34.728 ;
     RECT  59.893 44.736 60.217 44.76 ;
     RECT  59.605 46.176 60.217 47.928 ;
     RECT  60.181 34.704 60.253 34.776 ;
     RECT  59.893 30.864 60.325 33.096 ;
     RECT  60.253 34.128 60.325 34.776 ;
     RECT  60.217 44.736 60.365 47.928 ;
     RECT  60.365 44.736 60.469 45.72 ;
     RECT  60.469 44.496 60.545 45.72 ;
     RECT  60.325 30.864 60.685 34.776 ;
     RECT  59.893 35.856 60.685 35.88 ;
     RECT  59.893 37.584 60.793 39.624 ;
     RECT  60.685 30.864 60.865 35.88 ;
     RECT  60.793 37.104 60.901 39.624 ;
     RECT  60.001 21.024 60.949 25.224 ;
     RECT  59.893 40.656 60.973 43.32 ;
     RECT  60.545 44.496 60.973 45.528 ;
     RECT  59.857 51.12 61.081 51.144 ;
     RECT  60.901 36.864 61.525 39.624 ;
     RECT  60.973 40.656 61.525 45.528 ;
     RECT  60.365 46.704 61.525 47.928 ;
     RECT  61.657 26.832 61.729 26.856 ;
     RECT  60.949 20.448 61.808 25.224 ;
     RECT  61.729 26.832 61.808 26.904 ;
     RECT  61.045 27.888 61.808 27.912 ;
     RECT  61.117 28.944 61.808 28.968 ;
     RECT  60.865 30.144 61.808 35.88 ;
     RECT  61.525 36.864 61.808 45.528 ;
     RECT  61.525 46.512 61.808 47.928 ;
     RECT  59.941 49.056 61.808 49.752 ;
     RECT  61.081 50.832 61.808 51.144 ;
     RECT  61.808 2.148 61.912 66.972 ;
     RECT  61.912 2.418 62.104 66.702 ;
     RECT  62.104 43.296 62.201 45.528 ;
     RECT  62.104 46.512 62.201 49.56 ;
     RECT  62.104 20.976 62.237 35.736 ;
     RECT  62.104 36.864 62.243 42.072 ;
     RECT  62.201 45.216 62.273 45.528 ;
     RECT  62.273 45.504 62.309 45.528 ;
     RECT  62.243 36.864 62.489 39.624 ;
     RECT  62.201 46.512 62.705 49.08 ;
     RECT  62.237 20.976 62.957 28.392 ;
     RECT  62.489 36.864 63.097 36.936 ;
     RECT  62.957 20.976 63.1 26.76 ;
     RECT  62.705 46.512 63.205 48.696 ;
     RECT  63.1 20.976 63.389 25.272 ;
     RECT  62.237 29.664 63.389 35.736 ;
     RECT  62.104 50.832 63.457 50.856 ;
     RECT  63.097 36.816 63.493 36.936 ;
     RECT  63.389 29.664 63.497 34.2 ;
     RECT  63.457 50.832 63.497 51.288 ;
     RECT  63.389 35.328 63.529 35.736 ;
     RECT  63.493 36.768 63.529 36.936 ;
     RECT  62.489 38.16 63.533 39.624 ;
     RECT  62.957 27.792 63.589 28.392 ;
     RECT  62.201 43.296 63.605 43.848 ;
     RECT  63.205 46.32 63.637 48.696 ;
     RECT  63.497 30.384 63.677 34.2 ;
     RECT  63.637 46.08 63.677 48.696 ;
     RECT  63.389 20.976 63.713 25.224 ;
     RECT  63.1 26.256 63.785 26.76 ;
     RECT  63.713 20.976 63.817 21.768 ;
     RECT  63.677 46.08 63.821 48.456 ;
     RECT  63.529 35.328 63.889 36.936 ;
     RECT  63.677 32.688 63.929 34.2 ;
     RECT  63.785 26.4 63.961 26.76 ;
     RECT  63.589 27.792 64.001 29.256 ;
     RECT  63.889 35.328 64.001 37.08 ;
     RECT  63.925 44.976 64.069 45 ;
     RECT  64.001 27.888 64.109 29.256 ;
     RECT  62.243 40.656 64.393 42.072 ;
     RECT  63.605 43.296 64.393 43.32 ;
     RECT  64.109 27.888 64.397 28.968 ;
     RECT  64.393 40.656 64.469 43.32 ;
     RECT  63.497 51.264 64.505 51.288 ;
     RECT  63.929 33.888 64.541 34.2 ;
     RECT  63.533 38.64 64.541 39.624 ;
     RECT  63.713 23.136 64.757 25.224 ;
     RECT  63.677 30.384 64.757 31.416 ;
     RECT  64.757 24.336 64.789 25.224 ;
     RECT  63.961 26.4 64.789 26.808 ;
     RECT  64.541 39.072 64.789 39.624 ;
     RECT  64.469 40.656 64.789 42.456 ;
     RECT  63.817 20.496 64.793 21.768 ;
     RECT  64.789 39.072 64.793 42.456 ;
     RECT  63.929 32.688 64.829 32.904 ;
     RECT  63.821 46.08 64.865 46.824 ;
     RECT  64.789 24.336 64.937 26.808 ;
     RECT  64.793 39.072 64.937 42.072 ;
     RECT  64.865 46.32 64.937 46.824 ;
     RECT  64.001 35.328 64.969 35.64 ;
     RECT  64.397 27.888 64.973 28.44 ;
     RECT  64.001 36.816 64.973 37.08 ;
     RECT  64.937 39.216 64.973 42.072 ;
     RECT  64.937 46.608 64.973 46.824 ;
     RECT  64.937 24.336 65.009 25.8 ;
     RECT  64.969 35.328 65.009 35.784 ;
     RECT  64.973 39.216 65.009 39.912 ;
     RECT  64.94 43.872 65.027 43.896 ;
     RECT  64.793 21.12 65.045 21.768 ;
     RECT  64.757 30.384 65.077 31.272 ;
     RECT  64.757 23.136 65.081 23.16 ;
     RECT  65.009 39.216 65.117 39.24 ;
     RECT  65.009 24.432 65.225 25.8 ;
     RECT  64.937 26.784 65.333 26.808 ;
     RECT  64.541 34.176 65.405 34.2 ;
     RECT  63.821 47.856 65.405 48.456 ;
     RECT  64.973 41.472 65.513 42.072 ;
     RECT  65.225 24.432 65.621 24.456 ;
     RECT  65.405 48.432 65.693 48.456 ;
     RECT  64.973 36.864 65.725 37.08 ;
     RECT  65.045 21.744 65.797 21.768 ;
     RECT  65.725 36.864 65.801 37.224 ;
     RECT  64.973 28.416 66.053 28.44 ;
     RECT  65.513 41.472 66.053 41.496 ;
     RECT  65.797 21.744 66.121 21.96 ;
     RECT  65.009 35.568 66.121 35.784 ;
     RECT  64.069 44.928 66.121 45 ;
     RECT  65.077 29.712 66.125 31.272 ;
     RECT  66.121 44.736 66.161 45 ;
     RECT  66.121 21.744 66.193 22.536 ;
     RECT  66.161 44.736 66.233 44.76 ;
     RECT  64.973 46.608 66.265 46.728 ;
     RECT  66.193 21.744 66.305 23.16 ;
     RECT  65.221 32.976 66.305 33 ;
     RECT  65.801 37.2 66.373 37.224 ;
     RECT  65.545 27.12 66.697 27.144 ;
     RECT  66.125 29.712 66.697 29.736 ;
     RECT  66.125 30.768 66.697 31.272 ;
     RECT  66.265 45.792 66.697 46.728 ;
     RECT  66.121 49.008 66.697 49.032 ;
     RECT  66.697 27.12 67.201 27.336 ;
     RECT  66.121 35.424 67.201 35.784 ;
     RECT  66.373 37.2 67.201 38.088 ;
     RECT  67.201 27.12 67.237 27.912 ;
     RECT  66.697 29.328 67.237 29.736 ;
     RECT  66.553 33.12 67.237 33.144 ;
     RECT  67.201 35.424 67.237 38.088 ;
     RECT  66.697 39.216 67.237 39.24 ;
     RECT  66.697 43.152 67.237 43.176 ;
     RECT  66.697 44.304 67.237 44.328 ;
     RECT  66.697 45.792 67.237 47.496 ;
     RECT  66.697 48.624 67.237 49.032 ;
     RECT  67.237 20.016 67.273 20.04 ;
     RECT  66.305 21.744 67.273 22.536 ;
     RECT  66.733 23.664 67.273 23.688 ;
     RECT  65.225 25.488 67.273 25.8 ;
     RECT  67.237 27.12 67.273 29.736 ;
     RECT  66.697 30.768 67.273 31.656 ;
     RECT  67.237 33.12 67.273 33.96 ;
     RECT  67.237 35.088 67.273 38.088 ;
     RECT  67.237 39.216 67.273 40.008 ;
     RECT  66.733 41.904 67.273 41.928 ;
     RECT  67.237 43.152 67.273 44.616 ;
     RECT  67.237 45.792 67.273 49.992 ;
     RECT  67.273 21.744 67.741 38.184 ;
     RECT  67.273 39.216 67.741 41.928 ;
     RECT  67.273 43.152 67.741 49.992 ;
     RECT  67.273 20.016 67.777 20.328 ;
     RECT  67.741 21.552 67.777 38.184 ;
     RECT  67.741 39.216 67.777 50.856 ;
     RECT  67.777 20.016 68.317 50.856 ;
     RECT  68.317 20.016 68.353 51.24 ;
     RECT  68.353 20.016 69.001 51.336 ;
     RECT  69.001 19.92 69.036 19.944 ;
     RECT  69.001 19.944 69.084 20.016 ;
     RECT  69.001 20.016 69.036 20.04 ;
     RECT  69.001 20.04 69.084 20.112 ;
     RECT  69.001 20.112 69.036 20.136 ;
     RECT  69.001 20.136 69.084 20.208 ;
     RECT  69.001 20.208 69.036 20.232 ;
     RECT  69.001 20.232 69.084 20.304 ;
     RECT  69.001 20.304 69.036 20.328 ;
     RECT  69.001 20.328 69.084 20.4 ;
     RECT  69.001 20.4 69.036 20.424 ;
     RECT  69.001 20.424 69.084 20.496 ;
     RECT  69.001 20.496 69.036 20.52 ;
     RECT  69.001 20.52 69.084 20.592 ;
     RECT  69.001 20.592 69.036 20.616 ;
     RECT  69.001 20.616 69.084 20.688 ;
     RECT  69.001 20.688 69.036 20.712 ;
     RECT  69.001 20.712 69.084 20.784 ;
     RECT  69.001 20.784 69.036 20.808 ;
     RECT  69.001 20.808 69.084 20.88 ;
     RECT  69.001 20.88 69.036 20.904 ;
     RECT  69.001 20.904 69.084 20.976 ;
     RECT  69.001 20.976 69.036 21 ;
     RECT  69.001 21 69.084 21.072 ;
     RECT  69.001 21.072 69.036 21.096 ;
     RECT  69.001 21.096 69.084 21.168 ;
     RECT  69.001 21.168 69.036 21.192 ;
     RECT  69.001 21.192 69.084 21.264 ;
     RECT  69.001 21.264 69.036 21.288 ;
     RECT  69.001 21.288 69.084 21.36 ;
     RECT  69.001 21.36 69.036 21.384 ;
     RECT  69.001 21.384 69.084 21.456 ;
     RECT  69.001 21.456 69.036 21.48 ;
     RECT  69.001 21.48 69.084 21.552 ;
     RECT  69.001 21.552 69.036 21.576 ;
     RECT  69.001 21.576 69.084 21.648 ;
     RECT  69.001 21.648 69.036 21.672 ;
     RECT  69.001 21.672 69.084 21.744 ;
     RECT  69.001 21.744 69.036 21.768 ;
     RECT  69.001 21.768 69.084 21.84 ;
     RECT  69.001 21.84 69.036 21.864 ;
     RECT  69.001 21.864 69.084 21.936 ;
     RECT  69.001 21.936 69.036 21.96 ;
     RECT  69.001 21.96 69.084 22.032 ;
     RECT  69.001 22.032 69.036 22.056 ;
     RECT  69.001 22.056 69.084 22.128 ;
     RECT  69.001 22.128 69.036 22.152 ;
     RECT  69.001 22.152 69.084 22.224 ;
     RECT  69.001 22.224 69.036 22.248 ;
     RECT  69.001 22.248 69.084 22.32 ;
     RECT  69.001 22.32 69.036 22.344 ;
     RECT  69.001 22.344 69.084 22.416 ;
     RECT  69.001 22.416 69.036 22.44 ;
     RECT  69.001 22.44 69.084 22.512 ;
     RECT  69.001 22.512 69.036 22.536 ;
     RECT  69.001 22.536 69.084 22.608 ;
     RECT  69.001 22.608 69.036 22.632 ;
     RECT  69.001 22.632 69.084 22.704 ;
     RECT  69.001 22.704 69.036 22.728 ;
     RECT  69.001 22.728 69.084 22.8 ;
     RECT  69.001 22.8 69.036 22.824 ;
     RECT  69.001 22.824 69.084 22.896 ;
     RECT  69.001 22.896 69.036 22.92 ;
     RECT  69.001 22.92 69.084 22.992 ;
     RECT  69.001 22.992 69.036 23.016 ;
     RECT  69.001 23.016 69.084 23.088 ;
     RECT  69.001 23.088 69.036 23.112 ;
     RECT  69.001 23.112 69.084 23.184 ;
     RECT  69.001 23.184 69.036 23.208 ;
     RECT  69.001 23.208 69.084 23.28 ;
     RECT  69.001 23.28 69.036 23.304 ;
     RECT  69.001 23.304 69.084 23.376 ;
     RECT  69.001 23.376 69.036 23.4 ;
     RECT  69.001 23.4 69.084 23.472 ;
     RECT  69.001 23.472 69.036 23.496 ;
     RECT  69.001 23.496 69.084 23.568 ;
     RECT  69.001 23.568 69.036 23.592 ;
     RECT  69.001 23.592 69.084 23.664 ;
     RECT  69.001 23.664 69.036 23.688 ;
     RECT  69.001 23.688 69.084 23.76 ;
     RECT  69.001 23.76 69.036 23.784 ;
     RECT  69.001 23.784 69.084 23.856 ;
     RECT  69.001 23.856 69.036 23.88 ;
     RECT  69.001 23.88 69.084 23.952 ;
     RECT  69.001 23.952 69.036 23.976 ;
     RECT  69.001 23.976 69.084 24.048 ;
     RECT  69.001 24.048 69.036 24.072 ;
     RECT  69.001 24.072 69.084 24.144 ;
     RECT  69.001 24.144 69.036 24.168 ;
     RECT  69.001 24.168 69.084 24.24 ;
     RECT  69.001 24.24 69.036 24.264 ;
     RECT  69.001 24.264 69.084 24.336 ;
     RECT  69.001 24.336 69.036 24.36 ;
     RECT  69.001 24.36 69.084 24.432 ;
     RECT  69.001 24.432 69.036 24.456 ;
     RECT  69.001 24.456 69.084 24.528 ;
     RECT  69.001 24.528 69.036 24.552 ;
     RECT  69.001 24.552 69.084 24.624 ;
     RECT  69.001 24.624 69.036 24.648 ;
     RECT  69.001 24.648 69.084 24.72 ;
     RECT  69.001 24.72 69.036 24.744 ;
     RECT  69.001 24.744 69.084 24.816 ;
     RECT  69.001 24.816 69.036 24.84 ;
     RECT  69.001 24.84 69.084 24.912 ;
     RECT  69.001 24.912 69.036 24.936 ;
     RECT  69.001 24.936 69.084 25.008 ;
     RECT  69.001 25.008 69.036 25.032 ;
     RECT  69.001 25.032 69.084 25.104 ;
     RECT  69.001 25.104 69.036 25.128 ;
     RECT  69.001 25.128 69.084 25.2 ;
     RECT  69.001 25.2 69.036 25.224 ;
     RECT  69.001 25.224 69.084 25.296 ;
     RECT  69.001 25.296 69.036 25.32 ;
     RECT  69.001 25.32 69.084 25.392 ;
     RECT  69.001 25.392 69.036 25.416 ;
     RECT  69.001 25.416 69.084 25.488 ;
     RECT  69.001 25.488 69.036 25.512 ;
     RECT  69.001 25.512 69.084 25.584 ;
     RECT  69.001 25.584 69.036 25.608 ;
     RECT  69.001 25.608 69.084 25.68 ;
     RECT  69.001 25.68 69.036 25.704 ;
     RECT  69.001 25.704 69.084 25.776 ;
     RECT  69.001 25.776 69.036 25.8 ;
     RECT  69.001 25.8 69.084 25.872 ;
     RECT  69.001 25.872 69.036 25.896 ;
     RECT  69.001 25.896 69.084 25.968 ;
     RECT  69.001 25.968 69.036 25.992 ;
     RECT  69.001 25.992 69.084 26.064 ;
     RECT  69.001 26.064 69.036 26.088 ;
     RECT  69.001 26.088 69.084 26.16 ;
     RECT  69.001 26.16 69.036 26.184 ;
     RECT  69.001 26.184 69.084 26.256 ;
     RECT  69.001 26.256 69.036 26.28 ;
     RECT  69.001 26.28 69.084 26.352 ;
     RECT  69.001 26.352 69.036 26.376 ;
     RECT  69.001 26.376 69.084 26.448 ;
     RECT  69.001 26.448 69.036 26.472 ;
     RECT  69.001 26.472 69.084 26.544 ;
     RECT  69.001 26.544 69.036 26.568 ;
     RECT  69.001 26.568 69.084 26.64 ;
     RECT  69.001 26.64 69.036 26.664 ;
     RECT  69.001 26.664 69.084 26.736 ;
     RECT  69.001 26.736 69.036 26.76 ;
     RECT  69.001 26.76 69.084 26.832 ;
     RECT  69.001 26.832 69.036 26.856 ;
     RECT  69.001 26.856 69.084 26.928 ;
     RECT  69.001 26.928 69.036 26.952 ;
     RECT  69.001 26.952 69.084 27.024 ;
     RECT  69.001 27.024 69.036 27.048 ;
     RECT  69.001 27.048 69.084 27.12 ;
     RECT  69.001 27.12 69.036 27.144 ;
     RECT  69.001 27.144 69.084 27.216 ;
     RECT  69.001 27.216 69.036 27.24 ;
     RECT  69.001 27.24 69.084 27.312 ;
     RECT  69.001 27.312 69.036 27.336 ;
     RECT  69.001 27.336 69.084 27.408 ;
     RECT  69.001 27.408 69.036 27.432 ;
     RECT  69.001 27.432 69.084 27.504 ;
     RECT  69.001 27.504 69.036 27.528 ;
     RECT  69.001 27.528 69.084 27.6 ;
     RECT  69.001 27.6 69.036 27.624 ;
     RECT  69.001 27.624 69.084 27.696 ;
     RECT  69.001 27.696 69.036 27.72 ;
     RECT  69.001 27.72 69.084 27.792 ;
     RECT  69.001 27.792 69.036 27.816 ;
     RECT  69.001 27.816 69.084 27.888 ;
     RECT  69.001 27.888 69.036 27.912 ;
     RECT  69.001 27.912 69.084 27.984 ;
     RECT  69.001 27.984 69.036 28.008 ;
     RECT  69.001 28.008 69.084 28.08 ;
     RECT  69.001 28.08 69.036 28.104 ;
     RECT  69.001 28.104 69.084 28.176 ;
     RECT  69.001 28.176 69.036 28.2 ;
     RECT  69.001 28.2 69.084 28.272 ;
     RECT  69.001 28.272 69.036 28.296 ;
     RECT  69.001 28.296 69.084 28.368 ;
     RECT  69.001 28.368 69.036 28.392 ;
     RECT  69.001 28.392 69.084 28.464 ;
     RECT  69.001 28.464 69.036 28.488 ;
     RECT  69.001 28.488 69.084 28.56 ;
     RECT  69.001 28.56 69.036 28.584 ;
     RECT  69.001 28.584 69.084 28.656 ;
     RECT  69.001 28.656 69.036 28.68 ;
     RECT  69.001 28.68 69.084 28.752 ;
     RECT  69.001 28.752 69.036 28.776 ;
     RECT  69.001 28.776 69.084 28.848 ;
     RECT  69.001 28.848 69.036 28.872 ;
     RECT  69.001 28.872 69.084 28.944 ;
     RECT  69.001 28.944 69.036 28.968 ;
     RECT  69.001 28.968 69.084 29.04 ;
     RECT  69.001 29.04 69.036 29.064 ;
     RECT  69.001 29.064 69.084 29.136 ;
     RECT  69.001 29.136 69.036 29.16 ;
     RECT  69.001 29.16 69.084 29.232 ;
     RECT  69.001 29.232 69.036 29.256 ;
     RECT  69.001 29.256 69.084 29.328 ;
     RECT  69.001 29.328 69.036 29.352 ;
     RECT  69.001 29.352 69.084 29.424 ;
     RECT  69.001 29.424 69.036 29.448 ;
     RECT  69.001 29.448 69.084 29.52 ;
     RECT  69.001 29.52 69.036 29.544 ;
     RECT  69.001 29.544 69.084 29.616 ;
     RECT  69.001 29.616 69.036 29.64 ;
     RECT  69.001 29.64 69.084 29.712 ;
     RECT  69.001 29.712 69.036 29.736 ;
     RECT  69.001 29.736 69.084 29.808 ;
     RECT  69.001 29.808 69.036 29.832 ;
     RECT  69.001 29.832 69.084 29.904 ;
     RECT  69.001 29.904 69.036 29.928 ;
     RECT  69.001 29.928 69.084 30 ;
     RECT  69.001 30 69.036 30.024 ;
     RECT  69.001 30.024 69.084 30.096 ;
     RECT  69.001 30.096 69.036 30.12 ;
     RECT  69.001 30.12 69.084 30.192 ;
     RECT  69.001 30.192 69.036 30.216 ;
     RECT  69.001 30.216 69.084 30.288 ;
     RECT  69.001 30.288 69.036 30.312 ;
     RECT  69.001 30.312 69.084 30.384 ;
     RECT  69.001 30.384 69.036 30.408 ;
     RECT  69.001 30.408 69.084 30.48 ;
     RECT  69.001 30.48 69.036 30.504 ;
     RECT  69.001 30.504 69.084 30.576 ;
     RECT  69.001 30.576 69.036 30.6 ;
     RECT  69.001 30.6 69.084 30.672 ;
     RECT  69.001 30.672 69.036 30.696 ;
     RECT  69.001 30.696 69.084 30.768 ;
     RECT  69.001 30.768 69.036 30.792 ;
     RECT  69.001 30.792 69.084 30.864 ;
     RECT  69.001 30.864 69.036 30.888 ;
     RECT  69.001 30.888 69.084 30.96 ;
     RECT  69.001 30.96 69.036 30.984 ;
     RECT  69.001 30.984 69.084 31.056 ;
     RECT  69.001 31.056 69.036 31.08 ;
     RECT  69.001 31.08 69.084 31.152 ;
     RECT  69.001 31.152 69.036 31.176 ;
     RECT  69.001 31.176 69.084 31.248 ;
     RECT  69.001 31.248 69.036 31.272 ;
     RECT  69.001 31.272 69.084 31.344 ;
     RECT  69.001 31.344 69.036 31.368 ;
     RECT  69.001 31.368 69.084 31.44 ;
     RECT  69.001 31.44 69.036 31.464 ;
     RECT  69.001 31.464 69.084 31.536 ;
     RECT  69.001 31.536 69.036 31.56 ;
     RECT  69.001 31.56 69.084 31.632 ;
     RECT  69.001 31.632 69.036 31.656 ;
     RECT  69.001 31.656 69.084 31.728 ;
     RECT  69.001 31.728 69.036 31.752 ;
     RECT  69.001 31.752 69.084 31.824 ;
     RECT  69.001 31.824 69.036 31.848 ;
     RECT  69.001 31.848 69.084 31.92 ;
     RECT  69.001 31.92 69.036 31.944 ;
     RECT  69.001 31.944 69.084 32.016 ;
     RECT  69.001 32.016 69.036 32.04 ;
     RECT  69.001 32.04 69.084 32.112 ;
     RECT  69.001 32.112 69.036 32.136 ;
     RECT  69.001 32.136 69.084 32.208 ;
     RECT  69.001 32.208 69.036 32.232 ;
     RECT  69.001 32.232 69.084 32.304 ;
     RECT  69.001 32.304 69.036 32.328 ;
     RECT  69.001 32.328 69.084 32.4 ;
     RECT  69.001 32.4 69.036 32.424 ;
     RECT  69.001 32.424 69.084 32.496 ;
     RECT  69.001 32.496 69.036 32.52 ;
     RECT  69.001 32.52 69.084 32.592 ;
     RECT  69.001 32.592 69.036 32.616 ;
     RECT  69.001 32.616 69.084 32.688 ;
     RECT  69.001 32.688 69.036 32.712 ;
     RECT  69.001 32.712 69.084 32.784 ;
     RECT  69.001 32.784 69.036 32.808 ;
     RECT  69.001 32.808 69.084 32.88 ;
     RECT  69.001 32.88 69.036 32.904 ;
     RECT  69.001 32.904 69.084 32.976 ;
     RECT  69.001 32.976 69.036 33 ;
     RECT  69.001 33 69.084 33.072 ;
     RECT  69.001 33.072 69.036 33.096 ;
     RECT  69.001 33.096 69.084 33.168 ;
     RECT  69.001 33.168 69.036 33.192 ;
     RECT  69.001 33.192 69.084 33.264 ;
     RECT  69.001 33.264 69.036 33.288 ;
     RECT  69.001 33.288 69.084 33.36 ;
     RECT  69.001 33.36 69.036 33.384 ;
     RECT  69.001 33.384 69.084 33.456 ;
     RECT  69.001 33.456 69.036 33.48 ;
     RECT  69.001 33.48 69.084 33.552 ;
     RECT  69.001 33.552 69.036 33.576 ;
     RECT  69.001 33.576 69.084 33.648 ;
     RECT  69.001 33.648 69.036 33.672 ;
     RECT  69.001 33.672 69.084 33.744 ;
     RECT  69.001 33.744 69.036 33.768 ;
     RECT  69.001 33.768 69.084 33.84 ;
     RECT  69.001 33.84 69.036 33.864 ;
     RECT  69.001 33.864 69.084 33.936 ;
     RECT  69.001 33.936 69.036 33.96 ;
     RECT  69.001 33.96 69.084 34.032 ;
     RECT  69.001 34.032 69.036 34.056 ;
     RECT  69.001 34.056 69.084 34.128 ;
     RECT  69.001 34.128 69.036 34.152 ;
     RECT  69.001 34.152 69.084 34.224 ;
     RECT  69.001 34.224 69.036 34.248 ;
     RECT  69.001 34.248 69.084 34.32 ;
     RECT  69.001 34.32 69.036 34.344 ;
     RECT  69.001 34.344 69.084 34.416 ;
     RECT  69.001 34.416 69.036 34.44 ;
     RECT  69.001 34.44 69.084 34.512 ;
     RECT  69.001 34.512 69.036 34.536 ;
     RECT  69.001 34.536 69.084 34.608 ;
     RECT  69.001 34.608 69.036 34.632 ;
     RECT  69.001 34.632 69.084 34.704 ;
     RECT  69.001 34.704 69.036 34.728 ;
     RECT  69.001 34.728 69.084 34.8 ;
     RECT  69.001 34.8 69.036 34.824 ;
     RECT  69.001 34.824 69.084 34.896 ;
     RECT  69.001 34.896 69.036 34.92 ;
     RECT  69.001 34.92 69.084 34.992 ;
     RECT  69.001 34.992 69.036 35.016 ;
     RECT  69.001 35.016 69.084 35.088 ;
     RECT  69.001 35.088 69.036 35.112 ;
     RECT  69.001 35.112 69.084 35.184 ;
     RECT  69.001 35.184 69.036 35.208 ;
     RECT  69.001 35.208 69.084 35.28 ;
     RECT  69.001 35.28 69.036 35.304 ;
     RECT  69.001 35.304 69.084 35.376 ;
     RECT  69.001 35.376 69.036 35.4 ;
     RECT  69.001 35.4 69.084 35.472 ;
     RECT  69.001 35.472 69.036 35.496 ;
     RECT  69.001 35.496 69.084 35.568 ;
     RECT  69.001 35.568 69.036 35.592 ;
     RECT  69.001 35.592 69.084 35.664 ;
     RECT  69.001 35.664 69.036 35.688 ;
     RECT  69.001 35.688 69.084 35.76 ;
     RECT  69.001 35.76 69.036 35.784 ;
     RECT  69.001 35.784 69.084 35.856 ;
     RECT  69.001 35.856 69.036 35.88 ;
     RECT  69.001 35.88 69.084 35.952 ;
     RECT  69.001 35.952 69.036 35.976 ;
     RECT  69.001 35.976 69.084 36.048 ;
     RECT  69.001 36.048 69.036 36.072 ;
     RECT  69.001 36.072 69.084 36.144 ;
     RECT  69.001 36.144 69.036 36.168 ;
     RECT  69.001 36.168 69.084 36.24 ;
     RECT  69.001 36.24 69.036 36.264 ;
     RECT  69.001 36.264 69.084 36.336 ;
     RECT  69.001 36.336 69.036 36.36 ;
     RECT  69.001 36.36 69.084 36.432 ;
     RECT  69.001 36.432 69.036 36.456 ;
     RECT  69.001 36.456 69.084 36.528 ;
     RECT  69.001 36.528 69.036 36.552 ;
     RECT  69.001 36.552 69.084 36.624 ;
     RECT  69.001 36.624 69.036 36.648 ;
     RECT  69.001 36.648 69.084 36.72 ;
     RECT  69.001 36.72 69.036 36.744 ;
     RECT  69.001 36.744 69.084 36.816 ;
     RECT  69.001 36.816 69.036 36.84 ;
     RECT  69.001 36.84 69.084 36.912 ;
     RECT  69.001 36.912 69.036 36.936 ;
     RECT  69.001 36.936 69.084 37.008 ;
     RECT  69.001 37.008 69.036 37.032 ;
     RECT  69.001 37.032 69.084 37.104 ;
     RECT  69.001 37.104 69.036 37.128 ;
     RECT  69.001 37.128 69.084 37.2 ;
     RECT  69.001 37.2 69.036 37.224 ;
     RECT  69.001 37.224 69.084 37.296 ;
     RECT  69.001 37.296 69.036 37.32 ;
     RECT  69.001 37.32 69.084 37.392 ;
     RECT  69.001 37.392 69.036 37.416 ;
     RECT  69.001 37.416 69.084 37.488 ;
     RECT  69.001 37.488 69.036 37.512 ;
     RECT  69.001 37.512 69.084 37.584 ;
     RECT  69.001 37.584 69.036 37.608 ;
     RECT  69.001 37.608 69.084 37.68 ;
     RECT  69.001 37.68 69.036 37.704 ;
     RECT  69.001 37.704 69.084 37.776 ;
     RECT  69.001 37.776 69.036 37.8 ;
     RECT  69.001 37.8 69.084 37.872 ;
     RECT  69.001 37.872 69.036 37.896 ;
     RECT  69.001 37.896 69.084 37.968 ;
     RECT  69.001 37.968 69.036 37.992 ;
     RECT  69.001 37.992 69.084 38.064 ;
     RECT  69.001 38.064 69.036 38.088 ;
     RECT  69.001 38.088 69.084 38.16 ;
     RECT  69.001 38.16 69.036 38.184 ;
     RECT  69.001 38.184 69.084 38.256 ;
     RECT  69.001 38.256 69.036 38.28 ;
     RECT  69.001 38.28 69.084 39.12 ;
     RECT  69.001 39.12 69.036 39.144 ;
     RECT  69.001 39.144 69.084 39.216 ;
     RECT  69.001 39.216 69.036 39.24 ;
     RECT  69.001 39.24 69.084 39.312 ;
     RECT  69.001 39.312 69.036 39.336 ;
     RECT  69.001 39.336 69.084 39.408 ;
     RECT  69.001 39.408 69.036 39.432 ;
     RECT  69.001 39.432 69.084 39.504 ;
     RECT  69.001 39.504 69.036 39.528 ;
     RECT  69.001 39.528 69.084 39.6 ;
     RECT  69.001 39.6 69.036 39.624 ;
     RECT  69.001 39.624 69.084 39.696 ;
     RECT  69.001 39.696 69.036 39.72 ;
     RECT  69.001 39.72 69.084 39.792 ;
     RECT  69.001 39.792 69.036 39.816 ;
     RECT  69.001 39.816 69.084 39.888 ;
     RECT  69.001 39.888 69.036 39.912 ;
     RECT  69.001 39.912 69.084 39.984 ;
     RECT  69.001 39.984 69.036 40.008 ;
     RECT  69.001 40.008 69.084 40.08 ;
     RECT  69.001 40.08 69.036 40.104 ;
     RECT  69.001 40.104 69.084 40.176 ;
     RECT  69.001 40.176 69.036 40.2 ;
     RECT  69.001 40.2 69.084 40.272 ;
     RECT  69.001 40.272 69.036 40.296 ;
     RECT  69.001 40.296 69.084 40.368 ;
     RECT  69.001 40.368 69.036 40.392 ;
     RECT  69.001 40.392 69.084 40.464 ;
     RECT  69.001 40.464 69.036 40.488 ;
     RECT  69.001 40.488 69.084 40.56 ;
     RECT  69.001 40.56 69.036 40.584 ;
     RECT  69.001 40.584 69.084 40.656 ;
     RECT  69.001 40.656 69.036 40.68 ;
     RECT  69.001 40.68 69.084 40.752 ;
     RECT  69.001 40.752 69.036 40.776 ;
     RECT  69.001 40.776 69.084 40.848 ;
     RECT  69.001 40.848 69.036 40.872 ;
     RECT  69.001 40.872 69.084 40.944 ;
     RECT  69.001 40.944 69.036 40.968 ;
     RECT  69.001 40.968 69.084 41.04 ;
     RECT  69.001 41.04 69.036 41.064 ;
     RECT  69.001 41.064 69.084 41.136 ;
     RECT  69.001 41.136 69.036 41.16 ;
     RECT  69.001 41.16 69.084 41.232 ;
     RECT  69.001 41.232 69.036 41.256 ;
     RECT  69.001 41.256 69.084 41.328 ;
     RECT  69.001 41.328 69.036 41.352 ;
     RECT  69.001 41.352 69.084 41.424 ;
     RECT  69.001 41.424 69.036 41.448 ;
     RECT  69.001 41.448 69.084 41.52 ;
     RECT  69.001 41.52 69.036 41.544 ;
     RECT  69.001 41.544 69.084 41.616 ;
     RECT  69.001 41.616 69.036 41.64 ;
     RECT  69.001 41.64 69.084 41.712 ;
     RECT  69.001 41.712 69.036 41.736 ;
     RECT  69.001 41.736 69.084 41.808 ;
     RECT  69.001 41.808 69.036 41.832 ;
     RECT  69.001 41.832 69.084 41.904 ;
     RECT  69.001 41.904 69.036 41.928 ;
     RECT  69.001 41.928 69.084 42 ;
     RECT  69.001 42 69.036 42.024 ;
     RECT  69.001 42.024 69.084 42.096 ;
     RECT  69.001 42.096 69.036 42.12 ;
     RECT  69.001 42.12 69.084 42.192 ;
     RECT  69.001 42.192 69.036 42.216 ;
     RECT  69.001 42.216 69.084 42.288 ;
     RECT  69.001 42.288 69.036 42.312 ;
     RECT  69.001 42.312 69.084 42.384 ;
     RECT  69.001 42.384 69.036 42.408 ;
     RECT  69.001 42.408 69.084 42.48 ;
     RECT  69.001 42.48 69.036 42.504 ;
     RECT  69.001 42.504 69.084 42.576 ;
     RECT  69.001 42.576 69.036 42.6 ;
     RECT  69.001 42.6 69.084 42.672 ;
     RECT  69.001 42.672 69.036 42.696 ;
     RECT  69.001 42.696 69.084 42.768 ;
     RECT  69.001 42.768 69.036 42.792 ;
     RECT  69.001 42.792 69.084 42.864 ;
     RECT  69.001 42.864 69.036 42.888 ;
     RECT  69.001 42.888 69.084 42.96 ;
     RECT  69.001 42.96 69.036 42.984 ;
     RECT  69.001 42.984 69.084 43.056 ;
     RECT  69.001 43.056 69.036 43.08 ;
     RECT  69.001 43.08 69.084 43.152 ;
     RECT  69.001 43.152 69.036 43.176 ;
     RECT  69.001 43.176 69.084 43.248 ;
     RECT  69.001 43.248 69.036 43.272 ;
     RECT  69.001 43.272 69.084 43.344 ;
     RECT  69.001 43.344 69.036 43.368 ;
     RECT  69.001 43.368 69.084 43.44 ;
     RECT  69.001 43.44 69.036 43.464 ;
     RECT  69.001 43.464 69.084 43.536 ;
     RECT  69.001 43.536 69.036 43.56 ;
     RECT  69.001 43.56 69.084 43.632 ;
     RECT  69.001 43.632 69.036 43.656 ;
     RECT  69.001 43.656 69.084 43.728 ;
     RECT  69.001 43.728 69.036 43.752 ;
     RECT  69.001 43.752 69.084 43.824 ;
     RECT  69.001 43.824 69.036 43.848 ;
     RECT  69.001 43.848 69.084 43.92 ;
     RECT  69.001 43.92 69.036 43.944 ;
     RECT  69.001 43.944 69.084 44.016 ;
     RECT  69.001 44.016 69.036 44.04 ;
     RECT  69.001 44.04 69.084 44.112 ;
     RECT  69.001 44.112 69.036 44.136 ;
     RECT  69.001 44.136 69.084 44.208 ;
     RECT  69.001 44.208 69.036 44.232 ;
     RECT  69.001 44.232 69.084 44.304 ;
     RECT  69.001 44.304 69.036 44.328 ;
     RECT  69.001 44.328 69.084 44.4 ;
     RECT  69.001 44.4 69.036 44.424 ;
     RECT  69.001 44.424 69.084 44.496 ;
     RECT  69.001 44.496 69.036 44.52 ;
     RECT  69.001 44.52 69.084 44.592 ;
     RECT  69.001 44.592 69.036 44.616 ;
     RECT  69.001 44.616 69.084 44.688 ;
     RECT  69.001 44.688 69.036 44.712 ;
     RECT  69.001 44.712 69.084 44.784 ;
     RECT  69.001 44.784 69.036 44.808 ;
     RECT  69.001 44.808 69.084 44.88 ;
     RECT  69.001 44.88 69.036 44.904 ;
     RECT  69.001 44.904 69.084 44.976 ;
     RECT  69.001 44.976 69.036 45 ;
     RECT  69.001 45 69.084 45.072 ;
     RECT  69.001 45.072 69.036 45.096 ;
     RECT  69.001 45.096 69.084 45.168 ;
     RECT  69.001 45.168 69.036 45.192 ;
     RECT  69.001 45.192 69.084 45.264 ;
     RECT  69.001 45.264 69.036 45.288 ;
     RECT  69.001 45.288 69.084 45.36 ;
     RECT  69.001 45.36 69.036 45.384 ;
     RECT  69.001 45.384 69.084 45.456 ;
     RECT  69.001 45.456 69.036 45.48 ;
     RECT  69.001 45.48 69.084 45.552 ;
     RECT  69.001 45.552 69.036 45.576 ;
     RECT  69.001 45.576 69.084 45.648 ;
     RECT  69.001 45.648 69.036 45.672 ;
     RECT  69.001 45.672 69.084 45.744 ;
     RECT  69.001 45.744 69.036 45.768 ;
     RECT  69.001 45.768 69.084 45.84 ;
     RECT  69.001 45.84 69.036 45.864 ;
     RECT  69.001 45.864 69.084 45.936 ;
     RECT  69.001 45.936 69.036 45.96 ;
     RECT  69.001 45.96 69.084 46.032 ;
     RECT  69.001 46.032 69.036 46.056 ;
     RECT  69.001 46.056 69.084 46.128 ;
     RECT  69.001 46.128 69.036 46.152 ;
     RECT  69.001 46.152 69.084 46.224 ;
     RECT  69.001 46.224 69.036 46.248 ;
     RECT  69.001 46.248 69.084 46.32 ;
     RECT  69.001 46.32 69.036 46.344 ;
     RECT  69.001 46.344 69.084 46.416 ;
     RECT  69.001 46.416 69.036 46.44 ;
     RECT  69.001 46.44 69.084 46.512 ;
     RECT  69.001 46.512 69.036 46.536 ;
     RECT  69.001 46.536 69.084 46.608 ;
     RECT  69.001 46.608 69.036 46.632 ;
     RECT  69.001 46.632 69.084 46.704 ;
     RECT  69.001 46.704 69.036 46.728 ;
     RECT  69.001 46.728 69.084 46.8 ;
     RECT  69.001 46.8 69.036 46.824 ;
     RECT  69.001 46.824 69.084 46.896 ;
     RECT  69.001 46.896 69.036 46.92 ;
     RECT  69.001 46.92 69.084 46.992 ;
     RECT  69.001 46.992 69.036 47.016 ;
     RECT  69.001 47.016 69.084 47.088 ;
     RECT  69.001 47.088 69.036 47.112 ;
     RECT  69.001 47.112 69.084 47.184 ;
     RECT  69.001 47.184 69.036 47.208 ;
     RECT  69.001 47.208 69.084 47.28 ;
     RECT  69.001 47.28 69.036 47.304 ;
     RECT  69.001 47.304 69.084 47.376 ;
     RECT  69.001 47.376 69.036 47.4 ;
     RECT  69.001 47.4 69.084 47.472 ;
     RECT  69.001 47.472 69.036 47.496 ;
     RECT  69.001 47.496 69.084 47.568 ;
     RECT  69.001 47.568 69.036 47.592 ;
     RECT  69.001 47.592 69.084 47.664 ;
     RECT  69.001 47.664 69.036 47.688 ;
     RECT  69.001 47.688 69.084 47.76 ;
     RECT  69.001 47.76 69.036 47.784 ;
     RECT  69.001 47.784 69.084 47.856 ;
     RECT  69.001 47.856 69.036 47.88 ;
     RECT  69.001 47.88 69.084 47.952 ;
     RECT  69.001 47.952 69.036 47.976 ;
     RECT  69.001 47.976 69.084 48.048 ;
     RECT  69.001 48.048 69.036 48.072 ;
     RECT  69.001 48.072 69.084 48.144 ;
     RECT  69.001 48.144 69.036 48.168 ;
     RECT  69.001 48.168 69.084 48.24 ;
     RECT  69.001 48.24 69.036 48.264 ;
     RECT  69.001 48.264 69.084 48.336 ;
     RECT  69.001 48.336 69.036 48.36 ;
     RECT  69.001 48.36 69.084 48.432 ;
     RECT  69.001 48.432 69.036 48.456 ;
     RECT  69.001 48.456 69.084 48.528 ;
     RECT  69.001 48.528 69.036 48.552 ;
     RECT  69.001 48.552 69.084 48.624 ;
     RECT  69.001 48.624 69.036 48.648 ;
     RECT  69.001 48.648 69.084 48.72 ;
     RECT  69.001 48.72 69.036 48.744 ;
     RECT  69.001 48.744 69.084 48.816 ;
     RECT  69.001 48.816 69.036 48.84 ;
     RECT  69.001 48.84 69.084 48.912 ;
     RECT  69.001 48.912 69.036 48.936 ;
     RECT  69.001 48.936 69.084 49.008 ;
     RECT  69.001 49.008 69.036 49.032 ;
     RECT  69.001 49.032 69.084 49.104 ;
     RECT  69.001 49.104 69.036 49.128 ;
     RECT  69.001 49.128 69.084 49.2 ;
     RECT  69.001 49.2 69.036 49.224 ;
     RECT  69.001 49.224 69.084 49.296 ;
     RECT  69.001 49.296 69.036 49.32 ;
     RECT  69.001 49.32 69.084 49.392 ;
     RECT  69.001 49.392 69.036 49.416 ;
     RECT  69.001 49.416 69.084 49.488 ;
     RECT  69.001 49.488 69.036 49.512 ;
     RECT  69.001 49.512 69.084 49.584 ;
     RECT  69.001 49.584 69.036 49.608 ;
     RECT  69.001 49.608 69.084 49.68 ;
     RECT  69.001 49.68 69.036 49.704 ;
     RECT  69.001 49.704 69.084 49.776 ;
     RECT  69.001 49.776 69.036 49.8 ;
     RECT  69.001 49.8 69.084 49.872 ;
     RECT  69.001 49.872 69.036 49.896 ;
     RECT  69.001 49.896 69.084 49.968 ;
     RECT  69.001 49.968 69.036 49.992 ;
     RECT  69.001 49.992 69.084 50.064 ;
     RECT  69.001 50.064 69.036 50.088 ;
     RECT  69.001 50.088 69.084 50.16 ;
     RECT  69.001 50.16 69.036 50.184 ;
     RECT  69.001 50.184 69.084 50.256 ;
     RECT  69.001 50.256 69.036 50.28 ;
     RECT  69.001 50.28 69.084 50.352 ;
     RECT  69.001 50.352 69.036 50.376 ;
     RECT  69.001 50.376 69.084 50.448 ;
     RECT  69.001 50.448 69.036 50.472 ;
     RECT  69.001 50.472 69.084 50.544 ;
     RECT  69.001 50.544 69.036 50.568 ;
     RECT  69.001 50.568 69.084 50.64 ;
     RECT  69.001 50.64 69.036 50.664 ;
     RECT  69.001 50.664 69.084 50.736 ;
     RECT  69.001 50.736 69.036 50.76 ;
     RECT  69.001 50.76 69.084 50.832 ;
     RECT  69.001 50.832 69.036 50.856 ;
     RECT  69.001 50.856 69.084 50.928 ;
     RECT  69.001 50.928 69.036 50.952 ;
     RECT  69.001 50.952 69.084 51.024 ;
     RECT  69.001 51.024 69.036 51.048 ;
     RECT  69.001 51.048 69.084 51.12 ;
     RECT  69.001 51.12 69.036 51.144 ;
     RECT  69.001 51.144 69.084 51.216 ;
     RECT  69.001 51.216 69.036 51.24 ;
     RECT  69.001 51.24 69.084 51.312 ;
     RECT  69.001 51.312 69.036 51.336 ;
    LAYER M5 ;
     RECT  32.232 0.016 32.304 0.084 ;
     RECT  32.328 0.016 32.4 0.084 ;
     RECT  32.424 0.016 32.496 0.084 ;
     RECT  32.52 0.016 32.592 0.084 ;
     RECT  32.616 0.016 32.688 0.084 ;
     RECT  32.712 0.016 32.784 0.084 ;
     RECT  32.808 0.016 32.88 0.084 ;
     RECT  32.904 0.016 32.976 0.084 ;
     RECT  33 0.016 33.072 0.084 ;
     RECT  33.096 0.016 33.168 0.084 ;
     RECT  33.192 0.016 33.264 0.084 ;
     RECT  33.288 0.016 33.36 0.084 ;
     RECT  33.384 0.016 33.456 0.084 ;
     RECT  33.48 0.016 33.552 0.084 ;
     RECT  33.576 0.016 33.648 0.084 ;
     RECT  33.672 0.016 33.744 0.084 ;
     RECT  33.768 0.016 33.84 0.084 ;
     RECT  33.864 0.016 33.936 0.084 ;
     RECT  33.96 0.016 34.032 0.084 ;
     RECT  34.056 0.016 34.128 0.084 ;
     RECT  34.152 0.016 34.224 0.084 ;
     RECT  34.248 0.016 34.32 0.084 ;
     RECT  34.344 0.016 34.416 0.084 ;
     RECT  34.44 0.016 34.512 0.084 ;
     RECT  34.536 0.016 34.608 0.084 ;
     RECT  34.632 0.016 34.704 0.084 ;
     RECT  34.728 0.016 34.8 0.084 ;
     RECT  34.824 0.016 35.28 0.084 ;
     RECT  35.304 0.016 35.376 0.084 ;
     RECT  35.4 0.016 35.472 0.084 ;
     RECT  35.496 0.016 35.568 0.084 ;
     RECT  35.592 0.016 35.664 0.084 ;
     RECT  35.688 0.016 35.76 0.084 ;
     RECT  35.784 0.016 35.856 0.084 ;
     RECT  35.88 0.016 35.952 0.084 ;
     RECT  35.976 0.016 36.048 0.084 ;
     RECT  36.072 0.016 36.144 0.084 ;
     RECT  36.168 0.016 36.24 0.084 ;
     RECT  36.264 0.016 36.336 0.084 ;
     RECT  36.36 0.016 36.432 0.084 ;
     RECT  36.456 0.016 36.528 0.084 ;
     RECT  36.552 0.016 36.624 0.084 ;
     RECT  36.648 0.016 36.72 0.084 ;
     RECT  36.744 0.016 36.816 0.084 ;
     RECT  36.84 0.016 36.912 0.084 ;
     RECT  36.936 0.016 37.008 0.084 ;
     RECT  37.032 0.016 37.104 0.084 ;
     RECT  37.128 0.016 37.2 0.084 ;
     RECT  37.224 0.016 37.296 0.084 ;
     RECT  37.32 0.016 37.392 0.084 ;
     RECT  37.416 0.016 37.488 0.084 ;
     RECT  37.512 0.016 37.584 0.084 ;
     RECT  37.608 0.016 37.68 0.084 ;
     RECT  37.704 0.016 37.776 0.084 ;
     RECT  37.8 0.016 37.872 0.084 ;
     RECT  37.896 0.016 37.968 0.084 ;
     RECT  37.992 0.016 38.064 0.084 ;
     RECT  38.088 0.016 38.16 0.084 ;
     RECT  38.184 0.016 38.256 0.084 ;
     RECT  38.28 0.016 39.12 0.084 ;
     RECT  39.144 0.016 39.216 0.084 ;
     RECT  39.24 0.016 39.312 0.084 ;
     RECT  39.336 0.016 39.408 0.084 ;
     RECT  39.432 0.016 39.504 0.084 ;
     RECT  39.528 0.016 39.6 0.084 ;
     RECT  39.624 0.016 39.696 0.084 ;
     RECT  39.72 0.016 39.792 0.084 ;
     RECT  39.816 0.016 39.888 0.084 ;
     RECT  39.912 0.016 39.984 0.084 ;
     RECT  40.008 0.016 40.08 0.084 ;
     RECT  40.104 0.016 40.176 0.084 ;
     RECT  40.2 0.016 40.272 0.084 ;
     RECT  40.296 0.016 40.368 0.084 ;
     RECT  40.392 0.016 40.464 0.084 ;
     RECT  40.488 0.016 40.56 0.084 ;
     RECT  40.584 0.016 40.656 0.084 ;
     RECT  40.68 0.016 40.752 0.084 ;
     RECT  40.776 0.016 40.848 0.084 ;
     RECT  40.872 0.016 40.944 0.084 ;
     RECT  40.968 0.016 41.04 0.084 ;
     RECT  41.064 0.016 41.136 0.084 ;
     RECT  41.16 0.016 41.232 0.084 ;
     RECT  41.256 0.016 41.328 0.084 ;
     RECT  41.352 0.016 41.424 0.084 ;
     RECT  41.448 0.016 41.52 0.084 ;
     RECT  41.544 0.016 41.616 0.084 ;
     RECT  41.64 0.016 41.712 0.084 ;
     RECT  41.736 0.016 41.808 0.084 ;
     RECT  41.832 0.016 41.904 0.084 ;
     RECT  41.928 0.016 42 0.084 ;
     RECT  42.024 0.016 42.096 0.084 ;
     RECT  42.12 0.016 42.192 0.084 ;
     RECT  42.216 0.016 42.288 0.084 ;
     RECT  42.312 0.016 42.384 0.084 ;
     RECT  42.408 0.016 42.48 0.084 ;
     RECT  42.504 0.016 42.576 0.084 ;
     RECT  42.6 0.016 42.672 0.084 ;
     RECT  42.696 0.016 42.768 0.084 ;
     RECT  42.792 0.016 42.864 0.084 ;
     RECT  42.888 0.016 42.96 0.084 ;
     RECT  42.984 0.016 43.056 0.084 ;
     RECT  43.08 0.016 43.152 0.084 ;
     RECT  43.176 0.016 43.248 0.084 ;
     RECT  43.272 0.016 43.344 0.084 ;
     RECT  43.368 0.016 43.44 0.084 ;
     RECT  43.464 0.016 43.536 0.084 ;
     RECT  43.56 0.016 43.632 0.084 ;
     RECT  43.656 0.016 43.728 0.084 ;
     RECT  43.752 0.016 43.824 0.084 ;
     RECT  43.848 0.016 43.92 0.084 ;
     RECT  43.944 0.016 44.016 0.084 ;
     RECT  44.04 0.016 44.112 0.084 ;
     RECT  44.136 0.016 44.208 0.084 ;
     RECT  44.232 0.016 44.304 0.084 ;
     RECT  44.328 0.016 44.4 0.084 ;
     RECT  44.424 0.016 44.496 0.084 ;
     RECT  44.52 0.016 44.592 0.084 ;
     RECT  44.616 0.016 44.688 0.084 ;
     RECT  44.712 0.016 44.784 0.084 ;
     RECT  44.808 0.016 44.88 0.084 ;
     RECT  44.904 0.016 44.976 0.084 ;
     RECT  45 0.016 45.072 0.084 ;
     RECT  45.096 0.016 45.168 0.084 ;
     RECT  32.208 0.084 45.192 1.139 ;
     RECT  32.4 1.139 45.192 2.053 ;
     RECT  2.4 2.137 2.52 2.151 ;
     RECT  7.8 2.137 7.92 2.151 ;
     RECT  13.2 2.137 13.32 2.151 ;
     RECT  18.6 2.137 18.72 2.151 ;
     RECT  24 2.137 24.12 2.151 ;
     RECT  29.4 2.137 29.52 2.151 ;
     RECT  51 2.137 51.12 2.151 ;
     RECT  56.4 2.137 56.52 2.151 ;
     RECT  61.8 2.137 61.92 2.151 ;
     RECT  32.4 2.053 46.008 2.291 ;
     RECT  33.456 2.291 46.008 2.435 ;
     RECT  33.456 2.435 45.912 2.723 ;
     RECT  33.552 2.723 45.912 2.963 ;
     RECT  33.936 2.963 45.912 5.411 ;
     RECT  44.16 5.411 45.912 5.555 ;
     RECT  33.936 5.411 42.984 5.603 ;
     RECT  33.936 5.603 42.792 6.611 ;
     RECT  33.936 6.611 42.408 6.899 ;
     RECT  34.416 6.899 42.408 6.947 ;
     RECT  39.36 6.947 42.408 7.091 ;
     RECT  39.36 7.091 41.736 7.187 ;
     RECT  36.336 6.947 38.376 7.235 ;
     RECT  39.36 7.187 40.512 7.283 ;
     RECT  34.416 6.947 35.112 7.379 ;
     RECT  39.984 7.283 40.512 7.475 ;
     RECT  41.712 7.187 41.736 7.475 ;
     RECT  36.336 7.235 37.608 7.523 ;
     RECT  40.08 7.475 40.512 7.523 ;
     RECT  36.336 7.523 36.744 7.715 ;
     RECT  36.336 7.715 36.36 8.003 ;
     RECT  29.4 2.151 29.712 14.197 ;
     RECT  32.208 5.605 32.232 14.243 ;
     RECT  34.8 7.379 35.112 19.525 ;
     RECT  7.8 2.151 8.112 19.621 ;
     RECT  22.032 6.805 22.056 19.811 ;
     RECT  44.16 5.555 44.184 19.811 ;
     RECT  34.704 19.525 35.112 19.861 ;
     RECT  61.8 2.151 62.112 20.437 ;
     RECT  6.816 19.621 8.112 21.155 ;
     RECT  60.96 20.437 62.112 21.155 ;
     RECT  61.8 21.155 62.112 22.741 ;
     RECT  49.248 19.669 49.272 22.883 ;
     RECT  4.8 19.861 4.824 22.933 ;
     RECT  4.608 22.933 4.824 22.979 ;
     RECT  61.8 22.741 63.096 23.171 ;
     RECT  61.8 23.171 62.76 25.861 ;
     RECT  61.8 25.861 63.048 26.725 ;
     RECT  2.4 2.151 2.712 27.349 ;
     RECT  2.304 27.349 2.712 27.539 ;
     RECT  61.8 26.725 63.768 27.923 ;
     RECT  63.6 27.923 63.768 28.115 ;
     RECT  6.672 27.301 6.696 28.261 ;
     RECT  6.336 28.261 6.696 28.451 ;
     RECT  0.144 28.213 0.168 28.499 ;
     RECT  6.672 28.451 6.696 28.547 ;
     RECT  66.672 30.757 66.696 30.899 ;
     RECT  68.928 30.757 68.952 30.947 ;
     RECT  63.6 28.115 63.624 31.379 ;
     RECT  7.8 21.155 8.112 31.765 ;
     RECT  7.392 31.765 8.112 31.955 ;
     RECT  4.608 22.979 4.632 32.483 ;
     RECT  59.904 32.437 59.928 33.107 ;
     RECT  63.552 31.861 63.576 33.683 ;
     RECT  0.192 34.165 0.216 35.315 ;
     RECT  7.8 31.955 8.112 35.845 ;
     RECT  3.936 35.317 3.96 35.891 ;
     RECT  2.4 27.539 2.712 36.277 ;
     RECT  2.4 36.277 2.808 36.419 ;
     RECT  40.2 7.523 40.512 36.469 ;
     RECT  2.4 36.419 2.712 37.429 ;
     RECT  61.8 27.923 62.112 37.429 ;
     RECT  2.304 37.429 2.712 37.667 ;
     RECT  59.904 35.845 59.928 38.675 ;
     RECT  7.68 35.845 8.112 39.973 ;
     RECT  61.8 37.429 62.232 40.067 ;
     RECT  61.8 40.067 62.112 40.165 ;
     RECT  5.808 39.109 5.832 40.211 ;
     RECT  45.6 5.555 45.912 41.557 ;
     RECT  2.4 37.667 2.712 41.749 ;
     RECT  2.304 41.749 2.712 41.939 ;
     RECT  7.536 39.973 8.112 43.813 ;
     RECT  0.192 43.861 0.216 44.099 ;
     RECT  7.008 43.813 8.112 44.627 ;
     RECT  2.4 41.939 2.712 44.773 ;
     RECT  2.304 44.773 2.712 44.963 ;
     RECT  64.992 43.861 65.016 44.963 ;
     RECT  7.536 44.627 8.112 44.965 ;
     RECT  2.4 44.963 2.712 45.157 ;
     RECT  2.4 45.157 2.856 45.347 ;
     RECT  7.536 44.965 8.232 45.635 ;
     RECT  7.536 45.635 8.112 46.789 ;
     RECT  7.536 46.789 8.328 46.835 ;
     RECT  59.952 47.749 59.976 49.091 ;
     RECT  0.144 48.997 0.168 49.187 ;
     RECT  61.536 40.165 62.112 49.571 ;
     RECT  7.8 46.835 8.328 50.579 ;
     RECT  34.56 19.861 35.112 50.581 ;
     RECT  34.224 50.581 35.112 50.819 ;
     RECT  45.264 41.557 45.912 62.197 ;
     RECT  21.264 50.965 21.288 62.293 ;
     RECT  24 2.151 24.312 62.581 ;
     RECT  40.2 36.469 41.064 62.581 ;
     RECT  45.264 62.197 46.056 62.725 ;
     RECT  48.528 50.101 48.552 62.725 ;
     RECT  48.432 62.725 48.552 62.771 ;
     RECT  29.4 14.197 30.696 62.821 ;
     RECT  39.456 62.581 41.064 62.821 ;
     RECT  45.072 62.725 46.056 62.821 ;
     RECT  48.432 62.771 48.456 62.915 ;
     RECT  29.28 62.821 30.696 62.965 ;
     RECT  24 62.581 24.408 63.013 ;
     RECT  29.04 62.965 30.696 63.061 ;
     RECT  34.8 50.819 35.112 63.061 ;
     RECT  24 63.013 25.416 63.109 ;
     RECT  38.544 62.821 41.064 63.109 ;
     RECT  43.392 62.821 43.752 63.109 ;
     RECT  47.136 62.629 47.16 63.109 ;
     RECT  27.168 63.061 30.696 63.157 ;
     RECT  36.432 63.061 36.456 63.157 ;
     RECT  37.584 63.109 41.064 63.157 ;
     RECT  42.048 63.109 43.752 63.157 ;
     RECT  24 63.109 25.464 63.205 ;
     RECT  27.168 63.157 31.32 63.205 ;
     RECT  32.88 62.725 32.904 63.205 ;
     RECT  34.608 63.061 35.256 63.205 ;
     RECT  36.384 63.157 36.456 63.205 ;
     RECT  37.584 63.157 43.752 63.205 ;
     RECT  44.784 62.821 46.056 63.205 ;
     RECT  47.136 63.109 47.592 63.205 ;
     RECT  22.8 35.173 22.824 63.253 ;
     RECT  23.904 63.205 25.944 63.253 ;
     RECT  27.12 63.205 32.904 63.253 ;
     RECT  51 2.151 51.312 63.781 ;
     RECT  22.8 63.253 32.904 63.829 ;
     RECT  20.496 62.293 21.288 64.021 ;
     RECT  20.496 64.021 21.768 64.067 ;
     RECT  18.6 2.151 18.912 64.357 ;
     RECT  22.8 63.829 33.288 64.357 ;
     RECT  50.016 63.781 51.312 64.595 ;
     RECT  21.744 64.067 21.768 65.603 ;
     RECT  18.6 64.357 19.176 66.709 ;
     RECT  20.496 64.067 20.52 66.709 ;
     RECT  22.8 64.357 33.384 66.709 ;
     RECT  34.608 63.205 47.592 66.709 ;
     RECT  17.904 66.709 19.176 66.757 ;
     RECT  20.304 66.709 48.648 66.757 ;
     RECT  17.904 66.757 48.936 66.901 ;
     RECT  2.4 45.347 2.712 66.969 ;
     RECT  7.8 50.579 8.112 66.969 ;
     RECT  13.2 2.151 13.512 66.969 ;
     RECT  51 64.595 51.312 66.969 ;
     RECT  56.4 2.151 56.712 66.969 ;
     RECT  61.8 49.571 62.112 66.969 ;
     RECT  2.4 66.969 2.52 66.983 ;
     RECT  7.8 66.969 7.92 66.983 ;
     RECT  13.2 66.969 13.32 66.983 ;
     RECT  51 66.969 51.12 66.983 ;
     RECT  56.4 66.969 56.52 66.983 ;
     RECT  61.8 66.969 61.92 66.983 ;
     RECT  17.712 66.901 48.936 67.141 ;
     RECT  17.712 67.141 49.128 69.036 ;
     RECT  17.736 69.036 17.808 69.072 ;
     RECT  17.832 69.036 17.904 69.072 ;
     RECT  17.928 69.036 18 69.072 ;
     RECT  18.024 69.036 18.096 69.072 ;
     RECT  18.12 69.036 18.192 69.072 ;
     RECT  18.216 69.036 18.288 69.072 ;
     RECT  18.312 69.036 18.384 69.072 ;
     RECT  18.408 69.036 18.48 69.072 ;
     RECT  18.504 69.036 18.576 69.072 ;
     RECT  18.6 69.036 18.672 69.072 ;
     RECT  18.696 69.036 18.768 69.072 ;
     RECT  18.792 69.036 18.864 69.072 ;
     RECT  18.888 69.036 18.96 69.072 ;
     RECT  18.984 69.036 19.056 69.072 ;
     RECT  19.08 69.036 19.152 69.072 ;
     RECT  19.176 69.036 19.248 69.072 ;
     RECT  19.272 69.036 19.344 69.072 ;
     RECT  19.368 69.036 19.44 69.072 ;
     RECT  19.464 69.036 19.536 69.072 ;
     RECT  19.56 69.036 19.632 69.072 ;
     RECT  19.656 69.036 19.728 69.072 ;
     RECT  19.752 69.036 19.824 69.072 ;
     RECT  19.848 69.036 19.92 69.072 ;
     RECT  19.944 69.036 20.016 69.072 ;
     RECT  20.04 69.036 20.112 69.072 ;
     RECT  20.136 69.036 20.208 69.072 ;
     RECT  20.232 69.036 20.304 69.072 ;
     RECT  20.328 69.036 20.4 69.072 ;
     RECT  20.424 69.036 20.496 69.072 ;
     RECT  20.52 69.036 20.592 69.072 ;
     RECT  20.616 69.036 20.688 69.072 ;
     RECT  20.712 69.036 20.784 69.072 ;
     RECT  20.808 69.036 20.88 69.072 ;
     RECT  20.904 69.036 20.976 69.072 ;
     RECT  21 69.036 21.072 69.072 ;
     RECT  21.096 69.036 21.168 69.072 ;
     RECT  21.192 69.036 21.264 69.072 ;
     RECT  21.288 69.036 21.36 69.072 ;
     RECT  21.384 69.036 21.456 69.072 ;
     RECT  21.48 69.036 21.552 69.072 ;
     RECT  21.576 69.036 21.648 69.072 ;
     RECT  21.672 69.036 21.744 69.072 ;
     RECT  21.768 69.036 21.84 69.072 ;
     RECT  21.864 69.036 21.936 69.072 ;
     RECT  21.96 69.036 22.032 69.072 ;
     RECT  22.056 69.036 22.128 69.072 ;
     RECT  22.152 69.036 22.224 69.072 ;
     RECT  22.248 69.036 22.32 69.072 ;
     RECT  22.344 69.036 22.416 69.072 ;
     RECT  22.44 69.036 22.512 69.072 ;
     RECT  22.536 69.036 22.608 69.072 ;
     RECT  22.632 69.036 22.704 69.072 ;
     RECT  22.728 69.036 22.8 69.072 ;
     RECT  22.824 69.036 22.896 69.072 ;
     RECT  22.92 69.036 22.992 69.072 ;
     RECT  23.016 69.036 23.088 69.072 ;
     RECT  23.112 69.036 23.184 69.072 ;
     RECT  23.208 69.036 23.28 69.072 ;
     RECT  23.304 69.036 23.376 69.072 ;
     RECT  23.4 69.036 23.472 69.072 ;
     RECT  23.496 69.036 23.568 69.072 ;
     RECT  23.592 69.036 23.664 69.072 ;
     RECT  23.688 69.036 23.76 69.072 ;
     RECT  23.784 69.036 23.856 69.072 ;
     RECT  23.88 69.036 23.952 69.072 ;
     RECT  23.976 69.036 24.048 69.072 ;
     RECT  24.072 69.036 24.144 69.072 ;
     RECT  24.168 69.036 24.24 69.072 ;
     RECT  24.264 69.036 24.336 69.072 ;
     RECT  24.36 69.036 24.432 69.072 ;
     RECT  24.456 69.036 24.528 69.072 ;
     RECT  24.552 69.036 24.624 69.072 ;
     RECT  24.648 69.036 24.72 69.072 ;
     RECT  24.744 69.036 24.816 69.072 ;
     RECT  24.84 69.036 24.912 69.072 ;
     RECT  24.936 69.036 25.008 69.072 ;
     RECT  25.032 69.036 25.104 69.072 ;
     RECT  25.128 69.036 25.2 69.072 ;
     RECT  25.224 69.036 25.296 69.072 ;
     RECT  25.32 69.036 25.392 69.072 ;
     RECT  25.416 69.036 25.488 69.072 ;
     RECT  25.512 69.036 25.584 69.072 ;
     RECT  25.608 69.036 25.68 69.072 ;
     RECT  25.704 69.036 25.776 69.072 ;
     RECT  25.8 69.036 25.872 69.072 ;
     RECT  25.896 69.036 25.968 69.072 ;
     RECT  25.992 69.036 26.064 69.072 ;
     RECT  26.088 69.036 26.16 69.072 ;
     RECT  26.184 69.036 26.256 69.072 ;
     RECT  26.28 69.036 26.352 69.072 ;
     RECT  26.376 69.036 26.448 69.072 ;
     RECT  26.472 69.036 26.544 69.072 ;
     RECT  26.568 69.036 26.64 69.072 ;
     RECT  26.664 69.036 26.736 69.072 ;
     RECT  26.76 69.036 26.832 69.072 ;
     RECT  26.856 69.036 26.928 69.072 ;
     RECT  26.952 69.036 27.024 69.072 ;
     RECT  27.048 69.036 27.12 69.072 ;
     RECT  27.144 69.036 27.216 69.072 ;
     RECT  27.24 69.036 27.312 69.072 ;
     RECT  27.336 69.036 27.408 69.072 ;
     RECT  27.432 69.036 27.504 69.072 ;
     RECT  27.528 69.036 27.6 69.072 ;
     RECT  27.624 69.036 27.696 69.072 ;
     RECT  27.72 69.036 27.792 69.072 ;
     RECT  27.816 69.036 27.888 69.072 ;
     RECT  27.912 69.036 27.984 69.072 ;
     RECT  28.008 69.036 28.08 69.072 ;
     RECT  28.104 69.036 28.176 69.072 ;
     RECT  28.2 69.036 28.272 69.072 ;
     RECT  28.296 69.036 28.368 69.072 ;
     RECT  28.392 69.036 28.464 69.072 ;
     RECT  28.488 69.036 28.56 69.072 ;
     RECT  28.584 69.036 28.656 69.072 ;
     RECT  28.68 69.036 28.752 69.072 ;
     RECT  28.776 69.036 28.848 69.072 ;
     RECT  28.872 69.036 28.944 69.072 ;
     RECT  28.968 69.036 29.04 69.072 ;
     RECT  29.064 69.036 29.136 69.072 ;
     RECT  29.16 69.036 29.232 69.072 ;
     RECT  29.256 69.036 29.328 69.072 ;
     RECT  29.352 69.036 29.424 69.072 ;
     RECT  29.448 69.036 29.52 69.072 ;
     RECT  29.544 69.036 29.616 69.072 ;
     RECT  29.64 69.036 29.712 69.072 ;
     RECT  29.736 69.036 29.808 69.072 ;
     RECT  29.832 69.036 29.904 69.072 ;
     RECT  29.928 69.036 30.576 69.072 ;
     RECT  30.6 69.036 30.672 69.072 ;
     RECT  30.696 69.036 30.768 69.072 ;
     RECT  30.792 69.036 30.864 69.072 ;
     RECT  30.888 69.036 30.96 69.072 ;
     RECT  30.984 69.036 31.056 69.072 ;
     RECT  31.08 69.036 31.152 69.072 ;
     RECT  31.176 69.036 31.248 69.072 ;
     RECT  31.272 69.036 31.344 69.072 ;
     RECT  31.368 69.036 31.44 69.072 ;
     RECT  31.464 69.036 31.536 69.072 ;
     RECT  31.56 69.036 31.632 69.072 ;
     RECT  31.656 69.036 31.728 69.072 ;
     RECT  31.752 69.036 31.824 69.072 ;
     RECT  31.848 69.036 31.92 69.072 ;
     RECT  31.944 69.036 32.016 69.072 ;
     RECT  32.04 69.036 32.112 69.072 ;
     RECT  32.136 69.036 32.208 69.072 ;
     RECT  32.232 69.036 32.304 69.072 ;
     RECT  32.328 69.036 32.4 69.072 ;
     RECT  32.424 69.036 32.496 69.072 ;
     RECT  32.52 69.036 32.592 69.072 ;
     RECT  32.616 69.036 32.688 69.072 ;
     RECT  32.712 69.036 32.784 69.072 ;
     RECT  32.808 69.036 32.88 69.072 ;
     RECT  32.904 69.036 32.976 69.072 ;
     RECT  33 69.036 33.072 69.072 ;
     RECT  33.096 69.036 33.168 69.072 ;
     RECT  33.192 69.036 33.264 69.072 ;
     RECT  33.288 69.036 33.36 69.072 ;
     RECT  33.384 69.036 33.456 69.072 ;
     RECT  33.48 69.036 33.552 69.072 ;
     RECT  33.576 69.036 33.648 69.072 ;
     RECT  33.672 69.036 33.744 69.072 ;
     RECT  33.768 69.036 33.84 69.072 ;
     RECT  33.864 69.036 33.936 69.072 ;
     RECT  33.96 69.036 34.032 69.072 ;
     RECT  34.056 69.036 34.128 69.072 ;
     RECT  34.152 69.036 34.224 69.072 ;
     RECT  34.248 69.036 34.32 69.072 ;
     RECT  34.344 69.036 34.416 69.072 ;
     RECT  34.44 69.036 34.512 69.072 ;
     RECT  34.536 69.036 34.608 69.072 ;
     RECT  34.632 69.036 34.704 69.072 ;
     RECT  34.728 69.036 34.8 69.072 ;
     RECT  34.824 69.036 34.896 69.072 ;
     RECT  34.92 69.036 34.992 69.072 ;
     RECT  35.016 69.036 35.088 69.072 ;
     RECT  35.112 69.036 35.184 69.072 ;
     RECT  35.208 69.036 35.28 69.072 ;
     RECT  35.304 69.036 35.376 69.072 ;
     RECT  35.4 69.036 35.472 69.072 ;
     RECT  35.496 69.036 35.568 69.072 ;
     RECT  35.592 69.036 35.664 69.072 ;
     RECT  35.688 69.036 35.76 69.072 ;
     RECT  35.784 69.036 35.856 69.072 ;
     RECT  35.88 69.036 35.952 69.072 ;
     RECT  35.976 69.036 36.048 69.072 ;
     RECT  36.072 69.036 36.144 69.072 ;
     RECT  36.168 69.036 36.24 69.072 ;
     RECT  36.264 69.036 36.336 69.072 ;
     RECT  36.36 69.036 36.432 69.072 ;
     RECT  36.456 69.036 36.528 69.072 ;
     RECT  36.552 69.036 36.624 69.072 ;
     RECT  36.648 69.036 36.72 69.072 ;
     RECT  36.744 69.036 36.816 69.072 ;
     RECT  36.84 69.036 36.912 69.072 ;
     RECT  36.936 69.036 37.008 69.072 ;
     RECT  37.032 69.036 37.104 69.072 ;
     RECT  37.128 69.036 37.2 69.072 ;
     RECT  37.224 69.036 37.296 69.072 ;
     RECT  37.32 69.036 37.392 69.072 ;
     RECT  37.416 69.036 37.488 69.072 ;
     RECT  37.512 69.036 37.584 69.072 ;
     RECT  37.608 69.036 37.68 69.072 ;
     RECT  37.704 69.036 37.776 69.072 ;
     RECT  37.8 69.036 37.872 69.072 ;
     RECT  37.896 69.036 37.968 69.072 ;
     RECT  37.992 69.036 38.064 69.072 ;
     RECT  38.088 69.036 38.16 69.072 ;
     RECT  38.184 69.036 38.256 69.072 ;
     RECT  38.28 69.036 38.352 69.072 ;
     RECT  38.376 69.036 38.448 69.072 ;
     RECT  38.472 69.036 38.544 69.072 ;
     RECT  38.568 69.036 38.64 69.072 ;
     RECT  38.664 69.036 38.736 69.072 ;
     RECT  38.76 69.036 38.832 69.072 ;
     RECT  38.856 69.036 38.928 69.072 ;
     RECT  38.952 69.036 39.024 69.072 ;
     RECT  39.048 69.036 39.12 69.072 ;
     RECT  39.144 69.036 39.216 69.072 ;
     RECT  39.24 69.036 39.312 69.072 ;
     RECT  39.336 69.036 39.408 69.072 ;
     RECT  39.432 69.036 39.504 69.072 ;
     RECT  39.528 69.036 39.6 69.072 ;
     RECT  39.624 69.036 39.696 69.072 ;
     RECT  39.72 69.036 39.792 69.072 ;
     RECT  39.816 69.036 39.888 69.072 ;
     RECT  39.912 69.036 39.984 69.072 ;
     RECT  40.008 69.036 40.08 69.072 ;
     RECT  40.104 69.036 40.176 69.072 ;
     RECT  40.2 69.036 40.272 69.072 ;
     RECT  40.296 69.036 40.368 69.072 ;
     RECT  40.392 69.036 40.464 69.072 ;
     RECT  40.488 69.036 40.56 69.072 ;
     RECT  40.584 69.036 40.656 69.072 ;
     RECT  40.68 69.036 40.752 69.072 ;
     RECT  40.776 69.036 40.848 69.072 ;
     RECT  40.872 69.036 40.944 69.072 ;
     RECT  40.968 69.036 41.04 69.072 ;
     RECT  41.064 69.036 41.136 69.072 ;
     RECT  41.16 69.036 41.232 69.072 ;
     RECT  41.256 69.036 41.328 69.072 ;
     RECT  41.352 69.036 41.424 69.072 ;
     RECT  41.448 69.036 41.52 69.072 ;
     RECT  41.544 69.036 41.616 69.072 ;
     RECT  41.64 69.036 41.712 69.072 ;
     RECT  41.736 69.036 41.808 69.072 ;
     RECT  41.832 69.036 41.904 69.072 ;
     RECT  41.928 69.036 42 69.072 ;
     RECT  42.024 69.036 42.096 69.072 ;
     RECT  42.12 69.036 42.192 69.072 ;
     RECT  42.216 69.036 42.288 69.072 ;
     RECT  42.312 69.036 42.384 69.072 ;
     RECT  42.408 69.036 42.48 69.072 ;
     RECT  42.504 69.036 42.576 69.072 ;
     RECT  42.6 69.036 42.672 69.072 ;
     RECT  42.696 69.036 42.768 69.072 ;
     RECT  42.792 69.036 42.864 69.072 ;
     RECT  42.888 69.036 42.96 69.072 ;
     RECT  42.984 69.036 43.056 69.072 ;
     RECT  43.08 69.036 43.152 69.072 ;
     RECT  43.176 69.036 43.248 69.072 ;
     RECT  43.272 69.036 43.344 69.072 ;
     RECT  43.368 69.036 43.44 69.072 ;
     RECT  43.464 69.036 43.536 69.072 ;
     RECT  43.56 69.036 43.632 69.072 ;
     RECT  43.656 69.036 43.728 69.072 ;
     RECT  43.752 69.036 43.824 69.072 ;
     RECT  43.848 69.036 43.92 69.072 ;
     RECT  43.944 69.036 44.016 69.072 ;
     RECT  44.04 69.036 44.112 69.072 ;
     RECT  44.136 69.036 44.208 69.072 ;
     RECT  44.232 69.036 44.304 69.072 ;
     RECT  44.328 69.036 44.4 69.072 ;
     RECT  44.424 69.036 44.496 69.072 ;
     RECT  44.52 69.036 44.592 69.072 ;
     RECT  44.616 69.036 44.688 69.072 ;
     RECT  44.712 69.036 44.784 69.072 ;
     RECT  44.808 69.036 44.88 69.072 ;
     RECT  44.904 69.036 44.976 69.072 ;
     RECT  45 69.036 45.072 69.072 ;
     RECT  45.096 69.036 45.168 69.072 ;
     RECT  45.192 69.036 45.264 69.072 ;
     RECT  45.288 69.036 45.36 69.072 ;
     RECT  45.384 69.036 45.456 69.072 ;
     RECT  45.48 69.036 45.552 69.072 ;
     RECT  45.576 69.036 45.648 69.072 ;
     RECT  45.672 69.036 45.744 69.072 ;
     RECT  45.768 69.036 45.84 69.072 ;
     RECT  45.864 69.036 45.936 69.072 ;
     RECT  45.96 69.036 46.032 69.072 ;
     RECT  46.056 69.036 46.128 69.072 ;
     RECT  46.152 69.036 46.224 69.072 ;
     RECT  46.248 69.036 46.32 69.072 ;
     RECT  46.344 69.036 46.416 69.072 ;
     RECT  46.44 69.036 46.512 69.072 ;
     RECT  46.536 69.036 46.608 69.072 ;
     RECT  46.632 69.036 46.704 69.072 ;
     RECT  46.728 69.036 46.8 69.072 ;
     RECT  46.824 69.036 46.896 69.072 ;
     RECT  46.92 69.036 46.992 69.072 ;
     RECT  47.016 69.036 47.088 69.072 ;
     RECT  47.112 69.036 47.184 69.072 ;
     RECT  47.208 69.036 47.28 69.072 ;
     RECT  47.304 69.036 47.376 69.072 ;
     RECT  47.4 69.036 47.472 69.072 ;
     RECT  47.496 69.036 47.568 69.072 ;
     RECT  47.592 69.036 47.664 69.072 ;
     RECT  47.688 69.036 47.76 69.072 ;
     RECT  47.784 69.036 47.856 69.072 ;
     RECT  47.88 69.036 47.952 69.072 ;
     RECT  47.976 69.036 48.048 69.072 ;
     RECT  48.072 69.036 48.144 69.072 ;
     RECT  48.168 69.036 48.24 69.072 ;
     RECT  48.264 69.036 48.336 69.072 ;
     RECT  48.36 69.036 48.432 69.072 ;
     RECT  48.456 69.036 48.528 69.072 ;
     RECT  48.552 69.036 48.624 69.072 ;
     RECT  48.648 69.036 48.72 69.072 ;
     RECT  48.744 69.036 48.816 69.072 ;
     RECT  48.84 69.036 48.912 69.072 ;
     RECT  48.936 69.036 49.008 69.072 ;
     RECT  49.032 69.036 49.104 69.072 ;
     RECT  42.984 5.411 44.16 5.603 ;
     RECT  44.184 5.555 45.6 19.811 ;
     RECT  42.792 5.603 44.16 6.611 ;
     RECT  35.112 6.947 36.336 8.003 ;
     RECT  38.376 6.947 39.36 7.235 ;
     RECT  40.512 7.187 41.712 7.475 ;
     RECT  30.696 14.197 32.208 14.243 ;
     RECT  6.696 27.301 7.8 28.547 ;
     RECT  62.112 27.923 63.6 31.379 ;
     RECT  62.112 31.379 63.576 31.861 ;
     RECT  62.112 31.861 63.552 33.683 ;
     RECT  22.824 35.173 24 63.205 ;
     RECT  2.712 35.317 3.936 35.891 ;
     RECT  2.712 35.891 2.808 36.277 ;
     RECT  8.112 45.635 8.232 46.789 ;
     RECT  21.288 50.965 22.8 64.021 ;
     RECT  46.056 62.629 47.136 63.205 ;
     RECT  47.16 62.629 48.528 62.725 ;
     RECT  47.16 62.725 48.432 62.915 ;
     RECT  43.752 62.821 44.784 63.205 ;
     RECT  47.16 62.915 47.592 63.109 ;
     RECT  35.256 63.061 36.432 63.157 ;
     RECT  36.456 63.109 37.584 63.205 ;
     RECT  41.064 63.109 42.048 63.157 ;
     RECT  35.256 63.157 36.384 63.205 ;
     RECT  22.824 63.205 23.904 63.253 ;
     RECT  25.944 63.205 27.12 63.253 ;
     RECT  33.288 63.829 34.608 64.357 ;
     RECT  21.768 64.021 22.8 65.603 ;
     RECT  20.52 64.067 21.744 65.603 ;
     RECT  19.176 64.357 20.496 66.709 ;
     RECT  33.384 64.357 34.608 66.709 ;
     RECT  20.52 65.603 22.8 66.709 ;
     RECT  19.176 66.709 20.304 66.757 ;
  END
END ot_hbm_host_cfg_leaf_se
END LIBRARY
